VERSION 5.8 ;
BUSBITCHARS "[]" ;
DIVIDERCHAR "/" ;
UNITS
    DATABASE MICRONS 1000 ;
END UNITS

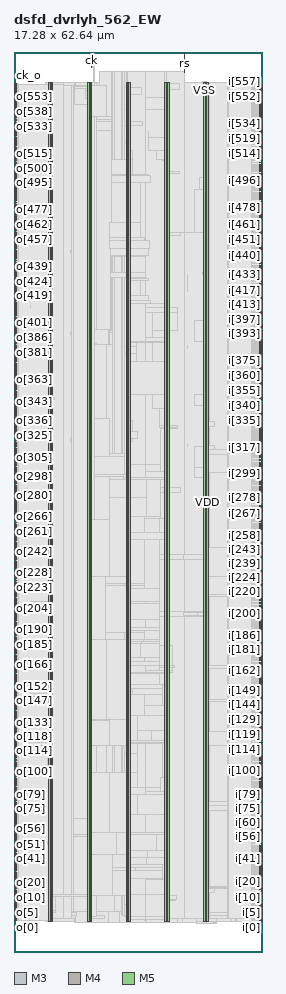
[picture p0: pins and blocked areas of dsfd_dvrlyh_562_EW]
MACRO dsfd_dvrlyh_562_EW
  FOREIGN dsfd_dvrlyh_562_EW 0 0 ;
  CLASS BLOCK ;
  SIZE 17.28 BY 62.64 ;
  PIN ck
    DIRECTION INPUT ;
    USE SIGNAL ;
    PORT
      LAYER M3 ;
        RECT  5.4 62.496 5.418 62.64 ;
    END
    PORT
      LAYER M3 ;
        RECT  5.4 61.579 5.418 62.508 ;
    END
  END ck
  PIN ck_o
    DIRECTION OUTPUT ;
    USE SIGNAL ;
    PORT
      LAYER M4 ;
        RECT  0 60.432 0.192 60.456 ;
    END
  END ck_o
  PIN i[0]
    DIRECTION INPUT ;
    USE SIGNAL ;
    PORT
      LAYER M4 ;
        RECT  17.088 2.208 17.28 2.232 ;
    END
  END i[0]
  PIN i[100]
    DIRECTION INPUT ;
    USE SIGNAL ;
    PORT
      LAYER M4 ;
        RECT  17.088 12.624 17.28 12.648 ;
    END
  END i[100]
  PIN i[101]
    DIRECTION INPUT ;
    USE SIGNAL ;
    PORT
      LAYER M4 ;
        RECT  17.088 12.72 17.28 12.744 ;
    END
  END i[101]
  PIN i[102]
    DIRECTION INPUT ;
    USE SIGNAL ;
    PORT
      LAYER M4 ;
        RECT  17.088 12.816 17.28 12.84 ;
    END
  END i[102]
  PIN i[103]
    DIRECTION INPUT ;
    USE SIGNAL ;
    PORT
      LAYER M4 ;
        RECT  17.088 12.912 17.28 12.936 ;
    END
  END i[103]
  PIN i[104]
    DIRECTION INPUT ;
    USE SIGNAL ;
    PORT
      LAYER M4 ;
        RECT  17.088 13.008 17.28 13.032 ;
    END
  END i[104]
  PIN i[105]
    DIRECTION INPUT ;
    USE SIGNAL ;
    PORT
      LAYER M4 ;
        RECT  17.088 13.104 17.28 13.128 ;
    END
  END i[105]
  PIN i[106]
    DIRECTION INPUT ;
    USE SIGNAL ;
    PORT
      LAYER M4 ;
        RECT  17.088 13.2 17.28 13.224 ;
    END
  END i[106]
  PIN i[107]
    DIRECTION INPUT ;
    USE SIGNAL ;
    PORT
      LAYER M4 ;
        RECT  17.088 13.344 17.28 13.368 ;
    END
  END i[107]
  PIN i[108]
    DIRECTION INPUT ;
    USE SIGNAL ;
    PORT
      LAYER M4 ;
        RECT  17.088 13.44 17.28 13.464 ;
    END
  END i[108]
  PIN i[109]
    DIRECTION INPUT ;
    USE SIGNAL ;
    PORT
      LAYER M4 ;
        RECT  17.088 13.536 17.28 13.56 ;
    END
  END i[109]
  PIN i[10]
    DIRECTION INPUT ;
    USE SIGNAL ;
    PORT
      LAYER M4 ;
        RECT  17.088 3.264 17.28 3.288 ;
    END
  END i[10]
  PIN i[110]
    DIRECTION INPUT ;
    USE SIGNAL ;
    PORT
      LAYER M4 ;
        RECT  17.088 13.632 17.28 13.656 ;
    END
  END i[110]
  PIN i[111]
    DIRECTION INPUT ;
    USE SIGNAL ;
    PORT
      LAYER M4 ;
        RECT  17.088 13.728 17.28 13.752 ;
    END
  END i[111]
  PIN i[112]
    DIRECTION INPUT ;
    USE SIGNAL ;
    PORT
      LAYER M4 ;
        RECT  17.088 13.824 17.28 13.848 ;
    END
  END i[112]
  PIN i[113]
    DIRECTION INPUT ;
    USE SIGNAL ;
    PORT
      LAYER M4 ;
        RECT  17.088 13.968 17.28 13.992 ;
    END
  END i[113]
  PIN i[114]
    DIRECTION INPUT ;
    USE SIGNAL ;
    PORT
      LAYER M4 ;
        RECT  17.088 14.064 17.28 14.088 ;
    END
  END i[114]
  PIN i[115]
    DIRECTION INPUT ;
    USE SIGNAL ;
    PORT
      LAYER M4 ;
        RECT  17.088 14.16 17.28 14.184 ;
    END
  END i[115]
  PIN i[116]
    DIRECTION INPUT ;
    USE SIGNAL ;
    PORT
      LAYER M4 ;
        RECT  17.088 14.256 17.28 14.28 ;
    END
  END i[116]
  PIN i[117]
    DIRECTION INPUT ;
    USE SIGNAL ;
    PORT
      LAYER M4 ;
        RECT  17.088 14.352 17.28 14.376 ;
    END
  END i[117]
  PIN i[118]
    DIRECTION INPUT ;
    USE SIGNAL ;
    PORT
      LAYER M4 ;
        RECT  17.088 14.448 17.28 14.472 ;
    END
  END i[118]
  PIN i[119]
    DIRECTION INPUT ;
    USE SIGNAL ;
    PORT
      LAYER M4 ;
        RECT  17.088 14.592 17.28 14.616 ;
    END
  END i[119]
  PIN i[11]
    DIRECTION INPUT ;
    USE SIGNAL ;
    PORT
      LAYER M4 ;
        RECT  17.088 3.36 17.28 3.384 ;
    END
  END i[11]
  PIN i[120]
    DIRECTION INPUT ;
    USE SIGNAL ;
    PORT
      LAYER M4 ;
        RECT  17.088 14.688 17.28 14.712 ;
    END
  END i[120]
  PIN i[121]
    DIRECTION INPUT ;
    USE SIGNAL ;
    PORT
      LAYER M4 ;
        RECT  17.088 14.784 17.28 14.808 ;
    END
  END i[121]
  PIN i[122]
    DIRECTION INPUT ;
    USE SIGNAL ;
    PORT
      LAYER M4 ;
        RECT  17.088 14.88 17.28 14.904 ;
    END
  END i[122]
  PIN i[123]
    DIRECTION INPUT ;
    USE SIGNAL ;
    PORT
      LAYER M4 ;
        RECT  17.088 14.976 17.28 15 ;
    END
  END i[123]
  PIN i[124]
    DIRECTION INPUT ;
    USE SIGNAL ;
    PORT
      LAYER M4 ;
        RECT  17.088 15.072 17.28 15.096 ;
    END
  END i[124]
  PIN i[125]
    DIRECTION INPUT ;
    USE SIGNAL ;
    PORT
      LAYER M4 ;
        RECT  17.088 15.216 17.28 15.24 ;
    END
  END i[125]
  PIN i[126]
    DIRECTION INPUT ;
    USE SIGNAL ;
    PORT
      LAYER M4 ;
        RECT  17.088 15.312 17.28 15.336 ;
    END
  END i[126]
  PIN i[127]
    DIRECTION INPUT ;
    USE SIGNAL ;
    PORT
      LAYER M4 ;
        RECT  17.088 15.408 17.28 15.432 ;
    END
  END i[127]
  PIN i[128]
    DIRECTION INPUT ;
    USE SIGNAL ;
    PORT
      LAYER M4 ;
        RECT  17.088 15.504 17.28 15.528 ;
    END
  END i[128]
  PIN i[129]
    DIRECTION INPUT ;
    USE SIGNAL ;
    PORT
      LAYER M4 ;
        RECT  17.088 15.6 17.28 15.624 ;
    END
  END i[129]
  PIN i[12]
    DIRECTION INPUT ;
    USE SIGNAL ;
    PORT
      LAYER M4 ;
        RECT  17.088 3.456 17.28 3.48 ;
    END
  END i[12]
  PIN i[130]
    DIRECTION INPUT ;
    USE SIGNAL ;
    PORT
      LAYER M4 ;
        RECT  17.088 15.696 17.28 15.72 ;
    END
  END i[130]
  PIN i[131]
    DIRECTION INPUT ;
    USE SIGNAL ;
    PORT
      LAYER M4 ;
        RECT  17.088 15.84 17.28 15.864 ;
    END
  END i[131]
  PIN i[132]
    DIRECTION INPUT ;
    USE SIGNAL ;
    PORT
      LAYER M4 ;
        RECT  17.088 15.936 17.28 15.96 ;
    END
  END i[132]
  PIN i[133]
    DIRECTION INPUT ;
    USE SIGNAL ;
    PORT
      LAYER M4 ;
        RECT  17.088 16.032 17.28 16.056 ;
    END
  END i[133]
  PIN i[134]
    DIRECTION INPUT ;
    USE SIGNAL ;
    PORT
      LAYER M4 ;
        RECT  17.088 16.128 17.28 16.152 ;
    END
  END i[134]
  PIN i[135]
    DIRECTION INPUT ;
    USE SIGNAL ;
    PORT
      LAYER M4 ;
        RECT  17.088 16.224 17.28 16.248 ;
    END
  END i[135]
  PIN i[136]
    DIRECTION INPUT ;
    USE SIGNAL ;
    PORT
      LAYER M4 ;
        RECT  17.088 16.32 17.28 16.344 ;
    END
  END i[136]
  PIN i[137]
    DIRECTION INPUT ;
    USE SIGNAL ;
    PORT
      LAYER M4 ;
        RECT  17.088 16.464 17.28 16.488 ;
    END
  END i[137]
  PIN i[138]
    DIRECTION INPUT ;
    USE SIGNAL ;
    PORT
      LAYER M4 ;
        RECT  17.088 16.56 17.28 16.584 ;
    END
  END i[138]
  PIN i[139]
    DIRECTION INPUT ;
    USE SIGNAL ;
    PORT
      LAYER M4 ;
        RECT  17.088 16.656 17.28 16.68 ;
    END
  END i[139]
  PIN i[13]
    DIRECTION INPUT ;
    USE SIGNAL ;
    PORT
      LAYER M4 ;
        RECT  17.088 3.552 17.28 3.576 ;
    END
  END i[13]
  PIN i[140]
    DIRECTION INPUT ;
    USE SIGNAL ;
    PORT
      LAYER M4 ;
        RECT  17.088 16.752 17.28 16.776 ;
    END
  END i[140]
  PIN i[141]
    DIRECTION INPUT ;
    USE SIGNAL ;
    PORT
      LAYER M4 ;
        RECT  17.088 16.848 17.28 16.872 ;
    END
  END i[141]
  PIN i[142]
    DIRECTION INPUT ;
    USE SIGNAL ;
    PORT
      LAYER M4 ;
        RECT  17.088 16.944 17.28 16.968 ;
    END
  END i[142]
  PIN i[143]
    DIRECTION INPUT ;
    USE SIGNAL ;
    PORT
      LAYER M4 ;
        RECT  17.088 17.04 17.28 17.064 ;
    END
  END i[143]
  PIN i[144]
    DIRECTION INPUT ;
    USE SIGNAL ;
    PORT
      LAYER M4 ;
        RECT  17.088 17.184 17.28 17.208 ;
    END
  END i[144]
  PIN i[145]
    DIRECTION INPUT ;
    USE SIGNAL ;
    PORT
      LAYER M4 ;
        RECT  17.088 17.28 17.28 17.304 ;
    END
  END i[145]
  PIN i[146]
    DIRECTION INPUT ;
    USE SIGNAL ;
    PORT
      LAYER M4 ;
        RECT  17.088 17.376 17.28 17.4 ;
    END
  END i[146]
  PIN i[147]
    DIRECTION INPUT ;
    USE SIGNAL ;
    PORT
      LAYER M4 ;
        RECT  17.088 17.472 17.28 17.496 ;
    END
  END i[147]
  PIN i[148]
    DIRECTION INPUT ;
    USE SIGNAL ;
    PORT
      LAYER M4 ;
        RECT  17.088 17.568 17.28 17.592 ;
    END
  END i[148]
  PIN i[149]
    DIRECTION INPUT ;
    USE SIGNAL ;
    PORT
      LAYER M4 ;
        RECT  17.088 17.664 17.28 17.688 ;
    END
  END i[149]
  PIN i[14]
    DIRECTION INPUT ;
    USE SIGNAL ;
    PORT
      LAYER M4 ;
        RECT  17.088 3.696 17.28 3.72 ;
    END
  END i[14]
  PIN i[150]
    DIRECTION INPUT ;
    USE SIGNAL ;
    PORT
      LAYER M4 ;
        RECT  17.088 17.808 17.28 17.832 ;
    END
  END i[150]
  PIN i[151]
    DIRECTION INPUT ;
    USE SIGNAL ;
    PORT
      LAYER M4 ;
        RECT  17.088 17.904 17.28 17.928 ;
    END
  END i[151]
  PIN i[152]
    DIRECTION INPUT ;
    USE SIGNAL ;
    PORT
      LAYER M4 ;
        RECT  17.088 18 17.28 18.024 ;
    END
  END i[152]
  PIN i[153]
    DIRECTION INPUT ;
    USE SIGNAL ;
    PORT
      LAYER M4 ;
        RECT  17.088 18.096 17.28 18.12 ;
    END
  END i[153]
  PIN i[154]
    DIRECTION INPUT ;
    USE SIGNAL ;
    PORT
      LAYER M4 ;
        RECT  17.088 18.192 17.28 18.216 ;
    END
  END i[154]
  PIN i[155]
    DIRECTION INPUT ;
    USE SIGNAL ;
    PORT
      LAYER M4 ;
        RECT  17.088 18.288 17.28 18.312 ;
    END
  END i[155]
  PIN i[156]
    DIRECTION INPUT ;
    USE SIGNAL ;
    PORT
      LAYER M4 ;
        RECT  17.088 18.432 17.28 18.456 ;
    END
  END i[156]
  PIN i[157]
    DIRECTION INPUT ;
    USE SIGNAL ;
    PORT
      LAYER M4 ;
        RECT  17.088 18.528 17.28 18.552 ;
    END
  END i[157]
  PIN i[158]
    DIRECTION INPUT ;
    USE SIGNAL ;
    PORT
      LAYER M4 ;
        RECT  17.088 18.624 17.28 18.648 ;
    END
  END i[158]
  PIN i[159]
    DIRECTION INPUT ;
    USE SIGNAL ;
    PORT
      LAYER M4 ;
        RECT  17.088 18.72 17.28 18.744 ;
    END
  END i[159]
  PIN i[15]
    DIRECTION INPUT ;
    USE SIGNAL ;
    PORT
      LAYER M4 ;
        RECT  17.088 3.792 17.28 3.816 ;
    END
  END i[15]
  PIN i[160]
    DIRECTION INPUT ;
    USE SIGNAL ;
    PORT
      LAYER M4 ;
        RECT  17.088 18.816 17.28 18.84 ;
    END
  END i[160]
  PIN i[161]
    DIRECTION INPUT ;
    USE SIGNAL ;
    PORT
      LAYER M4 ;
        RECT  17.088 18.912 17.28 18.936 ;
    END
  END i[161]
  PIN i[162]
    DIRECTION INPUT ;
    USE SIGNAL ;
    PORT
      LAYER M4 ;
        RECT  17.088 19.056 17.28 19.08 ;
    END
  END i[162]
  PIN i[163]
    DIRECTION INPUT ;
    USE SIGNAL ;
    PORT
      LAYER M4 ;
        RECT  17.088 19.152 17.28 19.176 ;
    END
  END i[163]
  PIN i[164]
    DIRECTION INPUT ;
    USE SIGNAL ;
    PORT
      LAYER M4 ;
        RECT  17.088 19.248 17.28 19.272 ;
    END
  END i[164]
  PIN i[165]
    DIRECTION INPUT ;
    USE SIGNAL ;
    PORT
      LAYER M4 ;
        RECT  17.088 19.344 17.28 19.368 ;
    END
  END i[165]
  PIN i[166]
    DIRECTION INPUT ;
    USE SIGNAL ;
    PORT
      LAYER M4 ;
        RECT  17.088 19.44 17.28 19.464 ;
    END
  END i[166]
  PIN i[167]
    DIRECTION INPUT ;
    USE SIGNAL ;
    PORT
      LAYER M4 ;
        RECT  17.088 19.536 17.28 19.56 ;
    END
  END i[167]
  PIN i[168]
    DIRECTION INPUT ;
    USE SIGNAL ;
    PORT
      LAYER M4 ;
        RECT  17.088 19.68 17.28 19.704 ;
    END
  END i[168]
  PIN i[169]
    DIRECTION INPUT ;
    USE SIGNAL ;
    PORT
      LAYER M4 ;
        RECT  17.088 19.776 17.28 19.8 ;
    END
  END i[169]
  PIN i[16]
    DIRECTION INPUT ;
    USE SIGNAL ;
    PORT
      LAYER M4 ;
        RECT  17.088 3.888 17.28 3.912 ;
    END
  END i[16]
  PIN i[170]
    DIRECTION INPUT ;
    USE SIGNAL ;
    PORT
      LAYER M4 ;
        RECT  17.088 19.872 17.28 19.896 ;
    END
  END i[170]
  PIN i[171]
    DIRECTION INPUT ;
    USE SIGNAL ;
    PORT
      LAYER M4 ;
        RECT  17.088 19.968 17.28 19.992 ;
    END
  END i[171]
  PIN i[172]
    DIRECTION INPUT ;
    USE SIGNAL ;
    PORT
      LAYER M4 ;
        RECT  17.088 20.064 17.28 20.088 ;
    END
  END i[172]
  PIN i[173]
    DIRECTION INPUT ;
    USE SIGNAL ;
    PORT
      LAYER M4 ;
        RECT  17.088 20.16 17.28 20.184 ;
    END
  END i[173]
  PIN i[174]
    DIRECTION INPUT ;
    USE SIGNAL ;
    PORT
      LAYER M4 ;
        RECT  17.088 20.304 17.28 20.328 ;
    END
  END i[174]
  PIN i[175]
    DIRECTION INPUT ;
    USE SIGNAL ;
    PORT
      LAYER M4 ;
        RECT  17.088 20.4 17.28 20.424 ;
    END
  END i[175]
  PIN i[176]
    DIRECTION INPUT ;
    USE SIGNAL ;
    PORT
      LAYER M4 ;
        RECT  17.088 20.496 17.28 20.52 ;
    END
  END i[176]
  PIN i[177]
    DIRECTION INPUT ;
    USE SIGNAL ;
    PORT
      LAYER M4 ;
        RECT  17.088 20.592 17.28 20.616 ;
    END
  END i[177]
  PIN i[178]
    DIRECTION INPUT ;
    USE SIGNAL ;
    PORT
      LAYER M4 ;
        RECT  17.088 20.688 17.28 20.712 ;
    END
  END i[178]
  PIN i[179]
    DIRECTION INPUT ;
    USE SIGNAL ;
    PORT
      LAYER M4 ;
        RECT  17.088 20.784 17.28 20.808 ;
    END
  END i[179]
  PIN i[17]
    DIRECTION INPUT ;
    USE SIGNAL ;
    PORT
      LAYER M4 ;
        RECT  17.088 3.984 17.28 4.008 ;
    END
  END i[17]
  PIN i[180]
    DIRECTION INPUT ;
    USE SIGNAL ;
    PORT
      LAYER M4 ;
        RECT  17.088 20.88 17.28 20.904 ;
    END
  END i[180]
  PIN i[181]
    DIRECTION INPUT ;
    USE SIGNAL ;
    PORT
      LAYER M4 ;
        RECT  17.088 21.024 17.28 21.048 ;
    END
  END i[181]
  PIN i[182]
    DIRECTION INPUT ;
    USE SIGNAL ;
    PORT
      LAYER M4 ;
        RECT  17.088 21.12 17.28 21.144 ;
    END
  END i[182]
  PIN i[183]
    DIRECTION INPUT ;
    USE SIGNAL ;
    PORT
      LAYER M4 ;
        RECT  17.088 21.216 17.28 21.24 ;
    END
  END i[183]
  PIN i[184]
    DIRECTION INPUT ;
    USE SIGNAL ;
    PORT
      LAYER M4 ;
        RECT  17.088 21.312 17.28 21.336 ;
    END
  END i[184]
  PIN i[185]
    DIRECTION INPUT ;
    USE SIGNAL ;
    PORT
      LAYER M4 ;
        RECT  17.088 21.408 17.28 21.432 ;
    END
  END i[185]
  PIN i[186]
    DIRECTION INPUT ;
    USE SIGNAL ;
    PORT
      LAYER M4 ;
        RECT  17.088 21.504 17.28 21.528 ;
    END
  END i[186]
  PIN i[187]
    DIRECTION INPUT ;
    USE SIGNAL ;
    PORT
      LAYER M4 ;
        RECT  17.088 21.648 17.28 21.672 ;
    END
  END i[187]
  PIN i[188]
    DIRECTION INPUT ;
    USE SIGNAL ;
    PORT
      LAYER M4 ;
        RECT  17.088 21.744 17.28 21.768 ;
    END
  END i[188]
  PIN i[189]
    DIRECTION INPUT ;
    USE SIGNAL ;
    PORT
      LAYER M4 ;
        RECT  17.088 21.84 17.28 21.864 ;
    END
  END i[189]
  PIN i[18]
    DIRECTION INPUT ;
    USE SIGNAL ;
    PORT
      LAYER M4 ;
        RECT  17.088 4.08 17.28 4.104 ;
    END
  END i[18]
  PIN i[190]
    DIRECTION INPUT ;
    USE SIGNAL ;
    PORT
      LAYER M4 ;
        RECT  17.088 21.936 17.28 21.96 ;
    END
  END i[190]
  PIN i[191]
    DIRECTION INPUT ;
    USE SIGNAL ;
    PORT
      LAYER M4 ;
        RECT  17.088 22.032 17.28 22.056 ;
    END
  END i[191]
  PIN i[192]
    DIRECTION INPUT ;
    USE SIGNAL ;
    PORT
      LAYER M4 ;
        RECT  17.088 22.128 17.28 22.152 ;
    END
  END i[192]
  PIN i[193]
    DIRECTION INPUT ;
    USE SIGNAL ;
    PORT
      LAYER M4 ;
        RECT  17.088 22.272 17.28 22.296 ;
    END
  END i[193]
  PIN i[194]
    DIRECTION INPUT ;
    USE SIGNAL ;
    PORT
      LAYER M4 ;
        RECT  17.088 22.368 17.28 22.392 ;
    END
  END i[194]
  PIN i[195]
    DIRECTION INPUT ;
    USE SIGNAL ;
    PORT
      LAYER M4 ;
        RECT  17.088 22.464 17.28 22.488 ;
    END
  END i[195]
  PIN i[196]
    DIRECTION INPUT ;
    USE SIGNAL ;
    PORT
      LAYER M4 ;
        RECT  17.088 22.56 17.28 22.584 ;
    END
  END i[196]
  PIN i[197]
    DIRECTION INPUT ;
    USE SIGNAL ;
    PORT
      LAYER M4 ;
        RECT  17.088 22.656 17.28 22.68 ;
    END
  END i[197]
  PIN i[198]
    DIRECTION INPUT ;
    USE SIGNAL ;
    PORT
      LAYER M4 ;
        RECT  17.088 22.752 17.28 22.776 ;
    END
  END i[198]
  PIN i[199]
    DIRECTION INPUT ;
    USE SIGNAL ;
    PORT
      LAYER M4 ;
        RECT  17.088 22.896 17.28 22.92 ;
    END
  END i[199]
  PIN i[19]
    DIRECTION INPUT ;
    USE SIGNAL ;
    PORT
      LAYER M4 ;
        RECT  17.088 4.176 17.28 4.2 ;
    END
  END i[19]
  PIN i[1]
    DIRECTION INPUT ;
    USE SIGNAL ;
    PORT
      LAYER M4 ;
        RECT  17.088 2.304 17.28 2.328 ;
    END
  END i[1]
  PIN i[200]
    DIRECTION INPUT ;
    USE SIGNAL ;
    PORT
      LAYER M4 ;
        RECT  17.088 22.992 17.28 23.016 ;
    END
  END i[200]
  PIN i[201]
    DIRECTION INPUT ;
    USE SIGNAL ;
    PORT
      LAYER M4 ;
        RECT  17.088 23.088 17.28 23.112 ;
    END
  END i[201]
  PIN i[202]
    DIRECTION INPUT ;
    USE SIGNAL ;
    PORT
      LAYER M4 ;
        RECT  17.088 23.184 17.28 23.208 ;
    END
  END i[202]
  PIN i[203]
    DIRECTION INPUT ;
    USE SIGNAL ;
    PORT
      LAYER M4 ;
        RECT  17.088 23.28 17.28 23.304 ;
    END
  END i[203]
  PIN i[204]
    DIRECTION INPUT ;
    USE SIGNAL ;
    PORT
      LAYER M4 ;
        RECT  17.088 23.376 17.28 23.4 ;
    END
  END i[204]
  PIN i[205]
    DIRECTION INPUT ;
    USE SIGNAL ;
    PORT
      LAYER M4 ;
        RECT  17.088 23.52 17.28 23.544 ;
    END
  END i[205]
  PIN i[206]
    DIRECTION INPUT ;
    USE SIGNAL ;
    PORT
      LAYER M4 ;
        RECT  17.088 23.616 17.28 23.64 ;
    END
  END i[206]
  PIN i[207]
    DIRECTION INPUT ;
    USE SIGNAL ;
    PORT
      LAYER M4 ;
        RECT  17.088 23.712 17.28 23.736 ;
    END
  END i[207]
  PIN i[208]
    DIRECTION INPUT ;
    USE SIGNAL ;
    PORT
      LAYER M4 ;
        RECT  17.088 23.808 17.28 23.832 ;
    END
  END i[208]
  PIN i[209]
    DIRECTION INPUT ;
    USE SIGNAL ;
    PORT
      LAYER M4 ;
        RECT  17.088 23.904 17.28 23.928 ;
    END
  END i[209]
  PIN i[20]
    DIRECTION INPUT ;
    USE SIGNAL ;
    PORT
      LAYER M4 ;
        RECT  17.088 4.32 17.28 4.344 ;
    END
  END i[20]
  PIN i[210]
    DIRECTION INPUT ;
    USE SIGNAL ;
    PORT
      LAYER M4 ;
        RECT  17.088 24 17.28 24.024 ;
    END
  END i[210]
  PIN i[211]
    DIRECTION INPUT ;
    USE SIGNAL ;
    PORT
      LAYER M4 ;
        RECT  17.088 24.096 17.28 24.12 ;
    END
  END i[211]
  PIN i[212]
    DIRECTION INPUT ;
    USE SIGNAL ;
    PORT
      LAYER M4 ;
        RECT  17.088 24.24 17.28 24.264 ;
    END
  END i[212]
  PIN i[213]
    DIRECTION INPUT ;
    USE SIGNAL ;
    PORT
      LAYER M4 ;
        RECT  17.088 24.336 17.28 24.36 ;
    END
  END i[213]
  PIN i[214]
    DIRECTION INPUT ;
    USE SIGNAL ;
    PORT
      LAYER M4 ;
        RECT  17.088 24.432 17.28 24.456 ;
    END
  END i[214]
  PIN i[215]
    DIRECTION INPUT ;
    USE SIGNAL ;
    PORT
      LAYER M4 ;
        RECT  17.088 24.528 17.28 24.552 ;
    END
  END i[215]
  PIN i[216]
    DIRECTION INPUT ;
    USE SIGNAL ;
    PORT
      LAYER M4 ;
        RECT  17.088 24.624 17.28 24.648 ;
    END
  END i[216]
  PIN i[217]
    DIRECTION INPUT ;
    USE SIGNAL ;
    PORT
      LAYER M4 ;
        RECT  17.088 24.72 17.28 24.744 ;
    END
  END i[217]
  PIN i[218]
    DIRECTION INPUT ;
    USE SIGNAL ;
    PORT
      LAYER M4 ;
        RECT  17.088 24.864 17.28 24.888 ;
    END
  END i[218]
  PIN i[219]
    DIRECTION INPUT ;
    USE SIGNAL ;
    PORT
      LAYER M4 ;
        RECT  17.088 24.96 17.28 24.984 ;
    END
  END i[219]
  PIN i[21]
    DIRECTION INPUT ;
    USE SIGNAL ;
    PORT
      LAYER M4 ;
        RECT  17.088 4.416 17.28 4.44 ;
    END
  END i[21]
  PIN i[220]
    DIRECTION INPUT ;
    USE SIGNAL ;
    PORT
      LAYER M4 ;
        RECT  17.088 25.056 17.28 25.08 ;
    END
  END i[220]
  PIN i[221]
    DIRECTION INPUT ;
    USE SIGNAL ;
    PORT
      LAYER M4 ;
        RECT  17.088 25.152 17.28 25.176 ;
    END
  END i[221]
  PIN i[222]
    DIRECTION INPUT ;
    USE SIGNAL ;
    PORT
      LAYER M4 ;
        RECT  17.088 25.248 17.28 25.272 ;
    END
  END i[222]
  PIN i[223]
    DIRECTION INPUT ;
    USE SIGNAL ;
    PORT
      LAYER M4 ;
        RECT  17.088 25.344 17.28 25.368 ;
    END
  END i[223]
  PIN i[224]
    DIRECTION INPUT ;
    USE SIGNAL ;
    PORT
      LAYER M4 ;
        RECT  17.088 25.488 17.28 25.512 ;
    END
  END i[224]
  PIN i[225]
    DIRECTION INPUT ;
    USE SIGNAL ;
    PORT
      LAYER M4 ;
        RECT  17.088 25.584 17.28 25.608 ;
    END
  END i[225]
  PIN i[226]
    DIRECTION INPUT ;
    USE SIGNAL ;
    PORT
      LAYER M4 ;
        RECT  17.088 25.68 17.28 25.704 ;
    END
  END i[226]
  PIN i[227]
    DIRECTION INPUT ;
    USE SIGNAL ;
    PORT
      LAYER M4 ;
        RECT  17.088 25.776 17.28 25.8 ;
    END
  END i[227]
  PIN i[228]
    DIRECTION INPUT ;
    USE SIGNAL ;
    PORT
      LAYER M4 ;
        RECT  17.088 25.872 17.28 25.896 ;
    END
  END i[228]
  PIN i[229]
    DIRECTION INPUT ;
    USE SIGNAL ;
    PORT
      LAYER M4 ;
        RECT  17.088 25.968 17.28 25.992 ;
    END
  END i[229]
  PIN i[22]
    DIRECTION INPUT ;
    USE SIGNAL ;
    PORT
      LAYER M4 ;
        RECT  17.088 4.512 17.28 4.536 ;
    END
  END i[22]
  PIN i[230]
    DIRECTION INPUT ;
    USE SIGNAL ;
    PORT
      LAYER M4 ;
        RECT  17.088 26.112 17.28 26.136 ;
    END
  END i[230]
  PIN i[231]
    DIRECTION INPUT ;
    USE SIGNAL ;
    PORT
      LAYER M4 ;
        RECT  17.088 26.208 17.28 26.232 ;
    END
  END i[231]
  PIN i[232]
    DIRECTION INPUT ;
    USE SIGNAL ;
    PORT
      LAYER M4 ;
        RECT  17.088 26.304 17.28 26.328 ;
    END
  END i[232]
  PIN i[233]
    DIRECTION INPUT ;
    USE SIGNAL ;
    PORT
      LAYER M4 ;
        RECT  17.088 26.4 17.28 26.424 ;
    END
  END i[233]
  PIN i[234]
    DIRECTION INPUT ;
    USE SIGNAL ;
    PORT
      LAYER M4 ;
        RECT  17.088 26.496 17.28 26.52 ;
    END
  END i[234]
  PIN i[235]
    DIRECTION INPUT ;
    USE SIGNAL ;
    PORT
      LAYER M4 ;
        RECT  17.088 26.592 17.28 26.616 ;
    END
  END i[235]
  PIN i[236]
    DIRECTION INPUT ;
    USE SIGNAL ;
    PORT
      LAYER M4 ;
        RECT  17.088 26.736 17.28 26.76 ;
    END
  END i[236]
  PIN i[237]
    DIRECTION INPUT ;
    USE SIGNAL ;
    PORT
      LAYER M4 ;
        RECT  17.088 26.832 17.28 26.856 ;
    END
  END i[237]
  PIN i[238]
    DIRECTION INPUT ;
    USE SIGNAL ;
    PORT
      LAYER M4 ;
        RECT  17.088 26.928 17.28 26.952 ;
    END
  END i[238]
  PIN i[239]
    DIRECTION INPUT ;
    USE SIGNAL ;
    PORT
      LAYER M4 ;
        RECT  17.088 27.024 17.28 27.048 ;
    END
  END i[239]
  PIN i[23]
    DIRECTION INPUT ;
    USE SIGNAL ;
    PORT
      LAYER M4 ;
        RECT  17.088 4.608 17.28 4.632 ;
    END
  END i[23]
  PIN i[240]
    DIRECTION INPUT ;
    USE SIGNAL ;
    PORT
      LAYER M4 ;
        RECT  17.088 27.12 17.28 27.144 ;
    END
  END i[240]
  PIN i[241]
    DIRECTION INPUT ;
    USE SIGNAL ;
    PORT
      LAYER M4 ;
        RECT  17.088 27.216 17.28 27.24 ;
    END
  END i[241]
  PIN i[242]
    DIRECTION INPUT ;
    USE SIGNAL ;
    PORT
      LAYER M4 ;
        RECT  17.088 27.36 17.28 27.384 ;
    END
  END i[242]
  PIN i[243]
    DIRECTION INPUT ;
    USE SIGNAL ;
    PORT
      LAYER M4 ;
        RECT  17.088 27.456 17.28 27.48 ;
    END
  END i[243]
  PIN i[244]
    DIRECTION INPUT ;
    USE SIGNAL ;
    PORT
      LAYER M4 ;
        RECT  17.088 27.552 17.28 27.576 ;
    END
  END i[244]
  PIN i[245]
    DIRECTION INPUT ;
    USE SIGNAL ;
    PORT
      LAYER M4 ;
        RECT  17.088 27.648 17.28 27.672 ;
    END
  END i[245]
  PIN i[246]
    DIRECTION INPUT ;
    USE SIGNAL ;
    PORT
      LAYER M4 ;
        RECT  17.088 27.744 17.28 27.768 ;
    END
  END i[246]
  PIN i[247]
    DIRECTION INPUT ;
    USE SIGNAL ;
    PORT
      LAYER M4 ;
        RECT  17.088 27.84 17.28 27.864 ;
    END
  END i[247]
  PIN i[248]
    DIRECTION INPUT ;
    USE SIGNAL ;
    PORT
      LAYER M4 ;
        RECT  17.088 27.936 17.28 27.96 ;
    END
  END i[248]
  PIN i[249]
    DIRECTION INPUT ;
    USE SIGNAL ;
    PORT
      LAYER M4 ;
        RECT  17.088 28.08 17.28 28.104 ;
    END
  END i[249]
  PIN i[24]
    DIRECTION INPUT ;
    USE SIGNAL ;
    PORT
      LAYER M4 ;
        RECT  17.088 4.704 17.28 4.728 ;
    END
  END i[24]
  PIN i[250]
    DIRECTION INPUT ;
    USE SIGNAL ;
    PORT
      LAYER M4 ;
        RECT  17.088 28.176 17.28 28.2 ;
    END
  END i[250]
  PIN i[251]
    DIRECTION INPUT ;
    USE SIGNAL ;
    PORT
      LAYER M4 ;
        RECT  17.088 28.272 17.28 28.296 ;
    END
  END i[251]
  PIN i[252]
    DIRECTION INPUT ;
    USE SIGNAL ;
    PORT
      LAYER M4 ;
        RECT  17.088 28.368 17.28 28.392 ;
    END
  END i[252]
  PIN i[253]
    DIRECTION INPUT ;
    USE SIGNAL ;
    PORT
      LAYER M4 ;
        RECT  17.088 28.464 17.28 28.488 ;
    END
  END i[253]
  PIN i[254]
    DIRECTION INPUT ;
    USE SIGNAL ;
    PORT
      LAYER M4 ;
        RECT  17.088 28.56 17.28 28.584 ;
    END
  END i[254]
  PIN i[255]
    DIRECTION INPUT ;
    USE SIGNAL ;
    PORT
      LAYER M4 ;
        RECT  17.088 28.704 17.28 28.728 ;
    END
  END i[255]
  PIN i[256]
    DIRECTION INPUT ;
    USE SIGNAL ;
    PORT
      LAYER M4 ;
        RECT  17.088 28.8 17.28 28.824 ;
    END
  END i[256]
  PIN i[257]
    DIRECTION INPUT ;
    USE SIGNAL ;
    PORT
      LAYER M4 ;
        RECT  17.088 28.896 17.28 28.92 ;
    END
  END i[257]
  PIN i[258]
    DIRECTION INPUT ;
    USE SIGNAL ;
    PORT
      LAYER M4 ;
        RECT  17.088 28.992 17.28 29.016 ;
    END
  END i[258]
  PIN i[259]
    DIRECTION INPUT ;
    USE SIGNAL ;
    PORT
      LAYER M4 ;
        RECT  17.088 29.088 17.28 29.112 ;
    END
  END i[259]
  PIN i[25]
    DIRECTION INPUT ;
    USE SIGNAL ;
    PORT
      LAYER M4 ;
        RECT  17.088 4.8 17.28 4.824 ;
    END
  END i[25]
  PIN i[260]
    DIRECTION INPUT ;
    USE SIGNAL ;
    PORT
      LAYER M4 ;
        RECT  17.088 29.184 17.28 29.208 ;
    END
  END i[260]
  PIN i[261]
    DIRECTION INPUT ;
    USE SIGNAL ;
    PORT
      LAYER M4 ;
        RECT  17.088 29.328 17.28 29.352 ;
    END
  END i[261]
  PIN i[262]
    DIRECTION INPUT ;
    USE SIGNAL ;
    PORT
      LAYER M4 ;
        RECT  17.088 29.424 17.28 29.448 ;
    END
  END i[262]
  PIN i[263]
    DIRECTION INPUT ;
    USE SIGNAL ;
    PORT
      LAYER M4 ;
        RECT  17.088 29.52 17.28 29.544 ;
    END
  END i[263]
  PIN i[264]
    DIRECTION INPUT ;
    USE SIGNAL ;
    PORT
      LAYER M4 ;
        RECT  17.088 29.616 17.28 29.64 ;
    END
  END i[264]
  PIN i[265]
    DIRECTION INPUT ;
    USE SIGNAL ;
    PORT
      LAYER M4 ;
        RECT  17.088 29.712 17.28 29.736 ;
    END
  END i[265]
  PIN i[266]
    DIRECTION INPUT ;
    USE SIGNAL ;
    PORT
      LAYER M4 ;
        RECT  17.088 29.808 17.28 29.832 ;
    END
  END i[266]
  PIN i[267]
    DIRECTION INPUT ;
    USE SIGNAL ;
    PORT
      LAYER M4 ;
        RECT  17.088 29.952 17.28 29.976 ;
    END
  END i[267]
  PIN i[268]
    DIRECTION INPUT ;
    USE SIGNAL ;
    PORT
      LAYER M4 ;
        RECT  17.088 30.048 17.28 30.072 ;
    END
  END i[268]
  PIN i[269]
    DIRECTION INPUT ;
    USE SIGNAL ;
    PORT
      LAYER M4 ;
        RECT  17.088 30.144 17.28 30.168 ;
    END
  END i[269]
  PIN i[26]
    DIRECTION INPUT ;
    USE SIGNAL ;
    PORT
      LAYER M4 ;
        RECT  17.088 4.944 17.28 4.968 ;
    END
  END i[26]
  PIN i[270]
    DIRECTION INPUT ;
    USE SIGNAL ;
    PORT
      LAYER M4 ;
        RECT  17.088 30.24 17.28 30.264 ;
    END
  END i[270]
  PIN i[271]
    DIRECTION INPUT ;
    USE SIGNAL ;
    PORT
      LAYER M4 ;
        RECT  17.088 30.336 17.28 30.36 ;
    END
  END i[271]
  PIN i[272]
    DIRECTION INPUT ;
    USE SIGNAL ;
    PORT
      LAYER M4 ;
        RECT  17.088 30.432 17.28 30.456 ;
    END
  END i[272]
  PIN i[273]
    DIRECTION INPUT ;
    USE SIGNAL ;
    PORT
      LAYER M4 ;
        RECT  17.088 30.576 17.28 30.6 ;
    END
  END i[273]
  PIN i[274]
    DIRECTION INPUT ;
    USE SIGNAL ;
    PORT
      LAYER M4 ;
        RECT  17.088 30.672 17.28 30.696 ;
    END
  END i[274]
  PIN i[275]
    DIRECTION INPUT ;
    USE SIGNAL ;
    PORT
      LAYER M4 ;
        RECT  17.088 30.768 17.28 30.792 ;
    END
  END i[275]
  PIN i[276]
    DIRECTION INPUT ;
    USE SIGNAL ;
    PORT
      LAYER M4 ;
        RECT  17.088 30.864 17.28 30.888 ;
    END
  END i[276]
  PIN i[277]
    DIRECTION INPUT ;
    USE SIGNAL ;
    PORT
      LAYER M4 ;
        RECT  17.088 30.96 17.28 30.984 ;
    END
  END i[277]
  PIN i[278]
    DIRECTION INPUT ;
    USE SIGNAL ;
    PORT
      LAYER M4 ;
        RECT  17.088 31.056 17.28 31.08 ;
    END
  END i[278]
  PIN i[279]
    DIRECTION INPUT ;
    USE SIGNAL ;
    PORT
      LAYER M4 ;
        RECT  17.088 31.2 17.28 31.224 ;
    END
  END i[279]
  PIN i[27]
    DIRECTION INPUT ;
    USE SIGNAL ;
    PORT
      LAYER M4 ;
        RECT  17.088 5.04 17.28 5.064 ;
    END
  END i[27]
  PIN i[280]
    DIRECTION INPUT ;
    USE SIGNAL ;
    PORT
      LAYER M4 ;
        RECT  17.088 31.296 17.28 31.32 ;
    END
  END i[280]
  PIN i[281]
    DIRECTION INPUT ;
    USE SIGNAL ;
    PORT
      LAYER M4 ;
        RECT  17.088 31.392 17.28 31.416 ;
    END
  END i[281]
  PIN i[282]
    DIRECTION INPUT ;
    USE SIGNAL ;
    PORT
      LAYER M4 ;
        RECT  17.088 31.488 17.28 31.512 ;
    END
  END i[282]
  PIN i[283]
    DIRECTION INPUT ;
    USE SIGNAL ;
    PORT
      LAYER M4 ;
        RECT  17.088 31.584 17.28 31.608 ;
    END
  END i[283]
  PIN i[284]
    DIRECTION INPUT ;
    USE SIGNAL ;
    PORT
      LAYER M4 ;
        RECT  17.088 31.68 17.28 31.704 ;
    END
  END i[284]
  PIN i[285]
    DIRECTION INPUT ;
    USE SIGNAL ;
    PORT
      LAYER M4 ;
        RECT  17.088 31.776 17.28 31.8 ;
    END
  END i[285]
  PIN i[286]
    DIRECTION INPUT ;
    USE SIGNAL ;
    PORT
      LAYER M4 ;
        RECT  17.088 31.92 17.28 31.944 ;
    END
  END i[286]
  PIN i[287]
    DIRECTION INPUT ;
    USE SIGNAL ;
    PORT
      LAYER M4 ;
        RECT  17.088 32.016 17.28 32.04 ;
    END
  END i[287]
  PIN i[288]
    DIRECTION INPUT ;
    USE SIGNAL ;
    PORT
      LAYER M4 ;
        RECT  17.088 32.112 17.28 32.136 ;
    END
  END i[288]
  PIN i[289]
    DIRECTION INPUT ;
    USE SIGNAL ;
    PORT
      LAYER M4 ;
        RECT  17.088 32.208 17.28 32.232 ;
    END
  END i[289]
  PIN i[28]
    DIRECTION INPUT ;
    USE SIGNAL ;
    PORT
      LAYER M4 ;
        RECT  17.088 5.136 17.28 5.16 ;
    END
  END i[28]
  PIN i[290]
    DIRECTION INPUT ;
    USE SIGNAL ;
    PORT
      LAYER M4 ;
        RECT  17.088 32.304 17.28 32.328 ;
    END
  END i[290]
  PIN i[291]
    DIRECTION INPUT ;
    USE SIGNAL ;
    PORT
      LAYER M4 ;
        RECT  17.088 32.4 17.28 32.424 ;
    END
  END i[291]
  PIN i[292]
    DIRECTION INPUT ;
    USE SIGNAL ;
    PORT
      LAYER M4 ;
        RECT  17.088 32.544 17.28 32.568 ;
    END
  END i[292]
  PIN i[293]
    DIRECTION INPUT ;
    USE SIGNAL ;
    PORT
      LAYER M4 ;
        RECT  17.088 32.64 17.28 32.664 ;
    END
  END i[293]
  PIN i[294]
    DIRECTION INPUT ;
    USE SIGNAL ;
    PORT
      LAYER M4 ;
        RECT  17.088 32.736 17.28 32.76 ;
    END
  END i[294]
  PIN i[295]
    DIRECTION INPUT ;
    USE SIGNAL ;
    PORT
      LAYER M4 ;
        RECT  17.088 32.832 17.28 32.856 ;
    END
  END i[295]
  PIN i[296]
    DIRECTION INPUT ;
    USE SIGNAL ;
    PORT
      LAYER M4 ;
        RECT  17.088 32.928 17.28 32.952 ;
    END
  END i[296]
  PIN i[297]
    DIRECTION INPUT ;
    USE SIGNAL ;
    PORT
      LAYER M4 ;
        RECT  17.088 33.024 17.28 33.048 ;
    END
  END i[297]
  PIN i[298]
    DIRECTION INPUT ;
    USE SIGNAL ;
    PORT
      LAYER M4 ;
        RECT  17.088 33.168 17.28 33.192 ;
    END
  END i[298]
  PIN i[299]
    DIRECTION INPUT ;
    USE SIGNAL ;
    PORT
      LAYER M4 ;
        RECT  17.088 33.264 17.28 33.288 ;
    END
  END i[299]
  PIN i[29]
    DIRECTION INPUT ;
    USE SIGNAL ;
    PORT
      LAYER M4 ;
        RECT  17.088 5.232 17.28 5.256 ;
    END
  END i[29]
  PIN i[2]
    DIRECTION INPUT ;
    USE SIGNAL ;
    PORT
      LAYER M4 ;
        RECT  17.088 2.448 17.28 2.472 ;
    END
  END i[2]
  PIN i[300]
    DIRECTION INPUT ;
    USE SIGNAL ;
    PORT
      LAYER M4 ;
        RECT  17.088 33.36 17.28 33.384 ;
    END
  END i[300]
  PIN i[301]
    DIRECTION INPUT ;
    USE SIGNAL ;
    PORT
      LAYER M4 ;
        RECT  17.088 33.456 17.28 33.48 ;
    END
  END i[301]
  PIN i[302]
    DIRECTION INPUT ;
    USE SIGNAL ;
    PORT
      LAYER M4 ;
        RECT  17.088 33.552 17.28 33.576 ;
    END
  END i[302]
  PIN i[303]
    DIRECTION INPUT ;
    USE SIGNAL ;
    PORT
      LAYER M4 ;
        RECT  17.088 33.648 17.28 33.672 ;
    END
  END i[303]
  PIN i[304]
    DIRECTION INPUT ;
    USE SIGNAL ;
    PORT
      LAYER M4 ;
        RECT  17.088 33.792 17.28 33.816 ;
    END
  END i[304]
  PIN i[305]
    DIRECTION INPUT ;
    USE SIGNAL ;
    PORT
      LAYER M4 ;
        RECT  17.088 33.888 17.28 33.912 ;
    END
  END i[305]
  PIN i[306]
    DIRECTION INPUT ;
    USE SIGNAL ;
    PORT
      LAYER M4 ;
        RECT  17.088 33.984 17.28 34.008 ;
    END
  END i[306]
  PIN i[307]
    DIRECTION INPUT ;
    USE SIGNAL ;
    PORT
      LAYER M4 ;
        RECT  17.088 34.08 17.28 34.104 ;
    END
  END i[307]
  PIN i[308]
    DIRECTION INPUT ;
    USE SIGNAL ;
    PORT
      LAYER M4 ;
        RECT  17.088 34.176 17.28 34.2 ;
    END
  END i[308]
  PIN i[309]
    DIRECTION INPUT ;
    USE SIGNAL ;
    PORT
      LAYER M4 ;
        RECT  17.088 34.272 17.28 34.296 ;
    END
  END i[309]
  PIN i[30]
    DIRECTION INPUT ;
    USE SIGNAL ;
    PORT
      LAYER M4 ;
        RECT  17.088 5.328 17.28 5.352 ;
    END
  END i[30]
  PIN i[310]
    DIRECTION INPUT ;
    USE SIGNAL ;
    PORT
      LAYER M4 ;
        RECT  17.088 34.416 17.28 34.44 ;
    END
  END i[310]
  PIN i[311]
    DIRECTION INPUT ;
    USE SIGNAL ;
    PORT
      LAYER M4 ;
        RECT  17.088 34.512 17.28 34.536 ;
    END
  END i[311]
  PIN i[312]
    DIRECTION INPUT ;
    USE SIGNAL ;
    PORT
      LAYER M4 ;
        RECT  17.088 34.608 17.28 34.632 ;
    END
  END i[312]
  PIN i[313]
    DIRECTION INPUT ;
    USE SIGNAL ;
    PORT
      LAYER M4 ;
        RECT  17.088 34.704 17.28 34.728 ;
    END
  END i[313]
  PIN i[314]
    DIRECTION INPUT ;
    USE SIGNAL ;
    PORT
      LAYER M4 ;
        RECT  17.088 34.8 17.28 34.824 ;
    END
  END i[314]
  PIN i[315]
    DIRECTION INPUT ;
    USE SIGNAL ;
    PORT
      LAYER M4 ;
        RECT  17.088 34.896 17.28 34.92 ;
    END
  END i[315]
  PIN i[316]
    DIRECTION INPUT ;
    USE SIGNAL ;
    PORT
      LAYER M4 ;
        RECT  17.088 34.992 17.28 35.016 ;
    END
  END i[316]
  PIN i[317]
    DIRECTION INPUT ;
    USE SIGNAL ;
    PORT
      LAYER M4 ;
        RECT  17.088 35.136 17.28 35.16 ;
    END
  END i[317]
  PIN i[318]
    DIRECTION INPUT ;
    USE SIGNAL ;
    PORT
      LAYER M4 ;
        RECT  17.088 35.232 17.28 35.256 ;
    END
  END i[318]
  PIN i[319]
    DIRECTION INPUT ;
    USE SIGNAL ;
    PORT
      LAYER M4 ;
        RECT  17.088 35.328 17.28 35.352 ;
    END
  END i[319]
  PIN i[31]
    DIRECTION INPUT ;
    USE SIGNAL ;
    PORT
      LAYER M4 ;
        RECT  17.088 5.424 17.28 5.448 ;
    END
  END i[31]
  PIN i[320]
    DIRECTION INPUT ;
    USE SIGNAL ;
    PORT
      LAYER M4 ;
        RECT  17.088 35.424 17.28 35.448 ;
    END
  END i[320]
  PIN i[321]
    DIRECTION INPUT ;
    USE SIGNAL ;
    PORT
      LAYER M4 ;
        RECT  17.088 35.52 17.28 35.544 ;
    END
  END i[321]
  PIN i[322]
    DIRECTION INPUT ;
    USE SIGNAL ;
    PORT
      LAYER M4 ;
        RECT  17.088 35.616 17.28 35.64 ;
    END
  END i[322]
  PIN i[323]
    DIRECTION INPUT ;
    USE SIGNAL ;
    PORT
      LAYER M4 ;
        RECT  17.088 35.76 17.28 35.784 ;
    END
  END i[323]
  PIN i[324]
    DIRECTION INPUT ;
    USE SIGNAL ;
    PORT
      LAYER M4 ;
        RECT  17.088 35.856 17.28 35.88 ;
    END
  END i[324]
  PIN i[325]
    DIRECTION INPUT ;
    USE SIGNAL ;
    PORT
      LAYER M4 ;
        RECT  17.088 35.952 17.28 35.976 ;
    END
  END i[325]
  PIN i[326]
    DIRECTION INPUT ;
    USE SIGNAL ;
    PORT
      LAYER M4 ;
        RECT  17.088 36.048 17.28 36.072 ;
    END
  END i[326]
  PIN i[327]
    DIRECTION INPUT ;
    USE SIGNAL ;
    PORT
      LAYER M4 ;
        RECT  17.088 36.144 17.28 36.168 ;
    END
  END i[327]
  PIN i[328]
    DIRECTION INPUT ;
    USE SIGNAL ;
    PORT
      LAYER M4 ;
        RECT  17.088 36.24 17.28 36.264 ;
    END
  END i[328]
  PIN i[329]
    DIRECTION INPUT ;
    USE SIGNAL ;
    PORT
      LAYER M4 ;
        RECT  17.088 36.384 17.28 36.408 ;
    END
  END i[329]
  PIN i[32]
    DIRECTION INPUT ;
    USE SIGNAL ;
    PORT
      LAYER M4 ;
        RECT  17.088 5.568 17.28 5.592 ;
    END
  END i[32]
  PIN i[330]
    DIRECTION INPUT ;
    USE SIGNAL ;
    PORT
      LAYER M4 ;
        RECT  17.088 36.48 17.28 36.504 ;
    END
  END i[330]
  PIN i[331]
    DIRECTION INPUT ;
    USE SIGNAL ;
    PORT
      LAYER M4 ;
        RECT  17.088 36.576 17.28 36.6 ;
    END
  END i[331]
  PIN i[332]
    DIRECTION INPUT ;
    USE SIGNAL ;
    PORT
      LAYER M4 ;
        RECT  17.088 36.672 17.28 36.696 ;
    END
  END i[332]
  PIN i[333]
    DIRECTION INPUT ;
    USE SIGNAL ;
    PORT
      LAYER M4 ;
        RECT  17.088 36.768 17.28 36.792 ;
    END
  END i[333]
  PIN i[334]
    DIRECTION INPUT ;
    USE SIGNAL ;
    PORT
      LAYER M4 ;
        RECT  17.088 36.864 17.28 36.888 ;
    END
  END i[334]
  PIN i[335]
    DIRECTION INPUT ;
    USE SIGNAL ;
    PORT
      LAYER M4 ;
        RECT  17.088 37.008 17.28 37.032 ;
    END
  END i[335]
  PIN i[336]
    DIRECTION INPUT ;
    USE SIGNAL ;
    PORT
      LAYER M4 ;
        RECT  17.088 37.104 17.28 37.128 ;
    END
  END i[336]
  PIN i[337]
    DIRECTION INPUT ;
    USE SIGNAL ;
    PORT
      LAYER M4 ;
        RECT  17.088 37.2 17.28 37.224 ;
    END
  END i[337]
  PIN i[338]
    DIRECTION INPUT ;
    USE SIGNAL ;
    PORT
      LAYER M4 ;
        RECT  17.088 37.296 17.28 37.32 ;
    END
  END i[338]
  PIN i[339]
    DIRECTION INPUT ;
    USE SIGNAL ;
    PORT
      LAYER M4 ;
        RECT  17.088 37.392 17.28 37.416 ;
    END
  END i[339]
  PIN i[33]
    DIRECTION INPUT ;
    USE SIGNAL ;
    PORT
      LAYER M4 ;
        RECT  17.088 5.664 17.28 5.688 ;
    END
  END i[33]
  PIN i[340]
    DIRECTION INPUT ;
    USE SIGNAL ;
    PORT
      LAYER M4 ;
        RECT  17.088 37.488 17.28 37.512 ;
    END
  END i[340]
  PIN i[341]
    DIRECTION INPUT ;
    USE SIGNAL ;
    PORT
      LAYER M4 ;
        RECT  17.088 37.632 17.28 37.656 ;
    END
  END i[341]
  PIN i[342]
    DIRECTION INPUT ;
    USE SIGNAL ;
    PORT
      LAYER M4 ;
        RECT  17.088 37.728 17.28 37.752 ;
    END
  END i[342]
  PIN i[343]
    DIRECTION INPUT ;
    USE SIGNAL ;
    PORT
      LAYER M4 ;
        RECT  17.088 37.824 17.28 37.848 ;
    END
  END i[343]
  PIN i[344]
    DIRECTION INPUT ;
    USE SIGNAL ;
    PORT
      LAYER M4 ;
        RECT  17.088 37.92 17.28 37.944 ;
    END
  END i[344]
  PIN i[345]
    DIRECTION INPUT ;
    USE SIGNAL ;
    PORT
      LAYER M4 ;
        RECT  17.088 38.016 17.28 38.04 ;
    END
  END i[345]
  PIN i[346]
    DIRECTION INPUT ;
    USE SIGNAL ;
    PORT
      LAYER M4 ;
        RECT  17.088 38.112 17.28 38.136 ;
    END
  END i[346]
  PIN i[347]
    DIRECTION INPUT ;
    USE SIGNAL ;
    PORT
      LAYER M4 ;
        RECT  17.088 38.256 17.28 38.28 ;
    END
  END i[347]
  PIN i[348]
    DIRECTION INPUT ;
    USE SIGNAL ;
    PORT
      LAYER M4 ;
        RECT  17.088 38.352 17.28 38.376 ;
    END
  END i[348]
  PIN i[349]
    DIRECTION INPUT ;
    USE SIGNAL ;
    PORT
      LAYER M4 ;
        RECT  17.088 38.448 17.28 38.472 ;
    END
  END i[349]
  PIN i[34]
    DIRECTION INPUT ;
    USE SIGNAL ;
    PORT
      LAYER M4 ;
        RECT  17.088 5.76 17.28 5.784 ;
    END
  END i[34]
  PIN i[350]
    DIRECTION INPUT ;
    USE SIGNAL ;
    PORT
      LAYER M4 ;
        RECT  17.088 38.544 17.28 38.568 ;
    END
  END i[350]
  PIN i[351]
    DIRECTION INPUT ;
    USE SIGNAL ;
    PORT
      LAYER M4 ;
        RECT  17.088 38.64 17.28 38.664 ;
    END
  END i[351]
  PIN i[352]
    DIRECTION INPUT ;
    USE SIGNAL ;
    PORT
      LAYER M4 ;
        RECT  17.088 38.736 17.28 38.76 ;
    END
  END i[352]
  PIN i[353]
    DIRECTION INPUT ;
    USE SIGNAL ;
    PORT
      LAYER M4 ;
        RECT  17.088 38.832 17.28 38.856 ;
    END
  END i[353]
  PIN i[354]
    DIRECTION INPUT ;
    USE SIGNAL ;
    PORT
      LAYER M4 ;
        RECT  17.088 38.976 17.28 39 ;
    END
  END i[354]
  PIN i[355]
    DIRECTION INPUT ;
    USE SIGNAL ;
    PORT
      LAYER M4 ;
        RECT  17.088 39.072 17.28 39.096 ;
    END
  END i[355]
  PIN i[356]
    DIRECTION INPUT ;
    USE SIGNAL ;
    PORT
      LAYER M4 ;
        RECT  17.088 39.168 17.28 39.192 ;
    END
  END i[356]
  PIN i[357]
    DIRECTION INPUT ;
    USE SIGNAL ;
    PORT
      LAYER M4 ;
        RECT  17.088 39.264 17.28 39.288 ;
    END
  END i[357]
  PIN i[358]
    DIRECTION INPUT ;
    USE SIGNAL ;
    PORT
      LAYER M4 ;
        RECT  17.088 39.36 17.28 39.384 ;
    END
  END i[358]
  PIN i[359]
    DIRECTION INPUT ;
    USE SIGNAL ;
    PORT
      LAYER M4 ;
        RECT  17.088 39.456 17.28 39.48 ;
    END
  END i[359]
  PIN i[35]
    DIRECTION INPUT ;
    USE SIGNAL ;
    PORT
      LAYER M4 ;
        RECT  17.088 5.856 17.28 5.88 ;
    END
  END i[35]
  PIN i[360]
    DIRECTION INPUT ;
    USE SIGNAL ;
    PORT
      LAYER M4 ;
        RECT  17.088 39.6 17.28 39.624 ;
    END
  END i[360]
  PIN i[361]
    DIRECTION INPUT ;
    USE SIGNAL ;
    PORT
      LAYER M4 ;
        RECT  17.088 39.696 17.28 39.72 ;
    END
  END i[361]
  PIN i[362]
    DIRECTION INPUT ;
    USE SIGNAL ;
    PORT
      LAYER M4 ;
        RECT  17.088 39.792 17.28 39.816 ;
    END
  END i[362]
  PIN i[363]
    DIRECTION INPUT ;
    USE SIGNAL ;
    PORT
      LAYER M4 ;
        RECT  17.088 39.888 17.28 39.912 ;
    END
  END i[363]
  PIN i[364]
    DIRECTION INPUT ;
    USE SIGNAL ;
    PORT
      LAYER M4 ;
        RECT  17.088 39.984 17.28 40.008 ;
    END
  END i[364]
  PIN i[365]
    DIRECTION INPUT ;
    USE SIGNAL ;
    PORT
      LAYER M4 ;
        RECT  17.088 40.08 17.28 40.104 ;
    END
  END i[365]
  PIN i[366]
    DIRECTION INPUT ;
    USE SIGNAL ;
    PORT
      LAYER M4 ;
        RECT  17.088 40.224 17.28 40.248 ;
    END
  END i[366]
  PIN i[367]
    DIRECTION INPUT ;
    USE SIGNAL ;
    PORT
      LAYER M4 ;
        RECT  17.088 40.32 17.28 40.344 ;
    END
  END i[367]
  PIN i[368]
    DIRECTION INPUT ;
    USE SIGNAL ;
    PORT
      LAYER M4 ;
        RECT  17.088 40.416 17.28 40.44 ;
    END
  END i[368]
  PIN i[369]
    DIRECTION INPUT ;
    USE SIGNAL ;
    PORT
      LAYER M4 ;
        RECT  17.088 40.512 17.28 40.536 ;
    END
  END i[369]
  PIN i[36]
    DIRECTION INPUT ;
    USE SIGNAL ;
    PORT
      LAYER M4 ;
        RECT  17.088 5.952 17.28 5.976 ;
    END
  END i[36]
  PIN i[370]
    DIRECTION INPUT ;
    USE SIGNAL ;
    PORT
      LAYER M4 ;
        RECT  17.088 40.608 17.28 40.632 ;
    END
  END i[370]
  PIN i[371]
    DIRECTION INPUT ;
    USE SIGNAL ;
    PORT
      LAYER M4 ;
        RECT  17.088 40.704 17.28 40.728 ;
    END
  END i[371]
  PIN i[372]
    DIRECTION INPUT ;
    USE SIGNAL ;
    PORT
      LAYER M4 ;
        RECT  17.088 40.848 17.28 40.872 ;
    END
  END i[372]
  PIN i[373]
    DIRECTION INPUT ;
    USE SIGNAL ;
    PORT
      LAYER M4 ;
        RECT  17.088 40.944 17.28 40.968 ;
    END
  END i[373]
  PIN i[374]
    DIRECTION INPUT ;
    USE SIGNAL ;
    PORT
      LAYER M4 ;
        RECT  17.088 41.04 17.28 41.064 ;
    END
  END i[374]
  PIN i[375]
    DIRECTION INPUT ;
    USE SIGNAL ;
    PORT
      LAYER M4 ;
        RECT  17.088 41.136 17.28 41.16 ;
    END
  END i[375]
  PIN i[376]
    DIRECTION INPUT ;
    USE SIGNAL ;
    PORT
      LAYER M4 ;
        RECT  17.088 41.232 17.28 41.256 ;
    END
  END i[376]
  PIN i[377]
    DIRECTION INPUT ;
    USE SIGNAL ;
    PORT
      LAYER M4 ;
        RECT  17.088 41.328 17.28 41.352 ;
    END
  END i[377]
  PIN i[378]
    DIRECTION INPUT ;
    USE SIGNAL ;
    PORT
      LAYER M4 ;
        RECT  17.088 41.472 17.28 41.496 ;
    END
  END i[378]
  PIN i[379]
    DIRECTION INPUT ;
    USE SIGNAL ;
    PORT
      LAYER M4 ;
        RECT  17.088 41.568 17.28 41.592 ;
    END
  END i[379]
  PIN i[37]
    DIRECTION INPUT ;
    USE SIGNAL ;
    PORT
      LAYER M4 ;
        RECT  17.088 6.048 17.28 6.072 ;
    END
  END i[37]
  PIN i[380]
    DIRECTION INPUT ;
    USE SIGNAL ;
    PORT
      LAYER M4 ;
        RECT  17.088 41.664 17.28 41.688 ;
    END
  END i[380]
  PIN i[381]
    DIRECTION INPUT ;
    USE SIGNAL ;
    PORT
      LAYER M4 ;
        RECT  17.088 41.76 17.28 41.784 ;
    END
  END i[381]
  PIN i[382]
    DIRECTION INPUT ;
    USE SIGNAL ;
    PORT
      LAYER M4 ;
        RECT  17.088 41.856 17.28 41.88 ;
    END
  END i[382]
  PIN i[383]
    DIRECTION INPUT ;
    USE SIGNAL ;
    PORT
      LAYER M4 ;
        RECT  17.088 41.952 17.28 41.976 ;
    END
  END i[383]
  PIN i[384]
    DIRECTION INPUT ;
    USE SIGNAL ;
    PORT
      LAYER M4 ;
        RECT  17.088 42.096 17.28 42.12 ;
    END
  END i[384]
  PIN i[385]
    DIRECTION INPUT ;
    USE SIGNAL ;
    PORT
      LAYER M4 ;
        RECT  17.088 42.192 17.28 42.216 ;
    END
  END i[385]
  PIN i[386]
    DIRECTION INPUT ;
    USE SIGNAL ;
    PORT
      LAYER M4 ;
        RECT  17.088 42.288 17.28 42.312 ;
    END
  END i[386]
  PIN i[387]
    DIRECTION INPUT ;
    USE SIGNAL ;
    PORT
      LAYER M4 ;
        RECT  17.088 42.384 17.28 42.408 ;
    END
  END i[387]
  PIN i[388]
    DIRECTION INPUT ;
    USE SIGNAL ;
    PORT
      LAYER M4 ;
        RECT  17.088 42.48 17.28 42.504 ;
    END
  END i[388]
  PIN i[389]
    DIRECTION INPUT ;
    USE SIGNAL ;
    PORT
      LAYER M4 ;
        RECT  17.088 42.576 17.28 42.6 ;
    END
  END i[389]
  PIN i[38]
    DIRECTION INPUT ;
    USE SIGNAL ;
    PORT
      LAYER M4 ;
        RECT  17.088 6.144 17.28 6.168 ;
    END
  END i[38]
  PIN i[390]
    DIRECTION INPUT ;
    USE SIGNAL ;
    PORT
      LAYER M4 ;
        RECT  17.088 42.672 17.28 42.696 ;
    END
  END i[390]
  PIN i[391]
    DIRECTION INPUT ;
    USE SIGNAL ;
    PORT
      LAYER M4 ;
        RECT  17.088 42.816 17.28 42.84 ;
    END
  END i[391]
  PIN i[392]
    DIRECTION INPUT ;
    USE SIGNAL ;
    PORT
      LAYER M4 ;
        RECT  17.088 42.912 17.28 42.936 ;
    END
  END i[392]
  PIN i[393]
    DIRECTION INPUT ;
    USE SIGNAL ;
    PORT
      LAYER M4 ;
        RECT  17.088 43.008 17.28 43.032 ;
    END
  END i[393]
  PIN i[394]
    DIRECTION INPUT ;
    USE SIGNAL ;
    PORT
      LAYER M4 ;
        RECT  17.088 43.104 17.28 43.128 ;
    END
  END i[394]
  PIN i[395]
    DIRECTION INPUT ;
    USE SIGNAL ;
    PORT
      LAYER M4 ;
        RECT  17.088 43.2 17.28 43.224 ;
    END
  END i[395]
  PIN i[396]
    DIRECTION INPUT ;
    USE SIGNAL ;
    PORT
      LAYER M4 ;
        RECT  17.088 43.296 17.28 43.32 ;
    END
  END i[396]
  PIN i[397]
    DIRECTION INPUT ;
    USE SIGNAL ;
    PORT
      LAYER M4 ;
        RECT  17.088 43.44 17.28 43.464 ;
    END
  END i[397]
  PIN i[398]
    DIRECTION INPUT ;
    USE SIGNAL ;
    PORT
      LAYER M4 ;
        RECT  17.088 43.536 17.28 43.56 ;
    END
  END i[398]
  PIN i[399]
    DIRECTION INPUT ;
    USE SIGNAL ;
    PORT
      LAYER M4 ;
        RECT  17.088 43.632 17.28 43.656 ;
    END
  END i[399]
  PIN i[39]
    DIRECTION INPUT ;
    USE SIGNAL ;
    PORT
      LAYER M4 ;
        RECT  17.088 6.288 17.28 6.312 ;
    END
  END i[39]
  PIN i[3]
    DIRECTION INPUT ;
    USE SIGNAL ;
    PORT
      LAYER M4 ;
        RECT  17.088 2.544 17.28 2.568 ;
    END
  END i[3]
  PIN i[400]
    DIRECTION INPUT ;
    USE SIGNAL ;
    PORT
      LAYER M4 ;
        RECT  17.088 43.728 17.28 43.752 ;
    END
  END i[400]
  PIN i[401]
    DIRECTION INPUT ;
    USE SIGNAL ;
    PORT
      LAYER M4 ;
        RECT  17.088 43.824 17.28 43.848 ;
    END
  END i[401]
  PIN i[402]
    DIRECTION INPUT ;
    USE SIGNAL ;
    PORT
      LAYER M4 ;
        RECT  17.088 43.92 17.28 43.944 ;
    END
  END i[402]
  PIN i[403]
    DIRECTION INPUT ;
    USE SIGNAL ;
    PORT
      LAYER M4 ;
        RECT  17.088 44.064 17.28 44.088 ;
    END
  END i[403]
  PIN i[404]
    DIRECTION INPUT ;
    USE SIGNAL ;
    PORT
      LAYER M4 ;
        RECT  17.088 44.16 17.28 44.184 ;
    END
  END i[404]
  PIN i[405]
    DIRECTION INPUT ;
    USE SIGNAL ;
    PORT
      LAYER M4 ;
        RECT  17.088 44.256 17.28 44.28 ;
    END
  END i[405]
  PIN i[406]
    DIRECTION INPUT ;
    USE SIGNAL ;
    PORT
      LAYER M4 ;
        RECT  17.088 44.352 17.28 44.376 ;
    END
  END i[406]
  PIN i[407]
    DIRECTION INPUT ;
    USE SIGNAL ;
    PORT
      LAYER M4 ;
        RECT  17.088 44.448 17.28 44.472 ;
    END
  END i[407]
  PIN i[408]
    DIRECTION INPUT ;
    USE SIGNAL ;
    PORT
      LAYER M4 ;
        RECT  17.088 44.544 17.28 44.568 ;
    END
  END i[408]
  PIN i[409]
    DIRECTION INPUT ;
    USE SIGNAL ;
    PORT
      LAYER M4 ;
        RECT  17.088 44.688 17.28 44.712 ;
    END
  END i[409]
  PIN i[40]
    DIRECTION INPUT ;
    USE SIGNAL ;
    PORT
      LAYER M4 ;
        RECT  17.088 6.384 17.28 6.408 ;
    END
  END i[40]
  PIN i[410]
    DIRECTION INPUT ;
    USE SIGNAL ;
    PORT
      LAYER M4 ;
        RECT  17.088 44.784 17.28 44.808 ;
    END
  END i[410]
  PIN i[411]
    DIRECTION INPUT ;
    USE SIGNAL ;
    PORT
      LAYER M4 ;
        RECT  17.088 44.88 17.28 44.904 ;
    END
  END i[411]
  PIN i[412]
    DIRECTION INPUT ;
    USE SIGNAL ;
    PORT
      LAYER M4 ;
        RECT  17.088 44.976 17.28 45 ;
    END
  END i[412]
  PIN i[413]
    DIRECTION INPUT ;
    USE SIGNAL ;
    PORT
      LAYER M4 ;
        RECT  17.088 45.072 17.28 45.096 ;
    END
  END i[413]
  PIN i[414]
    DIRECTION INPUT ;
    USE SIGNAL ;
    PORT
      LAYER M4 ;
        RECT  17.088 45.168 17.28 45.192 ;
    END
  END i[414]
  PIN i[415]
    DIRECTION INPUT ;
    USE SIGNAL ;
    PORT
      LAYER M4 ;
        RECT  17.088 45.312 17.28 45.336 ;
    END
  END i[415]
  PIN i[416]
    DIRECTION INPUT ;
    USE SIGNAL ;
    PORT
      LAYER M4 ;
        RECT  17.088 45.408 17.28 45.432 ;
    END
  END i[416]
  PIN i[417]
    DIRECTION INPUT ;
    USE SIGNAL ;
    PORT
      LAYER M4 ;
        RECT  17.088 45.504 17.28 45.528 ;
    END
  END i[417]
  PIN i[418]
    DIRECTION INPUT ;
    USE SIGNAL ;
    PORT
      LAYER M4 ;
        RECT  17.088 45.6 17.28 45.624 ;
    END
  END i[418]
  PIN i[419]
    DIRECTION INPUT ;
    USE SIGNAL ;
    PORT
      LAYER M4 ;
        RECT  17.088 45.696 17.28 45.72 ;
    END
  END i[419]
  PIN i[41]
    DIRECTION INPUT ;
    USE SIGNAL ;
    PORT
      LAYER M4 ;
        RECT  17.088 6.48 17.28 6.504 ;
    END
  END i[41]
  PIN i[420]
    DIRECTION INPUT ;
    USE SIGNAL ;
    PORT
      LAYER M4 ;
        RECT  17.088 45.792 17.28 45.816 ;
    END
  END i[420]
  PIN i[421]
    DIRECTION INPUT ;
    USE SIGNAL ;
    PORT
      LAYER M4 ;
        RECT  17.088 45.936 17.28 45.96 ;
    END
  END i[421]
  PIN i[422]
    DIRECTION INPUT ;
    USE SIGNAL ;
    PORT
      LAYER M4 ;
        RECT  17.088 46.032 17.28 46.056 ;
    END
  END i[422]
  PIN i[423]
    DIRECTION INPUT ;
    USE SIGNAL ;
    PORT
      LAYER M4 ;
        RECT  17.088 46.128 17.28 46.152 ;
    END
  END i[423]
  PIN i[424]
    DIRECTION INPUT ;
    USE SIGNAL ;
    PORT
      LAYER M4 ;
        RECT  17.088 46.224 17.28 46.248 ;
    END
  END i[424]
  PIN i[425]
    DIRECTION INPUT ;
    USE SIGNAL ;
    PORT
      LAYER M4 ;
        RECT  17.088 46.32 17.28 46.344 ;
    END
  END i[425]
  PIN i[426]
    DIRECTION INPUT ;
    USE SIGNAL ;
    PORT
      LAYER M4 ;
        RECT  17.088 46.416 17.28 46.44 ;
    END
  END i[426]
  PIN i[427]
    DIRECTION INPUT ;
    USE SIGNAL ;
    PORT
      LAYER M4 ;
        RECT  17.088 46.512 17.28 46.536 ;
    END
  END i[427]
  PIN i[428]
    DIRECTION INPUT ;
    USE SIGNAL ;
    PORT
      LAYER M4 ;
        RECT  17.088 46.656 17.28 46.68 ;
    END
  END i[428]
  PIN i[429]
    DIRECTION INPUT ;
    USE SIGNAL ;
    PORT
      LAYER M4 ;
        RECT  17.088 46.752 17.28 46.776 ;
    END
  END i[429]
  PIN i[42]
    DIRECTION INPUT ;
    USE SIGNAL ;
    PORT
      LAYER M4 ;
        RECT  17.088 6.576 17.28 6.6 ;
    END
  END i[42]
  PIN i[430]
    DIRECTION INPUT ;
    USE SIGNAL ;
    PORT
      LAYER M4 ;
        RECT  17.088 46.848 17.28 46.872 ;
    END
  END i[430]
  PIN i[431]
    DIRECTION INPUT ;
    USE SIGNAL ;
    PORT
      LAYER M4 ;
        RECT  17.088 46.944 17.28 46.968 ;
    END
  END i[431]
  PIN i[432]
    DIRECTION INPUT ;
    USE SIGNAL ;
    PORT
      LAYER M4 ;
        RECT  17.088 47.04 17.28 47.064 ;
    END
  END i[432]
  PIN i[433]
    DIRECTION INPUT ;
    USE SIGNAL ;
    PORT
      LAYER M4 ;
        RECT  17.088 47.136 17.28 47.16 ;
    END
  END i[433]
  PIN i[434]
    DIRECTION INPUT ;
    USE SIGNAL ;
    PORT
      LAYER M4 ;
        RECT  17.088 47.28 17.28 47.304 ;
    END
  END i[434]
  PIN i[435]
    DIRECTION INPUT ;
    USE SIGNAL ;
    PORT
      LAYER M4 ;
        RECT  17.088 47.376 17.28 47.4 ;
    END
  END i[435]
  PIN i[436]
    DIRECTION INPUT ;
    USE SIGNAL ;
    PORT
      LAYER M4 ;
        RECT  17.088 47.472 17.28 47.496 ;
    END
  END i[436]
  PIN i[437]
    DIRECTION INPUT ;
    USE SIGNAL ;
    PORT
      LAYER M4 ;
        RECT  17.088 47.568 17.28 47.592 ;
    END
  END i[437]
  PIN i[438]
    DIRECTION INPUT ;
    USE SIGNAL ;
    PORT
      LAYER M4 ;
        RECT  17.088 47.664 17.28 47.688 ;
    END
  END i[438]
  PIN i[439]
    DIRECTION INPUT ;
    USE SIGNAL ;
    PORT
      LAYER M4 ;
        RECT  17.088 47.76 17.28 47.784 ;
    END
  END i[439]
  PIN i[43]
    DIRECTION INPUT ;
    USE SIGNAL ;
    PORT
      LAYER M4 ;
        RECT  17.088 6.672 17.28 6.696 ;
    END
  END i[43]
  PIN i[440]
    DIRECTION INPUT ;
    USE SIGNAL ;
    PORT
      LAYER M4 ;
        RECT  17.088 47.904 17.28 47.928 ;
    END
  END i[440]
  PIN i[441]
    DIRECTION INPUT ;
    USE SIGNAL ;
    PORT
      LAYER M4 ;
        RECT  17.088 48 17.28 48.024 ;
    END
  END i[441]
  PIN i[442]
    DIRECTION INPUT ;
    USE SIGNAL ;
    PORT
      LAYER M4 ;
        RECT  17.088 48.096 17.28 48.12 ;
    END
  END i[442]
  PIN i[443]
    DIRECTION INPUT ;
    USE SIGNAL ;
    PORT
      LAYER M4 ;
        RECT  17.088 48.192 17.28 48.216 ;
    END
  END i[443]
  PIN i[444]
    DIRECTION INPUT ;
    USE SIGNAL ;
    PORT
      LAYER M4 ;
        RECT  17.088 48.288 17.28 48.312 ;
    END
  END i[444]
  PIN i[445]
    DIRECTION INPUT ;
    USE SIGNAL ;
    PORT
      LAYER M4 ;
        RECT  17.088 48.384 17.28 48.408 ;
    END
  END i[445]
  PIN i[446]
    DIRECTION INPUT ;
    USE SIGNAL ;
    PORT
      LAYER M4 ;
        RECT  17.088 48.528 17.28 48.552 ;
    END
  END i[446]
  PIN i[447]
    DIRECTION INPUT ;
    USE SIGNAL ;
    PORT
      LAYER M4 ;
        RECT  17.088 48.624 17.28 48.648 ;
    END
  END i[447]
  PIN i[448]
    DIRECTION INPUT ;
    USE SIGNAL ;
    PORT
      LAYER M4 ;
        RECT  17.088 48.72 17.28 48.744 ;
    END
  END i[448]
  PIN i[449]
    DIRECTION INPUT ;
    USE SIGNAL ;
    PORT
      LAYER M4 ;
        RECT  17.088 48.816 17.28 48.84 ;
    END
  END i[449]
  PIN i[44]
    DIRECTION INPUT ;
    USE SIGNAL ;
    PORT
      LAYER M4 ;
        RECT  17.088 6.768 17.28 6.792 ;
    END
  END i[44]
  PIN i[450]
    DIRECTION INPUT ;
    USE SIGNAL ;
    PORT
      LAYER M4 ;
        RECT  17.088 48.912 17.28 48.936 ;
    END
  END i[450]
  PIN i[451]
    DIRECTION INPUT ;
    USE SIGNAL ;
    PORT
      LAYER M4 ;
        RECT  17.088 49.008 17.28 49.032 ;
    END
  END i[451]
  PIN i[452]
    DIRECTION INPUT ;
    USE SIGNAL ;
    PORT
      LAYER M4 ;
        RECT  17.088 49.152 17.28 49.176 ;
    END
  END i[452]
  PIN i[453]
    DIRECTION INPUT ;
    USE SIGNAL ;
    PORT
      LAYER M4 ;
        RECT  17.088 49.248 17.28 49.272 ;
    END
  END i[453]
  PIN i[454]
    DIRECTION INPUT ;
    USE SIGNAL ;
    PORT
      LAYER M4 ;
        RECT  17.088 49.344 17.28 49.368 ;
    END
  END i[454]
  PIN i[455]
    DIRECTION INPUT ;
    USE SIGNAL ;
    PORT
      LAYER M4 ;
        RECT  17.088 49.44 17.28 49.464 ;
    END
  END i[455]
  PIN i[456]
    DIRECTION INPUT ;
    USE SIGNAL ;
    PORT
      LAYER M4 ;
        RECT  17.088 49.536 17.28 49.56 ;
    END
  END i[456]
  PIN i[457]
    DIRECTION INPUT ;
    USE SIGNAL ;
    PORT
      LAYER M4 ;
        RECT  17.088 49.632 17.28 49.656 ;
    END
  END i[457]
  PIN i[458]
    DIRECTION INPUT ;
    USE SIGNAL ;
    PORT
      LAYER M4 ;
        RECT  17.088 49.728 17.28 49.752 ;
    END
  END i[458]
  PIN i[459]
    DIRECTION INPUT ;
    USE SIGNAL ;
    PORT
      LAYER M4 ;
        RECT  17.088 49.872 17.28 49.896 ;
    END
  END i[459]
  PIN i[45]
    DIRECTION INPUT ;
    USE SIGNAL ;
    PORT
      LAYER M4 ;
        RECT  17.088 6.912 17.28 6.936 ;
    END
  END i[45]
  PIN i[460]
    DIRECTION INPUT ;
    USE SIGNAL ;
    PORT
      LAYER M4 ;
        RECT  17.088 49.968 17.28 49.992 ;
    END
  END i[460]
  PIN i[461]
    DIRECTION INPUT ;
    USE SIGNAL ;
    PORT
      LAYER M4 ;
        RECT  17.088 50.064 17.28 50.088 ;
    END
  END i[461]
  PIN i[462]
    DIRECTION INPUT ;
    USE SIGNAL ;
    PORT
      LAYER M4 ;
        RECT  17.088 50.16 17.28 50.184 ;
    END
  END i[462]
  PIN i[463]
    DIRECTION INPUT ;
    USE SIGNAL ;
    PORT
      LAYER M4 ;
        RECT  17.088 50.256 17.28 50.28 ;
    END
  END i[463]
  PIN i[464]
    DIRECTION INPUT ;
    USE SIGNAL ;
    PORT
      LAYER M4 ;
        RECT  17.088 50.352 17.28 50.376 ;
    END
  END i[464]
  PIN i[465]
    DIRECTION INPUT ;
    USE SIGNAL ;
    PORT
      LAYER M4 ;
        RECT  17.088 50.496 17.28 50.52 ;
    END
  END i[465]
  PIN i[466]
    DIRECTION INPUT ;
    USE SIGNAL ;
    PORT
      LAYER M4 ;
        RECT  17.088 50.592 17.28 50.616 ;
    END
  END i[466]
  PIN i[467]
    DIRECTION INPUT ;
    USE SIGNAL ;
    PORT
      LAYER M4 ;
        RECT  17.088 50.688 17.28 50.712 ;
    END
  END i[467]
  PIN i[468]
    DIRECTION INPUT ;
    USE SIGNAL ;
    PORT
      LAYER M4 ;
        RECT  17.088 50.784 17.28 50.808 ;
    END
  END i[468]
  PIN i[469]
    DIRECTION INPUT ;
    USE SIGNAL ;
    PORT
      LAYER M4 ;
        RECT  17.088 50.88 17.28 50.904 ;
    END
  END i[469]
  PIN i[46]
    DIRECTION INPUT ;
    USE SIGNAL ;
    PORT
      LAYER M4 ;
        RECT  17.088 7.008 17.28 7.032 ;
    END
  END i[46]
  PIN i[470]
    DIRECTION INPUT ;
    USE SIGNAL ;
    PORT
      LAYER M4 ;
        RECT  17.088 50.976 17.28 51 ;
    END
  END i[470]
  PIN i[471]
    DIRECTION INPUT ;
    USE SIGNAL ;
    PORT
      LAYER M4 ;
        RECT  17.088 51.12 17.28 51.144 ;
    END
  END i[471]
  PIN i[472]
    DIRECTION INPUT ;
    USE SIGNAL ;
    PORT
      LAYER M4 ;
        RECT  17.088 51.216 17.28 51.24 ;
    END
  END i[472]
  PIN i[473]
    DIRECTION INPUT ;
    USE SIGNAL ;
    PORT
      LAYER M4 ;
        RECT  17.088 51.312 17.28 51.336 ;
    END
  END i[473]
  PIN i[474]
    DIRECTION INPUT ;
    USE SIGNAL ;
    PORT
      LAYER M4 ;
        RECT  17.088 51.408 17.28 51.432 ;
    END
  END i[474]
  PIN i[475]
    DIRECTION INPUT ;
    USE SIGNAL ;
    PORT
      LAYER M4 ;
        RECT  17.088 51.504 17.28 51.528 ;
    END
  END i[475]
  PIN i[476]
    DIRECTION INPUT ;
    USE SIGNAL ;
    PORT
      LAYER M4 ;
        RECT  17.088 51.6 17.28 51.624 ;
    END
  END i[476]
  PIN i[477]
    DIRECTION INPUT ;
    USE SIGNAL ;
    PORT
      LAYER M4 ;
        RECT  17.088 51.744 17.28 51.768 ;
    END
  END i[477]
  PIN i[478]
    DIRECTION INPUT ;
    USE SIGNAL ;
    PORT
      LAYER M4 ;
        RECT  17.088 51.84 17.28 51.864 ;
    END
  END i[478]
  PIN i[479]
    DIRECTION INPUT ;
    USE SIGNAL ;
    PORT
      LAYER M4 ;
        RECT  17.088 51.936 17.28 51.96 ;
    END
  END i[479]
  PIN i[47]
    DIRECTION INPUT ;
    USE SIGNAL ;
    PORT
      LAYER M4 ;
        RECT  17.088 7.104 17.28 7.128 ;
    END
  END i[47]
  PIN i[480]
    DIRECTION INPUT ;
    USE SIGNAL ;
    PORT
      LAYER M4 ;
        RECT  17.088 52.032 17.28 52.056 ;
    END
  END i[480]
  PIN i[481]
    DIRECTION INPUT ;
    USE SIGNAL ;
    PORT
      LAYER M4 ;
        RECT  17.088 52.128 17.28 52.152 ;
    END
  END i[481]
  PIN i[482]
    DIRECTION INPUT ;
    USE SIGNAL ;
    PORT
      LAYER M4 ;
        RECT  17.088 52.224 17.28 52.248 ;
    END
  END i[482]
  PIN i[483]
    DIRECTION INPUT ;
    USE SIGNAL ;
    PORT
      LAYER M4 ;
        RECT  17.088 52.368 17.28 52.392 ;
    END
  END i[483]
  PIN i[484]
    DIRECTION INPUT ;
    USE SIGNAL ;
    PORT
      LAYER M4 ;
        RECT  17.088 52.464 17.28 52.488 ;
    END
  END i[484]
  PIN i[485]
    DIRECTION INPUT ;
    USE SIGNAL ;
    PORT
      LAYER M4 ;
        RECT  17.088 52.56 17.28 52.584 ;
    END
  END i[485]
  PIN i[486]
    DIRECTION INPUT ;
    USE SIGNAL ;
    PORT
      LAYER M4 ;
        RECT  17.088 52.656 17.28 52.68 ;
    END
  END i[486]
  PIN i[487]
    DIRECTION INPUT ;
    USE SIGNAL ;
    PORT
      LAYER M4 ;
        RECT  17.088 52.752 17.28 52.776 ;
    END
  END i[487]
  PIN i[488]
    DIRECTION INPUT ;
    USE SIGNAL ;
    PORT
      LAYER M4 ;
        RECT  17.088 52.848 17.28 52.872 ;
    END
  END i[488]
  PIN i[489]
    DIRECTION INPUT ;
    USE SIGNAL ;
    PORT
      LAYER M4 ;
        RECT  17.088 52.992 17.28 53.016 ;
    END
  END i[489]
  PIN i[48]
    DIRECTION INPUT ;
    USE SIGNAL ;
    PORT
      LAYER M4 ;
        RECT  17.088 7.2 17.28 7.224 ;
    END
  END i[48]
  PIN i[490]
    DIRECTION INPUT ;
    USE SIGNAL ;
    PORT
      LAYER M4 ;
        RECT  17.088 53.088 17.28 53.112 ;
    END
  END i[490]
  PIN i[491]
    DIRECTION INPUT ;
    USE SIGNAL ;
    PORT
      LAYER M4 ;
        RECT  17.088 53.184 17.28 53.208 ;
    END
  END i[491]
  PIN i[492]
    DIRECTION INPUT ;
    USE SIGNAL ;
    PORT
      LAYER M4 ;
        RECT  17.088 53.28 17.28 53.304 ;
    END
  END i[492]
  PIN i[493]
    DIRECTION INPUT ;
    USE SIGNAL ;
    PORT
      LAYER M4 ;
        RECT  17.088 53.376 17.28 53.4 ;
    END
  END i[493]
  PIN i[494]
    DIRECTION INPUT ;
    USE SIGNAL ;
    PORT
      LAYER M4 ;
        RECT  17.088 53.472 17.28 53.496 ;
    END
  END i[494]
  PIN i[495]
    DIRECTION INPUT ;
    USE SIGNAL ;
    PORT
      LAYER M4 ;
        RECT  17.088 53.568 17.28 53.592 ;
    END
  END i[495]
  PIN i[496]
    DIRECTION INPUT ;
    USE SIGNAL ;
    PORT
      LAYER M4 ;
        RECT  17.088 53.712 17.28 53.736 ;
    END
  END i[496]
  PIN i[497]
    DIRECTION INPUT ;
    USE SIGNAL ;
    PORT
      LAYER M4 ;
        RECT  17.088 53.808 17.28 53.832 ;
    END
  END i[497]
  PIN i[498]
    DIRECTION INPUT ;
    USE SIGNAL ;
    PORT
      LAYER M4 ;
        RECT  17.088 53.904 17.28 53.928 ;
    END
  END i[498]
  PIN i[499]
    DIRECTION INPUT ;
    USE SIGNAL ;
    PORT
      LAYER M4 ;
        RECT  17.088 54 17.28 54.024 ;
    END
  END i[499]
  PIN i[49]
    DIRECTION INPUT ;
    USE SIGNAL ;
    PORT
      LAYER M4 ;
        RECT  17.088 7.296 17.28 7.32 ;
    END
  END i[49]
  PIN i[4]
    DIRECTION INPUT ;
    USE SIGNAL ;
    PORT
      LAYER M4 ;
        RECT  17.088 2.64 17.28 2.664 ;
    END
  END i[4]
  PIN i[500]
    DIRECTION INPUT ;
    USE SIGNAL ;
    PORT
      LAYER M4 ;
        RECT  17.088 54.096 17.28 54.12 ;
    END
  END i[500]
  PIN i[501]
    DIRECTION INPUT ;
    USE SIGNAL ;
    PORT
      LAYER M4 ;
        RECT  17.088 54.192 17.28 54.216 ;
    END
  END i[501]
  PIN i[502]
    DIRECTION INPUT ;
    USE SIGNAL ;
    PORT
      LAYER M4 ;
        RECT  17.088 54.336 17.28 54.36 ;
    END
  END i[502]
  PIN i[503]
    DIRECTION INPUT ;
    USE SIGNAL ;
    PORT
      LAYER M4 ;
        RECT  17.088 54.432 17.28 54.456 ;
    END
  END i[503]
  PIN i[504]
    DIRECTION INPUT ;
    USE SIGNAL ;
    PORT
      LAYER M4 ;
        RECT  17.088 54.528 17.28 54.552 ;
    END
  END i[504]
  PIN i[505]
    DIRECTION INPUT ;
    USE SIGNAL ;
    PORT
      LAYER M4 ;
        RECT  17.088 54.624 17.28 54.648 ;
    END
  END i[505]
  PIN i[506]
    DIRECTION INPUT ;
    USE SIGNAL ;
    PORT
      LAYER M4 ;
        RECT  17.088 54.72 17.28 54.744 ;
    END
  END i[506]
  PIN i[507]
    DIRECTION INPUT ;
    USE SIGNAL ;
    PORT
      LAYER M4 ;
        RECT  17.088 54.816 17.28 54.84 ;
    END
  END i[507]
  PIN i[508]
    DIRECTION INPUT ;
    USE SIGNAL ;
    PORT
      LAYER M4 ;
        RECT  17.088 54.96 17.28 54.984 ;
    END
  END i[508]
  PIN i[509]
    DIRECTION INPUT ;
    USE SIGNAL ;
    PORT
      LAYER M4 ;
        RECT  17.088 55.056 17.28 55.08 ;
    END
  END i[509]
  PIN i[50]
    DIRECTION INPUT ;
    USE SIGNAL ;
    PORT
      LAYER M4 ;
        RECT  17.088 7.392 17.28 7.416 ;
    END
  END i[50]
  PIN i[510]
    DIRECTION INPUT ;
    USE SIGNAL ;
    PORT
      LAYER M4 ;
        RECT  17.088 55.152 17.28 55.176 ;
    END
  END i[510]
  PIN i[511]
    DIRECTION INPUT ;
    USE SIGNAL ;
    PORT
      LAYER M4 ;
        RECT  17.088 55.248 17.28 55.272 ;
    END
  END i[511]
  PIN i[512]
    DIRECTION INPUT ;
    USE SIGNAL ;
    PORT
      LAYER M4 ;
        RECT  17.088 55.344 17.28 55.368 ;
    END
  END i[512]
  PIN i[513]
    DIRECTION INPUT ;
    USE SIGNAL ;
    PORT
      LAYER M4 ;
        RECT  17.088 55.44 17.28 55.464 ;
    END
  END i[513]
  PIN i[514]
    DIRECTION INPUT ;
    USE SIGNAL ;
    PORT
      LAYER M4 ;
        RECT  17.088 55.584 17.28 55.608 ;
    END
  END i[514]
  PIN i[515]
    DIRECTION INPUT ;
    USE SIGNAL ;
    PORT
      LAYER M4 ;
        RECT  17.088 55.68 17.28 55.704 ;
    END
  END i[515]
  PIN i[516]
    DIRECTION INPUT ;
    USE SIGNAL ;
    PORT
      LAYER M4 ;
        RECT  17.088 55.776 17.28 55.8 ;
    END
  END i[516]
  PIN i[517]
    DIRECTION INPUT ;
    USE SIGNAL ;
    PORT
      LAYER M4 ;
        RECT  17.088 55.872 17.28 55.896 ;
    END
  END i[517]
  PIN i[518]
    DIRECTION INPUT ;
    USE SIGNAL ;
    PORT
      LAYER M4 ;
        RECT  17.088 55.968 17.28 55.992 ;
    END
  END i[518]
  PIN i[519]
    DIRECTION INPUT ;
    USE SIGNAL ;
    PORT
      LAYER M4 ;
        RECT  17.088 56.064 17.28 56.088 ;
    END
  END i[519]
  PIN i[51]
    DIRECTION INPUT ;
    USE SIGNAL ;
    PORT
      LAYER M4 ;
        RECT  17.088 7.536 17.28 7.56 ;
    END
  END i[51]
  PIN i[520]
    DIRECTION INPUT ;
    USE SIGNAL ;
    PORT
      LAYER M4 ;
        RECT  17.088 56.208 17.28 56.232 ;
    END
  END i[520]
  PIN i[521]
    DIRECTION INPUT ;
    USE SIGNAL ;
    PORT
      LAYER M4 ;
        RECT  17.088 56.304 17.28 56.328 ;
    END
  END i[521]
  PIN i[522]
    DIRECTION INPUT ;
    USE SIGNAL ;
    PORT
      LAYER M4 ;
        RECT  17.088 56.4 17.28 56.424 ;
    END
  END i[522]
  PIN i[523]
    DIRECTION INPUT ;
    USE SIGNAL ;
    PORT
      LAYER M4 ;
        RECT  17.088 56.496 17.28 56.52 ;
    END
  END i[523]
  PIN i[524]
    DIRECTION INPUT ;
    USE SIGNAL ;
    PORT
      LAYER M4 ;
        RECT  17.088 56.592 17.28 56.616 ;
    END
  END i[524]
  PIN i[525]
    DIRECTION INPUT ;
    USE SIGNAL ;
    PORT
      LAYER M4 ;
        RECT  17.088 56.688 17.28 56.712 ;
    END
  END i[525]
  PIN i[526]
    DIRECTION INPUT ;
    USE SIGNAL ;
    PORT
      LAYER M4 ;
        RECT  17.088 56.832 17.28 56.856 ;
    END
  END i[526]
  PIN i[527]
    DIRECTION INPUT ;
    USE SIGNAL ;
    PORT
      LAYER M4 ;
        RECT  17.088 56.928 17.28 56.952 ;
    END
  END i[527]
  PIN i[528]
    DIRECTION INPUT ;
    USE SIGNAL ;
    PORT
      LAYER M4 ;
        RECT  17.088 57.024 17.28 57.048 ;
    END
  END i[528]
  PIN i[529]
    DIRECTION INPUT ;
    USE SIGNAL ;
    PORT
      LAYER M4 ;
        RECT  17.088 57.12 17.28 57.144 ;
    END
  END i[529]
  PIN i[52]
    DIRECTION INPUT ;
    USE SIGNAL ;
    PORT
      LAYER M4 ;
        RECT  17.088 7.632 17.28 7.656 ;
    END
  END i[52]
  PIN i[530]
    DIRECTION INPUT ;
    USE SIGNAL ;
    PORT
      LAYER M4 ;
        RECT  17.088 57.216 17.28 57.24 ;
    END
  END i[530]
  PIN i[531]
    DIRECTION INPUT ;
    USE SIGNAL ;
    PORT
      LAYER M4 ;
        RECT  17.088 57.312 17.28 57.336 ;
    END
  END i[531]
  PIN i[532]
    DIRECTION INPUT ;
    USE SIGNAL ;
    PORT
      LAYER M4 ;
        RECT  17.088 57.408 17.28 57.432 ;
    END
  END i[532]
  PIN i[533]
    DIRECTION INPUT ;
    USE SIGNAL ;
    PORT
      LAYER M4 ;
        RECT  17.088 57.552 17.28 57.576 ;
    END
  END i[533]
  PIN i[534]
    DIRECTION INPUT ;
    USE SIGNAL ;
    PORT
      LAYER M4 ;
        RECT  17.088 57.648 17.28 57.672 ;
    END
  END i[534]
  PIN i[535]
    DIRECTION INPUT ;
    USE SIGNAL ;
    PORT
      LAYER M4 ;
        RECT  17.088 57.744 17.28 57.768 ;
    END
  END i[535]
  PIN i[536]
    DIRECTION INPUT ;
    USE SIGNAL ;
    PORT
      LAYER M4 ;
        RECT  17.088 57.84 17.28 57.864 ;
    END
  END i[536]
  PIN i[537]
    DIRECTION INPUT ;
    USE SIGNAL ;
    PORT
      LAYER M4 ;
        RECT  17.088 57.936 17.28 57.96 ;
    END
  END i[537]
  PIN i[538]
    DIRECTION INPUT ;
    USE SIGNAL ;
    PORT
      LAYER M4 ;
        RECT  17.088 58.032 17.28 58.056 ;
    END
  END i[538]
  PIN i[539]
    DIRECTION INPUT ;
    USE SIGNAL ;
    PORT
      LAYER M4 ;
        RECT  17.088 58.176 17.28 58.2 ;
    END
  END i[539]
  PIN i[53]
    DIRECTION INPUT ;
    USE SIGNAL ;
    PORT
      LAYER M4 ;
        RECT  17.088 7.728 17.28 7.752 ;
    END
  END i[53]
  PIN i[540]
    DIRECTION INPUT ;
    USE SIGNAL ;
    PORT
      LAYER M4 ;
        RECT  17.088 58.272 17.28 58.296 ;
    END
  END i[540]
  PIN i[541]
    DIRECTION INPUT ;
    USE SIGNAL ;
    PORT
      LAYER M4 ;
        RECT  17.088 58.368 17.28 58.392 ;
    END
  END i[541]
  PIN i[542]
    DIRECTION INPUT ;
    USE SIGNAL ;
    PORT
      LAYER M4 ;
        RECT  17.088 58.464 17.28 58.488 ;
    END
  END i[542]
  PIN i[543]
    DIRECTION INPUT ;
    USE SIGNAL ;
    PORT
      LAYER M4 ;
        RECT  17.088 58.56 17.28 58.584 ;
    END
  END i[543]
  PIN i[544]
    DIRECTION INPUT ;
    USE SIGNAL ;
    PORT
      LAYER M4 ;
        RECT  17.088 58.656 17.28 58.68 ;
    END
  END i[544]
  PIN i[545]
    DIRECTION INPUT ;
    USE SIGNAL ;
    PORT
      LAYER M4 ;
        RECT  17.088 58.8 17.28 58.824 ;
    END
  END i[545]
  PIN i[546]
    DIRECTION INPUT ;
    USE SIGNAL ;
    PORT
      LAYER M4 ;
        RECT  17.088 58.896 17.28 58.92 ;
    END
  END i[546]
  PIN i[547]
    DIRECTION INPUT ;
    USE SIGNAL ;
    PORT
      LAYER M4 ;
        RECT  17.088 58.992 17.28 59.016 ;
    END
  END i[547]
  PIN i[548]
    DIRECTION INPUT ;
    USE SIGNAL ;
    PORT
      LAYER M4 ;
        RECT  17.088 59.088 17.28 59.112 ;
    END
  END i[548]
  PIN i[549]
    DIRECTION INPUT ;
    USE SIGNAL ;
    PORT
      LAYER M4 ;
        RECT  17.088 59.184 17.28 59.208 ;
    END
  END i[549]
  PIN i[54]
    DIRECTION INPUT ;
    USE SIGNAL ;
    PORT
      LAYER M4 ;
        RECT  17.088 7.824 17.28 7.848 ;
    END
  END i[54]
  PIN i[550]
    DIRECTION INPUT ;
    USE SIGNAL ;
    PORT
      LAYER M4 ;
        RECT  17.088 59.28 17.28 59.304 ;
    END
  END i[550]
  PIN i[551]
    DIRECTION INPUT ;
    USE SIGNAL ;
    PORT
      LAYER M4 ;
        RECT  17.088 59.424 17.28 59.448 ;
    END
  END i[551]
  PIN i[552]
    DIRECTION INPUT ;
    USE SIGNAL ;
    PORT
      LAYER M4 ;
        RECT  17.088 59.52 17.28 59.544 ;
    END
  END i[552]
  PIN i[553]
    DIRECTION INPUT ;
    USE SIGNAL ;
    PORT
      LAYER M4 ;
        RECT  17.088 59.616 17.28 59.64 ;
    END
  END i[553]
  PIN i[554]
    DIRECTION INPUT ;
    USE SIGNAL ;
    PORT
      LAYER M4 ;
        RECT  17.088 59.712 17.28 59.736 ;
    END
  END i[554]
  PIN i[555]
    DIRECTION INPUT ;
    USE SIGNAL ;
    PORT
      LAYER M4 ;
        RECT  17.088 59.808 17.28 59.832 ;
    END
  END i[555]
  PIN i[556]
    DIRECTION INPUT ;
    USE SIGNAL ;
    PORT
      LAYER M4 ;
        RECT  17.088 59.904 17.28 59.928 ;
    END
  END i[556]
  PIN i[557]
    DIRECTION INPUT ;
    USE SIGNAL ;
    PORT
      LAYER M4 ;
        RECT  17.088 60.048 17.28 60.072 ;
    END
  END i[557]
  PIN i[558]
    DIRECTION INPUT ;
    USE SIGNAL ;
    PORT
      LAYER M4 ;
        RECT  17.088 60.144 17.28 60.168 ;
    END
  END i[558]
  PIN i[559]
    DIRECTION INPUT ;
    USE SIGNAL ;
    PORT
      LAYER M4 ;
        RECT  17.088 60.24 17.28 60.264 ;
    END
  END i[559]
  PIN i[55]
    DIRECTION INPUT ;
    USE SIGNAL ;
    PORT
      LAYER M4 ;
        RECT  17.088 7.92 17.28 7.944 ;
    END
  END i[55]
  PIN i[560]
    DIRECTION INPUT ;
    USE SIGNAL ;
    PORT
      LAYER M4 ;
        RECT  17.088 60.336 17.28 60.36 ;
    END
  END i[560]
  PIN i[561]
    DIRECTION INPUT ;
    USE SIGNAL ;
    PORT
      LAYER M4 ;
        RECT  17.088 60.432 17.28 60.456 ;
    END
  END i[561]
  PIN i[56]
    DIRECTION INPUT ;
    USE SIGNAL ;
    PORT
      LAYER M4 ;
        RECT  17.088 8.016 17.28 8.04 ;
    END
  END i[56]
  PIN i[57]
    DIRECTION INPUT ;
    USE SIGNAL ;
    PORT
      LAYER M4 ;
        RECT  17.088 8.16 17.28 8.184 ;
    END
  END i[57]
  PIN i[58]
    DIRECTION INPUT ;
    USE SIGNAL ;
    PORT
      LAYER M4 ;
        RECT  17.088 8.256 17.28 8.28 ;
    END
  END i[58]
  PIN i[59]
    DIRECTION INPUT ;
    USE SIGNAL ;
    PORT
      LAYER M4 ;
        RECT  17.088 8.352 17.28 8.376 ;
    END
  END i[59]
  PIN i[5]
    DIRECTION INPUT ;
    USE SIGNAL ;
    PORT
      LAYER M4 ;
        RECT  17.088 2.736 17.28 2.76 ;
    END
  END i[5]
  PIN i[60]
    DIRECTION INPUT ;
    USE SIGNAL ;
    PORT
      LAYER M4 ;
        RECT  17.088 8.448 17.28 8.472 ;
    END
  END i[60]
  PIN i[61]
    DIRECTION INPUT ;
    USE SIGNAL ;
    PORT
      LAYER M4 ;
        RECT  17.088 8.544 17.28 8.568 ;
    END
  END i[61]
  PIN i[62]
    DIRECTION INPUT ;
    USE SIGNAL ;
    PORT
      LAYER M4 ;
        RECT  17.088 8.64 17.28 8.664 ;
    END
  END i[62]
  PIN i[63]
    DIRECTION INPUT ;
    USE SIGNAL ;
    PORT
      LAYER M4 ;
        RECT  17.088 8.784 17.28 8.808 ;
    END
  END i[63]
  PIN i[64]
    DIRECTION INPUT ;
    USE SIGNAL ;
    PORT
      LAYER M4 ;
        RECT  17.088 8.88 17.28 8.904 ;
    END
  END i[64]
  PIN i[65]
    DIRECTION INPUT ;
    USE SIGNAL ;
    PORT
      LAYER M4 ;
        RECT  17.088 8.976 17.28 9 ;
    END
  END i[65]
  PIN i[66]
    DIRECTION INPUT ;
    USE SIGNAL ;
    PORT
      LAYER M4 ;
        RECT  17.088 9.072 17.28 9.096 ;
    END
  END i[66]
  PIN i[67]
    DIRECTION INPUT ;
    USE SIGNAL ;
    PORT
      LAYER M4 ;
        RECT  17.088 9.168 17.28 9.192 ;
    END
  END i[67]
  PIN i[68]
    DIRECTION INPUT ;
    USE SIGNAL ;
    PORT
      LAYER M4 ;
        RECT  17.088 9.264 17.28 9.288 ;
    END
  END i[68]
  PIN i[69]
    DIRECTION INPUT ;
    USE SIGNAL ;
    PORT
      LAYER M4 ;
        RECT  17.088 9.408 17.28 9.432 ;
    END
  END i[69]
  PIN i[6]
    DIRECTION INPUT ;
    USE SIGNAL ;
    PORT
      LAYER M4 ;
        RECT  17.088 2.832 17.28 2.856 ;
    END
  END i[6]
  PIN i[70]
    DIRECTION INPUT ;
    USE SIGNAL ;
    PORT
      LAYER M4 ;
        RECT  17.088 9.504 17.28 9.528 ;
    END
  END i[70]
  PIN i[71]
    DIRECTION INPUT ;
    USE SIGNAL ;
    PORT
      LAYER M4 ;
        RECT  17.088 9.6 17.28 9.624 ;
    END
  END i[71]
  PIN i[72]
    DIRECTION INPUT ;
    USE SIGNAL ;
    PORT
      LAYER M4 ;
        RECT  17.088 9.696 17.28 9.72 ;
    END
  END i[72]
  PIN i[73]
    DIRECTION INPUT ;
    USE SIGNAL ;
    PORT
      LAYER M4 ;
        RECT  17.088 9.792 17.28 9.816 ;
    END
  END i[73]
  PIN i[74]
    DIRECTION INPUT ;
    USE SIGNAL ;
    PORT
      LAYER M4 ;
        RECT  17.088 9.888 17.28 9.912 ;
    END
  END i[74]
  PIN i[75]
    DIRECTION INPUT ;
    USE SIGNAL ;
    PORT
      LAYER M4 ;
        RECT  17.088 9.984 17.28 10.008 ;
    END
  END i[75]
  PIN i[76]
    DIRECTION INPUT ;
    USE SIGNAL ;
    PORT
      LAYER M4 ;
        RECT  17.088 10.128 17.28 10.152 ;
    END
  END i[76]
  PIN i[77]
    DIRECTION INPUT ;
    USE SIGNAL ;
    PORT
      LAYER M4 ;
        RECT  17.088 10.224 17.28 10.248 ;
    END
  END i[77]
  PIN i[78]
    DIRECTION INPUT ;
    USE SIGNAL ;
    PORT
      LAYER M4 ;
        RECT  17.088 10.32 17.28 10.344 ;
    END
  END i[78]
  PIN i[79]
    DIRECTION INPUT ;
    USE SIGNAL ;
    PORT
      LAYER M4 ;
        RECT  17.088 10.416 17.28 10.44 ;
    END
  END i[79]
  PIN i[7]
    DIRECTION INPUT ;
    USE SIGNAL ;
    PORT
      LAYER M4 ;
        RECT  17.088 2.928 17.28 2.952 ;
    END
  END i[7]
  PIN i[80]
    DIRECTION INPUT ;
    USE SIGNAL ;
    PORT
      LAYER M4 ;
        RECT  17.088 10.512 17.28 10.536 ;
    END
  END i[80]
  PIN i[81]
    DIRECTION INPUT ;
    USE SIGNAL ;
    PORT
      LAYER M4 ;
        RECT  17.088 10.608 17.28 10.632 ;
    END
  END i[81]
  PIN i[82]
    DIRECTION INPUT ;
    USE SIGNAL ;
    PORT
      LAYER M4 ;
        RECT  17.088 10.752 17.28 10.776 ;
    END
  END i[82]
  PIN i[83]
    DIRECTION INPUT ;
    USE SIGNAL ;
    PORT
      LAYER M4 ;
        RECT  17.088 10.848 17.28 10.872 ;
    END
  END i[83]
  PIN i[84]
    DIRECTION INPUT ;
    USE SIGNAL ;
    PORT
      LAYER M4 ;
        RECT  17.088 10.944 17.28 10.968 ;
    END
  END i[84]
  PIN i[85]
    DIRECTION INPUT ;
    USE SIGNAL ;
    PORT
      LAYER M4 ;
        RECT  17.088 11.04 17.28 11.064 ;
    END
  END i[85]
  PIN i[86]
    DIRECTION INPUT ;
    USE SIGNAL ;
    PORT
      LAYER M4 ;
        RECT  17.088 11.136 17.28 11.16 ;
    END
  END i[86]
  PIN i[87]
    DIRECTION INPUT ;
    USE SIGNAL ;
    PORT
      LAYER M4 ;
        RECT  17.088 11.232 17.28 11.256 ;
    END
  END i[87]
  PIN i[88]
    DIRECTION INPUT ;
    USE SIGNAL ;
    PORT
      LAYER M4 ;
        RECT  17.088 11.376 17.28 11.4 ;
    END
  END i[88]
  PIN i[89]
    DIRECTION INPUT ;
    USE SIGNAL ;
    PORT
      LAYER M4 ;
        RECT  17.088 11.472 17.28 11.496 ;
    END
  END i[89]
  PIN i[8]
    DIRECTION INPUT ;
    USE SIGNAL ;
    PORT
      LAYER M4 ;
        RECT  17.088 3.072 17.28 3.096 ;
    END
  END i[8]
  PIN i[90]
    DIRECTION INPUT ;
    USE SIGNAL ;
    PORT
      LAYER M4 ;
        RECT  17.088 11.568 17.28 11.592 ;
    END
  END i[90]
  PIN i[91]
    DIRECTION INPUT ;
    USE SIGNAL ;
    PORT
      LAYER M4 ;
        RECT  17.088 11.664 17.28 11.688 ;
    END
  END i[91]
  PIN i[92]
    DIRECTION INPUT ;
    USE SIGNAL ;
    PORT
      LAYER M4 ;
        RECT  17.088 11.76 17.28 11.784 ;
    END
  END i[92]
  PIN i[93]
    DIRECTION INPUT ;
    USE SIGNAL ;
    PORT
      LAYER M4 ;
        RECT  17.088 11.856 17.28 11.88 ;
    END
  END i[93]
  PIN i[94]
    DIRECTION INPUT ;
    USE SIGNAL ;
    PORT
      LAYER M4 ;
        RECT  17.088 12 17.28 12.024 ;
    END
  END i[94]
  PIN i[95]
    DIRECTION INPUT ;
    USE SIGNAL ;
    PORT
      LAYER M4 ;
        RECT  17.088 12.096 17.28 12.12 ;
    END
  END i[95]
  PIN i[96]
    DIRECTION INPUT ;
    USE SIGNAL ;
    PORT
      LAYER M4 ;
        RECT  17.088 12.192 17.28 12.216 ;
    END
  END i[96]
  PIN i[97]
    DIRECTION INPUT ;
    USE SIGNAL ;
    PORT
      LAYER M4 ;
        RECT  17.088 12.288 17.28 12.312 ;
    END
  END i[97]
  PIN i[98]
    DIRECTION INPUT ;
    USE SIGNAL ;
    PORT
      LAYER M4 ;
        RECT  17.088 12.384 17.28 12.408 ;
    END
  END i[98]
  PIN i[99]
    DIRECTION INPUT ;
    USE SIGNAL ;
    PORT
      LAYER M4 ;
        RECT  17.088 12.48 17.28 12.504 ;
    END
  END i[99]
  PIN i[9]
    DIRECTION INPUT ;
    USE SIGNAL ;
    PORT
      LAYER M4 ;
        RECT  17.088 3.168 17.28 3.192 ;
    END
  END i[9]
  PIN o[0]
    DIRECTION OUTPUT ;
    USE SIGNAL ;
    PORT
      LAYER M4 ;
        RECT  0 2.208 0.192 2.232 ;
    END
  END o[0]
  PIN o[100]
    DIRECTION OUTPUT ;
    USE SIGNAL ;
    PORT
      LAYER M4 ;
        RECT  0 12.576 0.192 12.6 ;
    END
  END o[100]
  PIN o[101]
    DIRECTION OUTPUT ;
    USE SIGNAL ;
    PORT
      LAYER M4 ;
        RECT  0 12.672 0.192 12.696 ;
    END
  END o[101]
  PIN o[102]
    DIRECTION OUTPUT ;
    USE SIGNAL ;
    PORT
      LAYER M4 ;
        RECT  0 12.768 0.192 12.792 ;
    END
  END o[102]
  PIN o[103]
    DIRECTION OUTPUT ;
    USE SIGNAL ;
    PORT
      LAYER M4 ;
        RECT  0 12.912 0.192 12.936 ;
    END
  END o[103]
  PIN o[104]
    DIRECTION OUTPUT ;
    USE SIGNAL ;
    PORT
      LAYER M4 ;
        RECT  0 13.008 0.192 13.032 ;
    END
  END o[104]
  PIN o[105]
    DIRECTION OUTPUT ;
    USE SIGNAL ;
    PORT
      LAYER M4 ;
        RECT  0 13.104 0.192 13.128 ;
    END
  END o[105]
  PIN o[106]
    DIRECTION OUTPUT ;
    USE SIGNAL ;
    PORT
      LAYER M4 ;
        RECT  0 13.2 0.192 13.224 ;
    END
  END o[106]
  PIN o[107]
    DIRECTION OUTPUT ;
    USE SIGNAL ;
    PORT
      LAYER M4 ;
        RECT  0 13.296 0.192 13.32 ;
    END
  END o[107]
  PIN o[108]
    DIRECTION OUTPUT ;
    USE SIGNAL ;
    PORT
      LAYER M4 ;
        RECT  0 13.392 0.192 13.416 ;
    END
  END o[108]
  PIN o[109]
    DIRECTION OUTPUT ;
    USE SIGNAL ;
    PORT
      LAYER M4 ;
        RECT  0 13.536 0.192 13.56 ;
    END
  END o[109]
  PIN o[10]
    DIRECTION OUTPUT ;
    USE SIGNAL ;
    PORT
      LAYER M4 ;
        RECT  0 3.264 0.192 3.288 ;
    END
  END o[10]
  PIN o[110]
    DIRECTION OUTPUT ;
    USE SIGNAL ;
    PORT
      LAYER M4 ;
        RECT  0 13.632 0.192 13.656 ;
    END
  END o[110]
  PIN o[111]
    DIRECTION OUTPUT ;
    USE SIGNAL ;
    PORT
      LAYER M4 ;
        RECT  0 13.728 0.192 13.752 ;
    END
  END o[111]
  PIN o[112]
    DIRECTION OUTPUT ;
    USE SIGNAL ;
    PORT
      LAYER M4 ;
        RECT  0 13.824 0.192 13.848 ;
    END
  END o[112]
  PIN o[113]
    DIRECTION OUTPUT ;
    USE SIGNAL ;
    PORT
      LAYER M4 ;
        RECT  0 13.92 0.192 13.944 ;
    END
  END o[113]
  PIN o[114]
    DIRECTION OUTPUT ;
    USE SIGNAL ;
    PORT
      LAYER M4 ;
        RECT  0 14.016 0.192 14.04 ;
    END
  END o[114]
  PIN o[115]
    DIRECTION OUTPUT ;
    USE SIGNAL ;
    PORT
      LAYER M4 ;
        RECT  0 14.16 0.192 14.184 ;
    END
  END o[115]
  PIN o[116]
    DIRECTION OUTPUT ;
    USE SIGNAL ;
    PORT
      LAYER M4 ;
        RECT  0 14.256 0.192 14.28 ;
    END
  END o[116]
  PIN o[117]
    DIRECTION OUTPUT ;
    USE SIGNAL ;
    PORT
      LAYER M4 ;
        RECT  0 14.352 0.192 14.376 ;
    END
  END o[117]
  PIN o[118]
    DIRECTION OUTPUT ;
    USE SIGNAL ;
    PORT
      LAYER M4 ;
        RECT  0 14.448 0.192 14.472 ;
    END
  END o[118]
  PIN o[119]
    DIRECTION OUTPUT ;
    USE SIGNAL ;
    PORT
      LAYER M4 ;
        RECT  0 14.544 0.192 14.568 ;
    END
  END o[119]
  PIN o[11]
    DIRECTION OUTPUT ;
    USE SIGNAL ;
    PORT
      LAYER M4 ;
        RECT  0 3.36 0.192 3.384 ;
    END
  END o[11]
  PIN o[120]
    DIRECTION OUTPUT ;
    USE SIGNAL ;
    PORT
      LAYER M4 ;
        RECT  0 14.64 0.192 14.664 ;
    END
  END o[120]
  PIN o[121]
    DIRECTION OUTPUT ;
    USE SIGNAL ;
    PORT
      LAYER M4 ;
        RECT  0 14.736 0.192 14.76 ;
    END
  END o[121]
  PIN o[122]
    DIRECTION OUTPUT ;
    USE SIGNAL ;
    PORT
      LAYER M4 ;
        RECT  0 14.88 0.192 14.904 ;
    END
  END o[122]
  PIN o[123]
    DIRECTION OUTPUT ;
    USE SIGNAL ;
    PORT
      LAYER M4 ;
        RECT  0 14.976 0.192 15 ;
    END
  END o[123]
  PIN o[124]
    DIRECTION OUTPUT ;
    USE SIGNAL ;
    PORT
      LAYER M4 ;
        RECT  0 15.072 0.192 15.096 ;
    END
  END o[124]
  PIN o[125]
    DIRECTION OUTPUT ;
    USE SIGNAL ;
    PORT
      LAYER M4 ;
        RECT  0 15.168 0.192 15.192 ;
    END
  END o[125]
  PIN o[126]
    DIRECTION OUTPUT ;
    USE SIGNAL ;
    PORT
      LAYER M4 ;
        RECT  0 15.264 0.192 15.288 ;
    END
  END o[126]
  PIN o[127]
    DIRECTION OUTPUT ;
    USE SIGNAL ;
    PORT
      LAYER M4 ;
        RECT  0 15.36 0.192 15.384 ;
    END
  END o[127]
  PIN o[128]
    DIRECTION OUTPUT ;
    USE SIGNAL ;
    PORT
      LAYER M4 ;
        RECT  0 15.504 0.192 15.528 ;
    END
  END o[128]
  PIN o[129]
    DIRECTION OUTPUT ;
    USE SIGNAL ;
    PORT
      LAYER M4 ;
        RECT  0 15.6 0.192 15.624 ;
    END
  END o[129]
  PIN o[12]
    DIRECTION OUTPUT ;
    USE SIGNAL ;
    PORT
      LAYER M4 ;
        RECT  0 3.456 0.192 3.48 ;
    END
  END o[12]
  PIN o[130]
    DIRECTION OUTPUT ;
    USE SIGNAL ;
    PORT
      LAYER M4 ;
        RECT  0 15.696 0.192 15.72 ;
    END
  END o[130]
  PIN o[131]
    DIRECTION OUTPUT ;
    USE SIGNAL ;
    PORT
      LAYER M4 ;
        RECT  0 15.792 0.192 15.816 ;
    END
  END o[131]
  PIN o[132]
    DIRECTION OUTPUT ;
    USE SIGNAL ;
    PORT
      LAYER M4 ;
        RECT  0 15.888 0.192 15.912 ;
    END
  END o[132]
  PIN o[133]
    DIRECTION OUTPUT ;
    USE SIGNAL ;
    PORT
      LAYER M4 ;
        RECT  0 15.984 0.192 16.008 ;
    END
  END o[133]
  PIN o[134]
    DIRECTION OUTPUT ;
    USE SIGNAL ;
    PORT
      LAYER M4 ;
        RECT  0 16.128 0.192 16.152 ;
    END
  END o[134]
  PIN o[135]
    DIRECTION OUTPUT ;
    USE SIGNAL ;
    PORT
      LAYER M4 ;
        RECT  0 16.224 0.192 16.248 ;
    END
  END o[135]
  PIN o[136]
    DIRECTION OUTPUT ;
    USE SIGNAL ;
    PORT
      LAYER M4 ;
        RECT  0 16.32 0.192 16.344 ;
    END
  END o[136]
  PIN o[137]
    DIRECTION OUTPUT ;
    USE SIGNAL ;
    PORT
      LAYER M4 ;
        RECT  0 16.416 0.192 16.44 ;
    END
  END o[137]
  PIN o[138]
    DIRECTION OUTPUT ;
    USE SIGNAL ;
    PORT
      LAYER M4 ;
        RECT  0 16.512 0.192 16.536 ;
    END
  END o[138]
  PIN o[139]
    DIRECTION OUTPUT ;
    USE SIGNAL ;
    PORT
      LAYER M4 ;
        RECT  0 16.608 0.192 16.632 ;
    END
  END o[139]
  PIN o[13]
    DIRECTION OUTPUT ;
    USE SIGNAL ;
    PORT
      LAYER M4 ;
        RECT  0 3.552 0.192 3.576 ;
    END
  END o[13]
  PIN o[140]
    DIRECTION OUTPUT ;
    USE SIGNAL ;
    PORT
      LAYER M4 ;
        RECT  0 16.704 0.192 16.728 ;
    END
  END o[140]
  PIN o[141]
    DIRECTION OUTPUT ;
    USE SIGNAL ;
    PORT
      LAYER M4 ;
        RECT  0 16.848 0.192 16.872 ;
    END
  END o[141]
  PIN o[142]
    DIRECTION OUTPUT ;
    USE SIGNAL ;
    PORT
      LAYER M4 ;
        RECT  0 16.944 0.192 16.968 ;
    END
  END o[142]
  PIN o[143]
    DIRECTION OUTPUT ;
    USE SIGNAL ;
    PORT
      LAYER M4 ;
        RECT  0 17.04 0.192 17.064 ;
    END
  END o[143]
  PIN o[144]
    DIRECTION OUTPUT ;
    USE SIGNAL ;
    PORT
      LAYER M4 ;
        RECT  0 17.136 0.192 17.16 ;
    END
  END o[144]
  PIN o[145]
    DIRECTION OUTPUT ;
    USE SIGNAL ;
    PORT
      LAYER M4 ;
        RECT  0 17.232 0.192 17.256 ;
    END
  END o[145]
  PIN o[146]
    DIRECTION OUTPUT ;
    USE SIGNAL ;
    PORT
      LAYER M4 ;
        RECT  0 17.328 0.192 17.352 ;
    END
  END o[146]
  PIN o[147]
    DIRECTION OUTPUT ;
    USE SIGNAL ;
    PORT
      LAYER M4 ;
        RECT  0 17.472 0.192 17.496 ;
    END
  END o[147]
  PIN o[148]
    DIRECTION OUTPUT ;
    USE SIGNAL ;
    PORT
      LAYER M4 ;
        RECT  0 17.568 0.192 17.592 ;
    END
  END o[148]
  PIN o[149]
    DIRECTION OUTPUT ;
    USE SIGNAL ;
    PORT
      LAYER M4 ;
        RECT  0 17.664 0.192 17.688 ;
    END
  END o[149]
  PIN o[14]
    DIRECTION OUTPUT ;
    USE SIGNAL ;
    PORT
      LAYER M4 ;
        RECT  0 3.696 0.192 3.72 ;
    END
  END o[14]
  PIN o[150]
    DIRECTION OUTPUT ;
    USE SIGNAL ;
    PORT
      LAYER M4 ;
        RECT  0 17.76 0.192 17.784 ;
    END
  END o[150]
  PIN o[151]
    DIRECTION OUTPUT ;
    USE SIGNAL ;
    PORT
      LAYER M4 ;
        RECT  0 17.856 0.192 17.88 ;
    END
  END o[151]
  PIN o[152]
    DIRECTION OUTPUT ;
    USE SIGNAL ;
    PORT
      LAYER M4 ;
        RECT  0 17.952 0.192 17.976 ;
    END
  END o[152]
  PIN o[153]
    DIRECTION OUTPUT ;
    USE SIGNAL ;
    PORT
      LAYER M4 ;
        RECT  0 18.096 0.192 18.12 ;
    END
  END o[153]
  PIN o[154]
    DIRECTION OUTPUT ;
    USE SIGNAL ;
    PORT
      LAYER M4 ;
        RECT  0 18.192 0.192 18.216 ;
    END
  END o[154]
  PIN o[155]
    DIRECTION OUTPUT ;
    USE SIGNAL ;
    PORT
      LAYER M4 ;
        RECT  0 18.288 0.192 18.312 ;
    END
  END o[155]
  PIN o[156]
    DIRECTION OUTPUT ;
    USE SIGNAL ;
    PORT
      LAYER M4 ;
        RECT  0 18.384 0.192 18.408 ;
    END
  END o[156]
  PIN o[157]
    DIRECTION OUTPUT ;
    USE SIGNAL ;
    PORT
      LAYER M4 ;
        RECT  0 18.48 0.192 18.504 ;
    END
  END o[157]
  PIN o[158]
    DIRECTION OUTPUT ;
    USE SIGNAL ;
    PORT
      LAYER M4 ;
        RECT  0 18.576 0.192 18.6 ;
    END
  END o[158]
  PIN o[159]
    DIRECTION OUTPUT ;
    USE SIGNAL ;
    PORT
      LAYER M4 ;
        RECT  0 18.672 0.192 18.696 ;
    END
  END o[159]
  PIN o[15]
    DIRECTION OUTPUT ;
    USE SIGNAL ;
    PORT
      LAYER M4 ;
        RECT  0 3.792 0.192 3.816 ;
    END
  END o[15]
  PIN o[160]
    DIRECTION OUTPUT ;
    USE SIGNAL ;
    PORT
      LAYER M4 ;
        RECT  0 18.816 0.192 18.84 ;
    END
  END o[160]
  PIN o[161]
    DIRECTION OUTPUT ;
    USE SIGNAL ;
    PORT
      LAYER M4 ;
        RECT  0 18.912 0.192 18.936 ;
    END
  END o[161]
  PIN o[162]
    DIRECTION OUTPUT ;
    USE SIGNAL ;
    PORT
      LAYER M4 ;
        RECT  0 19.008 0.192 19.032 ;
    END
  END o[162]
  PIN o[163]
    DIRECTION OUTPUT ;
    USE SIGNAL ;
    PORT
      LAYER M4 ;
        RECT  0 19.104 0.192 19.128 ;
    END
  END o[163]
  PIN o[164]
    DIRECTION OUTPUT ;
    USE SIGNAL ;
    PORT
      LAYER M4 ;
        RECT  0 19.2 0.192 19.224 ;
    END
  END o[164]
  PIN o[165]
    DIRECTION OUTPUT ;
    USE SIGNAL ;
    PORT
      LAYER M4 ;
        RECT  0 19.296 0.192 19.32 ;
    END
  END o[165]
  PIN o[166]
    DIRECTION OUTPUT ;
    USE SIGNAL ;
    PORT
      LAYER M4 ;
        RECT  0 19.44 0.192 19.464 ;
    END
  END o[166]
  PIN o[167]
    DIRECTION OUTPUT ;
    USE SIGNAL ;
    PORT
      LAYER M4 ;
        RECT  0 19.536 0.192 19.56 ;
    END
  END o[167]
  PIN o[168]
    DIRECTION OUTPUT ;
    USE SIGNAL ;
    PORT
      LAYER M4 ;
        RECT  0 19.632 0.192 19.656 ;
    END
  END o[168]
  PIN o[169]
    DIRECTION OUTPUT ;
    USE SIGNAL ;
    PORT
      LAYER M4 ;
        RECT  0 19.728 0.192 19.752 ;
    END
  END o[169]
  PIN o[16]
    DIRECTION OUTPUT ;
    USE SIGNAL ;
    PORT
      LAYER M4 ;
        RECT  0 3.888 0.192 3.912 ;
    END
  END o[16]
  PIN o[170]
    DIRECTION OUTPUT ;
    USE SIGNAL ;
    PORT
      LAYER M4 ;
        RECT  0 19.824 0.192 19.848 ;
    END
  END o[170]
  PIN o[171]
    DIRECTION OUTPUT ;
    USE SIGNAL ;
    PORT
      LAYER M4 ;
        RECT  0 19.92 0.192 19.944 ;
    END
  END o[171]
  PIN o[172]
    DIRECTION OUTPUT ;
    USE SIGNAL ;
    PORT
      LAYER M4 ;
        RECT  0 20.064 0.192 20.088 ;
    END
  END o[172]
  PIN o[173]
    DIRECTION OUTPUT ;
    USE SIGNAL ;
    PORT
      LAYER M4 ;
        RECT  0 20.16 0.192 20.184 ;
    END
  END o[173]
  PIN o[174]
    DIRECTION OUTPUT ;
    USE SIGNAL ;
    PORT
      LAYER M4 ;
        RECT  0 20.256 0.192 20.28 ;
    END
  END o[174]
  PIN o[175]
    DIRECTION OUTPUT ;
    USE SIGNAL ;
    PORT
      LAYER M4 ;
        RECT  0 20.352 0.192 20.376 ;
    END
  END o[175]
  PIN o[176]
    DIRECTION OUTPUT ;
    USE SIGNAL ;
    PORT
      LAYER M4 ;
        RECT  0 20.448 0.192 20.472 ;
    END
  END o[176]
  PIN o[177]
    DIRECTION OUTPUT ;
    USE SIGNAL ;
    PORT
      LAYER M4 ;
        RECT  0 20.544 0.192 20.568 ;
    END
  END o[177]
  PIN o[178]
    DIRECTION OUTPUT ;
    USE SIGNAL ;
    PORT
      LAYER M4 ;
        RECT  0 20.64 0.192 20.664 ;
    END
  END o[178]
  PIN o[179]
    DIRECTION OUTPUT ;
    USE SIGNAL ;
    PORT
      LAYER M4 ;
        RECT  0 20.784 0.192 20.808 ;
    END
  END o[179]
  PIN o[17]
    DIRECTION OUTPUT ;
    USE SIGNAL ;
    PORT
      LAYER M4 ;
        RECT  0 3.984 0.192 4.008 ;
    END
  END o[17]
  PIN o[180]
    DIRECTION OUTPUT ;
    USE SIGNAL ;
    PORT
      LAYER M4 ;
        RECT  0 20.88 0.192 20.904 ;
    END
  END o[180]
  PIN o[181]
    DIRECTION OUTPUT ;
    USE SIGNAL ;
    PORT
      LAYER M4 ;
        RECT  0 20.976 0.192 21 ;
    END
  END o[181]
  PIN o[182]
    DIRECTION OUTPUT ;
    USE SIGNAL ;
    PORT
      LAYER M4 ;
        RECT  0 21.072 0.192 21.096 ;
    END
  END o[182]
  PIN o[183]
    DIRECTION OUTPUT ;
    USE SIGNAL ;
    PORT
      LAYER M4 ;
        RECT  0 21.168 0.192 21.192 ;
    END
  END o[183]
  PIN o[184]
    DIRECTION OUTPUT ;
    USE SIGNAL ;
    PORT
      LAYER M4 ;
        RECT  0 21.264 0.192 21.288 ;
    END
  END o[184]
  PIN o[185]
    DIRECTION OUTPUT ;
    USE SIGNAL ;
    PORT
      LAYER M4 ;
        RECT  0 21.408 0.192 21.432 ;
    END
  END o[185]
  PIN o[186]
    DIRECTION OUTPUT ;
    USE SIGNAL ;
    PORT
      LAYER M4 ;
        RECT  0 21.504 0.192 21.528 ;
    END
  END o[186]
  PIN o[187]
    DIRECTION OUTPUT ;
    USE SIGNAL ;
    PORT
      LAYER M4 ;
        RECT  0 21.6 0.192 21.624 ;
    END
  END o[187]
  PIN o[188]
    DIRECTION OUTPUT ;
    USE SIGNAL ;
    PORT
      LAYER M4 ;
        RECT  0 21.696 0.192 21.72 ;
    END
  END o[188]
  PIN o[189]
    DIRECTION OUTPUT ;
    USE SIGNAL ;
    PORT
      LAYER M4 ;
        RECT  0 21.792 0.192 21.816 ;
    END
  END o[189]
  PIN o[18]
    DIRECTION OUTPUT ;
    USE SIGNAL ;
    PORT
      LAYER M4 ;
        RECT  0 4.08 0.192 4.104 ;
    END
  END o[18]
  PIN o[190]
    DIRECTION OUTPUT ;
    USE SIGNAL ;
    PORT
      LAYER M4 ;
        RECT  0 21.888 0.192 21.912 ;
    END
  END o[190]
  PIN o[191]
    DIRECTION OUTPUT ;
    USE SIGNAL ;
    PORT
      LAYER M4 ;
        RECT  0 22.032 0.192 22.056 ;
    END
  END o[191]
  PIN o[192]
    DIRECTION OUTPUT ;
    USE SIGNAL ;
    PORT
      LAYER M4 ;
        RECT  0 22.128 0.192 22.152 ;
    END
  END o[192]
  PIN o[193]
    DIRECTION OUTPUT ;
    USE SIGNAL ;
    PORT
      LAYER M4 ;
        RECT  0 22.224 0.192 22.248 ;
    END
  END o[193]
  PIN o[194]
    DIRECTION OUTPUT ;
    USE SIGNAL ;
    PORT
      LAYER M4 ;
        RECT  0 22.32 0.192 22.344 ;
    END
  END o[194]
  PIN o[195]
    DIRECTION OUTPUT ;
    USE SIGNAL ;
    PORT
      LAYER M4 ;
        RECT  0 22.416 0.192 22.44 ;
    END
  END o[195]
  PIN o[196]
    DIRECTION OUTPUT ;
    USE SIGNAL ;
    PORT
      LAYER M4 ;
        RECT  0 22.512 0.192 22.536 ;
    END
  END o[196]
  PIN o[197]
    DIRECTION OUTPUT ;
    USE SIGNAL ;
    PORT
      LAYER M4 ;
        RECT  0 22.608 0.192 22.632 ;
    END
  END o[197]
  PIN o[198]
    DIRECTION OUTPUT ;
    USE SIGNAL ;
    PORT
      LAYER M4 ;
        RECT  0 22.752 0.192 22.776 ;
    END
  END o[198]
  PIN o[199]
    DIRECTION OUTPUT ;
    USE SIGNAL ;
    PORT
      LAYER M4 ;
        RECT  0 22.848 0.192 22.872 ;
    END
  END o[199]
  PIN o[19]
    DIRECTION OUTPUT ;
    USE SIGNAL ;
    PORT
      LAYER M4 ;
        RECT  0 4.176 0.192 4.2 ;
    END
  END o[19]
  PIN o[1]
    DIRECTION OUTPUT ;
    USE SIGNAL ;
    PORT
      LAYER M4 ;
        RECT  0 2.304 0.192 2.328 ;
    END
  END o[1]
  PIN o[200]
    DIRECTION OUTPUT ;
    USE SIGNAL ;
    PORT
      LAYER M4 ;
        RECT  0 22.944 0.192 22.968 ;
    END
  END o[200]
  PIN o[201]
    DIRECTION OUTPUT ;
    USE SIGNAL ;
    PORT
      LAYER M4 ;
        RECT  0 23.04 0.192 23.064 ;
    END
  END o[201]
  PIN o[202]
    DIRECTION OUTPUT ;
    USE SIGNAL ;
    PORT
      LAYER M4 ;
        RECT  0 23.136 0.192 23.16 ;
    END
  END o[202]
  PIN o[203]
    DIRECTION OUTPUT ;
    USE SIGNAL ;
    PORT
      LAYER M4 ;
        RECT  0 23.232 0.192 23.256 ;
    END
  END o[203]
  PIN o[204]
    DIRECTION OUTPUT ;
    USE SIGNAL ;
    PORT
      LAYER M4 ;
        RECT  0 23.376 0.192 23.4 ;
    END
  END o[204]
  PIN o[205]
    DIRECTION OUTPUT ;
    USE SIGNAL ;
    PORT
      LAYER M4 ;
        RECT  0 23.472 0.192 23.496 ;
    END
  END o[205]
  PIN o[206]
    DIRECTION OUTPUT ;
    USE SIGNAL ;
    PORT
      LAYER M4 ;
        RECT  0 23.568 0.192 23.592 ;
    END
  END o[206]
  PIN o[207]
    DIRECTION OUTPUT ;
    USE SIGNAL ;
    PORT
      LAYER M4 ;
        RECT  0 23.664 0.192 23.688 ;
    END
  END o[207]
  PIN o[208]
    DIRECTION OUTPUT ;
    USE SIGNAL ;
    PORT
      LAYER M4 ;
        RECT  0 23.76 0.192 23.784 ;
    END
  END o[208]
  PIN o[209]
    DIRECTION OUTPUT ;
    USE SIGNAL ;
    PORT
      LAYER M4 ;
        RECT  0 23.856 0.192 23.88 ;
    END
  END o[209]
  PIN o[20]
    DIRECTION OUTPUT ;
    USE SIGNAL ;
    PORT
      LAYER M4 ;
        RECT  0 4.272 0.192 4.296 ;
    END
  END o[20]
  PIN o[210]
    DIRECTION OUTPUT ;
    USE SIGNAL ;
    PORT
      LAYER M4 ;
        RECT  0 24 0.192 24.024 ;
    END
  END o[210]
  PIN o[211]
    DIRECTION OUTPUT ;
    USE SIGNAL ;
    PORT
      LAYER M4 ;
        RECT  0 24.096 0.192 24.12 ;
    END
  END o[211]
  PIN o[212]
    DIRECTION OUTPUT ;
    USE SIGNAL ;
    PORT
      LAYER M4 ;
        RECT  0 24.192 0.192 24.216 ;
    END
  END o[212]
  PIN o[213]
    DIRECTION OUTPUT ;
    USE SIGNAL ;
    PORT
      LAYER M4 ;
        RECT  0 24.288 0.192 24.312 ;
    END
  END o[213]
  PIN o[214]
    DIRECTION OUTPUT ;
    USE SIGNAL ;
    PORT
      LAYER M4 ;
        RECT  0 24.384 0.192 24.408 ;
    END
  END o[214]
  PIN o[215]
    DIRECTION OUTPUT ;
    USE SIGNAL ;
    PORT
      LAYER M4 ;
        RECT  0 24.48 0.192 24.504 ;
    END
  END o[215]
  PIN o[216]
    DIRECTION OUTPUT ;
    USE SIGNAL ;
    PORT
      LAYER M4 ;
        RECT  0 24.576 0.192 24.6 ;
    END
  END o[216]
  PIN o[217]
    DIRECTION OUTPUT ;
    USE SIGNAL ;
    PORT
      LAYER M4 ;
        RECT  0 24.72 0.192 24.744 ;
    END
  END o[217]
  PIN o[218]
    DIRECTION OUTPUT ;
    USE SIGNAL ;
    PORT
      LAYER M4 ;
        RECT  0 24.816 0.192 24.84 ;
    END
  END o[218]
  PIN o[219]
    DIRECTION OUTPUT ;
    USE SIGNAL ;
    PORT
      LAYER M4 ;
        RECT  0 24.912 0.192 24.936 ;
    END
  END o[219]
  PIN o[21]
    DIRECTION OUTPUT ;
    USE SIGNAL ;
    PORT
      LAYER M4 ;
        RECT  0 4.416 0.192 4.44 ;
    END
  END o[21]
  PIN o[220]
    DIRECTION OUTPUT ;
    USE SIGNAL ;
    PORT
      LAYER M4 ;
        RECT  0 25.008 0.192 25.032 ;
    END
  END o[220]
  PIN o[221]
    DIRECTION OUTPUT ;
    USE SIGNAL ;
    PORT
      LAYER M4 ;
        RECT  0 25.104 0.192 25.128 ;
    END
  END o[221]
  PIN o[222]
    DIRECTION OUTPUT ;
    USE SIGNAL ;
    PORT
      LAYER M4 ;
        RECT  0 25.2 0.192 25.224 ;
    END
  END o[222]
  PIN o[223]
    DIRECTION OUTPUT ;
    USE SIGNAL ;
    PORT
      LAYER M4 ;
        RECT  0 25.344 0.192 25.368 ;
    END
  END o[223]
  PIN o[224]
    DIRECTION OUTPUT ;
    USE SIGNAL ;
    PORT
      LAYER M4 ;
        RECT  0 25.44 0.192 25.464 ;
    END
  END o[224]
  PIN o[225]
    DIRECTION OUTPUT ;
    USE SIGNAL ;
    PORT
      LAYER M4 ;
        RECT  0 25.536 0.192 25.56 ;
    END
  END o[225]
  PIN o[226]
    DIRECTION OUTPUT ;
    USE SIGNAL ;
    PORT
      LAYER M4 ;
        RECT  0 25.632 0.192 25.656 ;
    END
  END o[226]
  PIN o[227]
    DIRECTION OUTPUT ;
    USE SIGNAL ;
    PORT
      LAYER M4 ;
        RECT  0 25.728 0.192 25.752 ;
    END
  END o[227]
  PIN o[228]
    DIRECTION OUTPUT ;
    USE SIGNAL ;
    PORT
      LAYER M4 ;
        RECT  0 25.824 0.192 25.848 ;
    END
  END o[228]
  PIN o[229]
    DIRECTION OUTPUT ;
    USE SIGNAL ;
    PORT
      LAYER M4 ;
        RECT  0 25.968 0.192 25.992 ;
    END
  END o[229]
  PIN o[22]
    DIRECTION OUTPUT ;
    USE SIGNAL ;
    PORT
      LAYER M4 ;
        RECT  0 4.512 0.192 4.536 ;
    END
  END o[22]
  PIN o[230]
    DIRECTION OUTPUT ;
    USE SIGNAL ;
    PORT
      LAYER M4 ;
        RECT  0 26.064 0.192 26.088 ;
    END
  END o[230]
  PIN o[231]
    DIRECTION OUTPUT ;
    USE SIGNAL ;
    PORT
      LAYER M4 ;
        RECT  0 26.16 0.192 26.184 ;
    END
  END o[231]
  PIN o[232]
    DIRECTION OUTPUT ;
    USE SIGNAL ;
    PORT
      LAYER M4 ;
        RECT  0 26.256 0.192 26.28 ;
    END
  END o[232]
  PIN o[233]
    DIRECTION OUTPUT ;
    USE SIGNAL ;
    PORT
      LAYER M4 ;
        RECT  0 26.352 0.192 26.376 ;
    END
  END o[233]
  PIN o[234]
    DIRECTION OUTPUT ;
    USE SIGNAL ;
    PORT
      LAYER M4 ;
        RECT  0 26.448 0.192 26.472 ;
    END
  END o[234]
  PIN o[235]
    DIRECTION OUTPUT ;
    USE SIGNAL ;
    PORT
      LAYER M4 ;
        RECT  0 26.544 0.192 26.568 ;
    END
  END o[235]
  PIN o[236]
    DIRECTION OUTPUT ;
    USE SIGNAL ;
    PORT
      LAYER M4 ;
        RECT  0 26.688 0.192 26.712 ;
    END
  END o[236]
  PIN o[237]
    DIRECTION OUTPUT ;
    USE SIGNAL ;
    PORT
      LAYER M4 ;
        RECT  0 26.784 0.192 26.808 ;
    END
  END o[237]
  PIN o[238]
    DIRECTION OUTPUT ;
    USE SIGNAL ;
    PORT
      LAYER M4 ;
        RECT  0 26.88 0.192 26.904 ;
    END
  END o[238]
  PIN o[239]
    DIRECTION OUTPUT ;
    USE SIGNAL ;
    PORT
      LAYER M4 ;
        RECT  0 26.976 0.192 27 ;
    END
  END o[239]
  PIN o[23]
    DIRECTION OUTPUT ;
    USE SIGNAL ;
    PORT
      LAYER M4 ;
        RECT  0 4.608 0.192 4.632 ;
    END
  END o[23]
  PIN o[240]
    DIRECTION OUTPUT ;
    USE SIGNAL ;
    PORT
      LAYER M4 ;
        RECT  0 27.072 0.192 27.096 ;
    END
  END o[240]
  PIN o[241]
    DIRECTION OUTPUT ;
    USE SIGNAL ;
    PORT
      LAYER M4 ;
        RECT  0 27.168 0.192 27.192 ;
    END
  END o[241]
  PIN o[242]
    DIRECTION OUTPUT ;
    USE SIGNAL ;
    PORT
      LAYER M4 ;
        RECT  0 27.312 0.192 27.336 ;
    END
  END o[242]
  PIN o[243]
    DIRECTION OUTPUT ;
    USE SIGNAL ;
    PORT
      LAYER M4 ;
        RECT  0 27.408 0.192 27.432 ;
    END
  END o[243]
  PIN o[244]
    DIRECTION OUTPUT ;
    USE SIGNAL ;
    PORT
      LAYER M4 ;
        RECT  0 27.504 0.192 27.528 ;
    END
  END o[244]
  PIN o[245]
    DIRECTION OUTPUT ;
    USE SIGNAL ;
    PORT
      LAYER M4 ;
        RECT  0 27.6 0.192 27.624 ;
    END
  END o[245]
  PIN o[246]
    DIRECTION OUTPUT ;
    USE SIGNAL ;
    PORT
      LAYER M4 ;
        RECT  0 27.696 0.192 27.72 ;
    END
  END o[246]
  PIN o[247]
    DIRECTION OUTPUT ;
    USE SIGNAL ;
    PORT
      LAYER M4 ;
        RECT  0 27.792 0.192 27.816 ;
    END
  END o[247]
  PIN o[248]
    DIRECTION OUTPUT ;
    USE SIGNAL ;
    PORT
      LAYER M4 ;
        RECT  0 27.936 0.192 27.96 ;
    END
  END o[248]
  PIN o[249]
    DIRECTION OUTPUT ;
    USE SIGNAL ;
    PORT
      LAYER M4 ;
        RECT  0 28.032 0.192 28.056 ;
    END
  END o[249]
  PIN o[24]
    DIRECTION OUTPUT ;
    USE SIGNAL ;
    PORT
      LAYER M4 ;
        RECT  0 4.704 0.192 4.728 ;
    END
  END o[24]
  PIN o[250]
    DIRECTION OUTPUT ;
    USE SIGNAL ;
    PORT
      LAYER M4 ;
        RECT  0 28.128 0.192 28.152 ;
    END
  END o[250]
  PIN o[251]
    DIRECTION OUTPUT ;
    USE SIGNAL ;
    PORT
      LAYER M4 ;
        RECT  0 28.224 0.192 28.248 ;
    END
  END o[251]
  PIN o[252]
    DIRECTION OUTPUT ;
    USE SIGNAL ;
    PORT
      LAYER M4 ;
        RECT  0 28.32 0.192 28.344 ;
    END
  END o[252]
  PIN o[253]
    DIRECTION OUTPUT ;
    USE SIGNAL ;
    PORT
      LAYER M4 ;
        RECT  0 28.416 0.192 28.44 ;
    END
  END o[253]
  PIN o[254]
    DIRECTION OUTPUT ;
    USE SIGNAL ;
    PORT
      LAYER M4 ;
        RECT  0 28.512 0.192 28.536 ;
    END
  END o[254]
  PIN o[255]
    DIRECTION OUTPUT ;
    USE SIGNAL ;
    PORT
      LAYER M4 ;
        RECT  0 28.656 0.192 28.68 ;
    END
  END o[255]
  PIN o[256]
    DIRECTION OUTPUT ;
    USE SIGNAL ;
    PORT
      LAYER M4 ;
        RECT  0 28.752 0.192 28.776 ;
    END
  END o[256]
  PIN o[257]
    DIRECTION OUTPUT ;
    USE SIGNAL ;
    PORT
      LAYER M4 ;
        RECT  0 28.848 0.192 28.872 ;
    END
  END o[257]
  PIN o[258]
    DIRECTION OUTPUT ;
    USE SIGNAL ;
    PORT
      LAYER M4 ;
        RECT  0 28.944 0.192 28.968 ;
    END
  END o[258]
  PIN o[259]
    DIRECTION OUTPUT ;
    USE SIGNAL ;
    PORT
      LAYER M4 ;
        RECT  0 29.04 0.192 29.064 ;
    END
  END o[259]
  PIN o[25]
    DIRECTION OUTPUT ;
    USE SIGNAL ;
    PORT
      LAYER M4 ;
        RECT  0 4.8 0.192 4.824 ;
    END
  END o[25]
  PIN o[260]
    DIRECTION OUTPUT ;
    USE SIGNAL ;
    PORT
      LAYER M4 ;
        RECT  0 29.136 0.192 29.16 ;
    END
  END o[260]
  PIN o[261]
    DIRECTION OUTPUT ;
    USE SIGNAL ;
    PORT
      LAYER M4 ;
        RECT  0 29.28 0.192 29.304 ;
    END
  END o[261]
  PIN o[262]
    DIRECTION OUTPUT ;
    USE SIGNAL ;
    PORT
      LAYER M4 ;
        RECT  0 29.376 0.192 29.4 ;
    END
  END o[262]
  PIN o[263]
    DIRECTION OUTPUT ;
    USE SIGNAL ;
    PORT
      LAYER M4 ;
        RECT  0 29.472 0.192 29.496 ;
    END
  END o[263]
  PIN o[264]
    DIRECTION OUTPUT ;
    USE SIGNAL ;
    PORT
      LAYER M4 ;
        RECT  0 29.568 0.192 29.592 ;
    END
  END o[264]
  PIN o[265]
    DIRECTION OUTPUT ;
    USE SIGNAL ;
    PORT
      LAYER M4 ;
        RECT  0 29.664 0.192 29.688 ;
    END
  END o[265]
  PIN o[266]
    DIRECTION OUTPUT ;
    USE SIGNAL ;
    PORT
      LAYER M4 ;
        RECT  0 29.76 0.192 29.784 ;
    END
  END o[266]
  PIN o[267]
    DIRECTION OUTPUT ;
    USE SIGNAL ;
    PORT
      LAYER M4 ;
        RECT  0 29.904 0.192 29.928 ;
    END
  END o[267]
  PIN o[268]
    DIRECTION OUTPUT ;
    USE SIGNAL ;
    PORT
      LAYER M4 ;
        RECT  0 30 0.192 30.024 ;
    END
  END o[268]
  PIN o[269]
    DIRECTION OUTPUT ;
    USE SIGNAL ;
    PORT
      LAYER M4 ;
        RECT  0 30.096 0.192 30.12 ;
    END
  END o[269]
  PIN o[26]
    DIRECTION OUTPUT ;
    USE SIGNAL ;
    PORT
      LAYER M4 ;
        RECT  0 4.896 0.192 4.92 ;
    END
  END o[26]
  PIN o[270]
    DIRECTION OUTPUT ;
    USE SIGNAL ;
    PORT
      LAYER M4 ;
        RECT  0 30.192 0.192 30.216 ;
    END
  END o[270]
  PIN o[271]
    DIRECTION OUTPUT ;
    USE SIGNAL ;
    PORT
      LAYER M4 ;
        RECT  0 30.288 0.192 30.312 ;
    END
  END o[271]
  PIN o[272]
    DIRECTION OUTPUT ;
    USE SIGNAL ;
    PORT
      LAYER M4 ;
        RECT  0 30.384 0.192 30.408 ;
    END
  END o[272]
  PIN o[273]
    DIRECTION OUTPUT ;
    USE SIGNAL ;
    PORT
      LAYER M4 ;
        RECT  0 30.48 0.192 30.504 ;
    END
  END o[273]
  PIN o[274]
    DIRECTION OUTPUT ;
    USE SIGNAL ;
    PORT
      LAYER M4 ;
        RECT  0 30.624 0.192 30.648 ;
    END
  END o[274]
  PIN o[275]
    DIRECTION OUTPUT ;
    USE SIGNAL ;
    PORT
      LAYER M4 ;
        RECT  0 30.72 0.192 30.744 ;
    END
  END o[275]
  PIN o[276]
    DIRECTION OUTPUT ;
    USE SIGNAL ;
    PORT
      LAYER M4 ;
        RECT  0 30.816 0.192 30.84 ;
    END
  END o[276]
  PIN o[277]
    DIRECTION OUTPUT ;
    USE SIGNAL ;
    PORT
      LAYER M4 ;
        RECT  0 30.912 0.192 30.936 ;
    END
  END o[277]
  PIN o[278]
    DIRECTION OUTPUT ;
    USE SIGNAL ;
    PORT
      LAYER M4 ;
        RECT  0 31.008 0.192 31.032 ;
    END
  END o[278]
  PIN o[279]
    DIRECTION OUTPUT ;
    USE SIGNAL ;
    PORT
      LAYER M4 ;
        RECT  0 31.104 0.192 31.128 ;
    END
  END o[279]
  PIN o[27]
    DIRECTION OUTPUT ;
    USE SIGNAL ;
    PORT
      LAYER M4 ;
        RECT  0 5.04 0.192 5.064 ;
    END
  END o[27]
  PIN o[280]
    DIRECTION OUTPUT ;
    USE SIGNAL ;
    PORT
      LAYER M4 ;
        RECT  0 31.248 0.192 31.272 ;
    END
  END o[280]
  PIN o[281]
    DIRECTION OUTPUT ;
    USE SIGNAL ;
    PORT
      LAYER M4 ;
        RECT  0 31.344 0.192 31.368 ;
    END
  END o[281]
  PIN o[282]
    DIRECTION OUTPUT ;
    USE SIGNAL ;
    PORT
      LAYER M4 ;
        RECT  0 31.44 0.192 31.464 ;
    END
  END o[282]
  PIN o[283]
    DIRECTION OUTPUT ;
    USE SIGNAL ;
    PORT
      LAYER M4 ;
        RECT  0 31.536 0.192 31.56 ;
    END
  END o[283]
  PIN o[284]
    DIRECTION OUTPUT ;
    USE SIGNAL ;
    PORT
      LAYER M4 ;
        RECT  0 31.632 0.192 31.656 ;
    END
  END o[284]
  PIN o[285]
    DIRECTION OUTPUT ;
    USE SIGNAL ;
    PORT
      LAYER M4 ;
        RECT  0 31.728 0.192 31.752 ;
    END
  END o[285]
  PIN o[286]
    DIRECTION OUTPUT ;
    USE SIGNAL ;
    PORT
      LAYER M4 ;
        RECT  0 31.872 0.192 31.896 ;
    END
  END o[286]
  PIN o[287]
    DIRECTION OUTPUT ;
    USE SIGNAL ;
    PORT
      LAYER M4 ;
        RECT  0 31.968 0.192 31.992 ;
    END
  END o[287]
  PIN o[288]
    DIRECTION OUTPUT ;
    USE SIGNAL ;
    PORT
      LAYER M4 ;
        RECT  0 32.064 0.192 32.088 ;
    END
  END o[288]
  PIN o[289]
    DIRECTION OUTPUT ;
    USE SIGNAL ;
    PORT
      LAYER M4 ;
        RECT  0 32.16 0.192 32.184 ;
    END
  END o[289]
  PIN o[28]
    DIRECTION OUTPUT ;
    USE SIGNAL ;
    PORT
      LAYER M4 ;
        RECT  0 5.136 0.192 5.16 ;
    END
  END o[28]
  PIN o[290]
    DIRECTION OUTPUT ;
    USE SIGNAL ;
    PORT
      LAYER M4 ;
        RECT  0 32.256 0.192 32.28 ;
    END
  END o[290]
  PIN o[291]
    DIRECTION OUTPUT ;
    USE SIGNAL ;
    PORT
      LAYER M4 ;
        RECT  0 32.352 0.192 32.376 ;
    END
  END o[291]
  PIN o[292]
    DIRECTION OUTPUT ;
    USE SIGNAL ;
    PORT
      LAYER M4 ;
        RECT  0 32.448 0.192 32.472 ;
    END
  END o[292]
  PIN o[293]
    DIRECTION OUTPUT ;
    USE SIGNAL ;
    PORT
      LAYER M4 ;
        RECT  0 32.592 0.192 32.616 ;
    END
  END o[293]
  PIN o[294]
    DIRECTION OUTPUT ;
    USE SIGNAL ;
    PORT
      LAYER M4 ;
        RECT  0 32.688 0.192 32.712 ;
    END
  END o[294]
  PIN o[295]
    DIRECTION OUTPUT ;
    USE SIGNAL ;
    PORT
      LAYER M4 ;
        RECT  0 32.784 0.192 32.808 ;
    END
  END o[295]
  PIN o[296]
    DIRECTION OUTPUT ;
    USE SIGNAL ;
    PORT
      LAYER M4 ;
        RECT  0 32.88 0.192 32.904 ;
    END
  END o[296]
  PIN o[297]
    DIRECTION OUTPUT ;
    USE SIGNAL ;
    PORT
      LAYER M4 ;
        RECT  0 32.976 0.192 33 ;
    END
  END o[297]
  PIN o[298]
    DIRECTION OUTPUT ;
    USE SIGNAL ;
    PORT
      LAYER M4 ;
        RECT  0 33.072 0.192 33.096 ;
    END
  END o[298]
  PIN o[299]
    DIRECTION OUTPUT ;
    USE SIGNAL ;
    PORT
      LAYER M4 ;
        RECT  0 33.216 0.192 33.24 ;
    END
  END o[299]
  PIN o[29]
    DIRECTION OUTPUT ;
    USE SIGNAL ;
    PORT
      LAYER M4 ;
        RECT  0 5.232 0.192 5.256 ;
    END
  END o[29]
  PIN o[2]
    DIRECTION OUTPUT ;
    USE SIGNAL ;
    PORT
      LAYER M4 ;
        RECT  0 2.448 0.192 2.472 ;
    END
  END o[2]
  PIN o[300]
    DIRECTION OUTPUT ;
    USE SIGNAL ;
    PORT
      LAYER M4 ;
        RECT  0 33.312 0.192 33.336 ;
    END
  END o[300]
  PIN o[301]
    DIRECTION OUTPUT ;
    USE SIGNAL ;
    PORT
      LAYER M4 ;
        RECT  0 33.408 0.192 33.432 ;
    END
  END o[301]
  PIN o[302]
    DIRECTION OUTPUT ;
    USE SIGNAL ;
    PORT
      LAYER M4 ;
        RECT  0 33.504 0.192 33.528 ;
    END
  END o[302]
  PIN o[303]
    DIRECTION OUTPUT ;
    USE SIGNAL ;
    PORT
      LAYER M4 ;
        RECT  0 33.6 0.192 33.624 ;
    END
  END o[303]
  PIN o[304]
    DIRECTION OUTPUT ;
    USE SIGNAL ;
    PORT
      LAYER M4 ;
        RECT  0 33.696 0.192 33.72 ;
    END
  END o[304]
  PIN o[305]
    DIRECTION OUTPUT ;
    USE SIGNAL ;
    PORT
      LAYER M4 ;
        RECT  0 33.84 0.192 33.864 ;
    END
  END o[305]
  PIN o[306]
    DIRECTION OUTPUT ;
    USE SIGNAL ;
    PORT
      LAYER M4 ;
        RECT  0 33.936 0.192 33.96 ;
    END
  END o[306]
  PIN o[307]
    DIRECTION OUTPUT ;
    USE SIGNAL ;
    PORT
      LAYER M4 ;
        RECT  0 34.032 0.192 34.056 ;
    END
  END o[307]
  PIN o[308]
    DIRECTION OUTPUT ;
    USE SIGNAL ;
    PORT
      LAYER M4 ;
        RECT  0 34.128 0.192 34.152 ;
    END
  END o[308]
  PIN o[309]
    DIRECTION OUTPUT ;
    USE SIGNAL ;
    PORT
      LAYER M4 ;
        RECT  0 34.224 0.192 34.248 ;
    END
  END o[309]
  PIN o[30]
    DIRECTION OUTPUT ;
    USE SIGNAL ;
    PORT
      LAYER M4 ;
        RECT  0 5.328 0.192 5.352 ;
    END
  END o[30]
  PIN o[310]
    DIRECTION OUTPUT ;
    USE SIGNAL ;
    PORT
      LAYER M4 ;
        RECT  0 34.32 0.192 34.344 ;
    END
  END o[310]
  PIN o[311]
    DIRECTION OUTPUT ;
    USE SIGNAL ;
    PORT
      LAYER M4 ;
        RECT  0 34.416 0.192 34.44 ;
    END
  END o[311]
  PIN o[312]
    DIRECTION OUTPUT ;
    USE SIGNAL ;
    PORT
      LAYER M4 ;
        RECT  0 34.56 0.192 34.584 ;
    END
  END o[312]
  PIN o[313]
    DIRECTION OUTPUT ;
    USE SIGNAL ;
    PORT
      LAYER M4 ;
        RECT  0 34.656 0.192 34.68 ;
    END
  END o[313]
  PIN o[314]
    DIRECTION OUTPUT ;
    USE SIGNAL ;
    PORT
      LAYER M4 ;
        RECT  0 34.752 0.192 34.776 ;
    END
  END o[314]
  PIN o[315]
    DIRECTION OUTPUT ;
    USE SIGNAL ;
    PORT
      LAYER M4 ;
        RECT  0 34.848 0.192 34.872 ;
    END
  END o[315]
  PIN o[316]
    DIRECTION OUTPUT ;
    USE SIGNAL ;
    PORT
      LAYER M4 ;
        RECT  0 34.944 0.192 34.968 ;
    END
  END o[316]
  PIN o[317]
    DIRECTION OUTPUT ;
    USE SIGNAL ;
    PORT
      LAYER M4 ;
        RECT  0 35.04 0.192 35.064 ;
    END
  END o[317]
  PIN o[318]
    DIRECTION OUTPUT ;
    USE SIGNAL ;
    PORT
      LAYER M4 ;
        RECT  0 35.184 0.192 35.208 ;
    END
  END o[318]
  PIN o[319]
    DIRECTION OUTPUT ;
    USE SIGNAL ;
    PORT
      LAYER M4 ;
        RECT  0 35.28 0.192 35.304 ;
    END
  END o[319]
  PIN o[31]
    DIRECTION OUTPUT ;
    USE SIGNAL ;
    PORT
      LAYER M4 ;
        RECT  0 5.424 0.192 5.448 ;
    END
  END o[31]
  PIN o[320]
    DIRECTION OUTPUT ;
    USE SIGNAL ;
    PORT
      LAYER M4 ;
        RECT  0 35.376 0.192 35.4 ;
    END
  END o[320]
  PIN o[321]
    DIRECTION OUTPUT ;
    USE SIGNAL ;
    PORT
      LAYER M4 ;
        RECT  0 35.472 0.192 35.496 ;
    END
  END o[321]
  PIN o[322]
    DIRECTION OUTPUT ;
    USE SIGNAL ;
    PORT
      LAYER M4 ;
        RECT  0 35.568 0.192 35.592 ;
    END
  END o[322]
  PIN o[323]
    DIRECTION OUTPUT ;
    USE SIGNAL ;
    PORT
      LAYER M4 ;
        RECT  0 35.664 0.192 35.688 ;
    END
  END o[323]
  PIN o[324]
    DIRECTION OUTPUT ;
    USE SIGNAL ;
    PORT
      LAYER M4 ;
        RECT  0 35.808 0.192 35.832 ;
    END
  END o[324]
  PIN o[325]
    DIRECTION OUTPUT ;
    USE SIGNAL ;
    PORT
      LAYER M4 ;
        RECT  0 35.904 0.192 35.928 ;
    END
  END o[325]
  PIN o[326]
    DIRECTION OUTPUT ;
    USE SIGNAL ;
    PORT
      LAYER M4 ;
        RECT  0 36 0.192 36.024 ;
    END
  END o[326]
  PIN o[327]
    DIRECTION OUTPUT ;
    USE SIGNAL ;
    PORT
      LAYER M4 ;
        RECT  0 36.096 0.192 36.12 ;
    END
  END o[327]
  PIN o[328]
    DIRECTION OUTPUT ;
    USE SIGNAL ;
    PORT
      LAYER M4 ;
        RECT  0 36.192 0.192 36.216 ;
    END
  END o[328]
  PIN o[329]
    DIRECTION OUTPUT ;
    USE SIGNAL ;
    PORT
      LAYER M4 ;
        RECT  0 36.288 0.192 36.312 ;
    END
  END o[329]
  PIN o[32]
    DIRECTION OUTPUT ;
    USE SIGNAL ;
    PORT
      LAYER M4 ;
        RECT  0 5.52 0.192 5.544 ;
    END
  END o[32]
  PIN o[330]
    DIRECTION OUTPUT ;
    USE SIGNAL ;
    PORT
      LAYER M4 ;
        RECT  0 36.384 0.192 36.408 ;
    END
  END o[330]
  PIN o[331]
    DIRECTION OUTPUT ;
    USE SIGNAL ;
    PORT
      LAYER M4 ;
        RECT  0 36.528 0.192 36.552 ;
    END
  END o[331]
  PIN o[332]
    DIRECTION OUTPUT ;
    USE SIGNAL ;
    PORT
      LAYER M4 ;
        RECT  0 36.624 0.192 36.648 ;
    END
  END o[332]
  PIN o[333]
    DIRECTION OUTPUT ;
    USE SIGNAL ;
    PORT
      LAYER M4 ;
        RECT  0 36.72 0.192 36.744 ;
    END
  END o[333]
  PIN o[334]
    DIRECTION OUTPUT ;
    USE SIGNAL ;
    PORT
      LAYER M4 ;
        RECT  0 36.816 0.192 36.84 ;
    END
  END o[334]
  PIN o[335]
    DIRECTION OUTPUT ;
    USE SIGNAL ;
    PORT
      LAYER M4 ;
        RECT  0 36.912 0.192 36.936 ;
    END
  END o[335]
  PIN o[336]
    DIRECTION OUTPUT ;
    USE SIGNAL ;
    PORT
      LAYER M4 ;
        RECT  0 37.008 0.192 37.032 ;
    END
  END o[336]
  PIN o[337]
    DIRECTION OUTPUT ;
    USE SIGNAL ;
    PORT
      LAYER M4 ;
        RECT  0 37.152 0.192 37.176 ;
    END
  END o[337]
  PIN o[338]
    DIRECTION OUTPUT ;
    USE SIGNAL ;
    PORT
      LAYER M4 ;
        RECT  0 37.248 0.192 37.272 ;
    END
  END o[338]
  PIN o[339]
    DIRECTION OUTPUT ;
    USE SIGNAL ;
    PORT
      LAYER M4 ;
        RECT  0 37.344 0.192 37.368 ;
    END
  END o[339]
  PIN o[33]
    DIRECTION OUTPUT ;
    USE SIGNAL ;
    PORT
      LAYER M4 ;
        RECT  0 5.664 0.192 5.688 ;
    END
  END o[33]
  PIN o[340]
    DIRECTION OUTPUT ;
    USE SIGNAL ;
    PORT
      LAYER M4 ;
        RECT  0 37.44 0.192 37.464 ;
    END
  END o[340]
  PIN o[341]
    DIRECTION OUTPUT ;
    USE SIGNAL ;
    PORT
      LAYER M4 ;
        RECT  0 37.536 0.192 37.56 ;
    END
  END o[341]
  PIN o[342]
    DIRECTION OUTPUT ;
    USE SIGNAL ;
    PORT
      LAYER M4 ;
        RECT  0 37.632 0.192 37.656 ;
    END
  END o[342]
  PIN o[343]
    DIRECTION OUTPUT ;
    USE SIGNAL ;
    PORT
      LAYER M4 ;
        RECT  0 37.776 0.192 37.8 ;
    END
  END o[343]
  PIN o[344]
    DIRECTION OUTPUT ;
    USE SIGNAL ;
    PORT
      LAYER M4 ;
        RECT  0 37.872 0.192 37.896 ;
    END
  END o[344]
  PIN o[345]
    DIRECTION OUTPUT ;
    USE SIGNAL ;
    PORT
      LAYER M4 ;
        RECT  0 37.968 0.192 37.992 ;
    END
  END o[345]
  PIN o[346]
    DIRECTION OUTPUT ;
    USE SIGNAL ;
    PORT
      LAYER M4 ;
        RECT  0 38.064 0.192 38.088 ;
    END
  END o[346]
  PIN o[347]
    DIRECTION OUTPUT ;
    USE SIGNAL ;
    PORT
      LAYER M4 ;
        RECT  0 38.16 0.192 38.184 ;
    END
  END o[347]
  PIN o[348]
    DIRECTION OUTPUT ;
    USE SIGNAL ;
    PORT
      LAYER M4 ;
        RECT  0 38.256 0.192 38.28 ;
    END
  END o[348]
  PIN o[349]
    DIRECTION OUTPUT ;
    USE SIGNAL ;
    PORT
      LAYER M4 ;
        RECT  0 38.352 0.192 38.376 ;
    END
  END o[349]
  PIN o[34]
    DIRECTION OUTPUT ;
    USE SIGNAL ;
    PORT
      LAYER M4 ;
        RECT  0 5.76 0.192 5.784 ;
    END
  END o[34]
  PIN o[350]
    DIRECTION OUTPUT ;
    USE SIGNAL ;
    PORT
      LAYER M4 ;
        RECT  0 38.496 0.192 38.52 ;
    END
  END o[350]
  PIN o[351]
    DIRECTION OUTPUT ;
    USE SIGNAL ;
    PORT
      LAYER M4 ;
        RECT  0 38.592 0.192 38.616 ;
    END
  END o[351]
  PIN o[352]
    DIRECTION OUTPUT ;
    USE SIGNAL ;
    PORT
      LAYER M4 ;
        RECT  0 38.688 0.192 38.712 ;
    END
  END o[352]
  PIN o[353]
    DIRECTION OUTPUT ;
    USE SIGNAL ;
    PORT
      LAYER M4 ;
        RECT  0 38.784 0.192 38.808 ;
    END
  END o[353]
  PIN o[354]
    DIRECTION OUTPUT ;
    USE SIGNAL ;
    PORT
      LAYER M4 ;
        RECT  0 38.88 0.192 38.904 ;
    END
  END o[354]
  PIN o[355]
    DIRECTION OUTPUT ;
    USE SIGNAL ;
    PORT
      LAYER M4 ;
        RECT  0 38.976 0.192 39 ;
    END
  END o[355]
  PIN o[356]
    DIRECTION OUTPUT ;
    USE SIGNAL ;
    PORT
      LAYER M4 ;
        RECT  0 39.12 0.192 39.144 ;
    END
  END o[356]
  PIN o[357]
    DIRECTION OUTPUT ;
    USE SIGNAL ;
    PORT
      LAYER M4 ;
        RECT  0 39.216 0.192 39.24 ;
    END
  END o[357]
  PIN o[358]
    DIRECTION OUTPUT ;
    USE SIGNAL ;
    PORT
      LAYER M4 ;
        RECT  0 39.312 0.192 39.336 ;
    END
  END o[358]
  PIN o[359]
    DIRECTION OUTPUT ;
    USE SIGNAL ;
    PORT
      LAYER M4 ;
        RECT  0 39.408 0.192 39.432 ;
    END
  END o[359]
  PIN o[35]
    DIRECTION OUTPUT ;
    USE SIGNAL ;
    PORT
      LAYER M4 ;
        RECT  0 5.856 0.192 5.88 ;
    END
  END o[35]
  PIN o[360]
    DIRECTION OUTPUT ;
    USE SIGNAL ;
    PORT
      LAYER M4 ;
        RECT  0 39.504 0.192 39.528 ;
    END
  END o[360]
  PIN o[361]
    DIRECTION OUTPUT ;
    USE SIGNAL ;
    PORT
      LAYER M4 ;
        RECT  0 39.6 0.192 39.624 ;
    END
  END o[361]
  PIN o[362]
    DIRECTION OUTPUT ;
    USE SIGNAL ;
    PORT
      LAYER M4 ;
        RECT  0 39.744 0.192 39.768 ;
    END
  END o[362]
  PIN o[363]
    DIRECTION OUTPUT ;
    USE SIGNAL ;
    PORT
      LAYER M4 ;
        RECT  0 39.84 0.192 39.864 ;
    END
  END o[363]
  PIN o[364]
    DIRECTION OUTPUT ;
    USE SIGNAL ;
    PORT
      LAYER M4 ;
        RECT  0 39.936 0.192 39.96 ;
    END
  END o[364]
  PIN o[365]
    DIRECTION OUTPUT ;
    USE SIGNAL ;
    PORT
      LAYER M4 ;
        RECT  0 40.032 0.192 40.056 ;
    END
  END o[365]
  PIN o[366]
    DIRECTION OUTPUT ;
    USE SIGNAL ;
    PORT
      LAYER M4 ;
        RECT  0 40.128 0.192 40.152 ;
    END
  END o[366]
  PIN o[367]
    DIRECTION OUTPUT ;
    USE SIGNAL ;
    PORT
      LAYER M4 ;
        RECT  0 40.224 0.192 40.248 ;
    END
  END o[367]
  PIN o[368]
    DIRECTION OUTPUT ;
    USE SIGNAL ;
    PORT
      LAYER M4 ;
        RECT  0 40.368 0.192 40.392 ;
    END
  END o[368]
  PIN o[369]
    DIRECTION OUTPUT ;
    USE SIGNAL ;
    PORT
      LAYER M4 ;
        RECT  0 40.464 0.192 40.488 ;
    END
  END o[369]
  PIN o[36]
    DIRECTION OUTPUT ;
    USE SIGNAL ;
    PORT
      LAYER M4 ;
        RECT  0 5.952 0.192 5.976 ;
    END
  END o[36]
  PIN o[370]
    DIRECTION OUTPUT ;
    USE SIGNAL ;
    PORT
      LAYER M4 ;
        RECT  0 40.56 0.192 40.584 ;
    END
  END o[370]
  PIN o[371]
    DIRECTION OUTPUT ;
    USE SIGNAL ;
    PORT
      LAYER M4 ;
        RECT  0 40.656 0.192 40.68 ;
    END
  END o[371]
  PIN o[372]
    DIRECTION OUTPUT ;
    USE SIGNAL ;
    PORT
      LAYER M4 ;
        RECT  0 40.752 0.192 40.776 ;
    END
  END o[372]
  PIN o[373]
    DIRECTION OUTPUT ;
    USE SIGNAL ;
    PORT
      LAYER M4 ;
        RECT  0 40.848 0.192 40.872 ;
    END
  END o[373]
  PIN o[374]
    DIRECTION OUTPUT ;
    USE SIGNAL ;
    PORT
      LAYER M4 ;
        RECT  0 40.944 0.192 40.968 ;
    END
  END o[374]
  PIN o[375]
    DIRECTION OUTPUT ;
    USE SIGNAL ;
    PORT
      LAYER M4 ;
        RECT  0 41.088 0.192 41.112 ;
    END
  END o[375]
  PIN o[376]
    DIRECTION OUTPUT ;
    USE SIGNAL ;
    PORT
      LAYER M4 ;
        RECT  0 41.184 0.192 41.208 ;
    END
  END o[376]
  PIN o[377]
    DIRECTION OUTPUT ;
    USE SIGNAL ;
    PORT
      LAYER M4 ;
        RECT  0 41.28 0.192 41.304 ;
    END
  END o[377]
  PIN o[378]
    DIRECTION OUTPUT ;
    USE SIGNAL ;
    PORT
      LAYER M4 ;
        RECT  0 41.376 0.192 41.4 ;
    END
  END o[378]
  PIN o[379]
    DIRECTION OUTPUT ;
    USE SIGNAL ;
    PORT
      LAYER M4 ;
        RECT  0 41.472 0.192 41.496 ;
    END
  END o[379]
  PIN o[37]
    DIRECTION OUTPUT ;
    USE SIGNAL ;
    PORT
      LAYER M4 ;
        RECT  0 6.048 0.192 6.072 ;
    END
  END o[37]
  PIN o[380]
    DIRECTION OUTPUT ;
    USE SIGNAL ;
    PORT
      LAYER M4 ;
        RECT  0 41.568 0.192 41.592 ;
    END
  END o[380]
  PIN o[381]
    DIRECTION OUTPUT ;
    USE SIGNAL ;
    PORT
      LAYER M4 ;
        RECT  0 41.712 0.192 41.736 ;
    END
  END o[381]
  PIN o[382]
    DIRECTION OUTPUT ;
    USE SIGNAL ;
    PORT
      LAYER M4 ;
        RECT  0 41.808 0.192 41.832 ;
    END
  END o[382]
  PIN o[383]
    DIRECTION OUTPUT ;
    USE SIGNAL ;
    PORT
      LAYER M4 ;
        RECT  0 41.904 0.192 41.928 ;
    END
  END o[383]
  PIN o[384]
    DIRECTION OUTPUT ;
    USE SIGNAL ;
    PORT
      LAYER M4 ;
        RECT  0 42 0.192 42.024 ;
    END
  END o[384]
  PIN o[385]
    DIRECTION OUTPUT ;
    USE SIGNAL ;
    PORT
      LAYER M4 ;
        RECT  0 42.096 0.192 42.12 ;
    END
  END o[385]
  PIN o[386]
    DIRECTION OUTPUT ;
    USE SIGNAL ;
    PORT
      LAYER M4 ;
        RECT  0 42.192 0.192 42.216 ;
    END
  END o[386]
  PIN o[387]
    DIRECTION OUTPUT ;
    USE SIGNAL ;
    PORT
      LAYER M4 ;
        RECT  0 42.336 0.192 42.36 ;
    END
  END o[387]
  PIN o[388]
    DIRECTION OUTPUT ;
    USE SIGNAL ;
    PORT
      LAYER M4 ;
        RECT  0 42.432 0.192 42.456 ;
    END
  END o[388]
  PIN o[389]
    DIRECTION OUTPUT ;
    USE SIGNAL ;
    PORT
      LAYER M4 ;
        RECT  0 42.528 0.192 42.552 ;
    END
  END o[389]
  PIN o[38]
    DIRECTION OUTPUT ;
    USE SIGNAL ;
    PORT
      LAYER M4 ;
        RECT  0 6.144 0.192 6.168 ;
    END
  END o[38]
  PIN o[390]
    DIRECTION OUTPUT ;
    USE SIGNAL ;
    PORT
      LAYER M4 ;
        RECT  0 42.624 0.192 42.648 ;
    END
  END o[390]
  PIN o[391]
    DIRECTION OUTPUT ;
    USE SIGNAL ;
    PORT
      LAYER M4 ;
        RECT  0 42.72 0.192 42.744 ;
    END
  END o[391]
  PIN o[392]
    DIRECTION OUTPUT ;
    USE SIGNAL ;
    PORT
      LAYER M4 ;
        RECT  0 42.816 0.192 42.84 ;
    END
  END o[392]
  PIN o[393]
    DIRECTION OUTPUT ;
    USE SIGNAL ;
    PORT
      LAYER M4 ;
        RECT  0 42.912 0.192 42.936 ;
    END
  END o[393]
  PIN o[394]
    DIRECTION OUTPUT ;
    USE SIGNAL ;
    PORT
      LAYER M4 ;
        RECT  0 43.056 0.192 43.08 ;
    END
  END o[394]
  PIN o[395]
    DIRECTION OUTPUT ;
    USE SIGNAL ;
    PORT
      LAYER M4 ;
        RECT  0 43.152 0.192 43.176 ;
    END
  END o[395]
  PIN o[396]
    DIRECTION OUTPUT ;
    USE SIGNAL ;
    PORT
      LAYER M4 ;
        RECT  0 43.248 0.192 43.272 ;
    END
  END o[396]
  PIN o[397]
    DIRECTION OUTPUT ;
    USE SIGNAL ;
    PORT
      LAYER M4 ;
        RECT  0 43.344 0.192 43.368 ;
    END
  END o[397]
  PIN o[398]
    DIRECTION OUTPUT ;
    USE SIGNAL ;
    PORT
      LAYER M4 ;
        RECT  0 43.44 0.192 43.464 ;
    END
  END o[398]
  PIN o[399]
    DIRECTION OUTPUT ;
    USE SIGNAL ;
    PORT
      LAYER M4 ;
        RECT  0 43.536 0.192 43.56 ;
    END
  END o[399]
  PIN o[39]
    DIRECTION OUTPUT ;
    USE SIGNAL ;
    PORT
      LAYER M4 ;
        RECT  0 6.24 0.192 6.264 ;
    END
  END o[39]
  PIN o[3]
    DIRECTION OUTPUT ;
    USE SIGNAL ;
    PORT
      LAYER M4 ;
        RECT  0 2.544 0.192 2.568 ;
    END
  END o[3]
  PIN o[400]
    DIRECTION OUTPUT ;
    USE SIGNAL ;
    PORT
      LAYER M4 ;
        RECT  0 43.68 0.192 43.704 ;
    END
  END o[400]
  PIN o[401]
    DIRECTION OUTPUT ;
    USE SIGNAL ;
    PORT
      LAYER M4 ;
        RECT  0 43.776 0.192 43.8 ;
    END
  END o[401]
  PIN o[402]
    DIRECTION OUTPUT ;
    USE SIGNAL ;
    PORT
      LAYER M4 ;
        RECT  0 43.872 0.192 43.896 ;
    END
  END o[402]
  PIN o[403]
    DIRECTION OUTPUT ;
    USE SIGNAL ;
    PORT
      LAYER M4 ;
        RECT  0 43.968 0.192 43.992 ;
    END
  END o[403]
  PIN o[404]
    DIRECTION OUTPUT ;
    USE SIGNAL ;
    PORT
      LAYER M4 ;
        RECT  0 44.064 0.192 44.088 ;
    END
  END o[404]
  PIN o[405]
    DIRECTION OUTPUT ;
    USE SIGNAL ;
    PORT
      LAYER M4 ;
        RECT  0 44.16 0.192 44.184 ;
    END
  END o[405]
  PIN o[406]
    DIRECTION OUTPUT ;
    USE SIGNAL ;
    PORT
      LAYER M4 ;
        RECT  0 44.304 0.192 44.328 ;
    END
  END o[406]
  PIN o[407]
    DIRECTION OUTPUT ;
    USE SIGNAL ;
    PORT
      LAYER M4 ;
        RECT  0 44.4 0.192 44.424 ;
    END
  END o[407]
  PIN o[408]
    DIRECTION OUTPUT ;
    USE SIGNAL ;
    PORT
      LAYER M4 ;
        RECT  0 44.496 0.192 44.52 ;
    END
  END o[408]
  PIN o[409]
    DIRECTION OUTPUT ;
    USE SIGNAL ;
    PORT
      LAYER M4 ;
        RECT  0 44.592 0.192 44.616 ;
    END
  END o[409]
  PIN o[40]
    DIRECTION OUTPUT ;
    USE SIGNAL ;
    PORT
      LAYER M4 ;
        RECT  0 6.384 0.192 6.408 ;
    END
  END o[40]
  PIN o[410]
    DIRECTION OUTPUT ;
    USE SIGNAL ;
    PORT
      LAYER M4 ;
        RECT  0 44.688 0.192 44.712 ;
    END
  END o[410]
  PIN o[411]
    DIRECTION OUTPUT ;
    USE SIGNAL ;
    PORT
      LAYER M4 ;
        RECT  0 44.784 0.192 44.808 ;
    END
  END o[411]
  PIN o[412]
    DIRECTION OUTPUT ;
    USE SIGNAL ;
    PORT
      LAYER M4 ;
        RECT  0 44.88 0.192 44.904 ;
    END
  END o[412]
  PIN o[413]
    DIRECTION OUTPUT ;
    USE SIGNAL ;
    PORT
      LAYER M4 ;
        RECT  0 45.024 0.192 45.048 ;
    END
  END o[413]
  PIN o[414]
    DIRECTION OUTPUT ;
    USE SIGNAL ;
    PORT
      LAYER M4 ;
        RECT  0 45.12 0.192 45.144 ;
    END
  END o[414]
  PIN o[415]
    DIRECTION OUTPUT ;
    USE SIGNAL ;
    PORT
      LAYER M4 ;
        RECT  0 45.216 0.192 45.24 ;
    END
  END o[415]
  PIN o[416]
    DIRECTION OUTPUT ;
    USE SIGNAL ;
    PORT
      LAYER M4 ;
        RECT  0 45.312 0.192 45.336 ;
    END
  END o[416]
  PIN o[417]
    DIRECTION OUTPUT ;
    USE SIGNAL ;
    PORT
      LAYER M4 ;
        RECT  0 45.408 0.192 45.432 ;
    END
  END o[417]
  PIN o[418]
    DIRECTION OUTPUT ;
    USE SIGNAL ;
    PORT
      LAYER M4 ;
        RECT  0 45.504 0.192 45.528 ;
    END
  END o[418]
  PIN o[419]
    DIRECTION OUTPUT ;
    USE SIGNAL ;
    PORT
      LAYER M4 ;
        RECT  0 45.648 0.192 45.672 ;
    END
  END o[419]
  PIN o[41]
    DIRECTION OUTPUT ;
    USE SIGNAL ;
    PORT
      LAYER M4 ;
        RECT  0 6.48 0.192 6.504 ;
    END
  END o[41]
  PIN o[420]
    DIRECTION OUTPUT ;
    USE SIGNAL ;
    PORT
      LAYER M4 ;
        RECT  0 45.744 0.192 45.768 ;
    END
  END o[420]
  PIN o[421]
    DIRECTION OUTPUT ;
    USE SIGNAL ;
    PORT
      LAYER M4 ;
        RECT  0 45.84 0.192 45.864 ;
    END
  END o[421]
  PIN o[422]
    DIRECTION OUTPUT ;
    USE SIGNAL ;
    PORT
      LAYER M4 ;
        RECT  0 45.936 0.192 45.96 ;
    END
  END o[422]
  PIN o[423]
    DIRECTION OUTPUT ;
    USE SIGNAL ;
    PORT
      LAYER M4 ;
        RECT  0 46.032 0.192 46.056 ;
    END
  END o[423]
  PIN o[424]
    DIRECTION OUTPUT ;
    USE SIGNAL ;
    PORT
      LAYER M4 ;
        RECT  0 46.128 0.192 46.152 ;
    END
  END o[424]
  PIN o[425]
    DIRECTION OUTPUT ;
    USE SIGNAL ;
    PORT
      LAYER M4 ;
        RECT  0 46.272 0.192 46.296 ;
    END
  END o[425]
  PIN o[426]
    DIRECTION OUTPUT ;
    USE SIGNAL ;
    PORT
      LAYER M4 ;
        RECT  0 46.368 0.192 46.392 ;
    END
  END o[426]
  PIN o[427]
    DIRECTION OUTPUT ;
    USE SIGNAL ;
    PORT
      LAYER M4 ;
        RECT  0 46.464 0.192 46.488 ;
    END
  END o[427]
  PIN o[428]
    DIRECTION OUTPUT ;
    USE SIGNAL ;
    PORT
      LAYER M4 ;
        RECT  0 46.56 0.192 46.584 ;
    END
  END o[428]
  PIN o[429]
    DIRECTION OUTPUT ;
    USE SIGNAL ;
    PORT
      LAYER M4 ;
        RECT  0 46.656 0.192 46.68 ;
    END
  END o[429]
  PIN o[42]
    DIRECTION OUTPUT ;
    USE SIGNAL ;
    PORT
      LAYER M4 ;
        RECT  0 6.576 0.192 6.6 ;
    END
  END o[42]
  PIN o[430]
    DIRECTION OUTPUT ;
    USE SIGNAL ;
    PORT
      LAYER M4 ;
        RECT  0 46.752 0.192 46.776 ;
    END
  END o[430]
  PIN o[431]
    DIRECTION OUTPUT ;
    USE SIGNAL ;
    PORT
      LAYER M4 ;
        RECT  0 46.848 0.192 46.872 ;
    END
  END o[431]
  PIN o[432]
    DIRECTION OUTPUT ;
    USE SIGNAL ;
    PORT
      LAYER M4 ;
        RECT  0 46.992 0.192 47.016 ;
    END
  END o[432]
  PIN o[433]
    DIRECTION OUTPUT ;
    USE SIGNAL ;
    PORT
      LAYER M4 ;
        RECT  0 47.088 0.192 47.112 ;
    END
  END o[433]
  PIN o[434]
    DIRECTION OUTPUT ;
    USE SIGNAL ;
    PORT
      LAYER M4 ;
        RECT  0 47.184 0.192 47.208 ;
    END
  END o[434]
  PIN o[435]
    DIRECTION OUTPUT ;
    USE SIGNAL ;
    PORT
      LAYER M4 ;
        RECT  0 47.28 0.192 47.304 ;
    END
  END o[435]
  PIN o[436]
    DIRECTION OUTPUT ;
    USE SIGNAL ;
    PORT
      LAYER M4 ;
        RECT  0 47.376 0.192 47.4 ;
    END
  END o[436]
  PIN o[437]
    DIRECTION OUTPUT ;
    USE SIGNAL ;
    PORT
      LAYER M4 ;
        RECT  0 47.472 0.192 47.496 ;
    END
  END o[437]
  PIN o[438]
    DIRECTION OUTPUT ;
    USE SIGNAL ;
    PORT
      LAYER M4 ;
        RECT  0 47.616 0.192 47.64 ;
    END
  END o[438]
  PIN o[439]
    DIRECTION OUTPUT ;
    USE SIGNAL ;
    PORT
      LAYER M4 ;
        RECT  0 47.712 0.192 47.736 ;
    END
  END o[439]
  PIN o[43]
    DIRECTION OUTPUT ;
    USE SIGNAL ;
    PORT
      LAYER M4 ;
        RECT  0 6.672 0.192 6.696 ;
    END
  END o[43]
  PIN o[440]
    DIRECTION OUTPUT ;
    USE SIGNAL ;
    PORT
      LAYER M4 ;
        RECT  0 47.808 0.192 47.832 ;
    END
  END o[440]
  PIN o[441]
    DIRECTION OUTPUT ;
    USE SIGNAL ;
    PORT
      LAYER M4 ;
        RECT  0 47.904 0.192 47.928 ;
    END
  END o[441]
  PIN o[442]
    DIRECTION OUTPUT ;
    USE SIGNAL ;
    PORT
      LAYER M4 ;
        RECT  0 48 0.192 48.024 ;
    END
  END o[442]
  PIN o[443]
    DIRECTION OUTPUT ;
    USE SIGNAL ;
    PORT
      LAYER M4 ;
        RECT  0 48.096 0.192 48.12 ;
    END
  END o[443]
  PIN o[444]
    DIRECTION OUTPUT ;
    USE SIGNAL ;
    PORT
      LAYER M4 ;
        RECT  0 48.24 0.192 48.264 ;
    END
  END o[444]
  PIN o[445]
    DIRECTION OUTPUT ;
    USE SIGNAL ;
    PORT
      LAYER M4 ;
        RECT  0 48.336 0.192 48.36 ;
    END
  END o[445]
  PIN o[446]
    DIRECTION OUTPUT ;
    USE SIGNAL ;
    PORT
      LAYER M4 ;
        RECT  0 48.432 0.192 48.456 ;
    END
  END o[446]
  PIN o[447]
    DIRECTION OUTPUT ;
    USE SIGNAL ;
    PORT
      LAYER M4 ;
        RECT  0 48.528 0.192 48.552 ;
    END
  END o[447]
  PIN o[448]
    DIRECTION OUTPUT ;
    USE SIGNAL ;
    PORT
      LAYER M4 ;
        RECT  0 48.624 0.192 48.648 ;
    END
  END o[448]
  PIN o[449]
    DIRECTION OUTPUT ;
    USE SIGNAL ;
    PORT
      LAYER M4 ;
        RECT  0 48.72 0.192 48.744 ;
    END
  END o[449]
  PIN o[44]
    DIRECTION OUTPUT ;
    USE SIGNAL ;
    PORT
      LAYER M4 ;
        RECT  0 6.768 0.192 6.792 ;
    END
  END o[44]
  PIN o[450]
    DIRECTION OUTPUT ;
    USE SIGNAL ;
    PORT
      LAYER M4 ;
        RECT  0 48.816 0.192 48.84 ;
    END
  END o[450]
  PIN o[451]
    DIRECTION OUTPUT ;
    USE SIGNAL ;
    PORT
      LAYER M4 ;
        RECT  0 48.96 0.192 48.984 ;
    END
  END o[451]
  PIN o[452]
    DIRECTION OUTPUT ;
    USE SIGNAL ;
    PORT
      LAYER M4 ;
        RECT  0 49.056 0.192 49.08 ;
    END
  END o[452]
  PIN o[453]
    DIRECTION OUTPUT ;
    USE SIGNAL ;
    PORT
      LAYER M4 ;
        RECT  0 49.152 0.192 49.176 ;
    END
  END o[453]
  PIN o[454]
    DIRECTION OUTPUT ;
    USE SIGNAL ;
    PORT
      LAYER M4 ;
        RECT  0 49.248 0.192 49.272 ;
    END
  END o[454]
  PIN o[455]
    DIRECTION OUTPUT ;
    USE SIGNAL ;
    PORT
      LAYER M4 ;
        RECT  0 49.344 0.192 49.368 ;
    END
  END o[455]
  PIN o[456]
    DIRECTION OUTPUT ;
    USE SIGNAL ;
    PORT
      LAYER M4 ;
        RECT  0 49.44 0.192 49.464 ;
    END
  END o[456]
  PIN o[457]
    DIRECTION OUTPUT ;
    USE SIGNAL ;
    PORT
      LAYER M4 ;
        RECT  0 49.584 0.192 49.608 ;
    END
  END o[457]
  PIN o[458]
    DIRECTION OUTPUT ;
    USE SIGNAL ;
    PORT
      LAYER M4 ;
        RECT  0 49.68 0.192 49.704 ;
    END
  END o[458]
  PIN o[459]
    DIRECTION OUTPUT ;
    USE SIGNAL ;
    PORT
      LAYER M4 ;
        RECT  0 49.776 0.192 49.8 ;
    END
  END o[459]
  PIN o[45]
    DIRECTION OUTPUT ;
    USE SIGNAL ;
    PORT
      LAYER M4 ;
        RECT  0 6.864 0.192 6.888 ;
    END
  END o[45]
  PIN o[460]
    DIRECTION OUTPUT ;
    USE SIGNAL ;
    PORT
      LAYER M4 ;
        RECT  0 49.872 0.192 49.896 ;
    END
  END o[460]
  PIN o[461]
    DIRECTION OUTPUT ;
    USE SIGNAL ;
    PORT
      LAYER M4 ;
        RECT  0 49.968 0.192 49.992 ;
    END
  END o[461]
  PIN o[462]
    DIRECTION OUTPUT ;
    USE SIGNAL ;
    PORT
      LAYER M4 ;
        RECT  0 50.064 0.192 50.088 ;
    END
  END o[462]
  PIN o[463]
    DIRECTION OUTPUT ;
    USE SIGNAL ;
    PORT
      LAYER M4 ;
        RECT  0 50.208 0.192 50.232 ;
    END
  END o[463]
  PIN o[464]
    DIRECTION OUTPUT ;
    USE SIGNAL ;
    PORT
      LAYER M4 ;
        RECT  0 50.304 0.192 50.328 ;
    END
  END o[464]
  PIN o[465]
    DIRECTION OUTPUT ;
    USE SIGNAL ;
    PORT
      LAYER M4 ;
        RECT  0 50.4 0.192 50.424 ;
    END
  END o[465]
  PIN o[466]
    DIRECTION OUTPUT ;
    USE SIGNAL ;
    PORT
      LAYER M4 ;
        RECT  0 50.496 0.192 50.52 ;
    END
  END o[466]
  PIN o[467]
    DIRECTION OUTPUT ;
    USE SIGNAL ;
    PORT
      LAYER M4 ;
        RECT  0 50.592 0.192 50.616 ;
    END
  END o[467]
  PIN o[468]
    DIRECTION OUTPUT ;
    USE SIGNAL ;
    PORT
      LAYER M4 ;
        RECT  0 50.688 0.192 50.712 ;
    END
  END o[468]
  PIN o[469]
    DIRECTION OUTPUT ;
    USE SIGNAL ;
    PORT
      LAYER M4 ;
        RECT  0 50.784 0.192 50.808 ;
    END
  END o[469]
  PIN o[46]
    DIRECTION OUTPUT ;
    USE SIGNAL ;
    PORT
      LAYER M4 ;
        RECT  0 7.008 0.192 7.032 ;
    END
  END o[46]
  PIN o[470]
    DIRECTION OUTPUT ;
    USE SIGNAL ;
    PORT
      LAYER M4 ;
        RECT  0 50.928 0.192 50.952 ;
    END
  END o[470]
  PIN o[471]
    DIRECTION OUTPUT ;
    USE SIGNAL ;
    PORT
      LAYER M4 ;
        RECT  0 51.024 0.192 51.048 ;
    END
  END o[471]
  PIN o[472]
    DIRECTION OUTPUT ;
    USE SIGNAL ;
    PORT
      LAYER M4 ;
        RECT  0 51.12 0.192 51.144 ;
    END
  END o[472]
  PIN o[473]
    DIRECTION OUTPUT ;
    USE SIGNAL ;
    PORT
      LAYER M4 ;
        RECT  0 51.216 0.192 51.24 ;
    END
  END o[473]
  PIN o[474]
    DIRECTION OUTPUT ;
    USE SIGNAL ;
    PORT
      LAYER M4 ;
        RECT  0 51.312 0.192 51.336 ;
    END
  END o[474]
  PIN o[475]
    DIRECTION OUTPUT ;
    USE SIGNAL ;
    PORT
      LAYER M4 ;
        RECT  0 51.408 0.192 51.432 ;
    END
  END o[475]
  PIN o[476]
    DIRECTION OUTPUT ;
    USE SIGNAL ;
    PORT
      LAYER M4 ;
        RECT  0 51.552 0.192 51.576 ;
    END
  END o[476]
  PIN o[477]
    DIRECTION OUTPUT ;
    USE SIGNAL ;
    PORT
      LAYER M4 ;
        RECT  0 51.648 0.192 51.672 ;
    END
  END o[477]
  PIN o[478]
    DIRECTION OUTPUT ;
    USE SIGNAL ;
    PORT
      LAYER M4 ;
        RECT  0 51.744 0.192 51.768 ;
    END
  END o[478]
  PIN o[479]
    DIRECTION OUTPUT ;
    USE SIGNAL ;
    PORT
      LAYER M4 ;
        RECT  0 51.84 0.192 51.864 ;
    END
  END o[479]
  PIN o[47]
    DIRECTION OUTPUT ;
    USE SIGNAL ;
    PORT
      LAYER M4 ;
        RECT  0 7.104 0.192 7.128 ;
    END
  END o[47]
  PIN o[480]
    DIRECTION OUTPUT ;
    USE SIGNAL ;
    PORT
      LAYER M4 ;
        RECT  0 51.936 0.192 51.96 ;
    END
  END o[480]
  PIN o[481]
    DIRECTION OUTPUT ;
    USE SIGNAL ;
    PORT
      LAYER M4 ;
        RECT  0 52.032 0.192 52.056 ;
    END
  END o[481]
  PIN o[482]
    DIRECTION OUTPUT ;
    USE SIGNAL ;
    PORT
      LAYER M4 ;
        RECT  0 52.176 0.192 52.2 ;
    END
  END o[482]
  PIN o[483]
    DIRECTION OUTPUT ;
    USE SIGNAL ;
    PORT
      LAYER M4 ;
        RECT  0 52.272 0.192 52.296 ;
    END
  END o[483]
  PIN o[484]
    DIRECTION OUTPUT ;
    USE SIGNAL ;
    PORT
      LAYER M4 ;
        RECT  0 52.368 0.192 52.392 ;
    END
  END o[484]
  PIN o[485]
    DIRECTION OUTPUT ;
    USE SIGNAL ;
    PORT
      LAYER M4 ;
        RECT  0 52.464 0.192 52.488 ;
    END
  END o[485]
  PIN o[486]
    DIRECTION OUTPUT ;
    USE SIGNAL ;
    PORT
      LAYER M4 ;
        RECT  0 52.56 0.192 52.584 ;
    END
  END o[486]
  PIN o[487]
    DIRECTION OUTPUT ;
    USE SIGNAL ;
    PORT
      LAYER M4 ;
        RECT  0 52.656 0.192 52.68 ;
    END
  END o[487]
  PIN o[488]
    DIRECTION OUTPUT ;
    USE SIGNAL ;
    PORT
      LAYER M4 ;
        RECT  0 52.752 0.192 52.776 ;
    END
  END o[488]
  PIN o[489]
    DIRECTION OUTPUT ;
    USE SIGNAL ;
    PORT
      LAYER M4 ;
        RECT  0 52.896 0.192 52.92 ;
    END
  END o[489]
  PIN o[48]
    DIRECTION OUTPUT ;
    USE SIGNAL ;
    PORT
      LAYER M4 ;
        RECT  0 7.2 0.192 7.224 ;
    END
  END o[48]
  PIN o[490]
    DIRECTION OUTPUT ;
    USE SIGNAL ;
    PORT
      LAYER M4 ;
        RECT  0 52.992 0.192 53.016 ;
    END
  END o[490]
  PIN o[491]
    DIRECTION OUTPUT ;
    USE SIGNAL ;
    PORT
      LAYER M4 ;
        RECT  0 53.088 0.192 53.112 ;
    END
  END o[491]
  PIN o[492]
    DIRECTION OUTPUT ;
    USE SIGNAL ;
    PORT
      LAYER M4 ;
        RECT  0 53.184 0.192 53.208 ;
    END
  END o[492]
  PIN o[493]
    DIRECTION OUTPUT ;
    USE SIGNAL ;
    PORT
      LAYER M4 ;
        RECT  0 53.28 0.192 53.304 ;
    END
  END o[493]
  PIN o[494]
    DIRECTION OUTPUT ;
    USE SIGNAL ;
    PORT
      LAYER M4 ;
        RECT  0 53.376 0.192 53.4 ;
    END
  END o[494]
  PIN o[495]
    DIRECTION OUTPUT ;
    USE SIGNAL ;
    PORT
      LAYER M4 ;
        RECT  0 53.52 0.192 53.544 ;
    END
  END o[495]
  PIN o[496]
    DIRECTION OUTPUT ;
    USE SIGNAL ;
    PORT
      LAYER M4 ;
        RECT  0 53.616 0.192 53.64 ;
    END
  END o[496]
  PIN o[497]
    DIRECTION OUTPUT ;
    USE SIGNAL ;
    PORT
      LAYER M4 ;
        RECT  0 53.712 0.192 53.736 ;
    END
  END o[497]
  PIN o[498]
    DIRECTION OUTPUT ;
    USE SIGNAL ;
    PORT
      LAYER M4 ;
        RECT  0 53.808 0.192 53.832 ;
    END
  END o[498]
  PIN o[499]
    DIRECTION OUTPUT ;
    USE SIGNAL ;
    PORT
      LAYER M4 ;
        RECT  0 53.904 0.192 53.928 ;
    END
  END o[499]
  PIN o[49]
    DIRECTION OUTPUT ;
    USE SIGNAL ;
    PORT
      LAYER M4 ;
        RECT  0 7.296 0.192 7.32 ;
    END
  END o[49]
  PIN o[4]
    DIRECTION OUTPUT ;
    USE SIGNAL ;
    PORT
      LAYER M4 ;
        RECT  0 2.64 0.192 2.664 ;
    END
  END o[4]
  PIN o[500]
    DIRECTION OUTPUT ;
    USE SIGNAL ;
    PORT
      LAYER M4 ;
        RECT  0 54 0.192 54.024 ;
    END
  END o[500]
  PIN o[501]
    DIRECTION OUTPUT ;
    USE SIGNAL ;
    PORT
      LAYER M4 ;
        RECT  0 54.144 0.192 54.168 ;
    END
  END o[501]
  PIN o[502]
    DIRECTION OUTPUT ;
    USE SIGNAL ;
    PORT
      LAYER M4 ;
        RECT  0 54.24 0.192 54.264 ;
    END
  END o[502]
  PIN o[503]
    DIRECTION OUTPUT ;
    USE SIGNAL ;
    PORT
      LAYER M4 ;
        RECT  0 54.336 0.192 54.36 ;
    END
  END o[503]
  PIN o[504]
    DIRECTION OUTPUT ;
    USE SIGNAL ;
    PORT
      LAYER M4 ;
        RECT  0 54.432 0.192 54.456 ;
    END
  END o[504]
  PIN o[505]
    DIRECTION OUTPUT ;
    USE SIGNAL ;
    PORT
      LAYER M4 ;
        RECT  0 54.528 0.192 54.552 ;
    END
  END o[505]
  PIN o[506]
    DIRECTION OUTPUT ;
    USE SIGNAL ;
    PORT
      LAYER M4 ;
        RECT  0 54.624 0.192 54.648 ;
    END
  END o[506]
  PIN o[507]
    DIRECTION OUTPUT ;
    USE SIGNAL ;
    PORT
      LAYER M4 ;
        RECT  0 54.72 0.192 54.744 ;
    END
  END o[507]
  PIN o[508]
    DIRECTION OUTPUT ;
    USE SIGNAL ;
    PORT
      LAYER M4 ;
        RECT  0 54.864 0.192 54.888 ;
    END
  END o[508]
  PIN o[509]
    DIRECTION OUTPUT ;
    USE SIGNAL ;
    PORT
      LAYER M4 ;
        RECT  0 54.96 0.192 54.984 ;
    END
  END o[509]
  PIN o[50]
    DIRECTION OUTPUT ;
    USE SIGNAL ;
    PORT
      LAYER M4 ;
        RECT  0 7.392 0.192 7.416 ;
    END
  END o[50]
  PIN o[510]
    DIRECTION OUTPUT ;
    USE SIGNAL ;
    PORT
      LAYER M4 ;
        RECT  0 55.056 0.192 55.08 ;
    END
  END o[510]
  PIN o[511]
    DIRECTION OUTPUT ;
    USE SIGNAL ;
    PORT
      LAYER M4 ;
        RECT  0 55.152 0.192 55.176 ;
    END
  END o[511]
  PIN o[512]
    DIRECTION OUTPUT ;
    USE SIGNAL ;
    PORT
      LAYER M4 ;
        RECT  0 55.248 0.192 55.272 ;
    END
  END o[512]
  PIN o[513]
    DIRECTION OUTPUT ;
    USE SIGNAL ;
    PORT
      LAYER M4 ;
        RECT  0 55.344 0.192 55.368 ;
    END
  END o[513]
  PIN o[514]
    DIRECTION OUTPUT ;
    USE SIGNAL ;
    PORT
      LAYER M4 ;
        RECT  0 55.488 0.192 55.512 ;
    END
  END o[514]
  PIN o[515]
    DIRECTION OUTPUT ;
    USE SIGNAL ;
    PORT
      LAYER M4 ;
        RECT  0 55.584 0.192 55.608 ;
    END
  END o[515]
  PIN o[516]
    DIRECTION OUTPUT ;
    USE SIGNAL ;
    PORT
      LAYER M4 ;
        RECT  0 55.68 0.192 55.704 ;
    END
  END o[516]
  PIN o[517]
    DIRECTION OUTPUT ;
    USE SIGNAL ;
    PORT
      LAYER M4 ;
        RECT  0 55.776 0.192 55.8 ;
    END
  END o[517]
  PIN o[518]
    DIRECTION OUTPUT ;
    USE SIGNAL ;
    PORT
      LAYER M4 ;
        RECT  0 55.872 0.192 55.896 ;
    END
  END o[518]
  PIN o[519]
    DIRECTION OUTPUT ;
    USE SIGNAL ;
    PORT
      LAYER M4 ;
        RECT  0 55.968 0.192 55.992 ;
    END
  END o[519]
  PIN o[51]
    DIRECTION OUTPUT ;
    USE SIGNAL ;
    PORT
      LAYER M4 ;
        RECT  0 7.488 0.192 7.512 ;
    END
  END o[51]
  PIN o[520]
    DIRECTION OUTPUT ;
    USE SIGNAL ;
    PORT
      LAYER M4 ;
        RECT  0 56.112 0.192 56.136 ;
    END
  END o[520]
  PIN o[521]
    DIRECTION OUTPUT ;
    USE SIGNAL ;
    PORT
      LAYER M4 ;
        RECT  0 56.208 0.192 56.232 ;
    END
  END o[521]
  PIN o[522]
    DIRECTION OUTPUT ;
    USE SIGNAL ;
    PORT
      LAYER M4 ;
        RECT  0 56.304 0.192 56.328 ;
    END
  END o[522]
  PIN o[523]
    DIRECTION OUTPUT ;
    USE SIGNAL ;
    PORT
      LAYER M4 ;
        RECT  0 56.4 0.192 56.424 ;
    END
  END o[523]
  PIN o[524]
    DIRECTION OUTPUT ;
    USE SIGNAL ;
    PORT
      LAYER M4 ;
        RECT  0 56.496 0.192 56.52 ;
    END
  END o[524]
  PIN o[525]
    DIRECTION OUTPUT ;
    USE SIGNAL ;
    PORT
      LAYER M4 ;
        RECT  0 56.592 0.192 56.616 ;
    END
  END o[525]
  PIN o[526]
    DIRECTION OUTPUT ;
    USE SIGNAL ;
    PORT
      LAYER M4 ;
        RECT  0 56.688 0.192 56.712 ;
    END
  END o[526]
  PIN o[527]
    DIRECTION OUTPUT ;
    USE SIGNAL ;
    PORT
      LAYER M4 ;
        RECT  0 56.832 0.192 56.856 ;
    END
  END o[527]
  PIN o[528]
    DIRECTION OUTPUT ;
    USE SIGNAL ;
    PORT
      LAYER M4 ;
        RECT  0 56.928 0.192 56.952 ;
    END
  END o[528]
  PIN o[529]
    DIRECTION OUTPUT ;
    USE SIGNAL ;
    PORT
      LAYER M4 ;
        RECT  0 57.024 0.192 57.048 ;
    END
  END o[529]
  PIN o[52]
    DIRECTION OUTPUT ;
    USE SIGNAL ;
    PORT
      LAYER M4 ;
        RECT  0 7.632 0.192 7.656 ;
    END
  END o[52]
  PIN o[530]
    DIRECTION OUTPUT ;
    USE SIGNAL ;
    PORT
      LAYER M4 ;
        RECT  0 57.12 0.192 57.144 ;
    END
  END o[530]
  PIN o[531]
    DIRECTION OUTPUT ;
    USE SIGNAL ;
    PORT
      LAYER M4 ;
        RECT  0 57.216 0.192 57.24 ;
    END
  END o[531]
  PIN o[532]
    DIRECTION OUTPUT ;
    USE SIGNAL ;
    PORT
      LAYER M4 ;
        RECT  0 57.312 0.192 57.336 ;
    END
  END o[532]
  PIN o[533]
    DIRECTION OUTPUT ;
    USE SIGNAL ;
    PORT
      LAYER M4 ;
        RECT  0 57.456 0.192 57.48 ;
    END
  END o[533]
  PIN o[534]
    DIRECTION OUTPUT ;
    USE SIGNAL ;
    PORT
      LAYER M4 ;
        RECT  0 57.552 0.192 57.576 ;
    END
  END o[534]
  PIN o[535]
    DIRECTION OUTPUT ;
    USE SIGNAL ;
    PORT
      LAYER M4 ;
        RECT  0 57.648 0.192 57.672 ;
    END
  END o[535]
  PIN o[536]
    DIRECTION OUTPUT ;
    USE SIGNAL ;
    PORT
      LAYER M4 ;
        RECT  0 57.744 0.192 57.768 ;
    END
  END o[536]
  PIN o[537]
    DIRECTION OUTPUT ;
    USE SIGNAL ;
    PORT
      LAYER M4 ;
        RECT  0 57.84 0.192 57.864 ;
    END
  END o[537]
  PIN o[538]
    DIRECTION OUTPUT ;
    USE SIGNAL ;
    PORT
      LAYER M4 ;
        RECT  0 57.936 0.192 57.96 ;
    END
  END o[538]
  PIN o[539]
    DIRECTION OUTPUT ;
    USE SIGNAL ;
    PORT
      LAYER M4 ;
        RECT  0 58.08 0.192 58.104 ;
    END
  END o[539]
  PIN o[53]
    DIRECTION OUTPUT ;
    USE SIGNAL ;
    PORT
      LAYER M4 ;
        RECT  0 7.728 0.192 7.752 ;
    END
  END o[53]
  PIN o[540]
    DIRECTION OUTPUT ;
    USE SIGNAL ;
    PORT
      LAYER M4 ;
        RECT  0 58.176 0.192 58.2 ;
    END
  END o[540]
  PIN o[541]
    DIRECTION OUTPUT ;
    USE SIGNAL ;
    PORT
      LAYER M4 ;
        RECT  0 58.272 0.192 58.296 ;
    END
  END o[541]
  PIN o[542]
    DIRECTION OUTPUT ;
    USE SIGNAL ;
    PORT
      LAYER M4 ;
        RECT  0 58.368 0.192 58.392 ;
    END
  END o[542]
  PIN o[543]
    DIRECTION OUTPUT ;
    USE SIGNAL ;
    PORT
      LAYER M4 ;
        RECT  0 58.464 0.192 58.488 ;
    END
  END o[543]
  PIN o[544]
    DIRECTION OUTPUT ;
    USE SIGNAL ;
    PORT
      LAYER M4 ;
        RECT  0 58.56 0.192 58.584 ;
    END
  END o[544]
  PIN o[545]
    DIRECTION OUTPUT ;
    USE SIGNAL ;
    PORT
      LAYER M4 ;
        RECT  0 58.656 0.192 58.68 ;
    END
  END o[545]
  PIN o[546]
    DIRECTION OUTPUT ;
    USE SIGNAL ;
    PORT
      LAYER M4 ;
        RECT  0 58.8 0.192 58.824 ;
    END
  END o[546]
  PIN o[547]
    DIRECTION OUTPUT ;
    USE SIGNAL ;
    PORT
      LAYER M4 ;
        RECT  0 58.896 0.192 58.92 ;
    END
  END o[547]
  PIN o[548]
    DIRECTION OUTPUT ;
    USE SIGNAL ;
    PORT
      LAYER M4 ;
        RECT  0 58.992 0.192 59.016 ;
    END
  END o[548]
  PIN o[549]
    DIRECTION OUTPUT ;
    USE SIGNAL ;
    PORT
      LAYER M4 ;
        RECT  0 59.088 0.192 59.112 ;
    END
  END o[549]
  PIN o[54]
    DIRECTION OUTPUT ;
    USE SIGNAL ;
    PORT
      LAYER M4 ;
        RECT  0 7.824 0.192 7.848 ;
    END
  END o[54]
  PIN o[550]
    DIRECTION OUTPUT ;
    USE SIGNAL ;
    PORT
      LAYER M4 ;
        RECT  0 59.184 0.192 59.208 ;
    END
  END o[550]
  PIN o[551]
    DIRECTION OUTPUT ;
    USE SIGNAL ;
    PORT
      LAYER M4 ;
        RECT  0 59.28 0.192 59.304 ;
    END
  END o[551]
  PIN o[552]
    DIRECTION OUTPUT ;
    USE SIGNAL ;
    PORT
      LAYER M4 ;
        RECT  0 59.424 0.192 59.448 ;
    END
  END o[552]
  PIN o[553]
    DIRECTION OUTPUT ;
    USE SIGNAL ;
    PORT
      LAYER M4 ;
        RECT  0 59.52 0.192 59.544 ;
    END
  END o[553]
  PIN o[554]
    DIRECTION OUTPUT ;
    USE SIGNAL ;
    PORT
      LAYER M4 ;
        RECT  0 59.616 0.192 59.64 ;
    END
  END o[554]
  PIN o[555]
    DIRECTION OUTPUT ;
    USE SIGNAL ;
    PORT
      LAYER M4 ;
        RECT  0 59.712 0.192 59.736 ;
    END
  END o[555]
  PIN o[556]
    DIRECTION OUTPUT ;
    USE SIGNAL ;
    PORT
      LAYER M4 ;
        RECT  0 59.808 0.192 59.832 ;
    END
  END o[556]
  PIN o[557]
    DIRECTION OUTPUT ;
    USE SIGNAL ;
    PORT
      LAYER M4 ;
        RECT  0 59.904 0.192 59.928 ;
    END
  END o[557]
  PIN o[558]
    DIRECTION OUTPUT ;
    USE SIGNAL ;
    PORT
      LAYER M4 ;
        RECT  0 60.048 0.192 60.072 ;
    END
  END o[558]
  PIN o[559]
    DIRECTION OUTPUT ;
    USE SIGNAL ;
    PORT
      LAYER M4 ;
        RECT  0 60.144 0.192 60.168 ;
    END
  END o[559]
  PIN o[55]
    DIRECTION OUTPUT ;
    USE SIGNAL ;
    PORT
      LAYER M4 ;
        RECT  0 7.92 0.192 7.944 ;
    END
  END o[55]
  PIN o[560]
    DIRECTION OUTPUT ;
    USE SIGNAL ;
    PORT
      LAYER M4 ;
        RECT  0 60.24 0.192 60.264 ;
    END
  END o[560]
  PIN o[561]
    DIRECTION OUTPUT ;
    USE SIGNAL ;
    PORT
      LAYER M4 ;
        RECT  0 60.336 0.192 60.36 ;
    END
  END o[561]
  PIN o[56]
    DIRECTION OUTPUT ;
    USE SIGNAL ;
    PORT
      LAYER M4 ;
        RECT  0 8.016 0.192 8.04 ;
    END
  END o[56]
  PIN o[57]
    DIRECTION OUTPUT ;
    USE SIGNAL ;
    PORT
      LAYER M4 ;
        RECT  0 8.112 0.192 8.136 ;
    END
  END o[57]
  PIN o[58]
    DIRECTION OUTPUT ;
    USE SIGNAL ;
    PORT
      LAYER M4 ;
        RECT  0 8.208 0.192 8.232 ;
    END
  END o[58]
  PIN o[59]
    DIRECTION OUTPUT ;
    USE SIGNAL ;
    PORT
      LAYER M4 ;
        RECT  0 8.352 0.192 8.376 ;
    END
  END o[59]
  PIN o[5]
    DIRECTION OUTPUT ;
    USE SIGNAL ;
    PORT
      LAYER M4 ;
        RECT  0 2.736 0.192 2.76 ;
    END
  END o[5]
  PIN o[60]
    DIRECTION OUTPUT ;
    USE SIGNAL ;
    PORT
      LAYER M4 ;
        RECT  0 8.448 0.192 8.472 ;
    END
  END o[60]
  PIN o[61]
    DIRECTION OUTPUT ;
    USE SIGNAL ;
    PORT
      LAYER M4 ;
        RECT  0 8.544 0.192 8.568 ;
    END
  END o[61]
  PIN o[62]
    DIRECTION OUTPUT ;
    USE SIGNAL ;
    PORT
      LAYER M4 ;
        RECT  0 8.64 0.192 8.664 ;
    END
  END o[62]
  PIN o[63]
    DIRECTION OUTPUT ;
    USE SIGNAL ;
    PORT
      LAYER M4 ;
        RECT  0 8.736 0.192 8.76 ;
    END
  END o[63]
  PIN o[64]
    DIRECTION OUTPUT ;
    USE SIGNAL ;
    PORT
      LAYER M4 ;
        RECT  0 8.832 0.192 8.856 ;
    END
  END o[64]
  PIN o[65]
    DIRECTION OUTPUT ;
    USE SIGNAL ;
    PORT
      LAYER M4 ;
        RECT  0 8.976 0.192 9 ;
    END
  END o[65]
  PIN o[66]
    DIRECTION OUTPUT ;
    USE SIGNAL ;
    PORT
      LAYER M4 ;
        RECT  0 9.072 0.192 9.096 ;
    END
  END o[66]
  PIN o[67]
    DIRECTION OUTPUT ;
    USE SIGNAL ;
    PORT
      LAYER M4 ;
        RECT  0 9.168 0.192 9.192 ;
    END
  END o[67]
  PIN o[68]
    DIRECTION OUTPUT ;
    USE SIGNAL ;
    PORT
      LAYER M4 ;
        RECT  0 9.264 0.192 9.288 ;
    END
  END o[68]
  PIN o[69]
    DIRECTION OUTPUT ;
    USE SIGNAL ;
    PORT
      LAYER M4 ;
        RECT  0 9.36 0.192 9.384 ;
    END
  END o[69]
  PIN o[6]
    DIRECTION OUTPUT ;
    USE SIGNAL ;
    PORT
      LAYER M4 ;
        RECT  0 2.832 0.192 2.856 ;
    END
  END o[6]
  PIN o[70]
    DIRECTION OUTPUT ;
    USE SIGNAL ;
    PORT
      LAYER M4 ;
        RECT  0 9.456 0.192 9.48 ;
    END
  END o[70]
  PIN o[71]
    DIRECTION OUTPUT ;
    USE SIGNAL ;
    PORT
      LAYER M4 ;
        RECT  0 9.6 0.192 9.624 ;
    END
  END o[71]
  PIN o[72]
    DIRECTION OUTPUT ;
    USE SIGNAL ;
    PORT
      LAYER M4 ;
        RECT  0 9.696 0.192 9.72 ;
    END
  END o[72]
  PIN o[73]
    DIRECTION OUTPUT ;
    USE SIGNAL ;
    PORT
      LAYER M4 ;
        RECT  0 9.792 0.192 9.816 ;
    END
  END o[73]
  PIN o[74]
    DIRECTION OUTPUT ;
    USE SIGNAL ;
    PORT
      LAYER M4 ;
        RECT  0 9.888 0.192 9.912 ;
    END
  END o[74]
  PIN o[75]
    DIRECTION OUTPUT ;
    USE SIGNAL ;
    PORT
      LAYER M4 ;
        RECT  0 9.984 0.192 10.008 ;
    END
  END o[75]
  PIN o[76]
    DIRECTION OUTPUT ;
    USE SIGNAL ;
    PORT
      LAYER M4 ;
        RECT  0 10.08 0.192 10.104 ;
    END
  END o[76]
  PIN o[77]
    DIRECTION OUTPUT ;
    USE SIGNAL ;
    PORT
      LAYER M4 ;
        RECT  0 10.224 0.192 10.248 ;
    END
  END o[77]
  PIN o[78]
    DIRECTION OUTPUT ;
    USE SIGNAL ;
    PORT
      LAYER M4 ;
        RECT  0 10.32 0.192 10.344 ;
    END
  END o[78]
  PIN o[79]
    DIRECTION OUTPUT ;
    USE SIGNAL ;
    PORT
      LAYER M4 ;
        RECT  0 10.416 0.192 10.44 ;
    END
  END o[79]
  PIN o[7]
    DIRECTION OUTPUT ;
    USE SIGNAL ;
    PORT
      LAYER M4 ;
        RECT  0 2.928 0.192 2.952 ;
    END
  END o[7]
  PIN o[80]
    DIRECTION OUTPUT ;
    USE SIGNAL ;
    PORT
      LAYER M4 ;
        RECT  0 10.512 0.192 10.536 ;
    END
  END o[80]
  PIN o[81]
    DIRECTION OUTPUT ;
    USE SIGNAL ;
    PORT
      LAYER M4 ;
        RECT  0 10.608 0.192 10.632 ;
    END
  END o[81]
  PIN o[82]
    DIRECTION OUTPUT ;
    USE SIGNAL ;
    PORT
      LAYER M4 ;
        RECT  0 10.704 0.192 10.728 ;
    END
  END o[82]
  PIN o[83]
    DIRECTION OUTPUT ;
    USE SIGNAL ;
    PORT
      LAYER M4 ;
        RECT  0 10.8 0.192 10.824 ;
    END
  END o[83]
  PIN o[84]
    DIRECTION OUTPUT ;
    USE SIGNAL ;
    PORT
      LAYER M4 ;
        RECT  0 10.944 0.192 10.968 ;
    END
  END o[84]
  PIN o[85]
    DIRECTION OUTPUT ;
    USE SIGNAL ;
    PORT
      LAYER M4 ;
        RECT  0 11.04 0.192 11.064 ;
    END
  END o[85]
  PIN o[86]
    DIRECTION OUTPUT ;
    USE SIGNAL ;
    PORT
      LAYER M4 ;
        RECT  0 11.136 0.192 11.16 ;
    END
  END o[86]
  PIN o[87]
    DIRECTION OUTPUT ;
    USE SIGNAL ;
    PORT
      LAYER M4 ;
        RECT  0 11.232 0.192 11.256 ;
    END
  END o[87]
  PIN o[88]
    DIRECTION OUTPUT ;
    USE SIGNAL ;
    PORT
      LAYER M4 ;
        RECT  0 11.328 0.192 11.352 ;
    END
  END o[88]
  PIN o[89]
    DIRECTION OUTPUT ;
    USE SIGNAL ;
    PORT
      LAYER M4 ;
        RECT  0 11.424 0.192 11.448 ;
    END
  END o[89]
  PIN o[8]
    DIRECTION OUTPUT ;
    USE SIGNAL ;
    PORT
      LAYER M4 ;
        RECT  0 3.072 0.192 3.096 ;
    END
  END o[8]
  PIN o[90]
    DIRECTION OUTPUT ;
    USE SIGNAL ;
    PORT
      LAYER M4 ;
        RECT  0 11.568 0.192 11.592 ;
    END
  END o[90]
  PIN o[91]
    DIRECTION OUTPUT ;
    USE SIGNAL ;
    PORT
      LAYER M4 ;
        RECT  0 11.664 0.192 11.688 ;
    END
  END o[91]
  PIN o[92]
    DIRECTION OUTPUT ;
    USE SIGNAL ;
    PORT
      LAYER M4 ;
        RECT  0 11.76 0.192 11.784 ;
    END
  END o[92]
  PIN o[93]
    DIRECTION OUTPUT ;
    USE SIGNAL ;
    PORT
      LAYER M4 ;
        RECT  0 11.856 0.192 11.88 ;
    END
  END o[93]
  PIN o[94]
    DIRECTION OUTPUT ;
    USE SIGNAL ;
    PORT
      LAYER M4 ;
        RECT  0 11.952 0.192 11.976 ;
    END
  END o[94]
  PIN o[95]
    DIRECTION OUTPUT ;
    USE SIGNAL ;
    PORT
      LAYER M4 ;
        RECT  0 12.048 0.192 12.072 ;
    END
  END o[95]
  PIN o[96]
    DIRECTION OUTPUT ;
    USE SIGNAL ;
    PORT
      LAYER M4 ;
        RECT  0 12.192 0.192 12.216 ;
    END
  END o[96]
  PIN o[97]
    DIRECTION OUTPUT ;
    USE SIGNAL ;
    PORT
      LAYER M4 ;
        RECT  0 12.288 0.192 12.312 ;
    END
  END o[97]
  PIN o[98]
    DIRECTION OUTPUT ;
    USE SIGNAL ;
    PORT
      LAYER M4 ;
        RECT  0 12.384 0.192 12.408 ;
    END
  END o[98]
  PIN o[99]
    DIRECTION OUTPUT ;
    USE SIGNAL ;
    PORT
      LAYER M4 ;
        RECT  0 12.48 0.192 12.504 ;
    END
  END o[99]
  PIN o[9]
    DIRECTION OUTPUT ;
    USE SIGNAL ;
    PORT
      LAYER M4 ;
        RECT  0 3.168 0.192 3.192 ;
    END
  END o[9]
  PIN rs
    DIRECTION INPUT ;
    USE SIGNAL ;
    PORT
      LAYER M5 ;
        RECT  11.856 62.448 11.88 62.64 ;
    END
    PORT
      LAYER M5 ;
        RECT  11.856 61.237 11.88 62.48 ;
    END
  END rs
  PIN VDD
    DIRECTION INOUT ;
    USE POWER ;
    PORT
      LAYER M5 ;
        RECT  13.392 2.151 13.512 60.489 ;
        RECT  10.692 2.151 10.812 60.489 ;
        RECT  7.992 2.151 8.112 60.489 ;
        RECT  5.292 2.151 5.412 60.489 ;
        RECT  2.592 2.151 2.712 60.489 ;
    END
  END VDD
  PIN VSS
    DIRECTION INOUT ;
    USE GROUND ;
    PORT
      LAYER M5 ;
        RECT  13.2 2.137 13.32 60.503 ;
        RECT  10.5 2.137 10.62 60.503 ;
        RECT  7.8 2.137 7.92 60.503 ;
        RECT  5.1 2.137 5.22 60.503 ;
        RECT  2.4 2.137 2.52 60.503 ;
    END
  END VSS
  # OT_OBS_CLOSED layer=M5 d_um=1.536 added=158
  OBS
    LAYER RVTN ;
     RECT  2.16 2.16 15.12 2.295 ;
     RECT  2.16 2.565 15.12 2.835 ;
     RECT  2.16 3.105 15.12 3.375 ;
     RECT  2.16 3.645 15.12 3.915 ;
     RECT  2.16 4.185 15.12 4.455 ;
     RECT  2.16 4.725 15.12 4.995 ;
     RECT  2.16 5.265 15.12 5.535 ;
     RECT  2.16 5.805 15.12 6.075 ;
     RECT  2.16 6.345 15.12 6.615 ;
     RECT  2.16 6.885 15.12 7.155 ;
     RECT  2.16 7.425 15.12 7.695 ;
     RECT  2.16 7.965 15.12 8.235 ;
     RECT  2.16 8.505 15.12 8.775 ;
     RECT  2.16 9.045 15.12 9.315 ;
     RECT  2.16 9.585 15.12 9.855 ;
     RECT  2.16 10.125 15.12 10.395 ;
     RECT  2.16 10.665 15.12 10.935 ;
     RECT  2.16 11.205 15.12 11.475 ;
     RECT  2.16 11.745 15.12 12.015 ;
     RECT  2.16 12.285 15.12 12.555 ;
     RECT  2.16 12.825 15.12 13.095 ;
     RECT  2.16 13.365 15.12 13.635 ;
     RECT  2.16 13.905 15.12 14.175 ;
     RECT  2.16 14.445 15.12 14.715 ;
     RECT  2.16 14.985 15.12 15.255 ;
     RECT  2.16 15.525 15.12 15.795 ;
     RECT  2.16 16.065 15.12 16.335 ;
     RECT  2.16 16.605 15.12 16.875 ;
     RECT  2.16 17.145 15.12 17.415 ;
     RECT  2.16 17.685 15.12 17.955 ;
     RECT  2.16 18.225 15.12 18.495 ;
     RECT  2.16 18.765 15.12 19.035 ;
     RECT  2.16 19.305 15.12 19.575 ;
     RECT  2.16 19.845 15.12 20.115 ;
     RECT  2.16 20.385 15.12 20.655 ;
     RECT  2.16 20.925 15.12 21.195 ;
     RECT  2.16 21.465 15.12 21.735 ;
     RECT  2.16 22.005 15.12 22.275 ;
     RECT  2.16 22.545 15.12 22.815 ;
     RECT  2.16 23.085 15.12 23.355 ;
     RECT  2.16 23.625 15.12 23.895 ;
     RECT  2.16 24.165 15.12 24.435 ;
     RECT  2.16 24.705 15.12 24.975 ;
     RECT  2.16 25.245 15.12 25.515 ;
     RECT  2.16 25.785 15.12 26.055 ;
     RECT  2.16 26.325 15.12 26.595 ;
     RECT  2.16 26.865 15.12 27.135 ;
     RECT  2.16 27.405 15.12 27.675 ;
     RECT  2.16 27.945 15.12 28.215 ;
     RECT  2.16 28.485 15.12 28.755 ;
     RECT  2.16 29.025 15.12 29.295 ;
     RECT  2.16 29.565 15.12 29.835 ;
     RECT  2.16 30.105 15.12 30.375 ;
     RECT  2.16 30.645 15.12 30.915 ;
     RECT  2.16 31.185 15.12 31.455 ;
     RECT  2.16 31.725 15.12 31.995 ;
     RECT  2.16 32.265 15.12 32.535 ;
     RECT  2.16 32.805 15.12 33.075 ;
     RECT  2.16 33.345 15.12 33.615 ;
     RECT  2.16 33.885 15.12 34.155 ;
     RECT  2.16 34.425 15.12 34.695 ;
     RECT  2.16 34.965 15.12 35.235 ;
     RECT  2.16 35.505 15.12 35.775 ;
     RECT  2.16 36.045 15.12 36.315 ;
     RECT  2.16 36.585 15.12 36.855 ;
     RECT  2.16 37.125 15.12 37.395 ;
     RECT  2.16 37.665 15.12 37.935 ;
     RECT  2.16 38.205 15.12 38.475 ;
     RECT  2.16 38.745 15.12 39.015 ;
     RECT  2.16 39.285 15.12 39.555 ;
     RECT  2.16 39.825 15.12 40.095 ;
     RECT  2.16 40.365 15.12 40.635 ;
     RECT  2.16 40.905 15.12 41.175 ;
     RECT  2.16 41.445 15.12 41.715 ;
     RECT  2.16 41.985 15.12 42.255 ;
     RECT  2.16 42.525 15.12 42.795 ;
     RECT  2.16 43.065 15.12 43.335 ;
     RECT  2.16 43.605 15.12 43.875 ;
     RECT  2.16 44.145 15.12 44.415 ;
     RECT  2.16 44.685 15.12 44.955 ;
     RECT  2.16 45.225 15.12 45.495 ;
     RECT  2.16 45.765 15.12 46.035 ;
     RECT  2.16 46.305 15.12 46.575 ;
     RECT  2.16 46.845 15.12 47.115 ;
     RECT  2.16 47.385 15.12 47.655 ;
     RECT  2.16 47.925 15.12 48.195 ;
     RECT  2.16 48.465 15.12 48.735 ;
     RECT  2.16 49.005 15.12 49.275 ;
     RECT  2.16 49.545 15.12 49.815 ;
     RECT  2.16 50.085 15.12 50.355 ;
     RECT  2.16 50.625 15.12 50.895 ;
     RECT  2.16 51.165 15.12 51.435 ;
     RECT  2.16 51.705 15.12 51.975 ;
     RECT  2.16 52.245 15.12 52.515 ;
     RECT  2.16 52.785 15.12 53.055 ;
     RECT  2.16 53.325 15.12 53.595 ;
     RECT  2.16 53.865 15.12 54.135 ;
     RECT  2.16 54.405 15.12 54.675 ;
     RECT  2.16 54.945 15.12 55.215 ;
     RECT  2.16 55.485 15.12 55.755 ;
     RECT  2.16 56.025 15.12 56.295 ;
     RECT  2.16 56.565 15.12 56.835 ;
     RECT  2.16 57.105 15.12 57.375 ;
     RECT  2.16 57.645 15.12 57.915 ;
     RECT  2.16 58.185 15.12 58.455 ;
     RECT  2.16 58.725 15.12 58.995 ;
     RECT  2.16 59.265 15.12 59.535 ;
     RECT  2.16 59.805 15.12 60.075 ;
     RECT  2.16 60.345 15.12 60.48 ;
    LAYER RVTP ;
     RECT  2.16 2.295 15.12 2.565 ;
     RECT  2.16 2.835 15.12 3.105 ;
     RECT  2.16 3.375 15.12 3.645 ;
     RECT  2.16 3.915 15.12 4.185 ;
     RECT  2.16 4.455 15.12 4.725 ;
     RECT  2.16 4.995 15.12 5.265 ;
     RECT  2.16 5.535 15.12 5.805 ;
     RECT  2.16 6.075 15.12 6.345 ;
     RECT  2.16 6.615 15.12 6.885 ;
     RECT  2.16 7.155 15.12 7.425 ;
     RECT  2.16 7.695 15.12 7.965 ;
     RECT  2.16 8.235 15.12 8.505 ;
     RECT  2.16 8.775 15.12 9.045 ;
     RECT  2.16 9.315 15.12 9.585 ;
     RECT  2.16 9.855 15.12 10.125 ;
     RECT  2.16 10.395 15.12 10.665 ;
     RECT  2.16 10.935 15.12 11.205 ;
     RECT  2.16 11.475 15.12 11.745 ;
     RECT  2.16 12.015 15.12 12.285 ;
     RECT  2.16 12.555 15.12 12.825 ;
     RECT  2.16 13.095 15.12 13.365 ;
     RECT  2.16 13.635 15.12 13.905 ;
     RECT  2.16 14.175 15.12 14.445 ;
     RECT  2.16 14.715 15.12 14.985 ;
     RECT  2.16 15.255 15.12 15.525 ;
     RECT  2.16 15.795 15.12 16.065 ;
     RECT  2.16 16.335 15.12 16.605 ;
     RECT  2.16 16.875 15.12 17.145 ;
     RECT  2.16 17.415 15.12 17.685 ;
     RECT  2.16 17.955 15.12 18.225 ;
     RECT  2.16 18.495 15.12 18.765 ;
     RECT  2.16 19.035 15.12 19.305 ;
     RECT  2.16 19.575 15.12 19.845 ;
     RECT  2.16 20.115 15.12 20.385 ;
     RECT  2.16 20.655 15.12 20.925 ;
     RECT  2.16 21.195 15.12 21.465 ;
     RECT  2.16 21.735 15.12 22.005 ;
     RECT  2.16 22.275 15.12 22.545 ;
     RECT  2.16 22.815 15.12 23.085 ;
     RECT  2.16 23.355 15.12 23.625 ;
     RECT  2.16 23.895 15.12 24.165 ;
     RECT  2.16 24.435 15.12 24.705 ;
     RECT  2.16 24.975 15.12 25.245 ;
     RECT  2.16 25.515 15.12 25.785 ;
     RECT  2.16 26.055 15.12 26.325 ;
     RECT  2.16 26.595 15.12 26.865 ;
     RECT  2.16 27.135 15.12 27.405 ;
     RECT  2.16 27.675 15.12 27.945 ;
     RECT  2.16 28.215 15.12 28.485 ;
     RECT  2.16 28.755 15.12 29.025 ;
     RECT  2.16 29.295 15.12 29.565 ;
     RECT  2.16 29.835 15.12 30.105 ;
     RECT  2.16 30.375 15.12 30.645 ;
     RECT  2.16 30.915 15.12 31.185 ;
     RECT  2.16 31.455 15.12 31.725 ;
     RECT  2.16 31.995 15.12 32.265 ;
     RECT  2.16 32.535 15.12 32.805 ;
     RECT  2.16 33.075 15.12 33.345 ;
     RECT  2.16 33.615 15.12 33.885 ;
     RECT  2.16 34.155 15.12 34.425 ;
     RECT  2.16 34.695 15.12 34.965 ;
     RECT  2.16 35.235 15.12 35.505 ;
     RECT  2.16 35.775 15.12 36.045 ;
     RECT  2.16 36.315 15.12 36.585 ;
     RECT  2.16 36.855 15.12 37.125 ;
     RECT  2.16 37.395 15.12 37.665 ;
     RECT  2.16 37.935 15.12 38.205 ;
     RECT  2.16 38.475 15.12 38.745 ;
     RECT  2.16 39.015 15.12 39.285 ;
     RECT  2.16 39.555 15.12 39.825 ;
     RECT  2.16 40.095 15.12 40.365 ;
     RECT  2.16 40.635 15.12 40.905 ;
     RECT  2.16 41.175 15.12 41.445 ;
     RECT  2.16 41.715 15.12 41.985 ;
     RECT  2.16 42.255 15.12 42.525 ;
     RECT  2.16 42.795 15.12 43.065 ;
     RECT  2.16 43.335 15.12 43.605 ;
     RECT  2.16 43.875 15.12 44.145 ;
     RECT  2.16 44.415 15.12 44.685 ;
     RECT  2.16 44.955 15.12 45.225 ;
     RECT  2.16 45.495 15.12 45.765 ;
     RECT  2.16 46.035 15.12 46.305 ;
     RECT  2.16 46.575 15.12 46.845 ;
     RECT  2.16 47.115 15.12 47.385 ;
     RECT  2.16 47.655 15.12 47.925 ;
     RECT  2.16 48.195 15.12 48.465 ;
     RECT  2.16 48.735 15.12 49.005 ;
     RECT  2.16 49.275 15.12 49.545 ;
     RECT  2.16 49.815 15.12 50.085 ;
     RECT  2.16 50.355 15.12 50.625 ;
     RECT  2.16 50.895 15.12 51.165 ;
     RECT  2.16 51.435 15.12 51.705 ;
     RECT  2.16 51.975 15.12 52.245 ;
     RECT  2.16 52.515 15.12 52.785 ;
     RECT  2.16 53.055 15.12 53.325 ;
     RECT  2.16 53.595 15.12 53.865 ;
     RECT  2.16 54.135 15.12 54.405 ;
     RECT  2.16 54.675 15.12 54.945 ;
     RECT  2.16 55.215 15.12 55.485 ;
     RECT  2.16 55.755 15.12 56.025 ;
     RECT  2.16 56.295 15.12 56.565 ;
     RECT  2.16 56.835 15.12 57.105 ;
     RECT  2.16 57.375 15.12 57.645 ;
     RECT  2.16 57.915 15.12 58.185 ;
     RECT  2.16 58.455 15.12 58.725 ;
     RECT  2.16 58.995 15.12 59.265 ;
     RECT  2.16 59.535 15.12 59.805 ;
     RECT  2.16 60.075 15.12 60.345 ;
    LAYER M1 ;
     RECT  2.16 2.151 15.12 60.489 ;
    LAYER M2 ;
     RECT  0.211 2.844 0.311 2.862 ;
     RECT  0.211 19.116 0.311 19.134 ;
     RECT  0.211 20.664 0.311 20.682 ;
     RECT  0.211 43.686 0.311 43.704 ;
     RECT  0.211 46.512 0.311 46.53 ;
     RECT  0.211 56.304 0.311 56.322 ;
     RECT  0.211 37.602 0.535 37.62 ;
     RECT  0.211 42.336 0.535 42.354 ;
     RECT  0.211 57.42 0.535 57.438 ;
     RECT  0.535 47.826 0.571 47.844 ;
     RECT  0.571 47.826 0.671 47.88 ;
     RECT  0.535 27.918 1.147 28.476 ;
     RECT  0.535 50.058 1.147 50.076 ;
     RECT  1.147 49.986 1.175 50.076 ;
     RECT  1.175 49.986 1.975 50.004 ;
     RECT  1.975 2.88 2.16 2.898 ;
     RECT  0.535 3.96 2.16 3.978 ;
     RECT  0.535 11.178 2.16 11.196 ;
     RECT  2.155 12.996 2.16 13.014 ;
     RECT  0.535 17.082 2.16 17.604 ;
     RECT  0.535 22.176 2.16 22.194 ;
     RECT  0.211 23.256 2.16 23.274 ;
     RECT  1.975 25.488 2.16 25.506 ;
     RECT  0.535 26.604 2.16 26.622 ;
     RECT  1.147 27.846 2.16 28.476 ;
     RECT  0.535 29.466 2.16 29.484 ;
     RECT  0.211 32.976 2.16 32.994 ;
     RECT  0.535 37.602 2.16 37.926 ;
     RECT  0.211 40.266 2.16 40.284 ;
     RECT  0.535 41.958 2.16 42.354 ;
     RECT  0.671 47.826 2.16 47.844 ;
     RECT  0.535 48.978 2.16 48.996 ;
     RECT  1.975 49.986 2.16 50.148 ;
     RECT  0.535 54.378 2.16 54.396 ;
     RECT  0.535 57.42 2.16 58.104 ;
     RECT  2.16 2.151 4.243 60.489 ;
     RECT  4.243 2.07 6.547 60.489 ;
     RECT  6.547 2.07 7.339 60.534 ;
     RECT  7.339 2.07 9.203 60.606 ;
     RECT  9.203 2.07 10.471 60.534 ;
     RECT  10.471 2.07 11.363 60.57 ;
     RECT  11.363 2.07 12.703 60.489 ;
     RECT  12.703 1.998 13.099 60.489 ;
     RECT  13.099 1.998 13.415 60.534 ;
     RECT  13.415 1.998 14.099 60.489 ;
     RECT  14.099 2.106 15.12 60.489 ;
     RECT  15.12 2.106 15.431 6.84 ;
     RECT  15.12 7.74 15.431 12.546 ;
     RECT  15.12 13.608 15.431 23.076 ;
     RECT  15.12 23.868 15.431 33.066 ;
     RECT  15.12 33.858 15.431 34.758 ;
     RECT  15.12 35.55 15.431 38.97 ;
     RECT  15.12 41.76 15.431 55.278 ;
     RECT  15.12 56.07 15.431 60.336 ;
     RECT  15.431 10.368 15.467 12.348 ;
     RECT  15.431 16.11 15.467 18.558 ;
     RECT  15.431 20.628 15.467 21.69 ;
     RECT  15.431 26.298 15.467 27.864 ;
     RECT  15.431 29.61 15.467 30.096 ;
     RECT  15.431 32.886 15.467 32.904 ;
     RECT  15.431 35.784 15.467 37.386 ;
     RECT  15.12 40.068 15.467 40.968 ;
     RECT  15.431 43.11 15.467 47.106 ;
     RECT  15.431 53.946 15.467 54.504 ;
     RECT  15.431 56.07 15.467 58.446 ;
     RECT  15.431 2.106 15.503 3.168 ;
     RECT  15.467 35.784 16.007 36.576 ;
     RECT  15.431 47.862 16.007 47.88 ;
     RECT  15.467 56.07 16.007 56.556 ;
     RECT  15.431 5.31 16.411 6.678 ;
     RECT  15.431 34.164 16.411 34.488 ;
     RECT  15.467 40.068 16.511 40.428 ;
     RECT  15.431 4.23 16.547 4.248 ;
     RECT  16.411 5.04 16.547 6.678 ;
     RECT  15.431 7.902 16.547 7.92 ;
     RECT  15.431 9.36 16.547 9.378 ;
     RECT  15.467 10.872 16.547 11.808 ;
     RECT  15.431 14.994 16.547 15.012 ;
     RECT  15.467 16.11 16.547 17.1 ;
     RECT  15.467 18 16.547 18.018 ;
     RECT  15.467 21.276 16.547 21.69 ;
     RECT  15.431 22.482 16.547 22.5 ;
     RECT  15.431 25.29 16.547 25.308 ;
     RECT  15.467 26.838 16.547 27.504 ;
     RECT  15.431 28.728 16.547 28.746 ;
     RECT  15.467 29.61 16.547 29.862 ;
     RECT  15.431 31.5 16.547 31.518 ;
     RECT  16.007 35.784 16.547 36.072 ;
     RECT  15.467 37.368 16.547 37.386 ;
     RECT  15.431 38.52 16.547 38.97 ;
     RECT  16.511 40.104 16.547 40.428 ;
     RECT  15.431 41.76 16.547 42.318 ;
     RECT  15.467 43.11 16.547 44.172 ;
     RECT  15.467 44.964 16.547 46.836 ;
     RECT  15.431 48.816 16.547 49.572 ;
     RECT  15.431 50.4 16.547 51.534 ;
     RECT  15.431 52.56 16.547 52.578 ;
     RECT  15.467 57.384 16.547 58.14 ;
     RECT  15.503 2.106 16.583 2.664 ;
     RECT  16.547 6.084 16.583 6.678 ;
     RECT  16.411 34.164 16.583 34.758 ;
     RECT  16.547 40.302 16.583 40.428 ;
     RECT  16.547 45.27 16.583 45.288 ;
     RECT  16.547 57.618 16.583 58.14 ;
     RECT  16.547 38.556 16.619 38.574 ;
     RECT  16.547 43.146 16.619 43.434 ;
     RECT  16.007 56.07 16.619 56.088 ;
     RECT  16.583 34.164 16.655 34.182 ;
     RECT  16.547 5.04 17.059 5.292 ;
     RECT  15.431 24.408 17.059 24.426 ;
     RECT  16.547 48.816 17.059 48.924 ;
     RECT  16.583 57.996 17.059 58.14 ;
     RECT  17.059 48.402 17.087 48.924 ;
     RECT  17.059 2.808 17.159 3.33 ;
     RECT  17.059 4.932 17.159 5.292 ;
     RECT  16.583 6.084 17.159 6.102 ;
     RECT  17.059 7.704 17.159 7.722 ;
     RECT  16.547 11.448 17.159 11.466 ;
     RECT  17.059 12.258 17.159 12.384 ;
     RECT  17.059 13.608 17.159 14.13 ;
     RECT  17.059 16.002 17.159 16.02 ;
     RECT  16.547 16.884 17.159 16.902 ;
     RECT  17.059 19.044 17.159 19.062 ;
     RECT  17.059 20.664 17.159 21.024 ;
     RECT  17.059 21.816 17.159 21.924 ;
     RECT  17.059 23.868 17.159 24.426 ;
     RECT  17.059 25.992 17.159 26.01 ;
     RECT  16.547 29.844 17.159 29.862 ;
     RECT  17.059 32.238 17.159 32.256 ;
     RECT  17.059 33.048 17.159 33.066 ;
     RECT  17.059 40.572 17.159 40.59 ;
     RECT  16.619 43.416 17.159 43.434 ;
     RECT  17.087 48.402 17.159 48.42 ;
     RECT  17.059 55.566 17.159 55.584 ;
     RECT  17.059 57.996 17.159 58.95 ;
    LAYER M3 ;
     RECT  14.076 1.993 14.094 2.065 ;
     RECT  8.064 2.101 8.082 2.143 ;
     RECT  12.708 1.993 12.726 2.143 ;
     RECT  13.824 2.065 14.094 2.143 ;
     RECT  2.415 2.143 2.505 2.191 ;
     RECT  16.56 2.101 16.578 2.203 ;
     RECT  4.248 2.065 4.266 2.299 ;
     RECT  9.108 2.191 9.126 2.299 ;
     RECT  10.515 2.143 10.605 2.299 ;
     RECT  11.7 2.227 11.718 2.299 ;
     RECT  12.708 2.143 14.094 2.299 ;
     RECT  3.996 2.299 4.266 2.335 ;
     RECT  5.115 2.143 5.205 2.335 ;
     RECT  6.3 2.299 6.318 2.335 ;
     RECT  9 2.299 9.126 2.335 ;
     RECT  9 2.335 9.162 2.347 ;
     RECT  10.224 2.299 10.605 2.371 ;
     RECT  2.304 2.191 2.505 2.413 ;
     RECT  7.815 2.143 8.082 2.413 ;
     RECT  7.815 2.413 8.097 2.488 ;
     RECT  10.224 2.371 10.854 2.488 ;
     RECT  7.668 2.488 8.097 2.497 ;
     RECT  9 2.347 9.27 2.497 ;
     RECT  5.115 2.335 6.318 2.525 ;
     RECT  3.852 2.335 4.266 2.533 ;
     RECT  7.668 2.497 9.27 2.533 ;
     RECT  10.08 2.488 10.854 2.533 ;
     RECT  11.7 2.299 14.886 2.533 ;
     RECT  7.524 2.533 9.27 2.569 ;
     RECT  10.08 2.533 15.426 2.569 ;
     RECT  2.304 2.413 2.697 2.731 ;
     RECT  3.42 2.533 4.338 2.731 ;
     RECT  16.524 2.203 16.578 2.765 ;
     RECT  5.115 2.525 5.454 2.831 ;
     RECT  1.98 2.731 4.338 2.903 ;
     RECT  0.216 2.839 0.306 2.909 ;
     RECT  6.336 2.875 6.354 2.911 ;
     RECT  0.216 2.909 0.234 2.957 ;
     RECT  2.304 2.903 4.338 3.029 ;
     RECT  7.524 2.569 15.426 3.067 ;
     RECT  5.115 2.831 5.397 3.109 ;
     RECT  6.336 2.911 6.39 3.145 ;
     RECT  7.524 3.067 15.498 3.173 ;
     RECT  6.336 3.145 6.462 3.299 ;
     RECT  7.524 3.173 15.426 3.299 ;
     RECT  7.524 3.299 13.986 3.307 ;
     RECT  17.064 2.779 17.154 3.335 ;
     RECT  17.136 3.335 17.154 3.344 ;
     RECT  7.416 3.307 13.986 3.541 ;
     RECT  7.38 3.541 13.986 3.595 ;
     RECT  2.304 3.029 4.014 3.677 ;
     RECT  2.304 3.677 2.862 3.787 ;
     RECT  3.6 3.677 4.014 3.811 ;
     RECT  4.788 3.109 5.397 3.811 ;
     RECT  14.832 3.299 15.426 3.917 ;
     RECT  1.98 3.787 2.862 3.965 ;
     RECT  6.516 3.595 13.986 3.965 ;
     RECT  0.54 3.955 0.558 4.013 ;
     RECT  7.596 3.965 13.986 4.153 ;
     RECT  14.832 3.917 14.958 4.153 ;
     RECT  7.596 4.153 14.958 4.253 ;
     RECT  16.524 4.171 16.542 4.253 ;
     RECT  3.6 3.811 5.397 4.351 ;
     RECT  3.6 4.351 5.454 4.445 ;
     RECT  6.264 4.261 6.282 4.445 ;
     RECT  2.304 3.965 2.862 4.507 ;
     RECT  3.6 4.445 5.397 4.507 ;
     RECT  2.304 4.507 5.397 4.649 ;
     RECT  12.276 4.253 14.958 4.693 ;
     RECT  12.276 4.693 15.426 4.733 ;
     RECT  6.804 4.729 6.822 4.781 ;
     RECT  7.596 4.253 11.538 4.795 ;
     RECT  7.56 4.795 11.538 4.801 ;
     RECT  12.276 4.733 14.922 4.829 ;
     RECT  7.164 4.801 11.538 4.919 ;
     RECT  14.832 4.829 14.922 5.027 ;
     RECT  17.064 4.891 17.154 5.035 ;
     RECT  16.416 5.035 17.154 5.072 ;
     RECT  12.276 4.829 13.986 5.233 ;
     RECT  16.524 5.072 17.154 5.309 ;
     RECT  5.115 4.649 5.397 5.431 ;
     RECT  2.304 4.649 4.158 5.504 ;
     RECT  3.924 5.504 4.158 5.563 ;
     RECT  0.252 5.275 0.27 5.693 ;
     RECT  7.272 4.919 11.178 5.851 ;
     RECT  11.988 5.233 13.986 5.851 ;
     RECT  14.832 5.027 14.85 5.851 ;
     RECT  7.272 5.851 15.426 5.909 ;
     RECT  14.616 5.909 15.426 5.947 ;
     RECT  6.444 5.881 6.462 5.999 ;
     RECT  3.924 5.563 4.266 6.007 ;
     RECT  5.076 5.431 5.397 6.007 ;
     RECT  7.272 5.909 13.77 6.007 ;
     RECT  16.524 5.309 16.578 6.043 ;
     RECT  14.616 5.947 15.462 6.071 ;
     RECT  16.524 6.043 17.082 6.079 ;
     RECT  16.524 6.079 17.154 6.125 ;
     RECT  3.924 6.007 4.338 6.151 ;
     RECT  5.076 6.007 6.282 6.151 ;
     RECT  3.924 6.151 6.282 6.269 ;
     RECT  16.524 6.125 16.578 6.413 ;
     RECT  2.304 5.504 2.898 6.421 ;
     RECT  2.304 6.421 2.97 6.511 ;
     RECT  3.924 6.269 5.397 6.619 ;
     RECT  16.56 6.413 16.578 6.683 ;
     RECT  7.02 6.007 13.77 6.691 ;
     RECT  6.264 6.269 6.282 6.763 ;
     RECT  7.02 6.691 13.986 6.763 ;
     RECT  2.304 6.511 3.042 6.808 ;
     RECT  3.816 6.619 5.397 6.808 ;
     RECT  6.264 6.763 13.986 6.809 ;
     RECT  14.796 6.071 15.426 6.845 ;
     RECT  7.128 6.809 13.986 6.859 ;
     RECT  14.796 6.845 14.922 6.859 ;
     RECT  2.304 6.808 5.397 7.123 ;
     RECT  6.264 6.809 6.39 7.123 ;
     RECT  2.304 7.123 6.39 7.229 ;
     RECT  6.12 7.229 6.39 7.349 ;
     RECT  7.128 6.859 14.922 7.349 ;
     RECT  7.2 7.349 14.922 7.627 ;
     RECT  2.304 7.229 5.397 7.661 ;
     RECT  17.136 7.675 17.154 7.699 ;
     RECT  17.064 7.699 17.154 7.727 ;
     RECT  17.064 7.727 17.082 7.757 ;
     RECT  1.152 7.771 1.17 7.819 ;
     RECT  1.152 7.819 1.278 7.949 ;
     RECT  16.524 7.897 16.542 7.949 ;
     RECT  6.228 7.349 6.246 7.961 ;
     RECT  3.924 7.661 5.397 8.159 ;
     RECT  7.2 7.627 15.426 8.275 ;
     RECT  6.876 8.275 15.426 8.827 ;
     RECT  2.304 7.661 2.697 8.941 ;
     RECT  2.304 8.941 2.754 9.067 ;
     RECT  6.804 8.827 15.426 9.211 ;
     RECT  2.304 9.067 2.97 9.307 ;
     RECT  3.996 8.159 5.397 9.307 ;
     RECT  6.732 9.211 15.426 9.341 ;
     RECT  6.84 9.341 15.426 9.347 ;
     RECT  16.524 9.259 16.542 9.383 ;
     RECT  12.024 9.347 15.426 9.509 ;
     RECT  6.84 9.347 11.25 9.917 ;
     RECT  2.304 9.307 5.397 9.931 ;
     RECT  2.304 9.931 5.778 10.121 ;
     RECT  7.2 9.917 11.25 10.129 ;
     RECT  12.024 9.509 13.842 10.129 ;
     RECT  0.252 9.691 0.27 10.157 ;
     RECT  14.796 9.509 15.426 10.219 ;
     RECT  3.924 10.121 5.778 10.349 ;
     RECT  14.796 10.219 15.462 10.363 ;
     RECT  14.688 10.363 15.462 10.391 ;
     RECT  14.688 10.391 15.426 10.499 ;
     RECT  5.04 10.349 5.778 10.561 ;
     RECT  3.924 10.349 3.942 10.661 ;
     RECT  2.304 10.121 3.15 10.697 ;
     RECT  7.2 10.129 13.842 10.781 ;
     RECT  5.04 10.561 5.994 10.867 ;
     RECT  7.2 10.781 11.538 10.867 ;
     RECT  5.04 10.867 11.538 11.209 ;
     RECT  12.276 10.781 13.842 11.371 ;
     RECT  14.832 10.499 15.426 11.371 ;
     RECT  4.932 11.209 11.538 11.399 ;
     RECT  16.524 10.843 16.542 11.419 ;
     RECT  0.54 11.173 0.558 11.453 ;
     RECT  16.524 11.419 17.154 11.471 ;
     RECT  16.524 11.471 17.082 11.501 ;
     RECT  2.304 10.697 3.114 11.551 ;
     RECT  6.732 11.399 11.538 11.551 ;
     RECT  12.276 11.371 15.426 11.551 ;
     RECT  6.732 11.551 15.426 11.579 ;
     RECT  2.304 11.551 3.222 11.669 ;
     RECT  4.104 11.227 4.122 11.755 ;
     RECT  4.932 11.399 5.814 11.755 ;
     RECT  16.524 11.501 16.578 11.813 ;
     RECT  6.804 11.579 15.426 11.885 ;
     RECT  0.288 11.707 0.414 11.981 ;
     RECT  4.104 11.755 5.814 11.981 ;
     RECT  4.104 11.981 5.706 12.091 ;
     RECT  15.408 11.885 15.426 12.187 ;
     RECT  16.56 11.813 16.578 12.235 ;
     RECT  4.068 12.091 5.706 12.325 ;
     RECT  15.408 12.187 15.462 12.353 ;
     RECT  2.304 11.669 2.934 12.379 ;
     RECT  16.56 12.235 17.154 12.389 ;
     RECT  16.56 12.389 17.082 12.413 ;
     RECT  6.804 11.885 14.346 12.475 ;
     RECT  3.996 12.325 5.706 12.509 ;
     RECT  2.268 12.379 2.934 12.551 ;
     RECT  15.408 12.353 15.426 12.551 ;
     RECT  16.56 12.413 16.578 12.557 ;
     RECT  6.444 12.475 14.346 12.619 ;
     RECT  5.115 12.509 5.706 12.721 ;
     RECT  6.444 12.619 14.886 12.721 ;
     RECT  3.996 12.509 4.23 12.859 ;
     RECT  2.268 12.551 2.862 12.991 ;
     RECT  5.115 12.721 14.886 13.019 ;
     RECT  2.16 12.991 2.862 13.037 ;
     RECT  3.852 12.859 4.23 13.325 ;
     RECT  6.372 13.019 14.886 13.339 ;
     RECT  2.268 13.037 2.862 13.369 ;
     RECT  6.372 13.339 14.922 13.435 ;
     RECT  4.14 13.325 4.23 13.531 ;
     RECT  2.268 13.369 3.33 13.559 ;
     RECT  2.268 13.559 2.79 13.565 ;
     RECT  4.14 13.531 4.374 13.567 ;
     RECT  5.115 13.019 5.397 13.567 ;
     RECT  17.136 13.579 17.154 13.603 ;
     RECT  4.14 13.567 5.397 13.915 ;
     RECT  6.372 13.435 15.426 13.915 ;
     RECT  4.14 13.915 15.426 14.071 ;
     RECT  17.064 13.603 17.154 14.144 ;
     RECT  3.6 14.071 15.426 14.369 ;
     RECT  1.26 14.347 1.278 14.443 ;
     RECT  1.152 14.443 1.278 14.477 ;
     RECT  2.304 13.565 2.79 14.485 ;
     RECT  3.6 14.369 13.95 14.485 ;
     RECT  2.304 14.485 13.95 14.513 ;
     RECT  2.304 14.513 5.397 14.639 ;
     RECT  3.708 14.639 5.397 14.669 ;
     RECT  6.264 14.513 13.95 14.819 ;
     RECT  16.524 14.779 16.542 15.017 ;
     RECT  2.304 14.639 2.862 15.151 ;
     RECT  3.816 14.669 5.397 15.179 ;
     RECT  1.152 14.477 1.17 15.389 ;
     RECT  3.852 15.179 5.397 15.449 ;
     RECT  2.268 15.151 2.862 15.493 ;
     RECT  5.115 15.449 5.397 15.493 ;
     RECT  6.84 14.819 13.95 15.601 ;
     RECT  14.832 14.369 15.426 15.601 ;
     RECT  2.268 15.493 3.114 15.791 ;
     RECT  6.84 15.601 15.426 15.791 ;
     RECT  2.304 15.791 3.114 15.961 ;
     RECT  3.852 15.449 4.194 15.961 ;
     RECT  16.524 15.835 16.542 15.979 ;
     RECT  16.524 15.979 17.154 16.025 ;
     RECT  16.524 16.025 17.082 16.061 ;
     RECT  5.115 15.493 5.922 16.069 ;
     RECT  6.84 15.791 13.914 16.069 ;
     RECT  0.252 16.075 0.27 16.253 ;
     RECT  2.304 15.961 4.194 16.339 ;
     RECT  5.115 16.069 13.914 16.339 ;
     RECT  14.832 15.791 15.426 16.349 ;
     RECT  2.304 16.339 13.914 16.589 ;
     RECT  2.304 16.589 13.842 16.799 ;
     RECT  16.524 16.061 16.614 16.843 ;
     RECT  2.304 16.799 5.454 16.877 ;
     RECT  16.524 16.843 17.082 16.879 ;
     RECT  16.524 16.879 17.154 16.925 ;
     RECT  1.152 16.795 1.17 16.973 ;
     RECT  16.524 16.925 16.578 17.105 ;
     RECT  14.832 16.349 14.886 17.179 ;
     RECT  14.832 17.179 15.426 17.221 ;
     RECT  6.336 16.799 13.842 17.383 ;
     RECT  14.616 17.221 15.426 17.383 ;
     RECT  6.336 17.383 15.462 17.411 ;
     RECT  6.66 17.411 15.462 17.501 ;
     RECT  2.304 16.877 2.754 17.609 ;
     RECT  0.54 17.077 0.666 17.693 ;
     RECT  16.56 17.105 16.578 17.693 ;
     RECT  6.66 17.501 15.426 17.753 ;
     RECT  3.6 16.877 5.454 17.761 ;
     RECT  6.84 17.753 15.426 17.789 ;
     RECT  1.152 17.755 1.17 17.851 ;
     RECT  6.912 17.789 15.426 17.951 ;
     RECT  1.152 17.851 1.278 17.981 ;
     RECT  16.524 17.899 16.542 18.023 ;
     RECT  3.492 17.761 5.454 18.031 ;
     RECT  6.984 17.951 15.426 18.149 ;
     RECT  7.056 18.149 13.914 18.185 ;
     RECT  3.492 18.031 5.922 18.193 ;
     RECT  3.492 18.193 6.102 18.221 ;
     RECT  3.96 18.221 6.102 18.293 ;
     RECT  2.304 17.609 2.697 18.391 ;
     RECT  14.832 18.149 15.426 18.427 ;
     RECT  1.152 17.981 1.17 18.461 ;
     RECT  14.832 18.427 15.462 18.563 ;
     RECT  2.304 18.391 2.718 18.571 ;
     RECT  1.98 18.571 3.078 18.749 ;
     RECT  7.056 18.185 13.842 18.931 ;
     RECT  17.136 19.003 17.154 19.039 ;
     RECT  17.064 19.039 17.154 19.067 ;
     RECT  2.304 18.749 3.078 19.075 ;
     RECT  3.96 18.293 5.397 19.075 ;
     RECT  17.064 19.067 17.082 19.085 ;
     RECT  0.252 18.907 0.27 19.111 ;
     RECT  14.832 18.563 15.426 19.201 ;
     RECT  0.216 19.111 0.306 19.229 ;
     RECT  2.304 19.075 5.397 19.229 ;
     RECT  7.02 18.931 13.842 19.237 ;
     RECT  0.288 19.229 0.306 19.277 ;
     RECT  3.492 19.229 5.397 19.291 ;
     RECT  7.02 19.237 13.914 19.615 ;
     RECT  14.688 19.201 15.426 19.615 ;
     RECT  3.492 19.291 5.706 19.651 ;
     RECT  3.492 19.651 5.814 19.769 ;
     RECT  7.02 19.615 15.426 19.777 ;
     RECT  6.408 19.777 15.426 19.901 ;
     RECT  6.732 19.901 15.426 19.949 ;
     RECT  2.304 19.229 2.697 20.047 ;
     RECT  3.492 19.769 5.397 20.047 ;
     RECT  6.732 19.949 11.718 20.075 ;
     RECT  2.304 20.047 5.397 20.219 ;
     RECT  1.152 20.107 1.17 20.251 ;
     RECT  1.152 20.251 1.386 20.381 ;
     RECT  6.732 20.075 11.61 20.381 ;
     RECT  6.804 20.381 11.61 20.429 ;
     RECT  1.296 20.381 1.314 20.477 ;
     RECT  12.564 19.949 15.426 20.491 ;
     RECT  2.34 20.219 5.397 20.551 ;
     RECT  0.216 20.539 0.234 20.587 ;
     RECT  2.34 20.551 5.634 20.621 ;
     RECT  12.564 20.491 15.462 20.651 ;
     RECT  17.136 20.635 17.154 20.659 ;
     RECT  0.216 20.587 0.306 20.687 ;
     RECT  12.564 20.651 15.426 20.695 ;
     RECT  2.34 20.621 3.546 20.971 ;
     RECT  17.064 20.659 17.154 21.029 ;
     RECT  17.064 21.029 17.082 21.053 ;
     RECT  6.84 20.429 11.61 21.091 ;
     RECT  12.348 20.695 15.426 21.091 ;
     RECT  2.304 20.971 3.546 21.191 ;
     RECT  4.428 20.621 5.634 21.271 ;
     RECT  4.428 21.271 5.922 21.389 ;
     RECT  6.84 21.091 15.426 21.433 ;
     RECT  3.528 21.191 3.546 21.451 ;
     RECT  4.428 21.389 5.67 21.451 ;
     RECT  0.252 20.687 0.27 21.629 ;
     RECT  3.528 21.451 5.67 21.659 ;
     RECT  16.524 21.271 16.614 21.695 ;
     RECT  6.66 21.433 15.426 21.739 ;
     RECT  16.596 21.695 16.614 21.787 ;
     RECT  6.516 21.739 15.426 21.803 ;
     RECT  2.304 21.191 2.754 21.901 ;
     RECT  16.596 21.787 17.154 21.929 ;
     RECT  16.596 21.929 17.082 21.965 ;
     RECT  2.268 21.901 2.754 21.973 ;
     RECT  3.528 21.659 5.397 21.973 ;
     RECT  2.268 21.973 5.397 22.157 ;
     RECT  0.54 22.171 0.558 22.253 ;
     RECT  16.596 21.965 16.614 22.301 ;
     RECT  2.304 22.157 5.397 22.441 ;
     RECT  6.876 21.803 15.426 22.469 ;
     RECT  6.876 22.469 11.718 22.505 ;
     RECT  16.524 22.459 16.542 22.505 ;
     RECT  2.304 22.441 5.454 22.549 ;
     RECT  6.876 22.505 11.43 22.555 ;
     RECT  2.304 22.549 5.67 22.739 ;
     RECT  12.564 22.469 15.426 22.739 ;
     RECT  1.152 22.603 1.278 22.781 ;
     RECT  0.216 23.227 0.234 23.279 ;
     RECT  2.304 22.739 5.397 23.279 ;
     RECT  12.564 22.739 13.842 23.371 ;
     RECT  2.304 23.279 4.23 23.423 ;
     RECT  12.456 23.371 13.842 23.563 ;
     RECT  14.832 22.739 15.426 23.563 ;
     RECT  2.304 23.423 3.258 23.621 ;
     RECT  6.804 22.555 11.43 23.621 ;
     RECT  6.984 23.621 11.43 23.659 ;
     RECT  12.456 23.563 15.426 23.819 ;
     RECT  17.136 23.851 17.154 23.863 ;
     RECT  6.984 23.659 11.682 23.935 ;
     RECT  12.456 23.819 14.058 23.935 ;
     RECT  1.152 23.947 1.17 23.995 ;
     RECT  3.996 23.423 4.23 24.061 ;
     RECT  5.004 23.279 5.397 24.061 ;
     RECT  1.152 23.995 1.278 24.125 ;
     RECT  17.064 23.863 17.154 24.235 ;
     RECT  1.26 24.125 1.278 24.413 ;
     RECT  16.524 24.235 17.154 24.431 ;
     RECT  16.524 24.431 17.082 24.461 ;
     RECT  2.304 23.621 3.114 24.475 ;
     RECT  3.996 24.061 5.397 24.475 ;
     RECT  14.832 23.819 15.426 24.701 ;
     RECT  6.984 23.935 14.058 24.715 ;
     RECT  14.832 24.701 15.066 24.749 ;
     RECT  6.84 24.715 14.058 24.773 ;
     RECT  6.948 24.773 14.058 24.781 ;
     RECT  14.832 24.749 14.922 24.781 ;
     RECT  2.304 24.475 5.397 24.871 ;
     RECT  2.304 24.871 5.886 24.941 ;
     RECT  16.524 24.461 16.542 25.313 ;
     RECT  2.304 24.941 5.397 25.339 ;
     RECT  6.948 24.781 14.922 25.483 ;
     RECT  1.98 25.339 5.397 25.511 ;
     RECT  6.948 25.483 15.426 25.579 ;
     RECT  6.804 25.579 15.426 25.825 ;
     RECT  17.064 25.963 17.082 25.987 ;
     RECT  17.064 25.987 17.154 26.045 ;
     RECT  1.152 25.771 1.17 26.093 ;
     RECT  0.252 26.011 0.27 26.189 ;
     RECT  6.264 25.825 15.426 26.293 ;
     RECT  6.264 26.293 15.462 26.333 ;
     RECT  6.264 26.333 15.426 26.587 ;
     RECT  6.228 26.587 15.426 26.627 ;
     RECT  6.696 26.627 15.426 26.933 ;
     RECT  0.54 26.599 0.558 27.005 ;
     RECT  2.304 25.511 5.397 27.365 ;
     RECT  3.816 27.365 5.397 27.643 ;
     RECT  16.524 26.731 16.542 27.677 ;
     RECT  6.804 26.933 15.426 27.707 ;
     RECT  6.84 27.707 15.426 27.841 ;
     RECT  0.252 27.787 0.27 27.913 ;
     RECT  1.152 27.841 1.17 27.913 ;
     RECT  0.252 27.913 1.17 27.917 ;
     RECT  6.84 27.841 15.462 27.917 ;
     RECT  6.876 27.917 15.462 27.941 ;
     RECT  14.832 27.941 15.462 27.965 ;
     RECT  3.816 27.643 5.454 28.183 ;
     RECT  2.304 27.365 2.754 28.291 ;
     RECT  3.672 28.183 5.454 28.291 ;
     RECT  2.304 28.291 5.454 28.315 ;
     RECT  14.832 27.965 15.426 28.319 ;
     RECT  0.288 27.917 1.17 28.445 ;
     RECT  0.54 28.445 1.17 28.541 ;
     RECT  6.876 27.941 13.77 28.747 ;
     RECT  16.524 28.699 16.542 28.751 ;
     RECT  6.84 28.747 13.77 28.891 ;
     RECT  6.588 28.891 13.77 29.101 ;
     RECT  14.904 28.319 15.426 29.179 ;
     RECT  2.304 28.315 5.49 29.219 ;
     RECT  3.492 29.219 5.49 29.371 ;
     RECT  6.588 29.101 14.058 29.371 ;
     RECT  14.832 29.179 15.426 29.371 ;
     RECT  1.152 28.541 1.17 29.461 ;
     RECT  0.54 29.461 1.17 29.467 ;
     RECT  3.492 29.371 5.598 29.489 ;
     RECT  6.588 29.371 15.426 29.561 ;
     RECT  6.588 29.561 14.022 29.569 ;
     RECT  3.492 29.489 5.397 29.597 ;
     RECT  16.524 29.515 16.542 29.611 ;
     RECT  16.524 29.611 16.578 29.633 ;
     RECT  6.264 29.569 14.022 29.759 ;
     RECT  0.54 29.467 1.278 29.789 ;
     RECT  3.492 29.597 3.546 29.789 ;
     RECT  6.264 29.759 13.95 29.789 ;
     RECT  16.56 29.633 16.578 29.803 ;
     RECT  16.56 29.803 17.082 29.839 ;
     RECT  16.56 29.839 17.154 29.867 ;
     RECT  6.264 29.789 13.914 29.885 ;
     RECT  17.136 29.867 17.154 29.885 ;
     RECT  3.492 29.789 3.51 30.029 ;
     RECT  14.832 29.561 15.426 30.043 ;
     RECT  14.832 30.043 15.462 30.101 ;
     RECT  1.152 29.789 1.278 30.125 ;
     RECT  2.304 29.219 2.697 30.187 ;
     RECT  6.264 29.885 6.282 30.451 ;
     RECT  4.464 29.597 5.397 30.541 ;
     RECT  0.252 30.475 0.27 30.605 ;
     RECT  2.268 30.187 2.697 30.613 ;
     RECT  4.428 30.541 5.397 30.613 ;
     RECT  7.416 29.885 13.914 30.613 ;
     RECT  6.228 30.451 6.282 30.677 ;
     RECT  7.344 30.613 13.914 30.749 ;
     RECT  7.344 30.749 11.718 30.797 ;
     RECT  2.268 30.613 3.33 30.811 ;
     RECT  4.284 30.613 5.397 30.811 ;
     RECT  14.832 30.101 15.426 30.811 ;
     RECT  7.344 30.797 11.574 30.991 ;
     RECT  12.564 30.749 13.914 30.991 ;
     RECT  14.76 30.811 15.426 30.991 ;
     RECT  2.268 30.811 5.397 31.019 ;
     RECT  2.304 31.019 5.397 31.195 ;
     RECT  2.304 31.195 5.454 31.379 ;
     RECT  16.524 31.195 16.542 31.483 ;
     RECT  12.564 30.991 15.426 31.495 ;
     RECT  1.152 31.147 1.17 31.531 ;
     RECT  1.152 31.531 1.458 31.709 ;
     RECT  1.152 31.709 1.386 31.757 ;
     RECT  1.152 31.757 1.17 31.853 ;
     RECT  3.492 31.379 5.454 31.919 ;
     RECT  16.524 31.483 16.578 31.997 ;
     RECT  0.252 31.771 0.27 32.189 ;
     RECT  16.56 31.997 16.578 32.203 ;
     RECT  6.804 30.991 11.574 32.233 ;
     RECT  12.492 31.495 15.426 32.233 ;
     RECT  16.56 32.203 17.082 32.233 ;
     RECT  3.492 31.919 5.397 32.261 ;
     RECT  16.56 32.233 17.154 32.285 ;
     RECT  2.304 31.379 2.697 32.575 ;
     RECT  4.212 32.261 5.397 32.737 ;
     RECT  6.804 32.233 15.426 32.765 ;
     RECT  4.212 32.737 5.598 32.809 ;
     RECT  4.212 32.809 5.706 32.881 ;
     RECT  11.988 32.765 15.426 32.881 ;
     RECT  16.56 32.285 16.578 33.019 ;
     RECT  16.56 33.019 17.082 33.043 ;
     RECT  4.212 32.881 6.03 33.067 ;
     RECT  6.804 32.765 11.214 33.067 ;
     RECT  0.216 32.971 0.234 33.101 ;
     RECT  16.56 33.043 17.154 33.101 ;
     RECT  2.304 32.575 3.222 33.241 ;
     RECT  4.212 33.067 11.214 33.241 ;
     RECT  11.988 32.881 15.462 33.293 ;
     RECT  2.304 33.241 11.214 33.341 ;
     RECT  2.304 33.341 5.397 33.421 ;
     RECT  2.268 33.421 5.397 33.533 ;
     RECT  11.988 33.293 15.426 33.539 ;
     RECT  6.552 33.341 11.214 33.655 ;
     RECT  11.988 33.539 13.842 33.655 ;
     RECT  16.56 33.101 16.578 33.883 ;
     RECT  1.152 33.883 1.17 34.027 ;
     RECT  1.152 34.027 1.278 34.157 ;
     RECT  16.56 33.883 16.65 34.171 ;
     RECT  16.416 34.171 16.65 34.187 ;
     RECT  2.304 33.533 5.397 34.231 ;
     RECT  6.552 33.655 13.842 34.231 ;
     RECT  2.304 34.231 13.842 34.349 ;
     RECT  6.228 34.349 13.842 34.393 ;
     RECT  14.688 33.539 15.426 34.393 ;
     RECT  6.228 34.393 15.426 34.493 ;
     RECT  2.304 34.349 5.397 34.619 ;
     RECT  0.252 34.555 0.27 34.733 ;
     RECT  16.416 34.187 16.578 34.763 ;
     RECT  7.02 34.493 15.426 34.781 ;
     RECT  6.228 34.493 6.246 34.961 ;
     RECT  1.152 34.157 1.17 35.035 ;
     RECT  3.924 34.619 5.397 35.131 ;
     RECT  1.152 35.035 1.278 35.213 ;
     RECT  3.924 35.131 5.958 35.429 ;
     RECT  3.924 35.429 4.374 35.453 ;
     RECT  7.02 34.781 13.842 35.467 ;
     RECT  2.304 34.619 3.042 35.509 ;
     RECT  3.924 35.453 4.158 35.509 ;
     RECT  2.304 35.509 4.158 35.515 ;
     RECT  14.832 34.781 15.426 35.515 ;
     RECT  16.56 34.763 16.578 35.549 ;
     RECT  14.616 35.515 15.426 35.573 ;
     RECT  14.616 35.573 15.066 35.609 ;
     RECT  5.115 35.429 5.706 35.699 ;
     RECT  6.804 35.467 13.842 35.699 ;
     RECT  6.84 35.699 13.842 35.741 ;
     RECT  16.524 35.755 16.542 36.077 ;
     RECT  6.876 35.741 13.842 36.121 ;
     RECT  5.115 35.699 5.397 36.211 ;
     RECT  1.98 35.515 4.158 36.239 ;
     RECT  3.6 36.239 4.158 36.269 ;
     RECT  1.98 36.239 2.754 36.317 ;
     RECT  1.98 36.317 2.718 36.365 ;
     RECT  3.6 36.269 3.978 36.365 ;
     RECT  5.076 36.211 5.397 36.481 ;
     RECT  6.876 36.121 13.986 36.481 ;
     RECT  5.076 36.481 5.454 36.517 ;
     RECT  6.696 36.481 13.986 36.571 ;
     RECT  14.832 35.609 15.066 36.571 ;
     RECT  15.984 36.553 16.002 36.571 ;
     RECT  5.076 36.517 5.526 36.589 ;
     RECT  6.588 36.571 13.986 36.619 ;
     RECT  14.832 36.571 16.002 36.619 ;
     RECT  6.588 36.619 16.002 36.625 ;
     RECT  6.264 36.625 16.002 36.797 ;
     RECT  3.6 36.365 3.762 37.057 ;
     RECT  6.264 36.797 15.462 37.085 ;
     RECT  5.004 36.589 5.526 37.147 ;
     RECT  14.508 37.085 15.462 37.193 ;
     RECT  2.304 36.365 2.718 37.291 ;
     RECT  3.492 37.057 3.762 37.291 ;
     RECT  4.536 37.147 5.526 37.291 ;
     RECT  6.264 37.085 13.698 37.391 ;
     RECT  16.524 37.363 16.542 37.421 ;
     RECT  6.66 37.391 13.698 37.463 ;
     RECT  2.304 37.291 5.526 37.471 ;
     RECT  2.304 37.471 5.778 37.499 ;
     RECT  3.636 37.499 5.778 37.589 ;
     RECT  0.252 37.243 0.27 37.597 ;
     RECT  14.508 37.193 15.426 37.625 ;
     RECT  0.216 37.597 0.27 37.661 ;
     RECT  14.796 37.625 15.426 37.859 ;
     RECT  0.252 37.661 0.27 37.903 ;
     RECT  6.768 37.463 13.698 38.011 ;
     RECT  3.636 37.589 5.67 38.129 ;
     RECT  6.768 38.011 13.842 38.201 ;
     RECT  2.304 37.499 2.826 38.281 ;
     RECT  3.636 38.129 5.397 38.281 ;
     RECT  0.252 37.903 0.558 38.285 ;
     RECT  2.304 38.281 5.397 38.347 ;
     RECT  2.268 38.347 5.397 38.429 ;
     RECT  2.268 38.429 2.862 38.525 ;
     RECT  6.768 38.201 13.806 38.551 ;
     RECT  16.524 38.251 16.542 38.551 ;
     RECT  0.252 38.285 0.27 38.621 ;
     RECT  6.588 38.551 13.806 38.621 ;
     RECT  7.2 38.621 13.806 38.669 ;
     RECT  14.832 37.859 15.426 38.741 ;
     RECT  7.272 38.669 13.806 38.765 ;
     RECT  16.524 38.551 16.614 38.765 ;
     RECT  12.276 38.765 13.806 39.019 ;
     RECT  16.524 38.765 16.542 39.101 ;
     RECT  6.228 38.683 6.246 39.119 ;
     RECT  2.268 38.525 2.826 39.181 ;
     RECT  12.276 39.019 14.058 39.209 ;
     RECT  2.196 39.181 2.826 39.245 ;
     RECT  7.416 38.765 11.538 39.281 ;
     RECT  3.708 38.429 5.397 39.293 ;
     RECT  4.428 39.293 5.397 39.325 ;
     RECT  4.428 39.325 5.958 39.479 ;
     RECT  2.304 39.245 2.826 39.547 ;
     RECT  14.832 38.741 14.886 39.547 ;
     RECT  7.416 39.281 11.358 39.559 ;
     RECT  7.02 39.559 11.358 39.595 ;
     RECT  5.004 39.479 5.958 39.749 ;
     RECT  6.804 39.595 11.358 39.749 ;
     RECT  12.276 39.209 13.806 39.793 ;
     RECT  14.832 39.547 14.994 39.979 ;
     RECT  12.096 39.793 13.806 39.991 ;
     RECT  16.524 39.883 16.542 40.063 ;
     RECT  16.488 40.063 16.542 40.109 ;
     RECT  5.004 39.749 5.397 40.261 ;
     RECT  2.304 39.547 3.294 40.297 ;
     RECT  16.524 40.109 16.542 40.297 ;
     RECT  12.096 39.991 13.986 40.325 ;
     RECT  16.524 40.297 16.578 40.433 ;
     RECT  16.56 40.433 16.578 40.445 ;
     RECT  14.832 39.979 15.426 40.507 ;
     RECT  6.804 39.749 11.106 40.531 ;
     RECT  0.216 40.261 0.234 40.589 ;
     RECT  17.064 40.555 17.154 40.595 ;
     RECT  17.064 40.595 17.082 40.637 ;
     RECT  2.304 40.297 3.51 40.639 ;
     RECT  4.464 40.261 5.397 40.639 ;
     RECT  12.492 40.325 13.986 40.639 ;
     RECT  14.796 40.507 15.426 40.639 ;
     RECT  6.804 40.531 11.61 40.699 ;
     RECT  6.444 40.699 11.61 40.739 ;
     RECT  12.492 40.639 15.426 40.829 ;
     RECT  14.832 40.829 15.426 40.843 ;
     RECT  6.444 40.739 11.574 40.865 ;
     RECT  6.264 40.873 6.282 40.909 ;
     RECT  2.304 40.639 5.397 40.937 ;
     RECT  14.832 40.843 15.462 40.973 ;
     RECT  1.26 41.083 1.278 41.179 ;
     RECT  1.152 41.179 1.278 41.213 ;
     RECT  1.152 41.213 1.17 41.357 ;
     RECT  12.492 40.829 13.842 41.377 ;
     RECT  14.832 40.973 14.922 41.441 ;
     RECT  7.164 40.865 11.574 41.611 ;
     RECT  12.348 41.377 13.842 41.611 ;
     RECT  6.228 40.909 6.282 41.659 ;
     RECT  7.164 41.611 13.842 41.659 ;
     RECT  2.304 40.937 2.862 41.707 ;
     RECT  3.744 40.937 5.397 41.707 ;
     RECT  6.228 41.659 13.842 41.755 ;
     RECT  2.304 41.707 5.397 41.791 ;
     RECT  6.228 41.755 13.986 41.791 ;
     RECT  2.304 41.791 13.986 41.819 ;
     RECT  0.252 41.419 0.27 41.953 ;
     RECT  6.624 41.819 13.986 41.953 ;
     RECT  14.832 41.441 14.886 41.953 ;
     RECT  2.304 41.819 5.886 42.017 ;
     RECT  2.304 42.017 5.814 42.089 ;
     RECT  6.624 41.953 14.886 42.179 ;
     RECT  14.76 42.179 14.886 42.259 ;
     RECT  2.304 42.089 5.742 42.317 ;
     RECT  0.252 41.953 0.558 42.331 ;
     RECT  0.216 42.331 0.558 42.368 ;
     RECT  2.304 42.317 5.49 42.449 ;
     RECT  0.54 42.368 0.558 42.461 ;
     RECT  2.304 42.449 2.79 43.003 ;
     RECT  3.852 42.449 5.49 43.025 ;
     RECT  6.624 42.179 13.842 43.099 ;
     RECT  14.76 42.259 15.426 43.099 ;
     RECT  5.115 43.025 5.49 43.141 ;
     RECT  16.524 41.563 16.542 43.141 ;
     RECT  1.98 43.003 2.79 43.181 ;
     RECT  5.115 43.141 5.562 43.259 ;
     RECT  6.624 43.099 15.426 43.259 ;
     RECT  12.204 43.259 15.426 43.331 ;
     RECT  2.268 43.181 2.79 43.339 ;
     RECT  16.524 43.141 16.614 43.387 ;
     RECT  2.268 43.339 2.898 43.403 ;
     RECT  6.624 43.259 11.43 43.421 ;
     RECT  16.524 43.387 17.154 43.439 ;
     RECT  16.524 43.439 17.082 43.469 ;
     RECT  2.304 43.403 2.898 43.501 ;
     RECT  5.115 43.259 5.49 43.601 ;
     RECT  0.252 43.531 0.27 43.681 ;
     RECT  2.304 43.501 2.97 43.771 ;
     RECT  3.852 43.025 4.158 43.771 ;
     RECT  12.204 43.331 14.85 43.799 ;
     RECT  2.304 43.771 4.158 43.901 ;
     RECT  3.996 43.901 4.158 43.915 ;
     RECT  5.115 43.601 5.397 43.915 ;
     RECT  0.216 43.681 0.306 43.949 ;
     RECT  0.216 43.949 0.234 43.997 ;
     RECT  6.804 43.421 11.43 44.155 ;
     RECT  12.204 43.799 13.842 44.155 ;
     RECT  14.832 43.799 14.85 44.155 ;
     RECT  6.804 44.155 13.842 44.221 ;
     RECT  14.832 44.155 14.922 44.251 ;
     RECT  3.996 43.915 5.397 44.339 ;
     RECT  6.48 44.221 13.842 44.411 ;
     RECT  14.832 44.251 14.958 44.443 ;
     RECT  5.115 44.339 5.397 44.491 ;
     RECT  14.832 44.443 15.426 44.539 ;
     RECT  6.768 44.411 13.842 44.581 ;
     RECT  14.832 44.539 15.462 44.581 ;
     RECT  5.115 44.491 6.03 44.609 ;
     RECT  6.768 44.581 15.462 44.621 ;
     RECT  6.804 44.621 15.462 44.681 ;
     RECT  1.26 44.779 1.278 44.909 ;
     RECT  5.115 44.609 5.742 44.909 ;
     RECT  6.804 44.681 15.426 44.915 ;
     RECT  16.524 43.469 16.542 44.971 ;
     RECT  2.304 43.901 3.186 44.995 ;
     RECT  3.996 44.339 4.014 44.995 ;
     RECT  6.912 44.915 15.426 45.005 ;
     RECT  6.912 45.005 14.13 45.023 ;
     RECT  14.868 45.005 15.426 45.023 ;
     RECT  16.524 44.971 16.578 45.293 ;
     RECT  2.304 44.995 4.014 45.301 ;
     RECT  5.115 44.909 5.397 45.301 ;
     RECT  2.304 45.301 5.397 45.307 ;
     RECT  14.904 45.023 15.426 45.403 ;
     RECT  14.904 45.403 15.462 45.491 ;
     RECT  2.268 45.307 5.397 45.761 ;
     RECT  14.904 45.491 15.426 45.787 ;
     RECT  6.912 45.023 14.058 45.805 ;
     RECT  5.115 45.761 5.397 45.841 ;
     RECT  2.268 45.761 4.302 45.965 ;
     RECT  6.84 45.805 14.058 46.013 ;
     RECT  5.115 45.841 5.994 46.273 ;
     RECT  2.304 45.965 4.302 46.301 ;
     RECT  5.115 46.273 6.066 46.409 ;
     RECT  0.252 45.979 0.27 46.492 ;
     RECT  14.832 45.787 15.426 46.571 ;
     RECT  3.528 46.301 4.302 46.603 ;
     RECT  5.115 46.409 5.397 46.603 ;
     RECT  0.216 46.492 0.306 46.637 ;
     RECT  0.216 46.637 0.234 46.685 ;
     RECT  16.524 45.293 16.542 46.841 ;
     RECT  6.876 46.013 14.058 46.891 ;
     RECT  15.408 46.571 15.426 47.035 ;
     RECT  2.304 46.301 2.79 47.047 ;
     RECT  3.528 46.603 5.397 47.047 ;
     RECT  6.264 46.891 14.058 47.069 ;
     RECT  15.408 47.035 15.462 47.111 ;
     RECT  6.516 47.069 14.058 47.131 ;
     RECT  2.304 47.047 5.397 47.425 ;
     RECT  15.408 47.111 15.426 47.453 ;
     RECT  6.516 47.131 14.274 47.467 ;
     RECT  0.576 47.803 0.594 47.821 ;
     RECT  2.304 47.425 5.706 47.849 ;
     RECT  0.54 47.821 0.594 47.851 ;
     RECT  2.304 47.849 5.49 47.885 ;
     RECT  0.54 47.851 0.666 47.891 ;
     RECT  0.54 47.891 0.558 47.933 ;
     RECT  15.984 47.857 16.002 47.933 ;
     RECT  2.304 47.885 5.397 48.091 ;
     RECT  6.516 47.467 14.85 48.091 ;
     RECT  6.3 48.091 14.85 48.271 ;
     RECT  6.3 48.271 15.426 48.299 ;
     RECT  12.312 48.299 15.426 48.317 ;
     RECT  6.3 48.299 11.25 48.389 ;
     RECT  17.064 48.379 17.082 48.397 ;
     RECT  12.312 48.317 14.886 48.425 ;
     RECT  6.516 48.389 11.25 48.461 ;
     RECT  12.312 48.425 13.842 48.461 ;
     RECT  17.064 48.397 17.154 48.461 ;
     RECT  2.268 48.091 5.397 48.619 ;
     RECT  1.98 48.619 5.397 48.797 ;
     RECT  17.064 48.461 17.082 48.811 ;
     RECT  2.304 48.797 5.397 48.929 ;
     RECT  16.524 48.811 17.082 49.037 ;
     RECT  14.832 48.425 14.886 49.045 ;
     RECT  0.54 48.973 0.558 49.051 ;
     RECT  0.54 49.051 0.666 49.085 ;
     RECT  14.832 49.045 14.922 49.147 ;
     RECT  0.648 49.085 0.666 49.181 ;
     RECT  6.552 48.461 11.25 49.243 ;
     RECT  12.528 48.461 13.842 49.315 ;
     RECT  6.228 49.243 11.25 49.351 ;
     RECT  11.988 49.315 13.842 49.351 ;
     RECT  14.832 49.147 15.426 49.351 ;
     RECT  6.228 49.351 15.426 49.541 ;
     RECT  16.524 49.037 16.542 49.577 ;
     RECT  6.804 49.541 15.426 49.649 ;
     RECT  3.924 48.929 5.397 49.747 ;
     RECT  2.304 48.929 2.97 49.819 ;
     RECT  3.708 49.747 5.397 49.819 ;
     RECT  6.84 49.649 15.426 49.901 ;
     RECT  2.304 49.819 5.397 49.963 ;
     RECT  1.98 49.963 5.397 50.009 ;
     RECT  6.876 49.901 15.426 50.009 ;
     RECT  1.152 49.981 1.17 50.053 ;
     RECT  1.98 50.009 2.826 50.153 ;
     RECT  3.708 50.009 5.397 50.161 ;
     RECT  0.54 50.053 1.17 50.333 ;
     RECT  3.708 50.161 5.49 50.629 ;
     RECT  3.708 50.629 5.742 50.693 ;
     RECT  1.152 50.333 1.17 50.717 ;
     RECT  3.852 50.693 5.742 50.729 ;
     RECT  6.876 50.009 13.914 50.731 ;
     RECT  6.732 50.731 13.914 50.779 ;
     RECT  4.14 50.729 5.742 51.269 ;
     RECT  4.356 51.269 5.742 51.367 ;
     RECT  6.516 50.779 13.914 51.367 ;
     RECT  4.356 51.367 13.95 51.439 ;
     RECT  4.356 51.439 14.094 51.475 ;
     RECT  14.832 50.009 15.426 51.475 ;
     RECT  4.356 51.475 15.426 51.533 ;
     RECT  2.304 50.153 2.826 51.629 ;
     RECT  4.356 51.533 5.742 51.725 ;
     RECT  4.356 51.725 5.397 52.015 ;
     RECT  6.768 51.533 15.426 52.079 ;
     RECT  3.924 52.015 5.397 52.321 ;
     RECT  2.304 51.629 2.697 52.348 ;
     RECT  2.268 52.348 2.697 52.439 ;
     RECT  16.524 50.347 16.542 52.583 ;
     RECT  2.304 52.439 2.697 52.717 ;
     RECT  3.456 52.321 5.397 52.717 ;
     RECT  0.288 52.795 0.306 52.891 ;
     RECT  6.804 52.079 15.426 52.979 ;
     RECT  0.288 52.891 0.414 53.021 ;
     RECT  6.804 52.979 13.95 53.021 ;
     RECT  2.304 52.717 5.397 53.221 ;
     RECT  1.26 53.275 1.278 53.371 ;
     RECT  2.304 53.221 5.778 53.519 ;
     RECT  3.96 53.519 5.778 53.527 ;
     RECT  6.804 53.021 13.77 53.527 ;
     RECT  1.152 53.371 1.278 53.837 ;
     RECT  3.96 53.527 13.77 53.851 ;
     RECT  3.96 53.851 13.842 53.869 ;
     RECT  14.832 52.979 15.426 53.869 ;
     RECT  3.96 53.869 15.426 53.941 ;
     RECT  2.304 53.519 3.114 53.995 ;
     RECT  3.96 53.941 15.462 54.131 ;
     RECT  3.96 54.131 6.102 54.365 ;
     RECT  0.252 54.235 0.27 54.373 ;
     RECT  2.268 53.995 3.114 54.373 ;
     RECT  3.96 54.365 5.67 54.373 ;
     RECT  2.268 54.373 5.67 54.509 ;
     RECT  6.84 54.131 15.462 54.557 ;
     RECT  0.252 54.373 0.558 54.701 ;
     RECT  0.54 54.701 0.558 54.749 ;
     RECT  2.268 54.509 5.397 55.099 ;
     RECT  6.84 54.557 15.426 55.099 ;
     RECT  2.232 55.099 5.397 55.139 ;
     RECT  6.804 55.099 15.426 55.139 ;
     RECT  1.152 55.099 1.17 55.147 ;
     RECT  1.152 55.147 1.278 55.277 ;
     RECT  14.832 55.139 15.426 55.283 ;
     RECT  2.304 55.139 5.397 55.489 ;
     RECT  2.304 55.489 5.706 55.525 ;
     RECT  6.804 55.139 14.058 55.525 ;
     RECT  16.524 55.051 16.542 55.531 ;
     RECT  16.524 55.531 17.154 55.589 ;
     RECT  16.524 55.589 17.082 55.613 ;
     RECT  14.832 55.283 14.85 55.751 ;
     RECT  16.524 55.613 16.614 56.093 ;
     RECT  2.304 55.525 14.058 56.191 ;
     RECT  15.408 56.059 15.426 56.203 ;
     RECT  0.252 56.107 0.27 56.284 ;
     RECT  0.216 56.284 0.306 56.381 ;
     RECT  2.304 56.191 14.094 56.399 ;
     RECT  0.216 56.381 0.27 56.429 ;
     RECT  15.408 56.203 15.498 56.491 ;
     RECT  14.832 56.491 15.498 56.533 ;
     RECT  16.524 56.093 16.542 56.533 ;
     RECT  14.832 56.533 16.542 56.573 ;
     RECT  14.832 56.573 16.002 56.717 ;
     RECT  3.996 56.399 14.094 56.759 ;
     RECT  12.528 56.759 14.094 56.765 ;
     RECT  0.252 56.429 0.27 56.813 ;
     RECT  3.996 56.759 11.718 56.903 ;
     RECT  12.564 56.765 14.094 57.115 ;
     RECT  14.832 56.717 15.462 57.115 ;
     RECT  3.996 56.903 11.466 57.173 ;
     RECT  12.564 57.115 15.462 57.173 ;
     RECT  2.304 56.399 3.15 57.181 ;
     RECT  3.996 57.173 4.374 57.181 ;
     RECT  16.524 57.307 16.542 57.403 ;
     RECT  0.216 57.415 0.234 57.485 ;
     RECT  2.304 57.181 4.374 57.581 ;
     RECT  5.115 57.173 11.466 57.835 ;
     RECT  5.115 57.835 11.754 57.931 ;
     RECT  16.524 57.403 16.578 57.979 ;
     RECT  5.115 57.931 11.826 58.157 ;
     RECT  0.54 57.541 0.558 58.205 ;
     RECT  16.524 57.979 17.154 58.205 ;
     RECT  12.564 57.173 15.426 58.363 ;
     RECT  2.304 57.581 4.194 58.411 ;
     RECT  12.564 58.363 15.462 58.451 ;
     RECT  1.98 58.411 4.194 58.459 ;
     RECT  1.98 58.459 4.23 58.507 ;
     RECT  5.115 58.157 6.03 58.507 ;
     RECT  6.804 58.157 11.826 58.531 ;
     RECT  12.564 58.451 15.426 58.531 ;
     RECT  1.98 58.507 4.302 58.589 ;
     RECT  2.268 58.589 4.302 58.649 ;
     RECT  5.112 58.507 6.03 58.649 ;
     RECT  6.804 58.531 15.426 58.649 ;
     RECT  5.115 58.649 6.03 58.685 ;
     RECT  6.804 58.649 11.718 58.685 ;
     RECT  2.268 58.649 4.122 58.919 ;
     RECT  17.064 58.205 17.154 58.955 ;
     RECT  17.136 58.955 17.154 58.973 ;
     RECT  12.456 58.649 15.426 59.099 ;
     RECT  6.804 58.685 11.574 59.261 ;
     RECT  5.115 58.685 5.994 59.431 ;
     RECT  6.804 59.261 11.142 59.431 ;
     RECT  12.456 59.099 13.842 59.515 ;
     RECT  2.304 58.919 4.122 59.837 ;
     RECT  11.988 59.515 13.842 59.971 ;
     RECT  14.58 59.099 15.426 59.971 ;
     RECT  5.004 59.431 11.142 59.995 ;
     RECT  11.988 59.971 15.426 59.995 ;
     RECT  2.304 59.837 3.438 60.077 ;
     RECT  5.004 59.995 15.426 60.115 ;
     RECT  4.176 60.115 15.426 60.227 ;
     RECT  2.412 60.077 3.438 60.269 ;
     RECT  4.176 60.227 5.205 60.269 ;
     RECT  5.976 60.227 15.426 60.269 ;
     RECT  4.176 60.269 4.266 60.305 ;
     RECT  10.44 60.269 11.358 60.305 ;
     RECT  2.412 60.269 2.574 60.317 ;
     RECT  13.032 60.269 13.41 60.317 ;
     RECT  14.22 60.269 15.426 60.341 ;
     RECT  3.348 60.269 3.438 60.365 ;
     RECT  5.976 60.269 9.45 60.365 ;
     RECT  0.252 59.899 0.27 60.413 ;
     RECT  3.42 60.365 3.438 60.413 ;
     RECT  4.248 60.305 4.266 60.413 ;
     RECT  5.976 60.365 6.606 60.413 ;
     RECT  14.832 60.341 14.886 60.413 ;
     RECT  7.344 60.365 9.45 60.449 ;
     RECT  9.072 60.449 9.45 60.461 ;
     RECT  2.415 60.317 2.505 60.497 ;
     RECT  5.115 60.269 5.205 60.497 ;
     RECT  5.976 60.413 6.57 60.539 ;
     RECT  13.104 60.317 13.41 60.557 ;
     RECT  14.868 60.413 14.886 60.557 ;
     RECT  9.072 60.461 9.198 60.575 ;
     RECT  10.476 60.305 11.358 60.575 ;
     RECT  5.976 60.539 6.498 60.605 ;
     RECT  10.692 60.575 10.854 60.605 ;
     RECT  7.344 60.449 8.082 60.611 ;
     RECT  9.18 60.575 9.198 60.611 ;
     RECT  8.064 60.611 8.082 60.653 ;
     RECT  10.692 60.605 10.71 60.653 ;
     RECT  5.976 60.605 5.994 61.277 ;
    LAYER M4 ;
     RECT  0.192 2.208 0.323 2.232 ;
     RECT  0.156 2.232 0.323 2.304 ;
     RECT  0.192 2.304 0.323 2.328 ;
     RECT  0.156 2.328 0.323 2.448 ;
     RECT  0.192 2.448 0.323 2.472 ;
     RECT  0.156 2.472 0.323 2.544 ;
     RECT  0.192 2.544 0.323 2.568 ;
     RECT  0.156 2.568 0.323 2.64 ;
     RECT  0.192 2.64 0.323 2.664 ;
     RECT  0.156 2.664 0.323 2.736 ;
     RECT  0.192 2.736 0.323 2.76 ;
     RECT  0.156 2.76 0.323 2.832 ;
     RECT  0.192 2.832 0.323 2.856 ;
     RECT  0.156 2.856 0.323 2.928 ;
     RECT  0.192 2.928 0.323 2.952 ;
     RECT  0.156 2.952 0.323 3.072 ;
     RECT  0.192 3.072 0.323 3.096 ;
     RECT  0.156 3.096 0.323 3.168 ;
     RECT  0.192 3.168 0.323 3.192 ;
     RECT  0.156 3.192 0.323 3.264 ;
     RECT  0.192 3.264 0.323 3.288 ;
     RECT  0.156 3.288 0.323 3.36 ;
     RECT  0.192 3.36 0.323 3.384 ;
     RECT  0.156 3.384 0.323 3.456 ;
     RECT  0.192 3.456 0.323 3.48 ;
     RECT  0.156 3.48 0.323 3.552 ;
     RECT  0.192 3.552 0.323 3.576 ;
     RECT  0.156 3.576 0.323 3.696 ;
     RECT  0.192 3.696 0.323 3.72 ;
     RECT  0.156 3.72 0.323 3.792 ;
     RECT  0.192 3.792 0.323 3.816 ;
     RECT  0.156 3.816 0.323 3.888 ;
     RECT  0.192 3.888 0.323 3.912 ;
     RECT  0.156 3.912 0.323 3.984 ;
     RECT  0.192 3.984 0.323 4.008 ;
     RECT  0.156 4.008 0.323 4.08 ;
     RECT  0.192 4.08 0.323 4.104 ;
     RECT  0.156 4.104 0.323 4.176 ;
     RECT  0.192 4.176 0.323 4.2 ;
     RECT  0.156 4.2 0.323 4.272 ;
     RECT  0.192 4.272 0.323 4.296 ;
     RECT  0.156 4.296 0.323 4.416 ;
     RECT  0.192 4.416 0.323 4.44 ;
     RECT  0.156 4.44 0.323 4.512 ;
     RECT  0.192 4.512 0.323 4.536 ;
     RECT  0.156 4.536 0.323 4.608 ;
     RECT  0.192 4.608 0.323 4.632 ;
     RECT  0.156 4.632 0.323 4.704 ;
     RECT  0.192 4.704 0.323 4.728 ;
     RECT  0.156 4.728 0.323 4.8 ;
     RECT  0.192 4.8 0.323 4.824 ;
     RECT  0.156 4.824 0.323 4.896 ;
     RECT  0.192 4.896 0.323 4.92 ;
     RECT  0.156 4.92 0.323 5.04 ;
     RECT  0.192 5.04 0.323 5.064 ;
     RECT  0.156 5.064 0.323 5.136 ;
     RECT  0.192 5.136 0.323 5.16 ;
     RECT  0.156 5.16 0.323 5.232 ;
     RECT  0.192 5.232 0.323 5.256 ;
     RECT  0.156 5.256 0.323 5.328 ;
     RECT  0.192 5.328 0.323 5.352 ;
     RECT  0.156 5.352 0.323 5.424 ;
     RECT  0.192 5.424 0.323 5.448 ;
     RECT  0.156 5.448 0.323 5.52 ;
     RECT  0.192 5.52 0.323 5.544 ;
     RECT  0.156 5.544 0.323 5.664 ;
     RECT  0.192 5.664 0.323 5.688 ;
     RECT  0.156 5.688 0.323 5.76 ;
     RECT  0.192 5.76 0.323 5.784 ;
     RECT  0.156 5.784 0.323 5.856 ;
     RECT  0.192 5.856 0.323 5.88 ;
     RECT  0.156 5.88 0.323 5.952 ;
     RECT  0.192 5.952 0.323 5.976 ;
     RECT  0.156 5.976 0.323 6.048 ;
     RECT  0.192 6.048 0.323 6.072 ;
     RECT  0.156 6.072 0.323 6.144 ;
     RECT  0.192 6.144 0.323 6.168 ;
     RECT  0.156 6.168 0.323 6.24 ;
     RECT  0.192 6.24 0.323 6.264 ;
     RECT  0.156 6.264 0.323 6.384 ;
     RECT  0.192 6.384 0.323 6.408 ;
     RECT  0.156 6.408 0.323 6.48 ;
     RECT  0.192 6.48 0.323 6.504 ;
     RECT  0.156 6.504 0.323 6.576 ;
     RECT  0.192 6.576 0.323 6.6 ;
     RECT  0.156 6.6 0.323 6.672 ;
     RECT  0.192 6.672 0.323 6.696 ;
     RECT  0.156 6.696 0.323 6.768 ;
     RECT  0.192 6.768 0.323 6.792 ;
     RECT  0.156 6.792 0.323 6.864 ;
     RECT  0.192 6.864 0.323 6.888 ;
     RECT  0.156 6.888 0.323 7.008 ;
     RECT  0.192 7.008 0.323 7.032 ;
     RECT  0.156 7.032 0.323 7.104 ;
     RECT  0.192 7.104 0.323 7.128 ;
     RECT  0.156 7.128 0.323 7.2 ;
     RECT  0.192 7.2 0.323 7.224 ;
     RECT  0.156 7.224 0.323 7.296 ;
     RECT  0.192 7.296 0.323 7.32 ;
     RECT  0.156 7.32 0.323 7.392 ;
     RECT  0.192 7.392 0.323 7.416 ;
     RECT  0.156 7.416 0.323 7.488 ;
     RECT  0.192 7.488 0.323 7.512 ;
     RECT  0.156 7.512 0.323 7.632 ;
     RECT  0.192 7.632 0.323 7.656 ;
     RECT  0.156 7.656 0.323 7.728 ;
     RECT  0.192 7.728 0.323 7.752 ;
     RECT  0.156 7.752 0.323 7.824 ;
     RECT  0.192 7.824 0.323 7.848 ;
     RECT  0.156 7.848 0.323 7.92 ;
     RECT  0.192 7.92 0.323 7.944 ;
     RECT  0.156 7.944 0.323 8.016 ;
     RECT  0.192 8.016 0.323 8.04 ;
     RECT  0.156 8.04 0.323 8.112 ;
     RECT  0.192 8.112 0.323 8.136 ;
     RECT  0.156 8.136 0.323 8.208 ;
     RECT  0.192 8.208 0.323 8.232 ;
     RECT  0.156 8.232 0.323 8.352 ;
     RECT  0.192 8.352 0.323 8.376 ;
     RECT  0.156 8.376 0.323 8.448 ;
     RECT  0.192 8.448 0.323 8.472 ;
     RECT  0.156 8.472 0.323 8.544 ;
     RECT  0.192 8.544 0.323 8.568 ;
     RECT  0.156 8.568 0.323 8.64 ;
     RECT  0.192 8.64 0.323 8.664 ;
     RECT  0.156 8.664 0.323 8.736 ;
     RECT  0.192 8.736 0.323 8.76 ;
     RECT  0.156 8.76 0.323 8.832 ;
     RECT  0.192 8.832 0.323 8.856 ;
     RECT  0.156 8.856 0.323 8.976 ;
     RECT  0.192 8.976 0.323 9 ;
     RECT  0.156 9 0.323 9.072 ;
     RECT  0.192 9.072 0.323 9.096 ;
     RECT  0.156 9.096 0.323 9.168 ;
     RECT  0.192 9.168 0.323 9.192 ;
     RECT  0.156 9.192 0.323 9.264 ;
     RECT  0.192 9.264 0.323 9.288 ;
     RECT  0.156 9.288 0.323 9.36 ;
     RECT  0.192 9.36 0.323 9.384 ;
     RECT  0.156 9.384 0.323 9.456 ;
     RECT  0.192 9.456 0.323 9.48 ;
     RECT  0.156 9.48 0.323 9.6 ;
     RECT  0.192 9.6 0.323 9.624 ;
     RECT  0.156 9.624 0.323 9.696 ;
     RECT  0.192 9.696 0.323 9.72 ;
     RECT  0.156 9.72 0.323 9.792 ;
     RECT  0.192 9.792 0.323 9.816 ;
     RECT  0.156 9.816 0.323 9.888 ;
     RECT  0.192 9.888 0.323 9.912 ;
     RECT  0.156 9.912 0.323 9.984 ;
     RECT  0.192 9.984 0.323 10.008 ;
     RECT  0.156 10.008 0.323 10.08 ;
     RECT  0.192 10.08 0.323 10.104 ;
     RECT  0.156 10.104 0.323 10.224 ;
     RECT  0.192 10.224 0.323 10.248 ;
     RECT  0.156 10.248 0.323 10.32 ;
     RECT  0.192 10.32 0.323 10.344 ;
     RECT  0.156 10.344 0.323 10.416 ;
     RECT  0.192 10.416 0.323 10.44 ;
     RECT  0.156 10.44 0.323 10.512 ;
     RECT  0.192 10.512 0.323 10.536 ;
     RECT  0.156 10.536 0.323 10.608 ;
     RECT  0.192 10.608 0.323 10.632 ;
     RECT  0.156 10.632 0.323 10.704 ;
     RECT  0.192 10.704 0.323 10.728 ;
     RECT  0.156 10.728 0.323 10.8 ;
     RECT  0.192 10.8 0.323 10.824 ;
     RECT  0.156 10.824 0.323 10.944 ;
     RECT  0.192 10.944 0.323 10.968 ;
     RECT  0.156 10.968 0.323 11.04 ;
     RECT  0.192 11.04 0.323 11.064 ;
     RECT  0.156 11.064 0.323 11.136 ;
     RECT  0.192 11.136 0.323 11.16 ;
     RECT  0.156 11.16 0.323 11.232 ;
     RECT  0.192 11.232 0.323 11.256 ;
     RECT  0.156 11.256 0.323 11.328 ;
     RECT  0.192 11.328 0.323 11.352 ;
     RECT  0.156 11.352 0.323 11.424 ;
     RECT  0.192 11.424 0.323 11.448 ;
     RECT  0.156 11.448 0.323 11.568 ;
     RECT  0.192 11.568 0.323 11.592 ;
     RECT  0.156 11.592 0.323 11.664 ;
     RECT  0.192 11.664 0.323 11.688 ;
     RECT  0.156 11.688 0.323 11.76 ;
     RECT  0.192 11.76 0.323 11.784 ;
     RECT  0.156 11.784 0.323 11.856 ;
     RECT  0.192 11.856 0.323 11.88 ;
     RECT  0.156 11.88 0.323 11.952 ;
     RECT  0.192 11.952 0.323 11.976 ;
     RECT  0.156 11.976 0.323 12.048 ;
     RECT  0.192 12.048 0.323 12.072 ;
     RECT  0.156 12.072 0.323 12.192 ;
     RECT  0.192 12.192 0.323 12.216 ;
     RECT  0.156 12.216 0.323 12.288 ;
     RECT  0.192 12.288 0.323 12.312 ;
     RECT  0.156 12.312 0.323 12.384 ;
     RECT  0.192 12.384 0.323 12.408 ;
     RECT  0.156 12.408 0.323 12.48 ;
     RECT  0.192 12.48 0.323 12.504 ;
     RECT  0.156 12.504 0.323 12.576 ;
     RECT  0.192 12.576 0.323 12.6 ;
     RECT  0.156 12.6 0.323 12.672 ;
     RECT  0.192 12.672 0.323 12.696 ;
     RECT  0.156 12.696 0.323 12.768 ;
     RECT  0.192 12.768 0.323 12.792 ;
     RECT  0.156 12.792 0.323 12.912 ;
     RECT  0.192 12.912 0.323 12.936 ;
     RECT  0.156 12.936 0.323 13.008 ;
     RECT  0.192 13.008 0.323 13.032 ;
     RECT  0.156 13.032 0.323 13.104 ;
     RECT  0.192 13.104 0.323 13.128 ;
     RECT  0.156 13.128 0.323 13.2 ;
     RECT  0.192 13.2 0.323 13.224 ;
     RECT  0.156 13.224 0.323 13.296 ;
     RECT  0.192 13.296 0.323 13.32 ;
     RECT  0.156 13.32 0.323 13.392 ;
     RECT  0.192 13.392 0.323 13.416 ;
     RECT  0.156 13.416 0.323 13.536 ;
     RECT  0.192 13.536 0.323 13.56 ;
     RECT  0.156 13.56 0.323 13.632 ;
     RECT  0.192 13.632 0.323 13.656 ;
     RECT  0.156 13.656 0.323 13.728 ;
     RECT  0.192 13.728 0.323 13.752 ;
     RECT  0.156 13.752 0.323 13.824 ;
     RECT  0.192 13.824 0.323 13.848 ;
     RECT  0.156 13.848 0.323 13.92 ;
     RECT  0.192 13.92 0.323 13.944 ;
     RECT  0.156 13.944 0.323 14.016 ;
     RECT  0.192 14.016 0.323 14.04 ;
     RECT  0.156 14.04 0.323 14.16 ;
     RECT  0.192 14.16 0.323 14.184 ;
     RECT  0.156 14.184 0.323 14.256 ;
     RECT  0.192 14.256 0.323 14.28 ;
     RECT  0.156 14.28 0.323 14.352 ;
     RECT  0.192 14.352 0.323 14.376 ;
     RECT  0.156 14.376 0.323 14.448 ;
     RECT  0.192 14.448 0.323 14.472 ;
     RECT  0.156 14.472 0.323 14.544 ;
     RECT  0.192 14.544 0.323 14.568 ;
     RECT  0.156 14.568 0.323 14.64 ;
     RECT  0.192 14.64 0.323 14.664 ;
     RECT  0.156 14.664 0.323 14.736 ;
     RECT  0.192 14.736 0.323 14.76 ;
     RECT  0.156 14.76 0.323 14.88 ;
     RECT  0.192 14.88 0.323 14.904 ;
     RECT  0.156 14.904 0.323 14.976 ;
     RECT  0.192 14.976 0.323 15 ;
     RECT  0.156 15 0.323 15.072 ;
     RECT  0.192 15.072 0.323 15.096 ;
     RECT  0.156 15.096 0.323 15.168 ;
     RECT  0.192 15.168 0.323 15.192 ;
     RECT  0.156 15.192 0.323 15.264 ;
     RECT  0.192 15.264 0.323 15.288 ;
     RECT  0.156 15.288 0.323 15.36 ;
     RECT  0.192 15.36 0.323 15.384 ;
     RECT  0.156 15.384 0.323 15.504 ;
     RECT  0.192 15.504 0.323 15.528 ;
     RECT  0.156 15.528 0.323 15.6 ;
     RECT  0.192 15.6 0.323 15.624 ;
     RECT  0.156 15.624 0.323 15.696 ;
     RECT  0.192 15.696 0.323 15.72 ;
     RECT  0.156 15.72 0.323 15.792 ;
     RECT  0.192 15.792 0.323 15.816 ;
     RECT  0.156 15.816 0.323 15.888 ;
     RECT  0.192 15.888 0.323 15.912 ;
     RECT  0.156 15.912 0.323 15.984 ;
     RECT  0.192 15.984 0.323 16.008 ;
     RECT  0.156 16.008 0.323 16.128 ;
     RECT  0.192 16.128 0.323 16.152 ;
     RECT  0.156 16.152 0.323 16.224 ;
     RECT  0.192 16.224 0.323 16.248 ;
     RECT  0.156 16.248 0.323 16.32 ;
     RECT  0.192 16.32 0.323 16.344 ;
     RECT  0.156 16.344 0.323 16.416 ;
     RECT  0.192 16.416 0.323 16.44 ;
     RECT  0.156 16.44 0.323 16.512 ;
     RECT  0.192 16.512 0.323 16.536 ;
     RECT  0.156 16.536 0.323 16.608 ;
     RECT  0.192 16.608 0.323 16.632 ;
     RECT  0.156 16.632 0.323 16.704 ;
     RECT  0.192 16.704 0.323 16.728 ;
     RECT  0.156 16.728 0.323 16.848 ;
     RECT  0.192 16.848 0.323 16.872 ;
     RECT  0.156 16.872 0.323 16.944 ;
     RECT  0.192 16.944 0.323 16.968 ;
     RECT  0.156 16.968 0.323 17.04 ;
     RECT  0.192 17.04 0.323 17.064 ;
     RECT  0.156 17.064 0.323 17.136 ;
     RECT  0.192 17.136 0.323 17.16 ;
     RECT  0.156 17.16 0.323 17.232 ;
     RECT  0.192 17.232 0.323 17.256 ;
     RECT  0.156 17.256 0.323 17.328 ;
     RECT  0.192 17.328 0.323 17.352 ;
     RECT  0.156 17.352 0.323 17.472 ;
     RECT  0.192 17.472 0.323 17.496 ;
     RECT  0.156 17.496 0.323 17.568 ;
     RECT  0.192 17.568 0.323 17.592 ;
     RECT  0.156 17.592 0.323 17.664 ;
     RECT  0.192 17.664 0.323 17.688 ;
     RECT  0.156 17.688 0.323 17.76 ;
     RECT  0.192 17.76 0.323 17.784 ;
     RECT  0.156 17.784 0.323 17.856 ;
     RECT  0.192 17.856 0.323 17.88 ;
     RECT  0.156 17.88 0.323 17.952 ;
     RECT  0.192 17.952 0.323 17.976 ;
     RECT  0.156 17.976 0.323 18.096 ;
     RECT  0.192 18.096 0.323 18.12 ;
     RECT  0.156 18.12 0.323 18.192 ;
     RECT  0.192 18.192 0.323 18.216 ;
     RECT  0.156 18.216 0.323 18.288 ;
     RECT  0.192 18.288 0.323 18.312 ;
     RECT  0.156 18.312 0.323 18.384 ;
     RECT  0.192 18.384 0.323 18.408 ;
     RECT  0.156 18.408 0.323 18.48 ;
     RECT  0.192 18.48 0.323 18.504 ;
     RECT  0.156 18.504 0.323 18.576 ;
     RECT  0.192 18.576 0.323 18.6 ;
     RECT  0.156 18.6 0.323 18.672 ;
     RECT  0.192 18.672 0.323 18.696 ;
     RECT  0.156 18.696 0.323 18.816 ;
     RECT  0.192 18.816 0.323 18.84 ;
     RECT  0.156 18.84 0.323 18.912 ;
     RECT  0.192 18.912 0.323 18.936 ;
     RECT  0.156 18.936 0.323 19.008 ;
     RECT  0.192 19.008 0.323 19.032 ;
     RECT  0.156 19.032 0.323 19.104 ;
     RECT  0.192 19.104 0.323 19.128 ;
     RECT  0.156 19.128 0.323 19.2 ;
     RECT  0.192 19.2 0.323 19.224 ;
     RECT  0.156 19.224 0.323 19.296 ;
     RECT  0.192 19.296 0.323 19.32 ;
     RECT  0.156 19.32 0.323 19.44 ;
     RECT  0.192 19.44 0.323 19.464 ;
     RECT  0.156 19.464 0.323 19.536 ;
     RECT  0.192 19.536 0.323 19.56 ;
     RECT  0.156 19.56 0.323 19.632 ;
     RECT  0.192 19.632 0.323 19.656 ;
     RECT  0.156 19.656 0.323 19.728 ;
     RECT  0.192 19.728 0.323 19.752 ;
     RECT  0.156 19.752 0.323 19.824 ;
     RECT  0.192 19.824 0.323 19.848 ;
     RECT  0.156 19.848 0.323 19.92 ;
     RECT  0.192 19.92 0.323 19.944 ;
     RECT  0.156 19.944 0.323 20.064 ;
     RECT  0.192 20.064 0.323 20.088 ;
     RECT  0.156 20.088 0.323 20.16 ;
     RECT  0.192 20.16 0.323 20.184 ;
     RECT  0.156 20.184 0.323 20.256 ;
     RECT  0.192 20.256 0.323 20.28 ;
     RECT  0.156 20.28 0.323 20.352 ;
     RECT  0.192 20.352 0.323 20.376 ;
     RECT  0.156 20.376 0.323 20.448 ;
     RECT  0.192 20.448 0.323 20.472 ;
     RECT  0.156 20.472 0.323 20.544 ;
     RECT  0.192 20.544 0.323 20.568 ;
     RECT  0.156 20.568 0.323 20.64 ;
     RECT  0.192 20.64 0.323 20.664 ;
     RECT  0.156 20.664 0.323 20.784 ;
     RECT  0.192 20.784 0.323 20.808 ;
     RECT  0.156 20.808 0.323 20.88 ;
     RECT  0.192 20.88 0.323 20.904 ;
     RECT  0.156 20.904 0.323 20.976 ;
     RECT  0.192 20.976 0.323 21 ;
     RECT  0.156 21 0.323 21.072 ;
     RECT  0.192 21.072 0.323 21.096 ;
     RECT  0.156 21.096 0.323 21.168 ;
     RECT  0.192 21.168 0.323 21.192 ;
     RECT  0.156 21.192 0.323 21.264 ;
     RECT  0.192 21.264 0.323 21.288 ;
     RECT  0.156 21.288 0.323 21.408 ;
     RECT  0.192 21.408 0.323 21.432 ;
     RECT  0.156 21.432 0.323 21.504 ;
     RECT  0.192 21.504 0.323 21.528 ;
     RECT  0.156 21.528 0.323 21.6 ;
     RECT  0.192 21.6 0.323 21.624 ;
     RECT  0.156 21.624 0.323 21.696 ;
     RECT  0.192 21.696 0.323 21.72 ;
     RECT  0.156 21.72 0.323 21.792 ;
     RECT  0.192 21.792 0.323 21.816 ;
     RECT  0.156 21.816 0.323 21.888 ;
     RECT  0.192 21.888 0.323 21.912 ;
     RECT  0.156 21.912 0.323 22.032 ;
     RECT  0.192 22.032 0.323 22.056 ;
     RECT  0.156 22.056 0.323 22.128 ;
     RECT  0.192 22.128 0.323 22.152 ;
     RECT  0.156 22.152 0.323 22.224 ;
     RECT  0.192 22.224 0.323 22.248 ;
     RECT  0.156 22.248 0.323 22.32 ;
     RECT  0.192 22.32 0.323 22.344 ;
     RECT  0.156 22.344 0.323 22.416 ;
     RECT  0.192 22.416 0.323 22.44 ;
     RECT  0.156 22.44 0.323 22.512 ;
     RECT  0.192 22.512 0.323 22.536 ;
     RECT  0.156 22.536 0.323 22.608 ;
     RECT  0.192 22.608 0.323 22.632 ;
     RECT  0.156 22.632 0.323 22.752 ;
     RECT  0.192 22.752 0.323 22.776 ;
     RECT  0.156 22.776 0.323 22.848 ;
     RECT  0.192 22.848 0.323 22.872 ;
     RECT  0.156 22.872 0.323 22.944 ;
     RECT  0.192 22.944 0.323 22.968 ;
     RECT  0.156 22.968 0.323 23.04 ;
     RECT  0.192 23.04 0.323 23.064 ;
     RECT  0.156 23.064 0.323 23.136 ;
     RECT  0.192 23.136 0.323 23.16 ;
     RECT  0.156 23.16 0.323 23.232 ;
     RECT  0.192 23.232 0.323 23.256 ;
     RECT  0.156 23.256 0.323 23.376 ;
     RECT  0.192 23.376 0.323 23.4 ;
     RECT  0.156 23.4 0.323 23.472 ;
     RECT  0.192 23.472 0.323 23.496 ;
     RECT  0.156 23.496 0.323 23.568 ;
     RECT  0.192 23.568 0.323 23.592 ;
     RECT  0.156 23.592 0.323 23.664 ;
     RECT  0.192 23.664 0.323 23.688 ;
     RECT  0.156 23.688 0.323 23.76 ;
     RECT  0.192 23.76 0.323 23.784 ;
     RECT  0.156 23.784 0.323 23.856 ;
     RECT  0.192 23.856 0.323 23.88 ;
     RECT  0.156 23.88 0.323 24 ;
     RECT  0.192 24 0.323 24.024 ;
     RECT  0.156 24.024 0.323 24.096 ;
     RECT  0.192 24.096 0.323 24.12 ;
     RECT  0.156 24.12 0.323 24.192 ;
     RECT  0.192 24.192 0.323 24.216 ;
     RECT  0.156 24.216 0.323 24.288 ;
     RECT  0.192 24.288 0.323 24.312 ;
     RECT  0.156 24.312 0.323 24.384 ;
     RECT  0.192 24.384 0.323 24.408 ;
     RECT  0.156 24.408 0.323 24.48 ;
     RECT  0.192 24.48 0.323 24.504 ;
     RECT  0.156 24.504 0.323 24.576 ;
     RECT  0.192 24.576 0.323 24.6 ;
     RECT  0.156 24.6 0.323 24.72 ;
     RECT  0.192 24.72 0.323 24.744 ;
     RECT  0.156 24.744 0.323 24.816 ;
     RECT  0.192 24.816 0.323 24.84 ;
     RECT  0.156 24.84 0.323 24.912 ;
     RECT  0.192 24.912 0.323 24.936 ;
     RECT  0.156 24.936 0.323 25.008 ;
     RECT  0.192 25.008 0.323 25.032 ;
     RECT  0.156 25.032 0.323 25.104 ;
     RECT  0.192 25.104 0.323 25.128 ;
     RECT  0.156 25.128 0.323 25.2 ;
     RECT  0.192 25.2 0.323 25.224 ;
     RECT  0.156 25.224 0.323 25.344 ;
     RECT  0.192 25.344 0.323 25.368 ;
     RECT  0.156 25.368 0.323 25.44 ;
     RECT  0.192 25.44 0.323 25.464 ;
     RECT  0.156 25.464 0.323 25.536 ;
     RECT  0.192 25.536 0.323 25.56 ;
     RECT  0.156 25.56 0.323 25.632 ;
     RECT  0.192 25.632 0.323 25.656 ;
     RECT  0.156 25.656 0.323 25.728 ;
     RECT  0.192 25.728 0.323 25.752 ;
     RECT  0.156 25.752 0.323 25.824 ;
     RECT  0.192 25.824 0.323 25.848 ;
     RECT  0.156 25.848 0.323 25.968 ;
     RECT  0.192 25.968 0.323 25.992 ;
     RECT  0.156 25.992 0.323 26.064 ;
     RECT  0.192 26.064 0.323 26.088 ;
     RECT  0.156 26.088 0.323 26.16 ;
     RECT  0.192 26.16 0.323 26.184 ;
     RECT  0.156 26.184 0.323 26.256 ;
     RECT  0.192 26.256 0.323 26.28 ;
     RECT  0.156 26.28 0.323 26.352 ;
     RECT  0.192 26.352 0.323 26.376 ;
     RECT  0.156 26.376 0.323 26.448 ;
     RECT  0.192 26.448 0.323 26.472 ;
     RECT  0.156 26.472 0.323 26.544 ;
     RECT  0.192 26.544 0.323 26.568 ;
     RECT  0.156 26.568 0.323 26.688 ;
     RECT  0.192 26.688 0.323 26.712 ;
     RECT  0.156 26.712 0.323 26.784 ;
     RECT  0.192 26.784 0.323 26.808 ;
     RECT  0.156 26.808 0.323 26.88 ;
     RECT  0.192 26.88 0.323 26.904 ;
     RECT  0.156 26.904 0.323 26.976 ;
     RECT  0.192 26.976 0.323 27 ;
     RECT  0.156 27 0.323 27.072 ;
     RECT  0.192 27.072 0.323 27.096 ;
     RECT  0.156 27.096 0.323 27.168 ;
     RECT  0.192 27.168 0.323 27.192 ;
     RECT  0.156 27.192 0.323 27.312 ;
     RECT  0.192 27.312 0.323 27.336 ;
     RECT  0.156 27.336 0.323 27.408 ;
     RECT  0.192 27.408 0.323 27.432 ;
     RECT  0.156 27.432 0.323 27.504 ;
     RECT  0.192 27.504 0.323 27.528 ;
     RECT  0.156 27.528 0.323 27.6 ;
     RECT  0.192 27.6 0.323 27.624 ;
     RECT  0.156 27.624 0.323 27.696 ;
     RECT  0.192 27.696 0.323 27.72 ;
     RECT  0.156 27.72 0.323 27.792 ;
     RECT  0.192 27.792 0.323 27.816 ;
     RECT  0.156 27.816 0.323 27.936 ;
     RECT  0.192 27.936 0.323 27.96 ;
     RECT  0.156 27.96 0.323 28.032 ;
     RECT  0.192 28.032 0.323 28.056 ;
     RECT  0.156 28.056 0.323 28.128 ;
     RECT  0.192 28.128 0.323 28.152 ;
     RECT  0.156 28.152 0.323 28.224 ;
     RECT  0.192 28.224 0.323 28.248 ;
     RECT  0.156 28.248 0.323 28.32 ;
     RECT  0.192 28.32 0.323 28.344 ;
     RECT  0.156 28.344 0.323 28.416 ;
     RECT  0.192 28.416 0.323 28.44 ;
     RECT  0.156 28.44 0.323 28.512 ;
     RECT  0.192 28.512 0.323 28.536 ;
     RECT  0.156 28.536 0.323 28.656 ;
     RECT  0.192 28.656 0.323 28.68 ;
     RECT  0.156 28.68 0.323 28.752 ;
     RECT  0.192 28.752 0.323 28.776 ;
     RECT  0.156 28.776 0.323 28.848 ;
     RECT  0.192 28.848 0.323 28.872 ;
     RECT  0.156 28.872 0.323 28.944 ;
     RECT  0.192 28.944 0.323 28.968 ;
     RECT  0.156 28.968 0.323 29.04 ;
     RECT  0.192 29.04 0.323 29.064 ;
     RECT  0.156 29.064 0.323 29.136 ;
     RECT  0.192 29.136 0.323 29.16 ;
     RECT  0.156 29.16 0.323 29.28 ;
     RECT  0.192 29.28 0.323 29.304 ;
     RECT  0.156 29.304 0.323 29.376 ;
     RECT  0.192 29.376 0.323 29.4 ;
     RECT  0.156 29.4 0.323 29.472 ;
     RECT  0.192 29.472 0.323 29.496 ;
     RECT  0.156 29.496 0.323 29.568 ;
     RECT  0.192 29.568 0.323 29.592 ;
     RECT  0.156 29.592 0.323 29.664 ;
     RECT  0.192 29.664 0.323 29.688 ;
     RECT  0.156 29.688 0.323 29.76 ;
     RECT  0.192 29.76 0.323 29.784 ;
     RECT  0.156 29.784 0.323 29.904 ;
     RECT  0.192 29.904 0.323 29.928 ;
     RECT  0.156 29.928 0.323 30 ;
     RECT  0.192 30 0.323 30.024 ;
     RECT  0.156 30.024 0.323 30.096 ;
     RECT  0.192 30.096 0.323 30.12 ;
     RECT  0.156 30.12 0.323 30.192 ;
     RECT  0.192 30.192 0.323 30.216 ;
     RECT  0.156 30.216 0.323 30.288 ;
     RECT  0.192 30.288 0.323 30.312 ;
     RECT  0.156 30.312 0.323 30.384 ;
     RECT  0.192 30.384 0.323 30.408 ;
     RECT  0.156 30.408 0.323 30.48 ;
     RECT  0.192 30.48 0.323 30.504 ;
     RECT  0.156 30.504 0.323 30.624 ;
     RECT  0.192 30.624 0.323 30.648 ;
     RECT  0.156 30.648 0.323 30.72 ;
     RECT  0.192 30.72 0.323 30.744 ;
     RECT  0.156 30.744 0.323 30.816 ;
     RECT  0.192 30.816 0.323 30.84 ;
     RECT  0.156 30.84 0.323 30.912 ;
     RECT  0.192 30.912 0.323 30.936 ;
     RECT  0.156 30.936 0.323 31.008 ;
     RECT  0.192 31.008 0.323 31.032 ;
     RECT  0.156 31.032 0.323 31.104 ;
     RECT  0.192 31.104 0.323 31.128 ;
     RECT  0.156 31.128 0.323 31.248 ;
     RECT  0.192 31.248 0.323 31.272 ;
     RECT  0.156 31.272 0.323 31.344 ;
     RECT  0.192 31.344 0.323 31.368 ;
     RECT  0.156 31.368 0.323 31.44 ;
     RECT  0.192 31.44 0.323 31.464 ;
     RECT  0.156 31.464 0.323 31.536 ;
     RECT  0.192 31.536 0.323 31.56 ;
     RECT  0.156 31.56 0.323 31.632 ;
     RECT  0.192 31.632 0.323 31.656 ;
     RECT  0.156 31.656 0.323 31.728 ;
     RECT  0.192 31.728 0.323 31.752 ;
     RECT  0.156 31.752 0.323 31.872 ;
     RECT  0.192 31.872 0.323 31.896 ;
     RECT  0.156 31.896 0.323 31.968 ;
     RECT  0.192 31.968 0.323 31.992 ;
     RECT  0.156 31.992 0.323 32.064 ;
     RECT  0.192 32.064 0.323 32.088 ;
     RECT  0.156 32.088 0.323 32.16 ;
     RECT  0.192 32.16 0.323 32.184 ;
     RECT  0.156 32.184 0.323 32.256 ;
     RECT  0.192 32.256 0.323 32.28 ;
     RECT  0.156 32.28 0.323 32.352 ;
     RECT  0.192 32.352 0.323 32.376 ;
     RECT  0.156 32.376 0.323 32.448 ;
     RECT  0.192 32.448 0.323 32.472 ;
     RECT  0.156 32.472 0.323 32.592 ;
     RECT  0.192 32.592 0.323 32.616 ;
     RECT  0.156 32.616 0.323 32.688 ;
     RECT  0.192 32.688 0.323 32.712 ;
     RECT  0.156 32.712 0.323 32.784 ;
     RECT  0.192 32.784 0.323 32.808 ;
     RECT  0.156 32.808 0.323 32.88 ;
     RECT  0.192 32.88 0.323 32.904 ;
     RECT  0.156 32.904 0.323 32.976 ;
     RECT  0.192 32.976 0.323 33 ;
     RECT  0.156 33 0.323 33.072 ;
     RECT  0.192 33.072 0.323 33.096 ;
     RECT  0.156 33.096 0.323 33.216 ;
     RECT  0.192 33.216 0.323 33.24 ;
     RECT  0.156 33.24 0.323 33.312 ;
     RECT  0.192 33.312 0.323 33.336 ;
     RECT  0.156 33.336 0.323 33.408 ;
     RECT  0.192 33.408 0.323 33.432 ;
     RECT  0.156 33.432 0.323 33.504 ;
     RECT  0.192 33.504 0.323 33.528 ;
     RECT  0.156 33.528 0.323 33.6 ;
     RECT  0.192 33.6 0.323 33.624 ;
     RECT  0.156 33.624 0.323 33.696 ;
     RECT  0.192 33.696 0.323 33.72 ;
     RECT  0.156 33.72 0.323 33.84 ;
     RECT  0.192 33.84 0.323 33.864 ;
     RECT  0.156 33.864 0.323 33.936 ;
     RECT  0.192 33.936 0.323 33.96 ;
     RECT  0.156 33.96 0.323 34.032 ;
     RECT  0.192 34.032 0.323 34.056 ;
     RECT  0.156 34.056 0.323 34.128 ;
     RECT  0.192 34.128 0.323 34.152 ;
     RECT  0.156 34.152 0.323 34.224 ;
     RECT  0.192 34.224 0.323 34.248 ;
     RECT  0.156 34.248 0.323 34.32 ;
     RECT  0.192 34.32 0.323 34.344 ;
     RECT  0.156 34.344 0.323 34.416 ;
     RECT  0.192 34.416 0.323 34.44 ;
     RECT  0.156 34.44 0.323 34.56 ;
     RECT  0.192 34.56 0.323 34.584 ;
     RECT  0.156 34.584 0.323 34.656 ;
     RECT  0.192 34.656 0.323 34.68 ;
     RECT  0.156 34.68 0.323 34.752 ;
     RECT  0.192 34.752 0.323 34.776 ;
     RECT  0.156 34.776 0.323 34.848 ;
     RECT  0.192 34.848 0.323 34.872 ;
     RECT  0.156 34.872 0.323 34.944 ;
     RECT  0.192 34.944 0.323 34.968 ;
     RECT  0.156 34.968 0.323 35.04 ;
     RECT  0.192 35.04 0.323 35.064 ;
     RECT  0.156 35.064 0.323 35.184 ;
     RECT  0.192 35.184 0.323 35.208 ;
     RECT  0.156 35.208 0.323 35.28 ;
     RECT  0.192 35.28 0.323 35.304 ;
     RECT  0.156 35.304 0.323 35.376 ;
     RECT  0.192 35.376 0.323 35.4 ;
     RECT  0.156 35.4 0.323 35.472 ;
     RECT  0.192 35.472 0.323 35.496 ;
     RECT  0.156 35.496 0.323 35.568 ;
     RECT  0.192 35.568 0.323 35.592 ;
     RECT  0.156 35.592 0.323 35.664 ;
     RECT  0.192 35.664 0.323 35.688 ;
     RECT  0.156 35.688 0.323 35.808 ;
     RECT  0.192 35.808 0.323 35.832 ;
     RECT  0.156 35.832 0.323 35.904 ;
     RECT  0.192 35.904 0.323 35.928 ;
     RECT  0.156 35.928 0.323 36 ;
     RECT  0.192 36 0.323 36.024 ;
     RECT  0.156 36.024 0.323 36.096 ;
     RECT  0.192 36.096 0.323 36.12 ;
     RECT  0.156 36.12 0.323 36.192 ;
     RECT  0.192 36.192 0.323 36.216 ;
     RECT  0.156 36.216 0.323 36.288 ;
     RECT  0.192 36.288 0.323 36.312 ;
     RECT  0.156 36.312 0.323 36.384 ;
     RECT  0.192 36.384 0.323 36.408 ;
     RECT  0.156 36.408 0.323 36.528 ;
     RECT  0.192 36.528 0.323 36.552 ;
     RECT  0.156 36.552 0.323 36.624 ;
     RECT  0.192 36.624 0.323 36.648 ;
     RECT  0.156 36.648 0.323 36.72 ;
     RECT  0.192 36.72 0.323 36.744 ;
     RECT  0.156 36.744 0.323 36.816 ;
     RECT  0.192 36.816 0.323 36.84 ;
     RECT  0.156 36.84 0.323 36.912 ;
     RECT  0.192 36.912 0.323 36.936 ;
     RECT  0.156 36.936 0.323 37.008 ;
     RECT  0.192 37.008 0.323 37.032 ;
     RECT  0.156 37.032 0.323 37.152 ;
     RECT  0.192 37.152 0.323 37.176 ;
     RECT  0.156 37.176 0.323 37.248 ;
     RECT  0.192 37.248 0.323 37.272 ;
     RECT  0.156 37.272 0.323 37.344 ;
     RECT  0.192 37.344 0.323 37.368 ;
     RECT  0.156 37.368 0.323 37.44 ;
     RECT  0.192 37.44 0.323 37.464 ;
     RECT  0.156 37.464 0.323 37.536 ;
     RECT  0.192 37.536 0.323 37.56 ;
     RECT  0.156 37.56 0.323 37.632 ;
     RECT  0.192 37.632 0.323 37.656 ;
     RECT  0.156 37.656 0.323 37.776 ;
     RECT  0.192 37.776 0.323 37.8 ;
     RECT  0.156 37.8 0.323 37.872 ;
     RECT  0.192 37.872 0.323 37.896 ;
     RECT  0.156 37.896 0.323 37.968 ;
     RECT  0.192 37.968 0.323 37.992 ;
     RECT  0.156 37.992 0.323 38.064 ;
     RECT  0.192 38.064 0.323 38.088 ;
     RECT  0.156 38.088 0.323 38.16 ;
     RECT  0.192 38.16 0.323 38.184 ;
     RECT  0.156 38.184 0.323 38.256 ;
     RECT  0.192 38.256 0.323 38.28 ;
     RECT  0.156 38.28 0.323 38.352 ;
     RECT  0.192 38.352 0.323 38.376 ;
     RECT  0.156 38.376 0.323 38.496 ;
     RECT  0.192 38.496 0.323 38.52 ;
     RECT  0.156 38.52 0.323 38.592 ;
     RECT  0.192 38.592 0.323 38.616 ;
     RECT  0.156 38.616 0.323 38.688 ;
     RECT  0.192 38.688 0.323 38.712 ;
     RECT  0.156 38.712 0.323 38.784 ;
     RECT  0.192 38.784 0.323 38.808 ;
     RECT  0.156 38.808 0.323 38.88 ;
     RECT  0.192 38.88 0.323 38.904 ;
     RECT  0.156 38.904 0.323 38.976 ;
     RECT  0.192 38.976 0.323 39 ;
     RECT  0.156 39 0.323 39.12 ;
     RECT  0.192 39.12 0.323 39.144 ;
     RECT  0.156 39.144 0.323 39.216 ;
     RECT  0.192 39.216 0.323 39.24 ;
     RECT  0.156 39.24 0.323 39.312 ;
     RECT  0.192 39.312 0.323 39.336 ;
     RECT  0.156 39.336 0.323 39.408 ;
     RECT  0.192 39.408 0.323 39.432 ;
     RECT  0.156 39.432 0.323 39.504 ;
     RECT  0.192 39.504 0.323 39.528 ;
     RECT  0.156 39.528 0.323 39.6 ;
     RECT  0.192 39.6 0.323 39.624 ;
     RECT  0.156 39.624 0.323 39.744 ;
     RECT  0.192 39.744 0.323 39.768 ;
     RECT  0.156 39.768 0.323 39.84 ;
     RECT  0.192 39.84 0.323 39.864 ;
     RECT  0.156 39.864 0.323 39.936 ;
     RECT  0.192 39.936 0.323 39.96 ;
     RECT  0.156 39.96 0.323 40.032 ;
     RECT  0.192 40.032 0.323 40.056 ;
     RECT  0.156 40.056 0.323 40.128 ;
     RECT  0.192 40.128 0.323 40.152 ;
     RECT  0.156 40.152 0.323 40.224 ;
     RECT  0.192 40.224 0.323 40.248 ;
     RECT  0.156 40.248 0.323 40.368 ;
     RECT  0.192 40.368 0.323 40.392 ;
     RECT  0.156 40.392 0.323 40.464 ;
     RECT  0.192 40.464 0.323 40.488 ;
     RECT  0.156 40.488 0.323 40.56 ;
     RECT  0.192 40.56 0.323 40.584 ;
     RECT  0.156 40.584 0.323 40.656 ;
     RECT  0.192 40.656 0.323 40.68 ;
     RECT  0.156 40.68 0.323 40.752 ;
     RECT  0.192 40.752 0.323 40.776 ;
     RECT  0.156 40.776 0.323 40.848 ;
     RECT  0.192 40.848 0.323 40.872 ;
     RECT  0.156 40.872 0.323 40.944 ;
     RECT  0.192 40.944 0.323 40.968 ;
     RECT  0.156 40.968 0.323 41.088 ;
     RECT  0.192 41.088 0.323 41.112 ;
     RECT  0.156 41.112 0.323 41.184 ;
     RECT  0.192 41.184 0.323 41.208 ;
     RECT  0.156 41.208 0.323 41.28 ;
     RECT  0.192 41.28 0.323 41.304 ;
     RECT  0.156 41.304 0.323 41.376 ;
     RECT  0.192 41.376 0.323 41.4 ;
     RECT  0.156 41.4 0.323 41.472 ;
     RECT  0.192 41.472 0.323 41.496 ;
     RECT  0.156 41.496 0.323 41.568 ;
     RECT  0.192 41.568 0.323 41.592 ;
     RECT  0.156 41.592 0.323 41.712 ;
     RECT  0.192 41.712 0.323 41.736 ;
     RECT  0.156 41.736 0.323 41.808 ;
     RECT  0.192 41.808 0.323 41.832 ;
     RECT  0.156 41.832 0.323 41.904 ;
     RECT  0.192 41.904 0.323 41.928 ;
     RECT  0.156 41.928 0.323 42 ;
     RECT  0.192 42 0.323 42.024 ;
     RECT  0.156 42.024 0.323 42.096 ;
     RECT  0.192 42.096 0.323 42.12 ;
     RECT  0.156 42.12 0.323 42.192 ;
     RECT  0.192 42.192 0.323 42.216 ;
     RECT  0.156 42.216 0.323 42.336 ;
     RECT  0.192 42.336 0.323 42.36 ;
     RECT  0.156 42.36 0.323 42.432 ;
     RECT  0.192 42.432 0.323 42.456 ;
     RECT  0.156 42.456 0.323 42.528 ;
     RECT  0.192 42.528 0.323 42.552 ;
     RECT  0.156 42.552 0.323 42.624 ;
     RECT  0.192 42.624 0.323 42.648 ;
     RECT  0.156 42.648 0.323 42.72 ;
     RECT  0.192 42.72 0.323 42.744 ;
     RECT  0.156 42.744 0.323 42.816 ;
     RECT  0.192 42.816 0.323 42.84 ;
     RECT  0.156 42.84 0.323 42.912 ;
     RECT  0.192 42.912 0.323 42.936 ;
     RECT  0.156 42.936 0.323 43.056 ;
     RECT  0.192 43.056 0.323 43.08 ;
     RECT  0.156 43.08 0.323 43.152 ;
     RECT  0.192 43.152 0.323 43.176 ;
     RECT  0.156 43.176 0.323 43.248 ;
     RECT  0.192 43.248 0.323 43.272 ;
     RECT  0.156 43.272 0.323 43.344 ;
     RECT  0.192 43.344 0.323 43.368 ;
     RECT  0.156 43.368 0.323 43.44 ;
     RECT  0.192 43.44 0.323 43.464 ;
     RECT  0.156 43.464 0.323 43.536 ;
     RECT  0.192 43.536 0.323 43.56 ;
     RECT  0.156 43.56 0.323 43.68 ;
     RECT  0.192 43.68 0.323 43.704 ;
     RECT  0.156 43.704 0.323 43.776 ;
     RECT  0.192 43.776 0.323 43.8 ;
     RECT  0.156 43.8 0.323 43.872 ;
     RECT  0.192 43.872 0.323 43.896 ;
     RECT  0.156 43.896 0.323 43.968 ;
     RECT  0.192 43.968 0.323 43.992 ;
     RECT  0.156 43.992 0.323 44.064 ;
     RECT  0.192 44.064 0.323 44.088 ;
     RECT  0.156 44.088 0.323 44.16 ;
     RECT  0.192 44.16 0.323 44.184 ;
     RECT  0.156 44.184 0.323 44.304 ;
     RECT  0.192 44.304 0.323 44.328 ;
     RECT  0.156 44.328 0.323 44.4 ;
     RECT  0.192 44.4 0.323 44.424 ;
     RECT  0.156 44.424 0.323 44.496 ;
     RECT  0.192 44.496 0.323 44.52 ;
     RECT  0.156 44.52 0.323 44.592 ;
     RECT  0.192 44.592 0.323 44.616 ;
     RECT  0.156 44.616 0.323 44.688 ;
     RECT  0.192 44.688 0.323 44.712 ;
     RECT  0.156 44.712 0.323 44.784 ;
     RECT  0.192 44.784 0.323 44.808 ;
     RECT  0.156 44.808 0.323 44.88 ;
     RECT  0.192 44.88 0.323 44.904 ;
     RECT  0.156 44.904 0.323 45.024 ;
     RECT  0.192 45.024 0.323 45.048 ;
     RECT  0.156 45.048 0.323 45.12 ;
     RECT  0.192 45.12 0.323 45.144 ;
     RECT  0.156 45.144 0.323 45.216 ;
     RECT  0.192 45.216 0.323 45.24 ;
     RECT  0.156 45.24 0.323 45.312 ;
     RECT  0.192 45.312 0.323 45.336 ;
     RECT  0.156 45.336 0.323 45.408 ;
     RECT  0.192 45.408 0.323 45.432 ;
     RECT  0.156 45.432 0.323 45.504 ;
     RECT  0.192 45.504 0.323 45.528 ;
     RECT  0.156 45.528 0.323 45.648 ;
     RECT  0.192 45.648 0.323 45.672 ;
     RECT  0.156 45.672 0.323 45.744 ;
     RECT  0.192 45.744 0.323 45.768 ;
     RECT  0.156 45.768 0.323 45.84 ;
     RECT  0.192 45.84 0.323 45.864 ;
     RECT  0.156 45.864 0.323 45.936 ;
     RECT  0.192 45.936 0.323 45.96 ;
     RECT  0.156 45.96 0.323 46.032 ;
     RECT  0.192 46.032 0.323 46.056 ;
     RECT  0.156 46.056 0.323 46.128 ;
     RECT  0.192 46.128 0.323 46.152 ;
     RECT  0.156 46.152 0.323 46.272 ;
     RECT  0.192 46.272 0.323 46.296 ;
     RECT  0.156 46.296 0.323 46.368 ;
     RECT  0.192 46.368 0.323 46.392 ;
     RECT  0.156 46.392 0.323 46.464 ;
     RECT  0.192 46.464 0.323 46.488 ;
     RECT  0.156 46.488 0.323 46.56 ;
     RECT  0.192 46.56 0.323 46.584 ;
     RECT  0.156 46.584 0.323 46.656 ;
     RECT  0.192 46.656 0.323 46.68 ;
     RECT  0.156 46.68 0.323 46.752 ;
     RECT  0.192 46.752 0.323 46.776 ;
     RECT  0.156 46.776 0.323 46.848 ;
     RECT  0.192 46.848 0.323 46.872 ;
     RECT  0.156 46.872 0.323 46.992 ;
     RECT  0.192 46.992 0.323 47.016 ;
     RECT  0.156 47.016 0.323 47.088 ;
     RECT  0.192 47.088 0.323 47.112 ;
     RECT  0.156 47.112 0.323 47.184 ;
     RECT  0.192 47.184 0.323 47.208 ;
     RECT  0.156 47.208 0.323 47.28 ;
     RECT  0.192 47.28 0.323 47.304 ;
     RECT  0.156 47.304 0.323 47.376 ;
     RECT  0.192 47.376 0.323 47.4 ;
     RECT  0.156 47.4 0.323 47.472 ;
     RECT  0.192 47.472 0.323 47.496 ;
     RECT  0.156 47.496 0.323 47.616 ;
     RECT  0.192 47.616 0.323 47.64 ;
     RECT  0.156 47.64 0.323 47.712 ;
     RECT  0.192 47.712 0.323 47.736 ;
     RECT  0.156 47.736 0.323 47.808 ;
     RECT  0.192 47.808 0.323 47.832 ;
     RECT  0.156 47.832 0.323 47.904 ;
     RECT  0.192 47.904 0.323 47.928 ;
     RECT  0.156 47.928 0.323 48 ;
     RECT  0.192 48 0.323 48.024 ;
     RECT  0.156 48.024 0.323 48.096 ;
     RECT  0.192 48.096 0.323 48.12 ;
     RECT  0.156 48.12 0.323 48.24 ;
     RECT  0.192 48.24 0.323 48.264 ;
     RECT  0.156 48.264 0.323 48.336 ;
     RECT  0.192 48.336 0.323 48.36 ;
     RECT  0.156 48.36 0.323 48.432 ;
     RECT  0.192 48.432 0.323 48.456 ;
     RECT  0.156 48.456 0.323 48.528 ;
     RECT  0.192 48.528 0.323 48.552 ;
     RECT  0.156 48.552 0.323 48.624 ;
     RECT  0.192 48.624 0.323 48.648 ;
     RECT  0.156 48.648 0.323 48.72 ;
     RECT  0.192 48.72 0.323 48.744 ;
     RECT  0.156 48.744 0.323 48.816 ;
     RECT  0.192 48.816 0.323 48.84 ;
     RECT  0.156 48.84 0.323 48.96 ;
     RECT  0.192 48.96 0.323 48.984 ;
     RECT  0.156 48.984 0.323 49.056 ;
     RECT  0.192 49.056 0.323 49.08 ;
     RECT  0.156 49.08 0.323 49.152 ;
     RECT  0.192 49.152 0.323 49.176 ;
     RECT  0.156 49.176 0.323 49.248 ;
     RECT  0.192 49.248 0.323 49.272 ;
     RECT  0.156 49.272 0.323 49.344 ;
     RECT  0.192 49.344 0.323 49.368 ;
     RECT  0.156 49.368 0.323 49.44 ;
     RECT  0.192 49.44 0.323 49.464 ;
     RECT  0.156 49.464 0.323 49.584 ;
     RECT  0.192 49.584 0.323 49.608 ;
     RECT  0.156 49.608 0.323 49.68 ;
     RECT  0.192 49.68 0.323 49.704 ;
     RECT  0.156 49.704 0.323 49.776 ;
     RECT  0.192 49.776 0.323 49.8 ;
     RECT  0.156 49.8 0.323 49.872 ;
     RECT  0.192 49.872 0.323 49.896 ;
     RECT  0.156 49.896 0.323 49.968 ;
     RECT  0.192 49.968 0.323 49.992 ;
     RECT  0.156 49.992 0.323 50.064 ;
     RECT  0.192 50.064 0.323 50.088 ;
     RECT  0.156 50.088 0.323 50.208 ;
     RECT  0.192 50.208 0.323 50.232 ;
     RECT  0.156 50.232 0.323 50.304 ;
     RECT  0.192 50.304 0.323 50.328 ;
     RECT  0.156 50.328 0.323 50.4 ;
     RECT  0.192 50.4 0.323 50.424 ;
     RECT  0.156 50.424 0.323 50.496 ;
     RECT  0.192 50.496 0.323 50.52 ;
     RECT  0.156 50.52 0.323 50.592 ;
     RECT  0.192 50.592 0.323 50.616 ;
     RECT  0.156 50.616 0.323 50.688 ;
     RECT  0.192 50.688 0.323 50.712 ;
     RECT  0.156 50.712 0.323 50.784 ;
     RECT  0.192 50.784 0.323 50.808 ;
     RECT  0.156 50.808 0.323 50.928 ;
     RECT  0.192 50.928 0.323 50.952 ;
     RECT  0.156 50.952 0.323 51.024 ;
     RECT  0.192 51.024 0.323 51.048 ;
     RECT  0.156 51.048 0.323 51.12 ;
     RECT  0.192 51.12 0.323 51.144 ;
     RECT  0.156 51.144 0.323 51.216 ;
     RECT  0.192 51.216 0.323 51.24 ;
     RECT  0.156 51.24 0.323 51.312 ;
     RECT  0.192 51.312 0.323 51.336 ;
     RECT  0.156 51.336 0.323 51.408 ;
     RECT  0.192 51.408 0.323 51.432 ;
     RECT  0.156 51.432 0.323 51.552 ;
     RECT  0.192 51.552 0.323 51.576 ;
     RECT  0.156 51.576 0.323 51.648 ;
     RECT  0.192 51.648 0.323 51.672 ;
     RECT  0.156 51.672 0.323 51.744 ;
     RECT  0.192 51.744 0.323 51.768 ;
     RECT  0.156 51.768 0.323 51.84 ;
     RECT  0.192 51.84 0.323 51.864 ;
     RECT  0.156 51.864 0.323 51.936 ;
     RECT  0.192 51.936 0.323 51.96 ;
     RECT  0.156 51.96 0.323 52.032 ;
     RECT  0.192 52.032 0.323 52.056 ;
     RECT  0.156 52.056 0.323 52.176 ;
     RECT  0.192 52.176 0.323 52.2 ;
     RECT  0.156 52.2 0.323 52.272 ;
     RECT  0.192 52.272 0.323 52.296 ;
     RECT  0.156 52.296 0.323 52.368 ;
     RECT  0.192 52.368 0.323 52.392 ;
     RECT  0.156 52.392 0.323 52.464 ;
     RECT  0.192 52.464 0.323 52.488 ;
     RECT  0.156 52.488 0.323 52.56 ;
     RECT  0.192 52.56 0.323 52.584 ;
     RECT  0.156 52.584 0.323 52.656 ;
     RECT  0.192 52.656 0.323 52.68 ;
     RECT  0.156 52.68 0.323 52.752 ;
     RECT  0.192 52.752 0.323 52.776 ;
     RECT  0.156 52.776 0.323 52.896 ;
     RECT  0.192 52.896 0.323 52.92 ;
     RECT  0.156 52.92 0.323 52.992 ;
     RECT  0.192 52.992 0.323 53.016 ;
     RECT  0.156 53.016 0.323 53.088 ;
     RECT  0.192 53.088 0.323 53.112 ;
     RECT  0.156 53.112 0.323 53.184 ;
     RECT  0.192 53.184 0.323 53.208 ;
     RECT  0.156 53.208 0.323 53.28 ;
     RECT  0.192 53.28 0.323 53.304 ;
     RECT  0.156 53.304 0.323 53.376 ;
     RECT  0.192 53.376 0.323 53.4 ;
     RECT  0.156 53.4 0.323 53.52 ;
     RECT  0.192 53.52 0.323 53.544 ;
     RECT  0.156 53.544 0.323 53.616 ;
     RECT  0.192 53.616 0.323 53.64 ;
     RECT  0.156 53.64 0.323 53.712 ;
     RECT  0.192 53.712 0.323 53.736 ;
     RECT  0.156 53.736 0.323 53.808 ;
     RECT  0.192 53.808 0.323 53.832 ;
     RECT  0.156 53.832 0.323 53.904 ;
     RECT  0.192 53.904 0.323 53.928 ;
     RECT  0.156 53.928 0.323 54 ;
     RECT  0.192 54 0.323 54.024 ;
     RECT  0.156 54.024 0.323 54.144 ;
     RECT  0.192 54.144 0.323 54.168 ;
     RECT  0.156 54.168 0.323 54.24 ;
     RECT  0.192 54.24 0.323 54.264 ;
     RECT  0.156 54.264 0.323 54.336 ;
     RECT  0.192 54.336 0.323 54.36 ;
     RECT  0.156 54.36 0.323 54.432 ;
     RECT  0.192 54.432 0.323 54.456 ;
     RECT  0.156 54.456 0.323 54.528 ;
     RECT  0.192 54.528 0.323 54.552 ;
     RECT  0.156 54.552 0.323 54.624 ;
     RECT  0.192 54.624 0.323 54.648 ;
     RECT  0.156 54.648 0.323 54.72 ;
     RECT  0.192 54.72 0.323 54.744 ;
     RECT  0.156 54.744 0.323 54.864 ;
     RECT  0.192 54.864 0.323 54.888 ;
     RECT  0.156 54.888 0.323 54.96 ;
     RECT  0.192 54.96 0.323 54.984 ;
     RECT  0.156 54.984 0.323 55.056 ;
     RECT  0.192 55.056 0.323 55.08 ;
     RECT  0.156 55.08 0.323 55.152 ;
     RECT  0.192 55.152 0.323 55.176 ;
     RECT  0.156 55.176 0.323 55.248 ;
     RECT  0.192 55.248 0.323 55.272 ;
     RECT  0.156 55.272 0.323 55.344 ;
     RECT  0.192 55.344 0.323 55.368 ;
     RECT  0.156 55.368 0.323 55.488 ;
     RECT  0.192 55.488 0.323 55.512 ;
     RECT  0.156 55.512 0.323 55.584 ;
     RECT  0.192 55.584 0.323 55.608 ;
     RECT  0.156 55.608 0.323 55.68 ;
     RECT  0.192 55.68 0.323 55.704 ;
     RECT  0.156 55.704 0.323 55.776 ;
     RECT  0.192 55.776 0.323 55.8 ;
     RECT  0.156 55.8 0.323 55.872 ;
     RECT  0.192 55.872 0.323 55.896 ;
     RECT  0.156 55.896 0.323 55.968 ;
     RECT  0.192 55.968 0.323 55.992 ;
     RECT  0.156 55.992 0.323 56.112 ;
     RECT  0.192 56.112 0.323 56.136 ;
     RECT  0.156 56.136 0.323 56.208 ;
     RECT  0.192 56.208 0.323 56.232 ;
     RECT  0.156 56.232 0.323 56.304 ;
     RECT  0.192 56.304 0.323 56.328 ;
     RECT  0.156 56.328 0.323 56.4 ;
     RECT  0.192 56.4 0.323 56.424 ;
     RECT  0.156 56.424 0.323 56.496 ;
     RECT  0.192 56.496 0.323 56.52 ;
     RECT  0.156 56.52 0.323 56.592 ;
     RECT  0.192 56.592 0.323 56.616 ;
     RECT  0.156 56.616 0.323 56.688 ;
     RECT  0.192 56.688 0.323 56.712 ;
     RECT  0.156 56.712 0.323 56.832 ;
     RECT  0.192 56.832 0.323 56.856 ;
     RECT  0.156 56.856 0.323 56.928 ;
     RECT  0.192 56.928 0.323 56.952 ;
     RECT  0.156 56.952 0.323 57.024 ;
     RECT  0.192 57.024 0.323 57.048 ;
     RECT  0.156 57.048 0.323 57.12 ;
     RECT  0.192 57.12 0.323 57.144 ;
     RECT  0.156 57.144 0.323 57.216 ;
     RECT  0.192 57.216 0.323 57.24 ;
     RECT  0.156 57.24 0.323 57.312 ;
     RECT  0.192 57.312 0.323 57.336 ;
     RECT  0.156 57.336 0.323 57.456 ;
     RECT  0.192 57.456 0.323 57.48 ;
     RECT  0.156 57.48 0.323 57.552 ;
     RECT  0.192 57.552 0.323 57.576 ;
     RECT  0.156 57.576 0.323 57.648 ;
     RECT  0.192 57.648 0.323 57.672 ;
     RECT  0.156 57.672 0.323 57.744 ;
     RECT  0.192 57.744 0.323 57.768 ;
     RECT  0.156 57.768 0.323 57.84 ;
     RECT  0.192 57.84 0.323 57.864 ;
     RECT  0.156 57.864 0.323 57.936 ;
     RECT  0.192 57.936 0.323 57.96 ;
     RECT  0.156 57.96 0.323 58.08 ;
     RECT  0.192 58.08 0.323 58.104 ;
     RECT  0.156 58.104 0.323 58.176 ;
     RECT  0.192 58.176 0.323 58.2 ;
     RECT  0.156 58.2 0.323 58.272 ;
     RECT  0.192 58.272 0.323 58.296 ;
     RECT  0.156 58.296 0.323 58.368 ;
     RECT  0.192 58.368 0.323 58.392 ;
     RECT  0.156 58.392 0.323 58.464 ;
     RECT  0.192 58.464 0.323 58.488 ;
     RECT  0.156 58.488 0.323 58.56 ;
     RECT  0.192 58.56 0.323 58.584 ;
     RECT  0.156 58.584 0.323 58.656 ;
     RECT  0.192 58.656 0.323 58.68 ;
     RECT  0.156 58.68 0.323 58.8 ;
     RECT  0.192 58.8 0.323 58.824 ;
     RECT  0.156 58.824 0.323 58.896 ;
     RECT  0.192 58.896 0.323 58.92 ;
     RECT  0.156 58.92 0.323 58.992 ;
     RECT  0.192 58.992 0.323 59.016 ;
     RECT  0.156 59.016 0.323 59.088 ;
     RECT  0.192 59.088 0.323 59.112 ;
     RECT  0.156 59.112 0.323 59.184 ;
     RECT  0.192 59.184 0.323 59.208 ;
     RECT  0.156 59.208 0.323 59.28 ;
     RECT  0.192 59.28 0.323 59.304 ;
     RECT  0.156 59.304 0.323 59.424 ;
     RECT  0.192 59.424 0.323 59.448 ;
     RECT  0.156 59.448 0.323 59.52 ;
     RECT  0.192 59.52 0.323 59.544 ;
     RECT  0.156 59.544 0.323 59.616 ;
     RECT  0.192 59.616 0.323 59.64 ;
     RECT  0.156 59.64 0.323 59.712 ;
     RECT  0.192 59.712 0.323 59.736 ;
     RECT  0.156 59.736 0.323 59.808 ;
     RECT  0.192 59.808 0.323 59.832 ;
     RECT  0.156 59.832 0.323 59.904 ;
     RECT  0.192 59.904 0.323 59.928 ;
     RECT  0.156 59.928 0.323 60.048 ;
     RECT  0.192 60.048 0.323 60.072 ;
     RECT  0.156 60.072 0.323 60.144 ;
     RECT  0.192 60.144 0.323 60.168 ;
     RECT  0.156 60.168 0.323 60.24 ;
     RECT  0.192 60.24 0.323 60.264 ;
     RECT  0.156 60.264 0.323 60.336 ;
     RECT  0.192 60.336 0.323 60.36 ;
     RECT  0.156 60.36 0.323 60.432 ;
     RECT  0.192 60.432 0.323 60.456 ;
     RECT  0.323 2.208 2.408 60.408 ;
     RECT  2.408 2.148 2.512 60.492 ;
     RECT  2.512 2.304 3.449 60.408 ;
     RECT  3.449 2.304 4.025 60.312 ;
     RECT  4.025 2.832 4.133 60.312 ;
     RECT  4.133 2.832 5.108 8.04 ;
     RECT  4.133 9.312 5.108 58.968 ;
     RECT  4.133 60.288 5.108 60.312 ;
     RECT  5.108 2.148 5.212 60.492 ;
     RECT  5.212 2.418 5.404 60.492 ;
     RECT  5.389 61.584 5.603 61.608 ;
     RECT  5.404 2.496 5.717 20.952 ;
     RECT  5.404 43.344 5.717 60.492 ;
     RECT  5.717 2.496 5.753 5.496 ;
     RECT  5.717 58.128 5.965 60.492 ;
     RECT  5.717 6.624 6.421 20.952 ;
     RECT  5.404 21.936 6.421 42.312 ;
     RECT  5.717 43.344 6.793 57.144 ;
     RECT  5.965 58.128 6.793 61.272 ;
     RECT  6.421 6.624 6.829 42.312 ;
     RECT  6.793 43.344 6.829 61.272 ;
     RECT  5.753 2.832 7.009 5.496 ;
     RECT  6.829 6.624 7.009 61.272 ;
     RECT  7.009 2.832 7.513 61.272 ;
     RECT  7.513 2.64 7.549 61.272 ;
     RECT  7.549 2.544 7.657 61.272 ;
     RECT  7.657 2.496 7.808 61.272 ;
     RECT  7.808 2.148 7.912 61.272 ;
     RECT  7.912 2.304 9.155 61.272 ;
     RECT  9.155 2.352 10.508 61.272 ;
     RECT  10.508 2.148 10.612 61.272 ;
     RECT  10.612 2.352 11.891 61.272 ;
     RECT  11.891 2.352 13.208 60.552 ;
     RECT  13.208 2.148 13.312 60.552 ;
     RECT  13.312 2.352 13.637 60.552 ;
     RECT  13.637 2.784 14.857 60.552 ;
     RECT  14.857 2.304 14.897 60.552 ;
     RECT  14.897 2.304 16.513 60.456 ;
     RECT  16.513 2.208 17.088 2.232 ;
     RECT  16.513 2.232 17.1 2.304 ;
     RECT  16.513 2.304 17.088 2.328 ;
     RECT  16.513 2.328 17.1 2.448 ;
     RECT  16.513 2.448 17.088 2.472 ;
     RECT  16.513 2.472 17.1 2.544 ;
     RECT  16.513 2.544 17.088 2.568 ;
     RECT  16.513 2.568 17.1 2.64 ;
     RECT  16.513 2.64 17.088 2.664 ;
     RECT  16.513 2.664 17.1 2.736 ;
     RECT  16.513 2.736 17.088 2.76 ;
     RECT  16.513 2.76 17.1 2.832 ;
     RECT  16.513 2.832 17.088 2.856 ;
     RECT  16.513 2.856 17.1 2.928 ;
     RECT  16.513 2.928 17.088 2.952 ;
     RECT  16.513 2.952 17.1 3.072 ;
     RECT  16.513 3.072 17.088 3.096 ;
     RECT  16.513 3.096 17.1 3.168 ;
     RECT  16.513 3.168 17.088 3.192 ;
     RECT  16.513 3.192 17.1 3.264 ;
     RECT  16.513 3.264 17.088 3.288 ;
     RECT  16.513 3.288 17.1 3.36 ;
     RECT  16.513 3.36 17.088 3.384 ;
     RECT  16.513 3.384 17.1 3.456 ;
     RECT  16.513 3.456 17.088 3.48 ;
     RECT  16.513 3.48 17.1 3.552 ;
     RECT  16.513 3.552 17.088 3.576 ;
     RECT  16.513 3.576 17.1 3.696 ;
     RECT  16.513 3.696 17.088 3.72 ;
     RECT  16.513 3.72 17.1 3.792 ;
     RECT  16.513 3.792 17.088 3.816 ;
     RECT  16.513 3.816 17.1 3.888 ;
     RECT  16.513 3.888 17.088 3.912 ;
     RECT  16.513 3.912 17.1 3.984 ;
     RECT  16.513 3.984 17.088 4.008 ;
     RECT  16.513 4.008 17.1 4.08 ;
     RECT  16.513 4.08 17.088 4.104 ;
     RECT  16.513 4.104 17.1 4.176 ;
     RECT  16.513 4.176 17.088 4.2 ;
     RECT  16.513 4.2 17.1 4.32 ;
     RECT  16.513 4.32 17.088 4.344 ;
     RECT  16.513 4.344 17.1 4.416 ;
     RECT  16.513 4.416 17.088 4.44 ;
     RECT  16.513 4.44 17.1 4.512 ;
     RECT  16.513 4.512 17.088 4.536 ;
     RECT  16.513 4.536 17.1 4.608 ;
     RECT  16.513 4.608 17.088 4.632 ;
     RECT  16.513 4.632 17.1 4.704 ;
     RECT  16.513 4.704 17.088 4.728 ;
     RECT  16.513 4.728 17.1 4.8 ;
     RECT  16.513 4.8 17.088 4.824 ;
     RECT  16.513 4.824 17.1 4.944 ;
     RECT  16.513 4.944 17.088 4.968 ;
     RECT  16.513 4.968 17.1 5.04 ;
     RECT  16.513 5.04 17.088 5.064 ;
     RECT  16.513 5.064 17.1 5.136 ;
     RECT  16.513 5.136 17.088 5.16 ;
     RECT  16.513 5.16 17.1 5.232 ;
     RECT  16.513 5.232 17.088 5.256 ;
     RECT  16.513 5.256 17.1 5.328 ;
     RECT  16.513 5.328 17.088 5.352 ;
     RECT  16.513 5.352 17.1 5.424 ;
     RECT  16.513 5.424 17.088 5.448 ;
     RECT  16.513 5.448 17.1 5.568 ;
     RECT  16.513 5.568 17.088 5.592 ;
     RECT  16.513 5.592 17.1 5.664 ;
     RECT  16.513 5.664 17.088 5.688 ;
     RECT  16.513 5.688 17.1 5.76 ;
     RECT  16.513 5.76 17.088 5.784 ;
     RECT  16.513 5.784 17.1 5.856 ;
     RECT  16.513 5.856 17.088 5.88 ;
     RECT  16.513 5.88 17.1 5.952 ;
     RECT  16.513 5.952 17.088 5.976 ;
     RECT  16.513 5.976 17.1 6.048 ;
     RECT  16.513 6.048 17.088 6.072 ;
     RECT  16.513 6.072 17.1 6.144 ;
     RECT  16.513 6.144 17.088 6.168 ;
     RECT  16.513 6.168 17.1 6.288 ;
     RECT  16.513 6.288 17.088 6.312 ;
     RECT  16.513 6.312 17.1 6.384 ;
     RECT  16.513 6.384 17.088 6.408 ;
     RECT  16.513 6.408 17.1 6.48 ;
     RECT  16.513 6.48 17.088 6.504 ;
     RECT  16.513 6.504 17.1 6.576 ;
     RECT  16.513 6.576 17.088 6.6 ;
     RECT  16.513 6.6 17.1 6.672 ;
     RECT  16.513 6.672 17.088 6.696 ;
     RECT  16.513 6.696 17.1 6.768 ;
     RECT  16.513 6.768 17.088 6.792 ;
     RECT  16.513 6.792 17.1 6.912 ;
     RECT  16.513 6.912 17.088 6.936 ;
     RECT  16.513 6.936 17.1 7.008 ;
     RECT  16.513 7.008 17.088 7.032 ;
     RECT  16.513 7.032 17.1 7.104 ;
     RECT  16.513 7.104 17.088 7.128 ;
     RECT  16.513 7.128 17.1 7.2 ;
     RECT  16.513 7.2 17.088 7.224 ;
     RECT  16.513 7.224 17.1 7.296 ;
     RECT  16.513 7.296 17.088 7.32 ;
     RECT  16.513 7.32 17.1 7.392 ;
     RECT  16.513 7.392 17.088 7.416 ;
     RECT  16.513 7.416 17.1 7.536 ;
     RECT  16.513 7.536 17.088 7.56 ;
     RECT  16.513 7.56 17.1 7.632 ;
     RECT  16.513 7.632 17.088 7.656 ;
     RECT  16.513 7.656 17.1 7.728 ;
     RECT  16.513 7.728 17.088 7.752 ;
     RECT  16.513 7.752 17.1 7.824 ;
     RECT  16.513 7.824 17.088 7.848 ;
     RECT  16.513 7.848 17.1 7.92 ;
     RECT  16.513 7.92 17.088 7.944 ;
     RECT  16.513 7.944 17.1 8.016 ;
     RECT  16.513 8.016 17.088 8.04 ;
     RECT  16.513 8.04 17.1 8.16 ;
     RECT  16.513 8.16 17.088 8.184 ;
     RECT  16.513 8.184 17.1 8.256 ;
     RECT  16.513 8.256 17.088 8.28 ;
     RECT  16.513 8.28 17.1 8.352 ;
     RECT  16.513 8.352 17.088 8.376 ;
     RECT  16.513 8.376 17.1 8.448 ;
     RECT  16.513 8.448 17.088 8.472 ;
     RECT  16.513 8.472 17.1 8.544 ;
     RECT  16.513 8.544 17.088 8.568 ;
     RECT  16.513 8.568 17.1 8.64 ;
     RECT  16.513 8.64 17.088 8.664 ;
     RECT  16.513 8.664 17.1 8.784 ;
     RECT  16.513 8.784 17.088 8.808 ;
     RECT  16.513 8.808 17.1 8.88 ;
     RECT  16.513 8.88 17.088 8.904 ;
     RECT  16.513 8.904 17.1 8.976 ;
     RECT  16.513 8.976 17.088 9 ;
     RECT  16.513 9 17.1 9.072 ;
     RECT  16.513 9.072 17.088 9.096 ;
     RECT  16.513 9.096 17.1 9.168 ;
     RECT  16.513 9.168 17.088 9.192 ;
     RECT  16.513 9.192 17.1 9.264 ;
     RECT  16.513 9.264 17.088 9.288 ;
     RECT  16.513 9.288 17.1 9.408 ;
     RECT  16.513 9.408 17.088 9.432 ;
     RECT  16.513 9.432 17.1 9.504 ;
     RECT  16.513 9.504 17.088 9.528 ;
     RECT  16.513 9.528 17.1 9.6 ;
     RECT  16.513 9.6 17.088 9.624 ;
     RECT  16.513 9.624 17.1 9.696 ;
     RECT  16.513 9.696 17.088 9.72 ;
     RECT  16.513 9.72 17.1 9.792 ;
     RECT  16.513 9.792 17.088 9.816 ;
     RECT  16.513 9.816 17.1 9.888 ;
     RECT  16.513 9.888 17.088 9.912 ;
     RECT  16.513 9.912 17.1 9.984 ;
     RECT  16.513 9.984 17.088 10.008 ;
     RECT  16.513 10.008 17.1 10.128 ;
     RECT  16.513 10.128 17.088 10.152 ;
     RECT  16.513 10.152 17.1 10.224 ;
     RECT  16.513 10.224 17.088 10.248 ;
     RECT  16.513 10.248 17.1 10.32 ;
     RECT  16.513 10.32 17.088 10.344 ;
     RECT  16.513 10.344 17.1 10.416 ;
     RECT  16.513 10.416 17.088 10.44 ;
     RECT  16.513 10.44 17.1 10.512 ;
     RECT  16.513 10.512 17.088 10.536 ;
     RECT  16.513 10.536 17.1 10.608 ;
     RECT  16.513 10.608 17.088 10.632 ;
     RECT  16.513 10.632 17.1 10.752 ;
     RECT  16.513 10.752 17.088 10.776 ;
     RECT  16.513 10.776 17.1 10.848 ;
     RECT  16.513 10.848 17.088 10.872 ;
     RECT  16.513 10.872 17.1 10.944 ;
     RECT  16.513 10.944 17.088 10.968 ;
     RECT  16.513 10.968 17.1 11.04 ;
     RECT  16.513 11.04 17.088 11.064 ;
     RECT  16.513 11.064 17.1 11.136 ;
     RECT  16.513 11.136 17.088 11.16 ;
     RECT  16.513 11.16 17.1 11.232 ;
     RECT  16.513 11.232 17.088 11.256 ;
     RECT  16.513 11.256 17.1 11.376 ;
     RECT  16.513 11.376 17.088 11.4 ;
     RECT  16.513 11.4 17.1 11.472 ;
     RECT  16.513 11.472 17.088 11.496 ;
     RECT  16.513 11.496 17.1 11.568 ;
     RECT  16.513 11.568 17.088 11.592 ;
     RECT  16.513 11.592 17.1 11.664 ;
     RECT  16.513 11.664 17.088 11.688 ;
     RECT  16.513 11.688 17.1 11.76 ;
     RECT  16.513 11.76 17.088 11.784 ;
     RECT  16.513 11.784 17.1 11.856 ;
     RECT  16.513 11.856 17.088 11.88 ;
     RECT  16.513 11.88 17.1 12 ;
     RECT  16.513 12 17.088 12.024 ;
     RECT  16.513 12.024 17.1 12.096 ;
     RECT  16.513 12.096 17.088 12.12 ;
     RECT  16.513 12.12 17.1 12.192 ;
     RECT  16.513 12.192 17.088 12.216 ;
     RECT  16.513 12.216 17.1 12.288 ;
     RECT  16.513 12.288 17.088 12.312 ;
     RECT  16.513 12.312 17.1 12.384 ;
     RECT  16.513 12.384 17.088 12.408 ;
     RECT  16.513 12.408 17.1 12.48 ;
     RECT  16.513 12.48 17.088 12.504 ;
     RECT  16.513 12.504 17.1 12.624 ;
     RECT  16.513 12.624 17.088 12.648 ;
     RECT  16.513 12.648 17.1 12.72 ;
     RECT  16.513 12.72 17.088 12.744 ;
     RECT  16.513 12.744 17.1 12.816 ;
     RECT  16.513 12.816 17.088 12.84 ;
     RECT  16.513 12.84 17.1 12.912 ;
     RECT  16.513 12.912 17.088 12.936 ;
     RECT  16.513 12.936 17.1 13.008 ;
     RECT  16.513 13.008 17.088 13.032 ;
     RECT  16.513 13.032 17.1 13.104 ;
     RECT  16.513 13.104 17.088 13.128 ;
     RECT  16.513 13.128 17.1 13.2 ;
     RECT  16.513 13.2 17.088 13.224 ;
     RECT  16.513 13.224 17.1 13.344 ;
     RECT  16.513 13.344 17.088 13.368 ;
     RECT  16.513 13.368 17.1 13.44 ;
     RECT  16.513 13.44 17.088 13.464 ;
     RECT  16.513 13.464 17.1 13.536 ;
     RECT  16.513 13.536 17.088 13.56 ;
     RECT  16.513 13.56 17.1 13.632 ;
     RECT  16.513 13.632 17.088 13.656 ;
     RECT  16.513 13.656 17.1 13.728 ;
     RECT  16.513 13.728 17.088 13.752 ;
     RECT  16.513 13.752 17.1 13.824 ;
     RECT  16.513 13.824 17.088 13.848 ;
     RECT  16.513 13.848 17.1 13.968 ;
     RECT  16.513 13.968 17.088 13.992 ;
     RECT  16.513 13.992 17.1 14.064 ;
     RECT  16.513 14.064 17.088 14.088 ;
     RECT  16.513 14.088 17.1 14.16 ;
     RECT  16.513 14.16 17.088 14.184 ;
     RECT  16.513 14.184 17.1 14.256 ;
     RECT  16.513 14.256 17.088 14.28 ;
     RECT  16.513 14.28 17.1 14.352 ;
     RECT  16.513 14.352 17.088 14.376 ;
     RECT  16.513 14.376 17.1 14.448 ;
     RECT  16.513 14.448 17.088 14.472 ;
     RECT  16.513 14.472 17.1 14.592 ;
     RECT  16.513 14.592 17.088 14.616 ;
     RECT  16.513 14.616 17.1 14.688 ;
     RECT  16.513 14.688 17.088 14.712 ;
     RECT  16.513 14.712 17.1 14.784 ;
     RECT  16.513 14.784 17.088 14.808 ;
     RECT  16.513 14.808 17.1 14.88 ;
     RECT  16.513 14.88 17.088 14.904 ;
     RECT  16.513 14.904 17.1 14.976 ;
     RECT  16.513 14.976 17.088 15 ;
     RECT  16.513 15 17.1 15.072 ;
     RECT  16.513 15.072 17.088 15.096 ;
     RECT  16.513 15.096 17.1 15.216 ;
     RECT  16.513 15.216 17.088 15.24 ;
     RECT  16.513 15.24 17.1 15.312 ;
     RECT  16.513 15.312 17.088 15.336 ;
     RECT  16.513 15.336 17.1 15.408 ;
     RECT  16.513 15.408 17.088 15.432 ;
     RECT  16.513 15.432 17.1 15.504 ;
     RECT  16.513 15.504 17.088 15.528 ;
     RECT  16.513 15.528 17.1 15.6 ;
     RECT  16.513 15.6 17.088 15.624 ;
     RECT  16.513 15.624 17.1 15.696 ;
     RECT  16.513 15.696 17.088 15.72 ;
     RECT  16.513 15.72 17.1 15.84 ;
     RECT  16.513 15.84 17.088 15.864 ;
     RECT  16.513 15.864 17.1 15.936 ;
     RECT  16.513 15.936 17.088 15.96 ;
     RECT  16.513 15.96 17.1 16.032 ;
     RECT  16.513 16.032 17.088 16.056 ;
     RECT  16.513 16.056 17.1 16.128 ;
     RECT  16.513 16.128 17.088 16.152 ;
     RECT  16.513 16.152 17.1 16.224 ;
     RECT  16.513 16.224 17.088 16.248 ;
     RECT  16.513 16.248 17.1 16.32 ;
     RECT  16.513 16.32 17.088 16.344 ;
     RECT  16.513 16.344 17.1 16.464 ;
     RECT  16.513 16.464 17.088 16.488 ;
     RECT  16.513 16.488 17.1 16.56 ;
     RECT  16.513 16.56 17.088 16.584 ;
     RECT  16.513 16.584 17.1 16.656 ;
     RECT  16.513 16.656 17.088 16.68 ;
     RECT  16.513 16.68 17.1 16.752 ;
     RECT  16.513 16.752 17.088 16.776 ;
     RECT  16.513 16.776 17.1 16.848 ;
     RECT  16.513 16.848 17.088 16.872 ;
     RECT  16.513 16.872 17.1 16.944 ;
     RECT  16.513 16.944 17.088 16.968 ;
     RECT  16.513 16.968 17.1 17.04 ;
     RECT  16.513 17.04 17.088 17.064 ;
     RECT  16.513 17.064 17.1 17.184 ;
     RECT  16.513 17.184 17.088 17.208 ;
     RECT  16.513 17.208 17.1 17.28 ;
     RECT  16.513 17.28 17.088 17.304 ;
     RECT  16.513 17.304 17.1 17.376 ;
     RECT  16.513 17.376 17.088 17.4 ;
     RECT  16.513 17.4 17.1 17.472 ;
     RECT  16.513 17.472 17.088 17.496 ;
     RECT  16.513 17.496 17.1 17.568 ;
     RECT  16.513 17.568 17.088 17.592 ;
     RECT  16.513 17.592 17.1 17.664 ;
     RECT  16.513 17.664 17.088 17.688 ;
     RECT  16.513 17.688 17.1 17.808 ;
     RECT  16.513 17.808 17.088 17.832 ;
     RECT  16.513 17.832 17.1 17.904 ;
     RECT  16.513 17.904 17.088 17.928 ;
     RECT  16.513 17.928 17.1 18 ;
     RECT  16.513 18 17.088 18.024 ;
     RECT  16.513 18.024 17.1 18.096 ;
     RECT  16.513 18.096 17.088 18.12 ;
     RECT  16.513 18.12 17.1 18.192 ;
     RECT  16.513 18.192 17.088 18.216 ;
     RECT  16.513 18.216 17.1 18.288 ;
     RECT  16.513 18.288 17.088 18.312 ;
     RECT  16.513 18.312 17.1 18.432 ;
     RECT  16.513 18.432 17.088 18.456 ;
     RECT  16.513 18.456 17.1 18.528 ;
     RECT  16.513 18.528 17.088 18.552 ;
     RECT  16.513 18.552 17.1 18.624 ;
     RECT  16.513 18.624 17.088 18.648 ;
     RECT  16.513 18.648 17.1 18.72 ;
     RECT  16.513 18.72 17.088 18.744 ;
     RECT  16.513 18.744 17.1 18.816 ;
     RECT  16.513 18.816 17.088 18.84 ;
     RECT  16.513 18.84 17.1 18.912 ;
     RECT  16.513 18.912 17.088 18.936 ;
     RECT  16.513 18.936 17.1 19.056 ;
     RECT  16.513 19.056 17.088 19.08 ;
     RECT  16.513 19.08 17.1 19.152 ;
     RECT  16.513 19.152 17.088 19.176 ;
     RECT  16.513 19.176 17.1 19.248 ;
     RECT  16.513 19.248 17.088 19.272 ;
     RECT  16.513 19.272 17.1 19.344 ;
     RECT  16.513 19.344 17.088 19.368 ;
     RECT  16.513 19.368 17.1 19.44 ;
     RECT  16.513 19.44 17.088 19.464 ;
     RECT  16.513 19.464 17.1 19.536 ;
     RECT  16.513 19.536 17.088 19.56 ;
     RECT  16.513 19.56 17.1 19.68 ;
     RECT  16.513 19.68 17.088 19.704 ;
     RECT  16.513 19.704 17.1 19.776 ;
     RECT  16.513 19.776 17.088 19.8 ;
     RECT  16.513 19.8 17.1 19.872 ;
     RECT  16.513 19.872 17.088 19.896 ;
     RECT  16.513 19.896 17.1 19.968 ;
     RECT  16.513 19.968 17.088 19.992 ;
     RECT  16.513 19.992 17.1 20.064 ;
     RECT  16.513 20.064 17.088 20.088 ;
     RECT  16.513 20.088 17.1 20.16 ;
     RECT  16.513 20.16 17.088 20.184 ;
     RECT  16.513 20.184 17.1 20.304 ;
     RECT  16.513 20.304 17.088 20.328 ;
     RECT  16.513 20.328 17.1 20.4 ;
     RECT  16.513 20.4 17.088 20.424 ;
     RECT  16.513 20.424 17.1 20.496 ;
     RECT  16.513 20.496 17.088 20.52 ;
     RECT  16.513 20.52 17.1 20.592 ;
     RECT  16.513 20.592 17.088 20.616 ;
     RECT  16.513 20.616 17.1 20.688 ;
     RECT  16.513 20.688 17.088 20.712 ;
     RECT  16.513 20.712 17.1 20.784 ;
     RECT  16.513 20.784 17.088 20.808 ;
     RECT  16.513 20.808 17.1 20.88 ;
     RECT  16.513 20.88 17.088 20.904 ;
     RECT  16.513 20.904 17.1 21.024 ;
     RECT  16.513 21.024 17.088 21.048 ;
     RECT  16.513 21.048 17.1 21.12 ;
     RECT  16.513 21.12 17.088 21.144 ;
     RECT  16.513 21.144 17.1 21.216 ;
     RECT  16.513 21.216 17.088 21.24 ;
     RECT  16.513 21.24 17.1 21.312 ;
     RECT  16.513 21.312 17.088 21.336 ;
     RECT  16.513 21.336 17.1 21.408 ;
     RECT  16.513 21.408 17.088 21.432 ;
     RECT  16.513 21.432 17.1 21.504 ;
     RECT  16.513 21.504 17.088 21.528 ;
     RECT  16.513 21.528 17.1 21.648 ;
     RECT  16.513 21.648 17.088 21.672 ;
     RECT  16.513 21.672 17.1 21.744 ;
     RECT  16.513 21.744 17.088 21.768 ;
     RECT  16.513 21.768 17.1 21.84 ;
     RECT  16.513 21.84 17.088 21.864 ;
     RECT  16.513 21.864 17.1 21.936 ;
     RECT  16.513 21.936 17.088 21.96 ;
     RECT  16.513 21.96 17.1 22.032 ;
     RECT  16.513 22.032 17.088 22.056 ;
     RECT  16.513 22.056 17.1 22.128 ;
     RECT  16.513 22.128 17.088 22.152 ;
     RECT  16.513 22.152 17.1 22.272 ;
     RECT  16.513 22.272 17.088 22.296 ;
     RECT  16.513 22.296 17.1 22.368 ;
     RECT  16.513 22.368 17.088 22.392 ;
     RECT  16.513 22.392 17.1 22.464 ;
     RECT  16.513 22.464 17.088 22.488 ;
     RECT  16.513 22.488 17.1 22.56 ;
     RECT  16.513 22.56 17.088 22.584 ;
     RECT  16.513 22.584 17.1 22.656 ;
     RECT  16.513 22.656 17.088 22.68 ;
     RECT  16.513 22.68 17.1 22.752 ;
     RECT  16.513 22.752 17.088 22.776 ;
     RECT  16.513 22.776 17.1 22.896 ;
     RECT  16.513 22.896 17.088 22.92 ;
     RECT  16.513 22.92 17.1 22.992 ;
     RECT  16.513 22.992 17.088 23.016 ;
     RECT  16.513 23.016 17.1 23.088 ;
     RECT  16.513 23.088 17.088 23.112 ;
     RECT  16.513 23.112 17.1 23.184 ;
     RECT  16.513 23.184 17.088 23.208 ;
     RECT  16.513 23.208 17.1 23.28 ;
     RECT  16.513 23.28 17.088 23.304 ;
     RECT  16.513 23.304 17.1 23.376 ;
     RECT  16.513 23.376 17.088 23.4 ;
     RECT  16.513 23.4 17.1 23.52 ;
     RECT  16.513 23.52 17.088 23.544 ;
     RECT  16.513 23.544 17.1 23.616 ;
     RECT  16.513 23.616 17.088 23.64 ;
     RECT  16.513 23.64 17.1 23.712 ;
     RECT  16.513 23.712 17.088 23.736 ;
     RECT  16.513 23.736 17.1 23.808 ;
     RECT  16.513 23.808 17.088 23.832 ;
     RECT  16.513 23.832 17.1 23.904 ;
     RECT  16.513 23.904 17.088 23.928 ;
     RECT  16.513 23.928 17.1 24 ;
     RECT  16.513 24 17.088 24.024 ;
     RECT  16.513 24.024 17.1 24.096 ;
     RECT  16.513 24.096 17.088 24.12 ;
     RECT  16.513 24.12 17.1 24.24 ;
     RECT  16.513 24.24 17.088 24.264 ;
     RECT  16.513 24.264 17.1 24.336 ;
     RECT  16.513 24.336 17.088 24.36 ;
     RECT  16.513 24.36 17.1 24.432 ;
     RECT  16.513 24.432 17.088 24.456 ;
     RECT  16.513 24.456 17.1 24.528 ;
     RECT  16.513 24.528 17.088 24.552 ;
     RECT  16.513 24.552 17.1 24.624 ;
     RECT  16.513 24.624 17.088 24.648 ;
     RECT  16.513 24.648 17.1 24.72 ;
     RECT  16.513 24.72 17.088 24.744 ;
     RECT  16.513 24.744 17.1 24.864 ;
     RECT  16.513 24.864 17.088 24.888 ;
     RECT  16.513 24.888 17.1 24.96 ;
     RECT  16.513 24.96 17.088 24.984 ;
     RECT  16.513 24.984 17.1 25.056 ;
     RECT  16.513 25.056 17.088 25.08 ;
     RECT  16.513 25.08 17.1 25.152 ;
     RECT  16.513 25.152 17.088 25.176 ;
     RECT  16.513 25.176 17.1 25.248 ;
     RECT  16.513 25.248 17.088 25.272 ;
     RECT  16.513 25.272 17.1 25.344 ;
     RECT  16.513 25.344 17.088 25.368 ;
     RECT  16.513 25.368 17.1 25.488 ;
     RECT  16.513 25.488 17.088 25.512 ;
     RECT  16.513 25.512 17.1 25.584 ;
     RECT  16.513 25.584 17.088 25.608 ;
     RECT  16.513 25.608 17.1 25.68 ;
     RECT  16.513 25.68 17.088 25.704 ;
     RECT  16.513 25.704 17.1 25.776 ;
     RECT  16.513 25.776 17.088 25.8 ;
     RECT  16.513 25.8 17.1 25.872 ;
     RECT  16.513 25.872 17.088 25.896 ;
     RECT  16.513 25.896 17.1 25.968 ;
     RECT  16.513 25.968 17.088 25.992 ;
     RECT  16.513 25.992 17.1 26.112 ;
     RECT  16.513 26.112 17.088 26.136 ;
     RECT  16.513 26.136 17.1 26.208 ;
     RECT  16.513 26.208 17.088 26.232 ;
     RECT  16.513 26.232 17.1 26.304 ;
     RECT  16.513 26.304 17.088 26.328 ;
     RECT  16.513 26.328 17.1 26.4 ;
     RECT  16.513 26.4 17.088 26.424 ;
     RECT  16.513 26.424 17.1 26.496 ;
     RECT  16.513 26.496 17.088 26.52 ;
     RECT  16.513 26.52 17.1 26.592 ;
     RECT  16.513 26.592 17.088 26.616 ;
     RECT  16.513 26.616 17.1 26.736 ;
     RECT  16.513 26.736 17.088 26.76 ;
     RECT  16.513 26.76 17.1 26.832 ;
     RECT  16.513 26.832 17.088 26.856 ;
     RECT  16.513 26.856 17.1 26.928 ;
     RECT  16.513 26.928 17.088 26.952 ;
     RECT  16.513 26.952 17.1 27.024 ;
     RECT  16.513 27.024 17.088 27.048 ;
     RECT  16.513 27.048 17.1 27.12 ;
     RECT  16.513 27.12 17.088 27.144 ;
     RECT  16.513 27.144 17.1 27.216 ;
     RECT  16.513 27.216 17.088 27.24 ;
     RECT  16.513 27.24 17.1 27.36 ;
     RECT  16.513 27.36 17.088 27.384 ;
     RECT  16.513 27.384 17.1 27.456 ;
     RECT  16.513 27.456 17.088 27.48 ;
     RECT  16.513 27.48 17.1 27.552 ;
     RECT  16.513 27.552 17.088 27.576 ;
     RECT  16.513 27.576 17.1 27.648 ;
     RECT  16.513 27.648 17.088 27.672 ;
     RECT  16.513 27.672 17.1 27.744 ;
     RECT  16.513 27.744 17.088 27.768 ;
     RECT  16.513 27.768 17.1 27.84 ;
     RECT  16.513 27.84 17.088 27.864 ;
     RECT  16.513 27.864 17.1 27.936 ;
     RECT  16.513 27.936 17.088 27.96 ;
     RECT  16.513 27.96 17.1 28.08 ;
     RECT  16.513 28.08 17.088 28.104 ;
     RECT  16.513 28.104 17.1 28.176 ;
     RECT  16.513 28.176 17.088 28.2 ;
     RECT  16.513 28.2 17.1 28.272 ;
     RECT  16.513 28.272 17.088 28.296 ;
     RECT  16.513 28.296 17.1 28.368 ;
     RECT  16.513 28.368 17.088 28.392 ;
     RECT  16.513 28.392 17.1 28.464 ;
     RECT  16.513 28.464 17.088 28.488 ;
     RECT  16.513 28.488 17.1 28.56 ;
     RECT  16.513 28.56 17.088 28.584 ;
     RECT  16.513 28.584 17.1 28.704 ;
     RECT  16.513 28.704 17.088 28.728 ;
     RECT  16.513 28.728 17.1 28.8 ;
     RECT  16.513 28.8 17.088 28.824 ;
     RECT  16.513 28.824 17.1 28.896 ;
     RECT  16.513 28.896 17.088 28.92 ;
     RECT  16.513 28.92 17.1 28.992 ;
     RECT  16.513 28.992 17.088 29.016 ;
     RECT  16.513 29.016 17.1 29.088 ;
     RECT  16.513 29.088 17.088 29.112 ;
     RECT  16.513 29.112 17.1 29.184 ;
     RECT  16.513 29.184 17.088 29.208 ;
     RECT  16.513 29.208 17.1 29.328 ;
     RECT  16.513 29.328 17.088 29.352 ;
     RECT  16.513 29.352 17.1 29.424 ;
     RECT  16.513 29.424 17.088 29.448 ;
     RECT  16.513 29.448 17.1 29.52 ;
     RECT  16.513 29.52 17.088 29.544 ;
     RECT  16.513 29.544 17.1 29.616 ;
     RECT  16.513 29.616 17.088 29.64 ;
     RECT  16.513 29.64 17.1 29.712 ;
     RECT  16.513 29.712 17.088 29.736 ;
     RECT  16.513 29.736 17.1 29.808 ;
     RECT  16.513 29.808 17.088 29.832 ;
     RECT  16.513 29.832 17.1 29.952 ;
     RECT  16.513 29.952 17.088 29.976 ;
     RECT  16.513 29.976 17.1 30.048 ;
     RECT  16.513 30.048 17.088 30.072 ;
     RECT  16.513 30.072 17.1 30.144 ;
     RECT  16.513 30.144 17.088 30.168 ;
     RECT  16.513 30.168 17.1 30.24 ;
     RECT  16.513 30.24 17.088 30.264 ;
     RECT  16.513 30.264 17.1 30.336 ;
     RECT  16.513 30.336 17.088 30.36 ;
     RECT  16.513 30.36 17.1 30.432 ;
     RECT  16.513 30.432 17.088 30.456 ;
     RECT  16.513 30.456 17.1 30.576 ;
     RECT  16.513 30.576 17.088 30.6 ;
     RECT  16.513 30.6 17.1 30.672 ;
     RECT  16.513 30.672 17.088 30.696 ;
     RECT  16.513 30.696 17.1 30.768 ;
     RECT  16.513 30.768 17.088 30.792 ;
     RECT  16.513 30.792 17.1 30.864 ;
     RECT  16.513 30.864 17.088 30.888 ;
     RECT  16.513 30.888 17.1 30.96 ;
     RECT  16.513 30.96 17.088 30.984 ;
     RECT  16.513 30.984 17.1 31.056 ;
     RECT  16.513 31.056 17.088 31.08 ;
     RECT  16.513 31.08 17.1 31.2 ;
     RECT  16.513 31.2 17.088 31.224 ;
     RECT  16.513 31.224 17.1 31.296 ;
     RECT  16.513 31.296 17.088 31.32 ;
     RECT  16.513 31.32 17.1 31.392 ;
     RECT  16.513 31.392 17.088 31.416 ;
     RECT  16.513 31.416 17.1 31.488 ;
     RECT  16.513 31.488 17.088 31.512 ;
     RECT  16.513 31.512 17.1 31.584 ;
     RECT  16.513 31.584 17.088 31.608 ;
     RECT  16.513 31.608 17.1 31.68 ;
     RECT  16.513 31.68 17.088 31.704 ;
     RECT  16.513 31.704 17.1 31.776 ;
     RECT  16.513 31.776 17.088 31.8 ;
     RECT  16.513 31.8 17.1 31.92 ;
     RECT  16.513 31.92 17.088 31.944 ;
     RECT  16.513 31.944 17.1 32.016 ;
     RECT  16.513 32.016 17.088 32.04 ;
     RECT  16.513 32.04 17.1 32.112 ;
     RECT  16.513 32.112 17.088 32.136 ;
     RECT  16.513 32.136 17.1 32.208 ;
     RECT  16.513 32.208 17.088 32.232 ;
     RECT  16.513 32.232 17.1 32.304 ;
     RECT  16.513 32.304 17.088 32.328 ;
     RECT  16.513 32.328 17.1 32.4 ;
     RECT  16.513 32.4 17.088 32.424 ;
     RECT  16.513 32.424 17.1 32.544 ;
     RECT  16.513 32.544 17.088 32.568 ;
     RECT  16.513 32.568 17.1 32.64 ;
     RECT  16.513 32.64 17.088 32.664 ;
     RECT  16.513 32.664 17.1 32.736 ;
     RECT  16.513 32.736 17.088 32.76 ;
     RECT  16.513 32.76 17.1 32.832 ;
     RECT  16.513 32.832 17.088 32.856 ;
     RECT  16.513 32.856 17.1 32.928 ;
     RECT  16.513 32.928 17.088 32.952 ;
     RECT  16.513 32.952 17.1 33.024 ;
     RECT  16.513 33.024 17.088 33.048 ;
     RECT  16.513 33.048 17.1 33.168 ;
     RECT  16.513 33.168 17.088 33.192 ;
     RECT  16.513 33.192 17.1 33.264 ;
     RECT  16.513 33.264 17.088 33.288 ;
     RECT  16.513 33.288 17.1 33.36 ;
     RECT  16.513 33.36 17.088 33.384 ;
     RECT  16.513 33.384 17.1 33.456 ;
     RECT  16.513 33.456 17.088 33.48 ;
     RECT  16.513 33.48 17.1 33.552 ;
     RECT  16.513 33.552 17.088 33.576 ;
     RECT  16.513 33.576 17.1 33.648 ;
     RECT  16.513 33.648 17.088 33.672 ;
     RECT  16.513 33.672 17.1 33.792 ;
     RECT  16.513 33.792 17.088 33.816 ;
     RECT  16.513 33.816 17.1 33.888 ;
     RECT  16.513 33.888 17.088 33.912 ;
     RECT  16.513 33.912 17.1 33.984 ;
     RECT  16.513 33.984 17.088 34.008 ;
     RECT  16.513 34.008 17.1 34.08 ;
     RECT  16.513 34.08 17.088 34.104 ;
     RECT  16.513 34.104 17.1 34.176 ;
     RECT  16.513 34.176 17.088 34.2 ;
     RECT  16.513 34.2 17.1 34.272 ;
     RECT  16.513 34.272 17.088 34.296 ;
     RECT  16.513 34.296 17.1 34.416 ;
     RECT  16.513 34.416 17.088 34.44 ;
     RECT  16.513 34.44 17.1 34.512 ;
     RECT  16.513 34.512 17.088 34.536 ;
     RECT  16.513 34.536 17.1 34.608 ;
     RECT  16.513 34.608 17.088 34.632 ;
     RECT  16.513 34.632 17.1 34.704 ;
     RECT  16.513 34.704 17.088 34.728 ;
     RECT  16.513 34.728 17.1 34.8 ;
     RECT  16.513 34.8 17.088 34.824 ;
     RECT  16.513 34.824 17.1 34.896 ;
     RECT  16.513 34.896 17.088 34.92 ;
     RECT  16.513 34.92 17.1 34.992 ;
     RECT  16.513 34.992 17.088 35.016 ;
     RECT  16.513 35.016 17.1 35.136 ;
     RECT  16.513 35.136 17.088 35.16 ;
     RECT  16.513 35.16 17.1 35.232 ;
     RECT  16.513 35.232 17.088 35.256 ;
     RECT  16.513 35.256 17.1 35.328 ;
     RECT  16.513 35.328 17.088 35.352 ;
     RECT  16.513 35.352 17.1 35.424 ;
     RECT  16.513 35.424 17.088 35.448 ;
     RECT  16.513 35.448 17.1 35.52 ;
     RECT  16.513 35.52 17.088 35.544 ;
     RECT  16.513 35.544 17.1 35.616 ;
     RECT  16.513 35.616 17.088 35.64 ;
     RECT  16.513 35.64 17.1 35.76 ;
     RECT  16.513 35.76 17.088 35.784 ;
     RECT  16.513 35.784 17.1 35.856 ;
     RECT  16.513 35.856 17.088 35.88 ;
     RECT  16.513 35.88 17.1 35.952 ;
     RECT  16.513 35.952 17.088 35.976 ;
     RECT  16.513 35.976 17.1 36.048 ;
     RECT  16.513 36.048 17.088 36.072 ;
     RECT  16.513 36.072 17.1 36.144 ;
     RECT  16.513 36.144 17.088 36.168 ;
     RECT  16.513 36.168 17.1 36.24 ;
     RECT  16.513 36.24 17.088 36.264 ;
     RECT  16.513 36.264 17.1 36.384 ;
     RECT  16.513 36.384 17.088 36.408 ;
     RECT  16.513 36.408 17.1 36.48 ;
     RECT  16.513 36.48 17.088 36.504 ;
     RECT  16.513 36.504 17.1 36.576 ;
     RECT  16.513 36.576 17.088 36.6 ;
     RECT  16.513 36.6 17.1 36.672 ;
     RECT  16.513 36.672 17.088 36.696 ;
     RECT  16.513 36.696 17.1 36.768 ;
     RECT  16.513 36.768 17.088 36.792 ;
     RECT  16.513 36.792 17.1 36.864 ;
     RECT  16.513 36.864 17.088 36.888 ;
     RECT  16.513 36.888 17.1 37.008 ;
     RECT  16.513 37.008 17.088 37.032 ;
     RECT  16.513 37.032 17.1 37.104 ;
     RECT  16.513 37.104 17.088 37.128 ;
     RECT  16.513 37.128 17.1 37.2 ;
     RECT  16.513 37.2 17.088 37.224 ;
     RECT  16.513 37.224 17.1 37.296 ;
     RECT  16.513 37.296 17.088 37.32 ;
     RECT  16.513 37.32 17.1 37.392 ;
     RECT  16.513 37.392 17.088 37.416 ;
     RECT  16.513 37.416 17.1 37.488 ;
     RECT  16.513 37.488 17.088 37.512 ;
     RECT  16.513 37.512 17.1 37.632 ;
     RECT  16.513 37.632 17.088 37.656 ;
     RECT  16.513 37.656 17.1 37.728 ;
     RECT  16.513 37.728 17.088 37.752 ;
     RECT  16.513 37.752 17.1 37.824 ;
     RECT  16.513 37.824 17.088 37.848 ;
     RECT  16.513 37.848 17.1 37.92 ;
     RECT  16.513 37.92 17.088 37.944 ;
     RECT  16.513 37.944 17.1 38.016 ;
     RECT  16.513 38.016 17.088 38.04 ;
     RECT  16.513 38.04 17.1 38.112 ;
     RECT  16.513 38.112 17.088 38.136 ;
     RECT  16.513 38.136 17.1 38.256 ;
     RECT  16.513 38.256 17.088 38.28 ;
     RECT  16.513 38.28 17.1 38.352 ;
     RECT  16.513 38.352 17.088 38.376 ;
     RECT  16.513 38.376 17.1 38.448 ;
     RECT  16.513 38.448 17.088 38.472 ;
     RECT  16.513 38.472 17.1 38.544 ;
     RECT  16.513 38.544 17.088 38.568 ;
     RECT  16.513 38.568 17.1 38.64 ;
     RECT  16.513 38.64 17.088 38.664 ;
     RECT  16.513 38.664 17.1 38.736 ;
     RECT  16.513 38.736 17.088 38.76 ;
     RECT  16.513 38.76 17.1 38.832 ;
     RECT  16.513 38.832 17.088 38.856 ;
     RECT  16.513 38.856 17.1 38.976 ;
     RECT  16.513 38.976 17.088 39 ;
     RECT  16.513 39 17.1 39.072 ;
     RECT  16.513 39.072 17.088 39.096 ;
     RECT  16.513 39.096 17.1 39.168 ;
     RECT  16.513 39.168 17.088 39.192 ;
     RECT  16.513 39.192 17.1 39.264 ;
     RECT  16.513 39.264 17.088 39.288 ;
     RECT  16.513 39.288 17.1 39.36 ;
     RECT  16.513 39.36 17.088 39.384 ;
     RECT  16.513 39.384 17.1 39.456 ;
     RECT  16.513 39.456 17.088 39.48 ;
     RECT  16.513 39.48 17.1 39.6 ;
     RECT  16.513 39.6 17.088 39.624 ;
     RECT  16.513 39.624 17.1 39.696 ;
     RECT  16.513 39.696 17.088 39.72 ;
     RECT  16.513 39.72 17.1 39.792 ;
     RECT  16.513 39.792 17.088 39.816 ;
     RECT  16.513 39.816 17.1 39.888 ;
     RECT  16.513 39.888 17.088 39.912 ;
     RECT  16.513 39.912 17.1 39.984 ;
     RECT  16.513 39.984 17.088 40.008 ;
     RECT  16.513 40.008 17.1 40.08 ;
     RECT  16.513 40.08 17.088 40.104 ;
     RECT  16.513 40.104 17.1 40.224 ;
     RECT  16.513 40.224 17.088 40.248 ;
     RECT  16.513 40.248 17.1 40.32 ;
     RECT  16.513 40.32 17.088 40.344 ;
     RECT  16.513 40.344 17.1 40.416 ;
     RECT  16.513 40.416 17.088 40.44 ;
     RECT  16.513 40.44 17.1 40.512 ;
     RECT  16.513 40.512 17.088 40.536 ;
     RECT  16.513 40.536 17.1 40.608 ;
     RECT  16.513 40.608 17.088 40.632 ;
     RECT  16.513 40.632 17.1 40.704 ;
     RECT  16.513 40.704 17.088 40.728 ;
     RECT  16.513 40.728 17.1 40.848 ;
     RECT  16.513 40.848 17.088 40.872 ;
     RECT  16.513 40.872 17.1 40.944 ;
     RECT  16.513 40.944 17.088 40.968 ;
     RECT  16.513 40.968 17.1 41.04 ;
     RECT  16.513 41.04 17.088 41.064 ;
     RECT  16.513 41.064 17.1 41.136 ;
     RECT  16.513 41.136 17.088 41.16 ;
     RECT  16.513 41.16 17.1 41.232 ;
     RECT  16.513 41.232 17.088 41.256 ;
     RECT  16.513 41.256 17.1 41.328 ;
     RECT  16.513 41.328 17.088 41.352 ;
     RECT  16.513 41.352 17.1 41.472 ;
     RECT  16.513 41.472 17.088 41.496 ;
     RECT  16.513 41.496 17.1 41.568 ;
     RECT  16.513 41.568 17.088 41.592 ;
     RECT  16.513 41.592 17.1 41.664 ;
     RECT  16.513 41.664 17.088 41.688 ;
     RECT  16.513 41.688 17.1 41.76 ;
     RECT  16.513 41.76 17.088 41.784 ;
     RECT  16.513 41.784 17.1 41.856 ;
     RECT  16.513 41.856 17.088 41.88 ;
     RECT  16.513 41.88 17.1 41.952 ;
     RECT  16.513 41.952 17.088 41.976 ;
     RECT  16.513 41.976 17.1 42.096 ;
     RECT  16.513 42.096 17.088 42.12 ;
     RECT  16.513 42.12 17.1 42.192 ;
     RECT  16.513 42.192 17.088 42.216 ;
     RECT  16.513 42.216 17.1 42.288 ;
     RECT  16.513 42.288 17.088 42.312 ;
     RECT  16.513 42.312 17.1 42.384 ;
     RECT  16.513 42.384 17.088 42.408 ;
     RECT  16.513 42.408 17.1 42.48 ;
     RECT  16.513 42.48 17.088 42.504 ;
     RECT  16.513 42.504 17.1 42.576 ;
     RECT  16.513 42.576 17.088 42.6 ;
     RECT  16.513 42.6 17.1 42.672 ;
     RECT  16.513 42.672 17.088 42.696 ;
     RECT  16.513 42.696 17.1 42.816 ;
     RECT  16.513 42.816 17.088 42.84 ;
     RECT  16.513 42.84 17.1 42.912 ;
     RECT  16.513 42.912 17.088 42.936 ;
     RECT  16.513 42.936 17.1 43.008 ;
     RECT  16.513 43.008 17.088 43.032 ;
     RECT  16.513 43.032 17.1 43.104 ;
     RECT  16.513 43.104 17.088 43.128 ;
     RECT  16.513 43.128 17.1 43.2 ;
     RECT  16.513 43.2 17.088 43.224 ;
     RECT  16.513 43.224 17.1 43.296 ;
     RECT  16.513 43.296 17.088 43.32 ;
     RECT  16.513 43.32 17.1 43.44 ;
     RECT  16.513 43.44 17.088 43.464 ;
     RECT  16.513 43.464 17.1 43.536 ;
     RECT  16.513 43.536 17.088 43.56 ;
     RECT  16.513 43.56 17.1 43.632 ;
     RECT  16.513 43.632 17.088 43.656 ;
     RECT  16.513 43.656 17.1 43.728 ;
     RECT  16.513 43.728 17.088 43.752 ;
     RECT  16.513 43.752 17.1 43.824 ;
     RECT  16.513 43.824 17.088 43.848 ;
     RECT  16.513 43.848 17.1 43.92 ;
     RECT  16.513 43.92 17.088 43.944 ;
     RECT  16.513 43.944 17.1 44.064 ;
     RECT  16.513 44.064 17.088 44.088 ;
     RECT  16.513 44.088 17.1 44.16 ;
     RECT  16.513 44.16 17.088 44.184 ;
     RECT  16.513 44.184 17.1 44.256 ;
     RECT  16.513 44.256 17.088 44.28 ;
     RECT  16.513 44.28 17.1 44.352 ;
     RECT  16.513 44.352 17.088 44.376 ;
     RECT  16.513 44.376 17.1 44.448 ;
     RECT  16.513 44.448 17.088 44.472 ;
     RECT  16.513 44.472 17.1 44.544 ;
     RECT  16.513 44.544 17.088 44.568 ;
     RECT  16.513 44.568 17.1 44.688 ;
     RECT  16.513 44.688 17.088 44.712 ;
     RECT  16.513 44.712 17.1 44.784 ;
     RECT  16.513 44.784 17.088 44.808 ;
     RECT  16.513 44.808 17.1 44.88 ;
     RECT  16.513 44.88 17.088 44.904 ;
     RECT  16.513 44.904 17.1 44.976 ;
     RECT  16.513 44.976 17.088 45 ;
     RECT  16.513 45 17.1 45.072 ;
     RECT  16.513 45.072 17.088 45.096 ;
     RECT  16.513 45.096 17.1 45.168 ;
     RECT  16.513 45.168 17.088 45.192 ;
     RECT  16.513 45.192 17.1 45.312 ;
     RECT  16.513 45.312 17.088 45.336 ;
     RECT  16.513 45.336 17.1 45.408 ;
     RECT  16.513 45.408 17.088 45.432 ;
     RECT  16.513 45.432 17.1 45.504 ;
     RECT  16.513 45.504 17.088 45.528 ;
     RECT  16.513 45.528 17.1 45.6 ;
     RECT  16.513 45.6 17.088 45.624 ;
     RECT  16.513 45.624 17.1 45.696 ;
     RECT  16.513 45.696 17.088 45.72 ;
     RECT  16.513 45.72 17.1 45.792 ;
     RECT  16.513 45.792 17.088 45.816 ;
     RECT  16.513 45.816 17.1 45.936 ;
     RECT  16.513 45.936 17.088 45.96 ;
     RECT  16.513 45.96 17.1 46.032 ;
     RECT  16.513 46.032 17.088 46.056 ;
     RECT  16.513 46.056 17.1 46.128 ;
     RECT  16.513 46.128 17.088 46.152 ;
     RECT  16.513 46.152 17.1 46.224 ;
     RECT  16.513 46.224 17.088 46.248 ;
     RECT  16.513 46.248 17.1 46.32 ;
     RECT  16.513 46.32 17.088 46.344 ;
     RECT  16.513 46.344 17.1 46.416 ;
     RECT  16.513 46.416 17.088 46.44 ;
     RECT  16.513 46.44 17.1 46.512 ;
     RECT  16.513 46.512 17.088 46.536 ;
     RECT  16.513 46.536 17.1 46.656 ;
     RECT  16.513 46.656 17.088 46.68 ;
     RECT  16.513 46.68 17.1 46.752 ;
     RECT  16.513 46.752 17.088 46.776 ;
     RECT  16.513 46.776 17.1 46.848 ;
     RECT  16.513 46.848 17.088 46.872 ;
     RECT  16.513 46.872 17.1 46.944 ;
     RECT  16.513 46.944 17.088 46.968 ;
     RECT  16.513 46.968 17.1 47.04 ;
     RECT  16.513 47.04 17.088 47.064 ;
     RECT  16.513 47.064 17.1 47.136 ;
     RECT  16.513 47.136 17.088 47.16 ;
     RECT  16.513 47.16 17.1 47.28 ;
     RECT  16.513 47.28 17.088 47.304 ;
     RECT  16.513 47.304 17.1 47.376 ;
     RECT  16.513 47.376 17.088 47.4 ;
     RECT  16.513 47.4 17.1 47.472 ;
     RECT  16.513 47.472 17.088 47.496 ;
     RECT  16.513 47.496 17.1 47.568 ;
     RECT  16.513 47.568 17.088 47.592 ;
     RECT  16.513 47.592 17.1 47.664 ;
     RECT  16.513 47.664 17.088 47.688 ;
     RECT  16.513 47.688 17.1 47.76 ;
     RECT  16.513 47.76 17.088 47.784 ;
     RECT  16.513 47.784 17.1 47.904 ;
     RECT  16.513 47.904 17.088 47.928 ;
     RECT  16.513 47.928 17.1 48 ;
     RECT  16.513 48 17.088 48.024 ;
     RECT  16.513 48.024 17.1 48.096 ;
     RECT  16.513 48.096 17.088 48.12 ;
     RECT  16.513 48.12 17.1 48.192 ;
     RECT  16.513 48.192 17.088 48.216 ;
     RECT  16.513 48.216 17.1 48.288 ;
     RECT  16.513 48.288 17.088 48.312 ;
     RECT  16.513 48.312 17.1 48.384 ;
     RECT  16.513 48.384 17.088 48.408 ;
     RECT  16.513 48.408 17.1 48.528 ;
     RECT  16.513 48.528 17.088 48.552 ;
     RECT  16.513 48.552 17.1 48.624 ;
     RECT  16.513 48.624 17.088 48.648 ;
     RECT  16.513 48.648 17.1 48.72 ;
     RECT  16.513 48.72 17.088 48.744 ;
     RECT  16.513 48.744 17.1 48.816 ;
     RECT  16.513 48.816 17.088 48.84 ;
     RECT  16.513 48.84 17.1 48.912 ;
     RECT  16.513 48.912 17.088 48.936 ;
     RECT  16.513 48.936 17.1 49.008 ;
     RECT  16.513 49.008 17.088 49.032 ;
     RECT  16.513 49.032 17.1 49.152 ;
     RECT  16.513 49.152 17.088 49.176 ;
     RECT  16.513 49.176 17.1 49.248 ;
     RECT  16.513 49.248 17.088 49.272 ;
     RECT  16.513 49.272 17.1 49.344 ;
     RECT  16.513 49.344 17.088 49.368 ;
     RECT  16.513 49.368 17.1 49.44 ;
     RECT  16.513 49.44 17.088 49.464 ;
     RECT  16.513 49.464 17.1 49.536 ;
     RECT  16.513 49.536 17.088 49.56 ;
     RECT  16.513 49.56 17.1 49.632 ;
     RECT  16.513 49.632 17.088 49.656 ;
     RECT  16.513 49.656 17.1 49.728 ;
     RECT  16.513 49.728 17.088 49.752 ;
     RECT  16.513 49.752 17.1 49.872 ;
     RECT  16.513 49.872 17.088 49.896 ;
     RECT  16.513 49.896 17.1 49.968 ;
     RECT  16.513 49.968 17.088 49.992 ;
     RECT  16.513 49.992 17.1 50.064 ;
     RECT  16.513 50.064 17.088 50.088 ;
     RECT  16.513 50.088 17.1 50.16 ;
     RECT  16.513 50.16 17.088 50.184 ;
     RECT  16.513 50.184 17.1 50.256 ;
     RECT  16.513 50.256 17.088 50.28 ;
     RECT  16.513 50.28 17.1 50.352 ;
     RECT  16.513 50.352 17.088 50.376 ;
     RECT  16.513 50.376 17.1 50.496 ;
     RECT  16.513 50.496 17.088 50.52 ;
     RECT  16.513 50.52 17.1 50.592 ;
     RECT  16.513 50.592 17.088 50.616 ;
     RECT  16.513 50.616 17.1 50.688 ;
     RECT  16.513 50.688 17.088 50.712 ;
     RECT  16.513 50.712 17.1 50.784 ;
     RECT  16.513 50.784 17.088 50.808 ;
     RECT  16.513 50.808 17.1 50.88 ;
     RECT  16.513 50.88 17.088 50.904 ;
     RECT  16.513 50.904 17.1 50.976 ;
     RECT  16.513 50.976 17.088 51 ;
     RECT  16.513 51 17.1 51.12 ;
     RECT  16.513 51.12 17.088 51.144 ;
     RECT  16.513 51.144 17.1 51.216 ;
     RECT  16.513 51.216 17.088 51.24 ;
     RECT  16.513 51.24 17.1 51.312 ;
     RECT  16.513 51.312 17.088 51.336 ;
     RECT  16.513 51.336 17.1 51.408 ;
     RECT  16.513 51.408 17.088 51.432 ;
     RECT  16.513 51.432 17.1 51.504 ;
     RECT  16.513 51.504 17.088 51.528 ;
     RECT  16.513 51.528 17.1 51.6 ;
     RECT  16.513 51.6 17.088 51.624 ;
     RECT  16.513 51.624 17.1 51.744 ;
     RECT  16.513 51.744 17.088 51.768 ;
     RECT  16.513 51.768 17.1 51.84 ;
     RECT  16.513 51.84 17.088 51.864 ;
     RECT  16.513 51.864 17.1 51.936 ;
     RECT  16.513 51.936 17.088 51.96 ;
     RECT  16.513 51.96 17.1 52.032 ;
     RECT  16.513 52.032 17.088 52.056 ;
     RECT  16.513 52.056 17.1 52.128 ;
     RECT  16.513 52.128 17.088 52.152 ;
     RECT  16.513 52.152 17.1 52.224 ;
     RECT  16.513 52.224 17.088 52.248 ;
     RECT  16.513 52.248 17.1 52.368 ;
     RECT  16.513 52.368 17.088 52.392 ;
     RECT  16.513 52.392 17.1 52.464 ;
     RECT  16.513 52.464 17.088 52.488 ;
     RECT  16.513 52.488 17.1 52.56 ;
     RECT  16.513 52.56 17.088 52.584 ;
     RECT  16.513 52.584 17.1 52.656 ;
     RECT  16.513 52.656 17.088 52.68 ;
     RECT  16.513 52.68 17.1 52.752 ;
     RECT  16.513 52.752 17.088 52.776 ;
     RECT  16.513 52.776 17.1 52.848 ;
     RECT  16.513 52.848 17.088 52.872 ;
     RECT  16.513 52.872 17.1 52.992 ;
     RECT  16.513 52.992 17.088 53.016 ;
     RECT  16.513 53.016 17.1 53.088 ;
     RECT  16.513 53.088 17.088 53.112 ;
     RECT  16.513 53.112 17.1 53.184 ;
     RECT  16.513 53.184 17.088 53.208 ;
     RECT  16.513 53.208 17.1 53.28 ;
     RECT  16.513 53.28 17.088 53.304 ;
     RECT  16.513 53.304 17.1 53.376 ;
     RECT  16.513 53.376 17.088 53.4 ;
     RECT  16.513 53.4 17.1 53.472 ;
     RECT  16.513 53.472 17.088 53.496 ;
     RECT  16.513 53.496 17.1 53.568 ;
     RECT  16.513 53.568 17.088 53.592 ;
     RECT  16.513 53.592 17.1 53.712 ;
     RECT  16.513 53.712 17.088 53.736 ;
     RECT  16.513 53.736 17.1 53.808 ;
     RECT  16.513 53.808 17.088 53.832 ;
     RECT  16.513 53.832 17.1 53.904 ;
     RECT  16.513 53.904 17.088 53.928 ;
     RECT  16.513 53.928 17.1 54 ;
     RECT  16.513 54 17.088 54.024 ;
     RECT  16.513 54.024 17.1 54.096 ;
     RECT  16.513 54.096 17.088 54.12 ;
     RECT  16.513 54.12 17.1 54.192 ;
     RECT  16.513 54.192 17.088 54.216 ;
     RECT  16.513 54.216 17.1 54.336 ;
     RECT  16.513 54.336 17.088 54.36 ;
     RECT  16.513 54.36 17.1 54.432 ;
     RECT  16.513 54.432 17.088 54.456 ;
     RECT  16.513 54.456 17.1 54.528 ;
     RECT  16.513 54.528 17.088 54.552 ;
     RECT  16.513 54.552 17.1 54.624 ;
     RECT  16.513 54.624 17.088 54.648 ;
     RECT  16.513 54.648 17.1 54.72 ;
     RECT  16.513 54.72 17.088 54.744 ;
     RECT  16.513 54.744 17.1 54.816 ;
     RECT  16.513 54.816 17.088 54.84 ;
     RECT  16.513 54.84 17.1 54.96 ;
     RECT  16.513 54.96 17.088 54.984 ;
     RECT  16.513 54.984 17.1 55.056 ;
     RECT  16.513 55.056 17.088 55.08 ;
     RECT  16.513 55.08 17.1 55.152 ;
     RECT  16.513 55.152 17.088 55.176 ;
     RECT  16.513 55.176 17.1 55.248 ;
     RECT  16.513 55.248 17.088 55.272 ;
     RECT  16.513 55.272 17.1 55.344 ;
     RECT  16.513 55.344 17.088 55.368 ;
     RECT  16.513 55.368 17.1 55.44 ;
     RECT  16.513 55.44 17.088 55.464 ;
     RECT  16.513 55.464 17.1 55.584 ;
     RECT  16.513 55.584 17.088 55.608 ;
     RECT  16.513 55.608 17.1 55.68 ;
     RECT  16.513 55.68 17.088 55.704 ;
     RECT  16.513 55.704 17.1 55.776 ;
     RECT  16.513 55.776 17.088 55.8 ;
     RECT  16.513 55.8 17.1 55.872 ;
     RECT  16.513 55.872 17.088 55.896 ;
     RECT  16.513 55.896 17.1 55.968 ;
     RECT  16.513 55.968 17.088 55.992 ;
     RECT  16.513 55.992 17.1 56.064 ;
     RECT  16.513 56.064 17.088 56.088 ;
     RECT  16.513 56.088 17.1 56.208 ;
     RECT  16.513 56.208 17.088 56.232 ;
     RECT  16.513 56.232 17.1 56.304 ;
     RECT  16.513 56.304 17.088 56.328 ;
     RECT  16.513 56.328 17.1 56.4 ;
     RECT  16.513 56.4 17.088 56.424 ;
     RECT  16.513 56.424 17.1 56.496 ;
     RECT  16.513 56.496 17.088 56.52 ;
     RECT  16.513 56.52 17.1 56.592 ;
     RECT  16.513 56.592 17.088 56.616 ;
     RECT  16.513 56.616 17.1 56.688 ;
     RECT  16.513 56.688 17.088 56.712 ;
     RECT  16.513 56.712 17.1 56.832 ;
     RECT  16.513 56.832 17.088 56.856 ;
     RECT  16.513 56.856 17.1 56.928 ;
     RECT  16.513 56.928 17.088 56.952 ;
     RECT  16.513 56.952 17.1 57.024 ;
     RECT  16.513 57.024 17.088 57.048 ;
     RECT  16.513 57.048 17.1 57.12 ;
     RECT  16.513 57.12 17.088 57.144 ;
     RECT  16.513 57.144 17.1 57.216 ;
     RECT  16.513 57.216 17.088 57.24 ;
     RECT  16.513 57.24 17.1 57.312 ;
     RECT  16.513 57.312 17.088 57.336 ;
     RECT  16.513 57.336 17.1 57.408 ;
     RECT  16.513 57.408 17.088 57.432 ;
     RECT  16.513 57.432 17.1 57.552 ;
     RECT  16.513 57.552 17.088 57.576 ;
     RECT  16.513 57.576 17.1 57.648 ;
     RECT  16.513 57.648 17.088 57.672 ;
     RECT  16.513 57.672 17.1 57.744 ;
     RECT  16.513 57.744 17.088 57.768 ;
     RECT  16.513 57.768 17.1 57.84 ;
     RECT  16.513 57.84 17.088 57.864 ;
     RECT  16.513 57.864 17.1 57.936 ;
     RECT  16.513 57.936 17.088 57.96 ;
     RECT  16.513 57.96 17.1 58.032 ;
     RECT  16.513 58.032 17.088 58.056 ;
     RECT  16.513 58.056 17.1 58.176 ;
     RECT  16.513 58.176 17.088 58.2 ;
     RECT  16.513 58.2 17.1 58.272 ;
     RECT  16.513 58.272 17.088 58.296 ;
     RECT  16.513 58.296 17.1 58.368 ;
     RECT  16.513 58.368 17.088 58.392 ;
     RECT  16.513 58.392 17.1 58.464 ;
     RECT  16.513 58.464 17.088 58.488 ;
     RECT  16.513 58.488 17.1 58.56 ;
     RECT  16.513 58.56 17.088 58.584 ;
     RECT  16.513 58.584 17.1 58.656 ;
     RECT  16.513 58.656 17.088 58.68 ;
     RECT  16.513 58.68 17.1 58.8 ;
     RECT  16.513 58.8 17.088 58.824 ;
     RECT  16.513 58.824 17.1 58.896 ;
     RECT  16.513 58.896 17.088 58.92 ;
     RECT  16.513 58.92 17.1 58.992 ;
     RECT  16.513 58.992 17.088 59.016 ;
     RECT  16.513 59.016 17.1 59.088 ;
     RECT  16.513 59.088 17.088 59.112 ;
     RECT  16.513 59.112 17.1 59.184 ;
     RECT  16.513 59.184 17.088 59.208 ;
     RECT  16.513 59.208 17.1 59.28 ;
     RECT  16.513 59.28 17.088 59.304 ;
     RECT  16.513 59.304 17.1 59.424 ;
     RECT  16.513 59.424 17.088 59.448 ;
     RECT  16.513 59.448 17.1 59.52 ;
     RECT  16.513 59.52 17.088 59.544 ;
     RECT  16.513 59.544 17.1 59.616 ;
     RECT  16.513 59.616 17.088 59.64 ;
     RECT  16.513 59.64 17.1 59.712 ;
     RECT  16.513 59.712 17.088 59.736 ;
     RECT  16.513 59.736 17.1 59.808 ;
     RECT  16.513 59.808 17.088 59.832 ;
     RECT  16.513 59.832 17.1 59.904 ;
     RECT  16.513 59.904 17.088 59.928 ;
     RECT  16.513 59.928 17.1 60.048 ;
     RECT  16.513 60.048 17.088 60.072 ;
     RECT  16.513 60.072 17.1 60.144 ;
     RECT  16.513 60.144 17.088 60.168 ;
     RECT  16.513 60.168 17.1 60.24 ;
     RECT  16.513 60.24 17.088 60.264 ;
     RECT  16.513 60.264 17.1 60.336 ;
     RECT  16.513 60.336 17.088 60.36 ;
     RECT  16.513 60.36 17.1 60.432 ;
     RECT  16.513 60.432 17.088 60.456 ;
     RECT  17.1 2.784 17.165 2.832 ;
     RECT  17.1 2.856 17.165 2.928 ;
     RECT  17.1 2.952 17.165 3.072 ;
     RECT  17.1 3.096 17.165 3.168 ;
     RECT  17.1 3.192 17.165 3.264 ;
     RECT  17.1 3.288 17.165 3.336 ;
     RECT  17.1 4.896 17.165 4.944 ;
     RECT  17.1 4.968 17.165 5.04 ;
     RECT  17.1 5.064 17.165 5.136 ;
     RECT  17.1 5.16 17.165 5.232 ;
     RECT  17.1 5.256 17.165 5.328 ;
     RECT  17.1 5.352 17.165 5.424 ;
     RECT  17.1 5.448 17.165 5.568 ;
     RECT  17.1 5.592 17.165 5.664 ;
     RECT  17.1 5.688 17.165 5.76 ;
     RECT  17.1 5.784 17.165 5.856 ;
     RECT  17.1 5.88 17.165 5.952 ;
     RECT  17.1 5.976 17.165 6.048 ;
     RECT  17.1 6.072 17.165 6.12 ;
     RECT  17.1 7.68 17.165 7.704 ;
     RECT  17.1 11.424 17.165 11.472 ;
     RECT  17.1 11.496 17.165 11.568 ;
     RECT  17.1 11.592 17.165 11.664 ;
     RECT  17.1 11.688 17.165 11.76 ;
     RECT  17.1 11.784 17.165 11.856 ;
     RECT  17.1 11.88 17.165 12 ;
     RECT  17.1 12.024 17.165 12.096 ;
     RECT  17.1 12.12 17.165 12.192 ;
     RECT  17.1 12.216 17.165 12.288 ;
     RECT  17.1 12.312 17.165 12.36 ;
     RECT  17.1 13.584 17.165 13.632 ;
     RECT  17.1 13.656 17.165 13.728 ;
     RECT  17.1 13.752 17.165 13.824 ;
     RECT  17.1 13.848 17.165 13.968 ;
     RECT  17.1 13.992 17.165 14.064 ;
     RECT  17.1 14.088 17.165 14.136 ;
     RECT  17.1 15.984 17.165 16.032 ;
     RECT  17.1 16.056 17.165 16.128 ;
     RECT  17.1 16.152 17.165 16.224 ;
     RECT  17.1 16.248 17.165 16.32 ;
     RECT  17.1 16.344 17.165 16.464 ;
     RECT  17.1 16.488 17.165 16.56 ;
     RECT  17.1 16.584 17.165 16.656 ;
     RECT  17.1 16.68 17.165 16.752 ;
     RECT  17.1 16.776 17.165 16.848 ;
     RECT  17.1 16.872 17.165 16.92 ;
     RECT  17.1 19.008 17.165 19.032 ;
     RECT  17.1 20.64 17.165 20.688 ;
     RECT  17.1 20.712 17.165 20.784 ;
     RECT  17.1 20.808 17.165 20.88 ;
     RECT  17.1 20.904 17.165 21.024 ;
     RECT  17.1 21.048 17.165 21.12 ;
     RECT  17.1 21.144 17.165 21.216 ;
     RECT  17.1 21.24 17.165 21.312 ;
     RECT  17.1 21.336 17.165 21.408 ;
     RECT  17.1 21.432 17.165 21.504 ;
     RECT  17.1 21.528 17.165 21.648 ;
     RECT  17.1 21.672 17.165 21.744 ;
     RECT  17.1 21.768 17.165 21.84 ;
     RECT  17.1 21.864 17.165 21.912 ;
     RECT  17.1 23.856 17.165 23.904 ;
     RECT  17.1 23.928 17.165 24 ;
     RECT  17.1 24.024 17.165 24.096 ;
     RECT  17.1 24.12 17.165 24.24 ;
     RECT  17.1 24.264 17.165 24.336 ;
     RECT  17.1 24.36 17.165 24.408 ;
     RECT  17.1 26.016 17.165 26.04 ;
     RECT  17.1 29.856 17.165 29.88 ;
     RECT  17.1 32.256 17.165 32.304 ;
     RECT  17.1 32.328 17.165 32.4 ;
     RECT  17.1 32.424 17.165 32.544 ;
     RECT  17.1 32.568 17.165 32.64 ;
     RECT  17.1 32.664 17.165 32.736 ;
     RECT  17.1 32.76 17.165 32.832 ;
     RECT  17.1 32.856 17.165 32.928 ;
     RECT  17.1 32.952 17.165 33.024 ;
     RECT  17.1 33.048 17.165 33.096 ;
     RECT  17.1 40.56 17.165 40.584 ;
     RECT  17.1 43.392 17.165 43.416 ;
     RECT  17.1 48.432 17.165 48.456 ;
     RECT  17.1 55.536 17.165 55.56 ;
     RECT  17.1 57.984 17.165 58.032 ;
     RECT  17.1 58.056 17.165 58.176 ;
     RECT  17.1 58.2 17.165 58.272 ;
     RECT  17.1 58.296 17.165 58.368 ;
     RECT  17.1 58.392 17.165 58.464 ;
     RECT  17.1 58.488 17.165 58.56 ;
     RECT  17.1 58.584 17.165 58.656 ;
     RECT  17.1 58.68 17.165 58.8 ;
     RECT  17.1 58.824 17.165 58.896 ;
     RECT  17.1 58.92 17.165 58.968 ;
    LAYER M5 ;
     RECT  2.4 2.137 2.52 2.151 ;
     RECT  5.1 2.137 5.22 2.151 ;
     RECT  7.8 2.137 7.92 2.151 ;
     RECT  10.5 2.137 10.62 2.151 ;
     RECT  13.2 2.137 13.32 2.151 ;
     RECT  9.12 2.293 9.144 2.483 ;
     RECT  2.4 2.151 2.712 2.725 ;
     RECT  2.4 2.725 2.904 2.867 ;
     RECT  7.8 2.151 8.112 3.301 ;
     RECT  10.5 2.151 10.812 3.589 ;
     RECT  10.5 3.589 11.208 3.685 ;
     RECT  10.5 3.685 11.304 3.923 ;
     RECT  7.68 3.301 8.112 3.925 ;
     RECT  3.936 3.829 3.96 3.971 ;
     RECT  13.2 2.151 13.512 4.117 ;
     RECT  13.2 4.117 13.944 4.405 ;
     RECT  13.2 4.405 14.856 4.499 ;
     RECT  14.832 4.499 14.856 4.547 ;
     RECT  10.5 3.923 10.812 5.029 ;
     RECT  9.12 4.021 9.144 5.123 ;
     RECT  6.864 3.925 8.112 5.701 ;
     RECT  6.864 5.701 8.424 5.891 ;
     RECT  10.368 5.029 10.812 6.085 ;
     RECT  9.216 6.085 10.812 6.563 ;
     RECT  6.864 5.891 8.112 6.803 ;
     RECT  9.312 6.563 10.812 7.091 ;
     RECT  2.4 2.867 2.712 7.477 ;
     RECT  2.304 7.477 2.712 7.715 ;
     RECT  9.888 7.091 10.812 8.147 ;
     RECT  7.152 6.803 8.112 8.293 ;
     RECT  6.624 8.293 8.112 8.339 ;
     RECT  7.8 8.339 8.112 8.341 ;
     RECT  7.8 8.341 9.144 9.587 ;
     RECT  13.2 4.499 13.512 9.877 ;
     RECT  14.832 9.829 14.856 9.877 ;
     RECT  13.2 9.877 14.856 10.163 ;
     RECT  14.832 10.163 14.856 10.499 ;
     RECT  7.8 9.587 8.568 10.933 ;
     RECT  10.5 8.147 10.812 11.173 ;
     RECT  7.8 10.933 9.144 11.459 ;
     RECT  10.176 11.173 10.812 12.131 ;
     RECT  7.8 11.459 8.568 12.469 ;
     RECT  6.624 8.339 6.648 12.515 ;
     RECT  2.4 7.715 2.712 12.853 ;
     RECT  2.304 12.853 2.712 13.043 ;
     RECT  7.68 12.469 8.568 13.811 ;
     RECT  7.8 13.811 8.568 14.533 ;
     RECT  1.056 14.389 1.08 14.579 ;
     RECT  7.8 14.533 9.144 14.581 ;
     RECT  10.368 12.131 10.812 14.581 ;
     RECT  7.8 14.581 10.812 14.723 ;
     RECT  14.832 14.389 14.856 15.347 ;
     RECT  9.6 14.723 10.812 15.443 ;
     RECT  5.1 2.151 5.412 16.117 ;
     RECT  6.624 14.389 6.648 16.117 ;
     RECT  5.1 16.117 6.648 16.163 ;
     RECT  7.8 14.723 8.568 16.453 ;
     RECT  16.512 16.549 16.536 16.739 ;
     RECT  10.5 15.443 10.812 17.125 ;
     RECT  14.832 17.413 14.856 17.555 ;
     RECT  7.8 16.453 9.096 17.891 ;
     RECT  7.8 17.891 8.76 17.939 ;
     RECT  1.152 17.797 1.176 17.987 ;
     RECT  7.8 17.939 8.28 18.371 ;
     RECT  10.368 17.125 10.812 18.613 ;
     RECT  10.128 18.613 10.812 19.381 ;
     RECT  9.264 19.381 10.812 19.429 ;
     RECT  9.12 19.429 10.812 19.477 ;
     RECT  9.12 19.477 11.016 19.571 ;
     RECT  10.128 19.571 11.016 19.813 ;
     RECT  9.12 19.571 9.144 19.907 ;
     RECT  14.832 19.765 14.856 19.907 ;
     RECT  10.128 19.813 11.16 19.955 ;
     RECT  7.8 18.371 8.112 20.245 ;
     RECT  7.8 20.245 9.096 20.531 ;
     RECT  10.128 19.955 11.016 21.347 ;
     RECT  7.8 20.531 8.808 21.493 ;
     RECT  7.8 21.493 8.904 21.589 ;
     RECT  7.8 21.589 9 21.733 ;
     RECT  5.1 16.163 6.456 21.779 ;
     RECT  7.68 21.733 9 21.781 ;
     RECT  13.2 10.163 13.512 21.877 ;
     RECT  13.2 21.877 13.608 22.019 ;
     RECT  7.68 21.781 9.096 22.259 ;
     RECT  7.8 22.259 9.096 22.403 ;
     RECT  9.12 22.597 9.144 23.123 ;
     RECT  10.128 21.347 10.812 23.365 ;
     RECT  13.2 22.019 13.512 23.413 ;
     RECT  12.768 23.413 13.512 23.603 ;
     RECT  10.128 23.365 11.784 23.699 ;
     RECT  1.152 24.133 1.176 24.419 ;
     RECT  9.12 24.229 9.144 24.419 ;
     RECT  14.928 24.709 14.952 24.899 ;
     RECT  7.8 22.403 8.112 25.285 ;
     RECT  7.8 25.285 9.048 25.477 ;
     RECT  7.68 25.477 9.048 25.619 ;
     RECT  5.1 21.779 6.36 26.101 ;
     RECT  5.1 26.101 6.648 26.147 ;
     RECT  10.128 23.699 10.812 27.349 ;
     RECT  10.128 27.349 11.784 27.683 ;
     RECT  14.832 26.101 14.856 28.163 ;
     RECT  0.192 28.261 0.216 28.451 ;
     RECT  7.8 25.619 9.048 28.741 ;
     RECT  10.128 27.683 10.812 28.741 ;
     RECT  7.8 28.741 10.812 29.219 ;
     RECT  1.152 29.413 1.176 29.603 ;
     RECT  5.1 26.147 5.412 30.133 ;
     RECT  10.128 29.219 10.812 30.179 ;
     RECT  7.8 29.219 9.096 30.277 ;
     RECT  16.992 30.757 17.016 30.947 ;
     RECT  6.624 26.147 6.648 31.621 ;
     RECT  7.8 30.277 9.192 31.621 ;
     RECT  10.224 30.179 10.812 32.005 ;
     RECT  10.224 32.005 11.592 32.339 ;
     RECT  6.624 31.621 9.192 32.915 ;
     RECT  7.632 32.915 9.192 32.917 ;
     RECT  10.224 32.339 10.812 32.917 ;
     RECT  7.632 32.917 10.812 33.011 ;
     RECT  13.2 23.603 13.512 33.013 ;
     RECT  6.624 32.915 6.648 33.107 ;
     RECT  7.632 33.011 8.112 33.203 ;
     RECT  9.12 33.011 10.812 33.443 ;
     RECT  12.528 33.013 13.512 33.731 ;
     RECT  9.12 33.443 9.144 33.923 ;
     RECT  14.832 33.397 14.856 34.595 ;
     RECT  7.68 33.203 8.112 34.691 ;
     RECT  16.56 34.549 16.584 34.739 ;
     RECT  13.2 33.731 13.512 34.981 ;
     RECT  13.2 34.981 13.944 35.267 ;
     RECT  12.048 35.173 12.072 35.315 ;
     RECT  7.8 34.691 8.112 35.557 ;
     RECT  3.936 35.509 3.96 35.747 ;
     RECT  7.8 35.557 8.232 35.749 ;
     RECT  14.832 35.989 14.856 36.179 ;
     RECT  7.8 35.749 8.616 36.227 ;
     RECT  10.224 33.443 10.812 36.469 ;
     RECT  10.224 36.469 11.352 36.517 ;
     RECT  13.2 35.267 13.512 36.565 ;
     RECT  10.128 36.517 11.352 36.659 ;
     RECT  13.2 36.565 13.944 36.899 ;
     RECT  7.8 36.227 8.232 36.995 ;
     RECT  6.624 34.453 6.648 37.139 ;
     RECT  13.2 36.899 13.608 37.139 ;
     RECT  14.832 37.333 14.856 37.475 ;
     RECT  10.128 36.659 10.812 37.813 ;
     RECT  13.2 37.139 13.512 38.005 ;
     RECT  2.4 13.043 2.712 38.437 ;
     RECT  2.4 38.437 2.808 38.579 ;
     RECT  0.288 38.533 0.312 38.723 ;
     RECT  12.528 38.005 13.512 38.771 ;
     RECT  7.8 36.995 8.112 38.821 ;
     RECT  9.648 37.813 10.812 38.821 ;
     RECT  7.8 38.821 10.812 41.123 ;
     RECT  13.2 38.771 13.512 41.221 ;
     RECT  13.2 41.221 13.608 41.363 ;
     RECT  7.8 41.123 8.52 41.653 ;
     RECT  7.68 41.653 8.52 42.131 ;
     RECT  12.048 41.989 12.072 42.179 ;
     RECT  7.8 42.131 8.52 42.421 ;
     RECT  9.648 41.123 10.812 42.421 ;
     RECT  7.8 42.421 10.812 42.467 ;
     RECT  13.2 41.363 13.512 42.469 ;
     RECT  14.832 42.565 14.856 42.707 ;
     RECT  9.12 42.467 10.812 42.803 ;
     RECT  3.936 42.997 3.96 43.139 ;
     RECT  9.648 42.803 10.812 43.285 ;
     RECT  12.528 42.469 13.512 43.955 ;
     RECT  9.648 43.285 11.4 44.533 ;
     RECT  9.12 44.533 11.4 44.867 ;
     RECT  1.152 44.869 1.176 45.011 ;
     RECT  7.8 42.467 8.112 45.109 ;
     RECT  9.12 44.867 10.812 45.109 ;
     RECT  7.8 45.109 10.812 45.155 ;
     RECT  7.8 45.155 9.48 45.347 ;
     RECT  2.4 38.579 2.712 45.541 ;
     RECT  7.8 45.347 9.384 45.683 ;
     RECT  2.256 45.541 2.712 45.731 ;
     RECT  7.8 45.683 8.808 46.741 ;
     RECT  7.8 46.741 9.336 46.883 ;
     RECT  6.72 43.381 6.744 46.933 ;
     RECT  7.8 46.883 9.144 46.933 ;
     RECT  13.2 43.955 13.512 47.125 ;
     RECT  12.048 45.973 12.072 47.171 ;
     RECT  13.104 47.125 13.512 47.267 ;
     RECT  6.72 46.933 9.144 47.315 ;
     RECT  6.72 47.315 6.744 48.421 ;
     RECT  7.8 47.315 9.144 48.421 ;
     RECT  6.72 48.421 9.144 48.469 ;
     RECT  3.936 48.661 3.96 48.803 ;
     RECT  6.72 48.469 9.336 48.949 ;
     RECT  6.672 48.949 9.336 48.997 ;
     RECT  6.672 48.997 9.432 49.523 ;
     RECT  6.672 49.523 9.096 49.763 ;
     RECT  10.5 45.155 10.812 49.861 ;
     RECT  10.5 49.861 11.592 50.053 ;
     RECT  13.2 47.267 13.512 50.053 ;
     RECT  10.5 50.053 13.512 50.099 ;
     RECT  6.672 49.763 8.808 50.771 ;
     RECT  12.528 50.099 13.512 53.075 ;
     RECT  6.816 50.771 8.808 53.557 ;
     RECT  12.912 53.075 13.512 53.939 ;
     RECT  6.816 53.557 9.48 54.035 ;
     RECT  6.816 54.035 9.384 54.131 ;
     RECT  10.5 50.099 10.812 54.181 ;
     RECT  10.5 54.181 11.496 54.323 ;
     RECT  10.5 54.323 10.812 55.093 ;
     RECT  6.816 54.131 8.232 55.139 ;
     RECT  10.368 55.093 10.812 55.189 ;
     RECT  7.8 55.139 8.232 55.763 ;
     RECT  9.936 55.189 10.812 55.813 ;
     RECT  14.832 54.421 14.856 55.907 ;
     RECT  7.8 55.763 8.112 56.341 ;
     RECT  9.36 55.813 10.812 56.675 ;
     RECT  9.36 56.675 9.384 57.107 ;
     RECT  7.68 56.341 8.112 57.541 ;
     RECT  7.68 57.541 8.952 57.779 ;
     RECT  5.1 30.133 5.592 58.117 ;
     RECT  7.68 57.779 8.112 58.643 ;
     RECT  9.12 58.549 9.144 58.645 ;
     RECT  10.5 56.675 10.812 58.645 ;
     RECT  2.4 45.731 2.712 58.933 ;
     RECT  2.304 58.933 2.712 59.507 ;
     RECT  9.12 58.645 10.812 59.507 ;
     RECT  7.8 58.643 8.112 59.701 ;
     RECT  10.5 59.507 10.812 60.037 ;
     RECT  7.8 59.701 8.904 60.179 ;
     RECT  5.1 58.117 6.408 60.323 ;
     RECT  10.5 60.037 11.496 60.419 ;
     RECT  0.288 60.277 0.312 60.467 ;
     RECT  2.4 59.507 2.712 60.489 ;
     RECT  7.8 60.179 8.112 60.489 ;
     RECT  10.5 60.419 10.812 60.489 ;
     RECT  13.2 53.939 13.512 60.489 ;
     RECT  2.4 60.489 2.52 60.503 ;
     RECT  5.1 60.323 5.592 60.503 ;
     RECT  7.8 60.489 7.92 60.503 ;
     RECT  10.5 60.489 10.62 60.503 ;
     RECT  13.2 60.489 13.32 60.503 ;
     RECT  5.568 60.503 5.592 61.619 ;
     RECT  8.112 2.293 9.12 2.483 ;
     RECT  9.144 2.293 10.5 2.483 ;
     RECT  2.712 2.867 2.904 3.829 ;
     RECT  2.712 3.829 3.936 3.971 ;
     RECT  3.96 3.829 5.1 3.971 ;
     RECT  5.412 3.925 6.864 6.803 ;
     RECT  8.112 4.021 9.12 5.123 ;
     RECT  9.144 4.021 10.5 5.029 ;
     RECT  13.512 4.499 14.832 4.547 ;
     RECT  9.144 5.029 10.368 5.123 ;
     RECT  8.112 5.123 10.368 5.701 ;
     RECT  8.424 5.701 10.368 5.891 ;
     RECT  8.112 5.891 10.368 6.085 ;
     RECT  8.112 6.085 9.216 6.563 ;
     RECT  8.112 6.563 9.312 7.091 ;
     RECT  5.412 6.803 7.152 8.293 ;
     RECT  8.112 7.091 9.888 8.147 ;
     RECT  8.112 8.147 10.5 8.341 ;
     RECT  5.412 8.293 6.624 12.515 ;
     RECT  6.648 8.339 7.8 12.469 ;
     RECT  9.144 8.341 10.5 9.587 ;
     RECT  8.568 9.587 10.5 10.933 ;
     RECT  13.512 9.829 14.832 9.877 ;
     RECT  13.512 10.163 14.832 10.499 ;
     RECT  9.144 10.933 10.5 11.173 ;
     RECT  9.144 11.173 10.176 11.459 ;
     RECT  6.648 12.469 7.68 12.515 ;
     RECT  2.304 13.043 2.4 14.389 ;
     RECT  7.68 13.811 7.8 14.389 ;
     RECT  1.08 14.389 2.4 14.579 ;
     RECT  5.412 14.389 6.624 16.117 ;
     RECT  6.648 14.389 7.8 16.163 ;
     RECT  13.512 14.389 14.832 15.347 ;
     RECT  9.144 14.533 10.368 14.581 ;
     RECT  8.568 14.723 9.6 15.443 ;
     RECT  8.568 15.443 10.5 16.453 ;
     RECT  6.456 16.163 7.8 21.733 ;
     RECT  9.096 16.453 10.5 17.125 ;
     RECT  9.096 17.125 10.368 17.891 ;
     RECT  13.512 17.413 14.832 17.555 ;
     RECT  1.176 17.797 2.4 17.987 ;
     RECT  8.76 17.891 10.368 17.939 ;
     RECT  8.28 17.939 10.368 18.371 ;
     RECT  8.112 18.371 10.368 18.613 ;
     RECT  8.112 18.613 10.128 19.381 ;
     RECT  8.112 19.381 9.264 19.429 ;
     RECT  8.112 19.429 9.12 19.907 ;
     RECT  9.144 19.571 10.128 19.907 ;
     RECT  13.512 19.765 14.832 19.907 ;
     RECT  8.112 19.907 10.128 20.245 ;
     RECT  9.096 20.245 10.128 20.531 ;
     RECT  8.808 20.531 10.128 21.493 ;
     RECT  8.904 21.493 10.128 21.589 ;
     RECT  9 21.589 10.128 21.781 ;
     RECT  6.456 21.733 7.68 21.779 ;
     RECT  6.36 21.779 7.68 22.259 ;
     RECT  9.096 21.781 10.128 22.403 ;
     RECT  6.36 22.259 7.8 25.477 ;
     RECT  8.112 22.403 10.128 22.597 ;
     RECT  8.112 22.597 9.12 23.123 ;
     RECT  9.144 22.597 10.128 23.123 ;
     RECT  8.112 23.123 10.128 24.229 ;
     RECT  11.784 23.365 13.2 23.413 ;
     RECT  11.784 23.413 12.768 23.603 ;
     RECT  11.784 23.603 13.2 23.699 ;
     RECT  1.176 24.133 2.4 24.419 ;
     RECT  8.112 24.229 9.12 24.419 ;
     RECT  9.144 24.229 10.128 24.419 ;
     RECT  8.112 24.419 10.128 25.285 ;
     RECT  13.512 24.709 14.928 24.899 ;
     RECT  13.512 24.899 14.856 26.101 ;
     RECT  9.048 25.285 10.128 28.741 ;
     RECT  6.36 25.477 7.68 25.619 ;
     RECT  6.36 25.619 7.8 26.101 ;
     RECT  6.648 26.101 7.8 31.621 ;
     RECT  13.512 26.101 14.832 28.163 ;
     RECT  5.412 26.147 6.624 30.133 ;
     RECT  11.784 27.349 13.2 27.683 ;
     RECT  9.096 29.219 10.128 30.179 ;
     RECT  1.176 29.413 2.4 29.603 ;
     RECT  5.592 30.133 6.624 33.107 ;
     RECT  9.096 30.179 10.224 30.277 ;
     RECT  9.192 30.277 10.224 32.917 ;
     RECT  6.648 32.915 7.632 33.107 ;
     RECT  8.112 33.011 9.12 33.923 ;
     RECT  5.592 33.107 7.632 33.203 ;
     RECT  5.592 33.203 7.68 34.453 ;
     RECT  13.512 33.397 14.832 34.595 ;
     RECT  9.144 33.443 10.224 33.923 ;
     RECT  12.528 33.731 13.2 35.173 ;
     RECT  5.592 34.453 6.624 37.139 ;
     RECT  6.648 34.453 7.68 34.691 ;
     RECT  13.512 34.595 14.856 34.981 ;
     RECT  6.648 34.691 7.8 37.139 ;
     RECT  13.944 34.981 14.856 35.267 ;
     RECT  10.812 35.173 12.048 35.315 ;
     RECT  12.072 35.173 13.2 35.315 ;
     RECT  13.512 35.267 14.856 35.989 ;
     RECT  10.812 35.315 11.352 36.469 ;
     RECT  2.712 35.509 3.936 35.747 ;
     RECT  3.96 35.509 5.1 35.747 ;
     RECT  13.512 35.989 14.832 36.179 ;
     RECT  13.512 36.179 14.856 36.565 ;
     RECT  13.944 36.565 14.856 36.899 ;
     RECT  13.608 36.899 14.856 37.139 ;
     RECT  13.512 37.139 14.856 37.333 ;
     RECT  13.512 37.333 14.832 37.475 ;
     RECT  8.52 41.123 9.648 42.421 ;
     RECT  13.512 41.363 13.608 42.565 ;
     RECT  10.812 41.989 12.048 42.179 ;
     RECT  12.072 41.989 13.2 42.179 ;
     RECT  7.68 42.131 7.8 43.381 ;
     RECT  10.812 42.179 13.2 42.469 ;
     RECT  8.112 42.467 9.12 42.803 ;
     RECT  10.812 42.469 12.528 43.285 ;
     RECT  13.512 42.565 14.832 42.707 ;
     RECT  2.712 42.997 3.936 43.139 ;
     RECT  3.96 42.997 5.1 43.139 ;
     RECT  11.4 43.285 12.528 43.955 ;
     RECT  5.592 43.381 6.72 48.949 ;
     RECT  6.744 43.381 7.8 46.933 ;
     RECT  8.112 44.533 9.12 45.109 ;
     RECT  10.812 44.867 11.4 45.973 ;
     RECT  1.176 44.869 2.4 45.011 ;
     RECT  2.256 45.011 2.4 45.541 ;
     RECT  9.48 45.155 10.5 45.347 ;
     RECT  9.384 45.347 10.5 45.683 ;
     RECT  8.808 45.683 10.5 46.741 ;
     RECT  10.812 45.973 12.048 47.171 ;
     RECT  12.072 45.973 13.2 47.125 ;
     RECT  9.336 46.741 10.5 46.883 ;
     RECT  9.144 46.883 10.5 48.469 ;
     RECT  12.072 47.125 13.104 47.171 ;
     RECT  6.744 47.315 7.8 48.421 ;
     RECT  9.336 48.469 10.5 48.997 ;
     RECT  2.712 48.661 3.936 48.803 ;
     RECT  3.96 48.661 5.1 48.803 ;
     RECT  5.592 48.949 6.672 50.771 ;
     RECT  9.432 48.997 10.5 49.523 ;
     RECT  9.096 49.523 10.5 49.763 ;
     RECT  5.592 50.771 6.816 55.139 ;
     RECT  9.48 53.557 10.5 54.035 ;
     RECT  9.384 54.035 10.5 54.131 ;
     RECT  9.936 54.131 10.5 55.093 ;
     RECT  13.512 54.421 14.832 55.907 ;
     RECT  9.936 55.093 10.368 55.189 ;
     RECT  7.68 55.139 7.8 56.341 ;
     RECT  8.112 55.763 8.232 55.813 ;
     RECT  8.112 55.813 9.36 57.107 ;
     RECT  9.384 56.675 10.5 57.107 ;
     RECT  8.112 57.107 10.5 57.541 ;
     RECT  8.952 57.541 10.5 57.779 ;
     RECT  8.112 57.779 10.5 58.549 ;
     RECT  6.408 58.117 7.68 58.643 ;
     RECT  8.112 58.549 9.12 59.507 ;
     RECT  9.144 58.549 10.5 58.645 ;
     RECT  6.408 58.643 7.8 60.323 ;
     RECT  8.112 59.507 8.904 59.701 ;
  END
END dsfd_dvrlyh_562_EW
END LIBRARY
